VERSION 5.7 ;
  NOWIREEXTENSIONATPIN ON ;
  DIVIDERCHAR "/" ;
  BUSBITCHARS "[]" ;
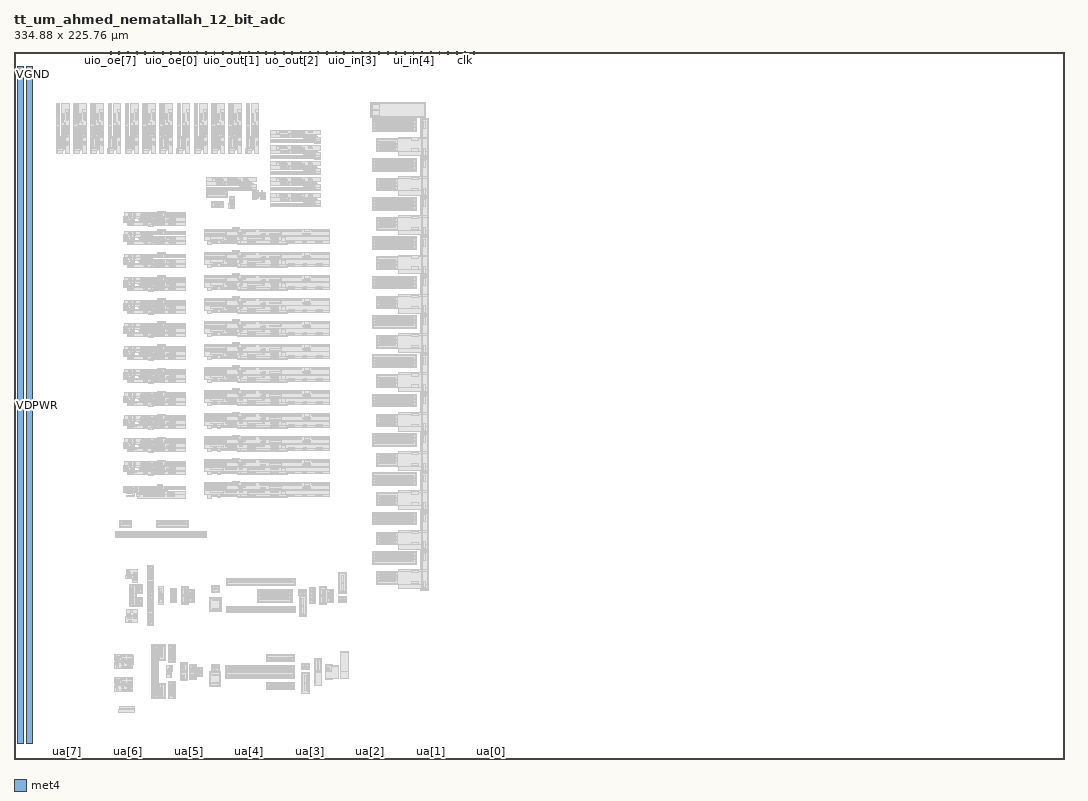
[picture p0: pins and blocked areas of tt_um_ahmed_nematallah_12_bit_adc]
MACRO tt_um_ahmed_nematallah_12_bit_adc
  CLASS BLOCK ;
  FOREIGN tt_um_ahmed_nematallah_12_bit_adc ;
  ORIGIN 0.000 0.000 ;
  SIZE 334.880 BY 225.760 ;
  PIN clk
    DIRECTION INPUT ;
    USE SIGNAL ;
    PORT
      LAYER met4 ;
        RECT 143.830 224.760 144.130 225.760 ;
    END
  END clk
  PIN ena
    DIRECTION INPUT ;
    USE SIGNAL ;
    PORT
      LAYER met4 ;
        RECT 146.590 224.760 146.890 225.760 ;
    END
  END ena
  PIN rst_n
    DIRECTION INPUT ;
    USE SIGNAL ;
    PORT
      LAYER met4 ;
        RECT 141.070 224.760 141.370 225.760 ;
    END
  END rst_n
  PIN ua[0]
    DIRECTION INOUT ;
    USE SIGNAL ;
    ANTENNAGATEAREA 0.450000 ;
    PORT
      LAYER met4 ;
        RECT 151.810 0.000 152.710 1.000 ;
    END
  END ua[0]
  PIN ua[1]
    DIRECTION INOUT ;
    USE SIGNAL ;
    PORT
      LAYER met4 ;
        RECT 132.490 0.000 133.390 1.000 ;
    END
  END ua[1]
  PIN ua[2]
    DIRECTION INOUT ;
    USE SIGNAL ;
    PORT
      LAYER met4 ;
        RECT 113.170 0.000 114.070 1.000 ;
    END
  END ua[2]
  PIN ua[3]
    DIRECTION INOUT ;
    USE SIGNAL ;
    PORT
      LAYER met4 ;
        RECT 93.850 0.000 94.750 1.000 ;
    END
  END ua[3]
  PIN ua[4]
    DIRECTION INOUT ;
    USE SIGNAL ;
    PORT
      LAYER met4 ;
        RECT 74.530 0.000 75.430 1.000 ;
    END
  END ua[4]
  PIN ua[5]
    DIRECTION INOUT ;
    USE SIGNAL ;
    PORT
      LAYER met4 ;
        RECT 55.210 0.000 56.110 1.000 ;
    END
  END ua[5]
  PIN ua[6]
    DIRECTION INOUT ;
    USE SIGNAL ;
    PORT
      LAYER met4 ;
        RECT 35.890 0.000 36.790 1.000 ;
    END
  END ua[6]
  PIN ua[7]
    DIRECTION INOUT ;
    USE SIGNAL ;
    PORT
      LAYER met4 ;
        RECT 16.570 0.000 17.470 1.000 ;
    END
  END ua[7]
  PIN ui_in[0]
    DIRECTION INPUT ;
    USE SIGNAL ;
    PORT
      LAYER met4 ;
        RECT 138.310 224.760 138.610 225.760 ;
    END
  END ui_in[0]
  PIN ui_in[1]
    DIRECTION INPUT ;
    USE SIGNAL ;
    PORT
      LAYER met4 ;
        RECT 135.550 224.760 135.850 225.760 ;
    END
  END ui_in[1]
  PIN ui_in[2]
    DIRECTION INPUT ;
    USE SIGNAL ;
    PORT
      LAYER met4 ;
        RECT 132.790 224.760 133.090 225.760 ;
    END
  END ui_in[2]
  PIN ui_in[3]
    DIRECTION INPUT ;
    USE SIGNAL ;
    PORT
      LAYER met4 ;
        RECT 130.030 224.760 130.330 225.760 ;
    END
  END ui_in[3]
  PIN ui_in[4]
    DIRECTION INPUT ;
    USE SIGNAL ;
    PORT
      LAYER met4 ;
        RECT 127.270 224.760 127.570 225.760 ;
    END
  END ui_in[4]
  PIN ui_in[5]
    DIRECTION INPUT ;
    USE SIGNAL ;
    PORT
      LAYER met4 ;
        RECT 124.510 224.760 124.810 225.760 ;
    END
  END ui_in[5]
  PIN ui_in[6]
    DIRECTION INPUT ;
    USE SIGNAL ;
    PORT
      LAYER met4 ;
        RECT 121.750 224.760 122.050 225.760 ;
    END
  END ui_in[6]
  PIN ui_in[7]
    DIRECTION INPUT ;
    USE SIGNAL ;
    PORT
      LAYER met4 ;
        RECT 118.990 224.760 119.290 225.760 ;
    END
  END ui_in[7]
  PIN uio_in[0]
    DIRECTION INPUT ;
    USE SIGNAL ;
    PORT
      LAYER met4 ;
        RECT 116.230 224.760 116.530 225.760 ;
    END
  END uio_in[0]
  PIN uio_in[1]
    DIRECTION INPUT ;
    USE SIGNAL ;
    PORT
      LAYER met4 ;
        RECT 113.470 224.760 113.770 225.760 ;
    END
  END uio_in[1]
  PIN uio_in[2]
    DIRECTION INPUT ;
    USE SIGNAL ;
    PORT
      LAYER met4 ;
        RECT 110.710 224.760 111.010 225.760 ;
    END
  END uio_in[2]
  PIN uio_in[3]
    DIRECTION INPUT ;
    USE SIGNAL ;
    PORT
      LAYER met4 ;
        RECT 107.950 224.760 108.250 225.760 ;
    END
  END uio_in[3]
  PIN uio_in[4]
    DIRECTION INPUT ;
    USE SIGNAL ;
    PORT
      LAYER met4 ;
        RECT 105.190 224.760 105.490 225.760 ;
    END
  END uio_in[4]
  PIN uio_in[5]
    DIRECTION INPUT ;
    USE SIGNAL ;
    PORT
      LAYER met4 ;
        RECT 102.430 224.760 102.730 225.760 ;
    END
  END uio_in[5]
  PIN uio_in[6]
    DIRECTION INPUT ;
    USE SIGNAL ;
    PORT
      LAYER met4 ;
        RECT 99.670 224.760 99.970 225.760 ;
    END
  END uio_in[6]
  PIN uio_in[7]
    DIRECTION INPUT ;
    USE SIGNAL ;
    PORT
      LAYER met4 ;
        RECT 96.910 224.760 97.210 225.760 ;
    END
  END uio_in[7]
  PIN uio_oe[0]
    DIRECTION OUTPUT ;
    USE SIGNAL ;
    PORT
      LAYER met4 ;
        RECT 49.990 224.760 50.290 225.760 ;
    END
  END uio_oe[0]
  PIN uio_oe[1]
    DIRECTION OUTPUT ;
    USE SIGNAL ;
    PORT
      LAYER met4 ;
        RECT 47.230 224.760 47.530 225.760 ;
    END
  END uio_oe[1]
  PIN uio_oe[2]
    DIRECTION OUTPUT ;
    USE SIGNAL ;
    PORT
      LAYER met4 ;
        RECT 44.470 224.760 44.770 225.760 ;
    END
  END uio_oe[2]
  PIN uio_oe[3]
    DIRECTION OUTPUT ;
    USE SIGNAL ;
    PORT
      LAYER met4 ;
        RECT 41.710 224.760 42.010 225.760 ;
    END
  END uio_oe[3]
  PIN uio_oe[4]
    DIRECTION OUTPUT ;
    USE SIGNAL ;
    PORT
      LAYER met4 ;
        RECT 38.950 224.760 39.250 225.760 ;
    END
  END uio_oe[4]
  PIN uio_oe[5]
    DIRECTION OUTPUT ;
    USE SIGNAL ;
    PORT
      LAYER met4 ;
        RECT 36.190 224.760 36.490 225.760 ;
    END
  END uio_oe[5]
  PIN uio_oe[6]
    DIRECTION OUTPUT ;
    USE SIGNAL ;
    PORT
      LAYER met4 ;
        RECT 33.430 224.760 33.730 225.760 ;
    END
  END uio_oe[6]
  PIN uio_oe[7]
    DIRECTION OUTPUT ;
    USE SIGNAL ;
    PORT
      LAYER met4 ;
        RECT 30.670 224.760 30.970 225.760 ;
    END
  END uio_oe[7]
  PIN uio_out[0]
    DIRECTION OUTPUT ;
    USE SIGNAL ;
    PORT
      LAYER met4 ;
        RECT 72.070 224.760 72.370 225.760 ;
    END
  END uio_out[0]
  PIN uio_out[1]
    DIRECTION OUTPUT ;
    USE SIGNAL ;
    PORT
      LAYER met4 ;
        RECT 69.310 224.760 69.610 225.760 ;
    END
  END uio_out[1]
  PIN uio_out[2]
    DIRECTION OUTPUT ;
    USE SIGNAL ;
    PORT
      LAYER met4 ;
        RECT 66.550 224.760 66.850 225.760 ;
    END
  END uio_out[2]
  PIN uio_out[3]
    DIRECTION OUTPUT ;
    USE SIGNAL ;
    PORT
      LAYER met4 ;
        RECT 63.790 224.760 64.090 225.760 ;
    END
  END uio_out[3]
  PIN uio_out[4]
    DIRECTION OUTPUT ;
    USE SIGNAL ;
    PORT
      LAYER met4 ;
        RECT 61.030 224.760 61.330 225.760 ;
    END
  END uio_out[4]
  PIN uio_out[5]
    DIRECTION OUTPUT ;
    USE SIGNAL ;
    PORT
      LAYER met4 ;
        RECT 58.270 224.760 58.570 225.760 ;
    END
  END uio_out[5]
  PIN uio_out[6]
    DIRECTION OUTPUT ;
    USE SIGNAL ;
    PORT
      LAYER met4 ;
        RECT 55.510 224.760 55.810 225.760 ;
    END
  END uio_out[6]
  PIN uio_out[7]
    DIRECTION OUTPUT ;
    USE SIGNAL ;
    PORT
      LAYER met4 ;
        RECT 52.750 224.760 53.050 225.760 ;
    END
  END uio_out[7]
  PIN uo_out[0]
    DIRECTION OUTPUT ;
    USE SIGNAL ;
    PORT
      LAYER met4 ;
        RECT 94.150 224.760 94.450 225.760 ;
    END
  END uo_out[0]
  PIN uo_out[1]
    DIRECTION OUTPUT ;
    USE SIGNAL ;
    PORT
      LAYER met4 ;
        RECT 91.390 224.760 91.690 225.760 ;
    END
  END uo_out[1]
  PIN uo_out[2]
    DIRECTION OUTPUT ;
    USE SIGNAL ;
    PORT
      LAYER met4 ;
        RECT 88.630 224.760 88.930 225.760 ;
    END
  END uo_out[2]
  PIN uo_out[3]
    DIRECTION OUTPUT ;
    USE SIGNAL ;
    PORT
      LAYER met4 ;
        RECT 85.870 224.760 86.170 225.760 ;
    END
  END uo_out[3]
  PIN uo_out[4]
    DIRECTION OUTPUT ;
    USE SIGNAL ;
    PORT
      LAYER met4 ;
        RECT 83.110 224.760 83.410 225.760 ;
    END
  END uo_out[4]
  PIN uo_out[5]
    DIRECTION OUTPUT ;
    USE SIGNAL ;
    PORT
      LAYER met4 ;
        RECT 80.350 224.760 80.650 225.760 ;
    END
  END uo_out[5]
  PIN uo_out[6]
    DIRECTION OUTPUT ;
    USE SIGNAL ;
    PORT
      LAYER met4 ;
        RECT 77.590 224.760 77.890 225.760 ;
    END
  END uo_out[6]
  PIN uo_out[7]
    DIRECTION OUTPUT ;
    USE SIGNAL ;
    PORT
      LAYER met4 ;
        RECT 74.830 224.760 75.130 225.760 ;
    END
  END uo_out[7]
  PIN VDPWR
    DIRECTION INOUT ;
    USE POWER ;
    PORT
      LAYER met4 ;
        RECT 1.000 5.000 3.000 220.760 ;
    END
  END VDPWR
  PIN VGND
    DIRECTION INOUT ;
    USE GROUND ;
    PORT
      LAYER met4 ;
        RECT 4.000 5.000 6.000 220.760 ;
    END
  END VGND
  OBS
      LAYER nwell ;
        RECT 13.530 198.270 14.620 208.920 ;
      LAYER pwell ;
        RECT 15.140 198.680 17.600 208.920 ;
      LAYER nwell ;
        RECT 13.530 197.980 15.710 198.270 ;
        RECT 13.535 195.160 15.710 197.980 ;
        RECT 13.530 194.830 15.710 195.160 ;
        RECT 13.420 194.090 15.710 194.830 ;
        RECT 13.420 193.010 15.380 194.090 ;
      LAYER pwell ;
        RECT 16.300 193.010 17.600 198.680 ;
      LAYER nwell ;
        RECT 19.030 198.270 20.120 208.920 ;
      LAYER pwell ;
        RECT 20.640 198.680 23.100 208.920 ;
      LAYER nwell ;
        RECT 19.030 197.980 21.210 198.270 ;
        RECT 19.035 195.160 21.210 197.980 ;
        RECT 19.030 194.830 21.210 195.160 ;
        RECT 18.920 194.090 21.210 194.830 ;
        RECT 18.920 193.010 20.880 194.090 ;
      LAYER pwell ;
        RECT 21.800 193.010 23.100 198.680 ;
      LAYER nwell ;
        RECT 24.530 198.270 25.620 208.920 ;
      LAYER pwell ;
        RECT 26.140 198.680 28.600 208.920 ;
      LAYER nwell ;
        RECT 24.530 197.980 26.710 198.270 ;
        RECT 24.535 195.160 26.710 197.980 ;
        RECT 24.530 194.830 26.710 195.160 ;
        RECT 24.420 194.090 26.710 194.830 ;
        RECT 24.420 193.010 26.380 194.090 ;
      LAYER pwell ;
        RECT 27.300 193.010 28.600 198.680 ;
      LAYER nwell ;
        RECT 30.030 198.270 31.120 208.920 ;
      LAYER pwell ;
        RECT 31.640 198.680 34.100 208.920 ;
      LAYER nwell ;
        RECT 30.030 197.980 32.210 198.270 ;
        RECT 30.035 195.160 32.210 197.980 ;
        RECT 30.030 194.830 32.210 195.160 ;
        RECT 29.920 194.090 32.210 194.830 ;
        RECT 29.920 193.010 31.880 194.090 ;
      LAYER pwell ;
        RECT 32.800 193.010 34.100 198.680 ;
      LAYER nwell ;
        RECT 35.530 198.270 36.620 208.920 ;
      LAYER pwell ;
        RECT 37.140 198.680 39.600 208.920 ;
      LAYER nwell ;
        RECT 35.530 197.980 37.710 198.270 ;
        RECT 35.535 195.160 37.710 197.980 ;
        RECT 35.530 194.830 37.710 195.160 ;
        RECT 35.420 194.090 37.710 194.830 ;
        RECT 35.420 193.010 37.380 194.090 ;
      LAYER pwell ;
        RECT 38.300 193.010 39.600 198.680 ;
      LAYER nwell ;
        RECT 41.030 198.270 42.120 208.920 ;
      LAYER pwell ;
        RECT 42.640 198.680 45.100 208.920 ;
      LAYER nwell ;
        RECT 41.030 197.980 43.210 198.270 ;
        RECT 41.035 195.160 43.210 197.980 ;
        RECT 41.030 194.830 43.210 195.160 ;
        RECT 40.920 194.090 43.210 194.830 ;
        RECT 40.920 193.010 42.880 194.090 ;
      LAYER pwell ;
        RECT 43.800 193.010 45.100 198.680 ;
      LAYER nwell ;
        RECT 46.530 198.270 47.620 208.920 ;
      LAYER pwell ;
        RECT 48.140 198.680 50.600 208.920 ;
      LAYER nwell ;
        RECT 46.530 197.980 48.710 198.270 ;
        RECT 46.535 195.160 48.710 197.980 ;
        RECT 46.530 194.830 48.710 195.160 ;
        RECT 46.420 194.090 48.710 194.830 ;
        RECT 46.420 193.010 48.380 194.090 ;
      LAYER pwell ;
        RECT 49.300 193.010 50.600 198.680 ;
      LAYER nwell ;
        RECT 52.030 198.270 53.120 208.920 ;
      LAYER pwell ;
        RECT 53.640 198.680 56.100 208.920 ;
      LAYER nwell ;
        RECT 52.030 197.980 54.210 198.270 ;
        RECT 52.035 195.160 54.210 197.980 ;
        RECT 52.030 194.830 54.210 195.160 ;
        RECT 51.920 194.090 54.210 194.830 ;
        RECT 51.920 193.010 53.880 194.090 ;
      LAYER pwell ;
        RECT 54.800 193.010 56.100 198.680 ;
      LAYER nwell ;
        RECT 57.530 198.270 58.620 208.920 ;
      LAYER pwell ;
        RECT 59.140 198.680 61.600 208.920 ;
      LAYER nwell ;
        RECT 57.530 197.980 59.710 198.270 ;
        RECT 57.535 195.160 59.710 197.980 ;
        RECT 57.530 194.830 59.710 195.160 ;
        RECT 57.420 194.090 59.710 194.830 ;
        RECT 57.420 193.010 59.380 194.090 ;
      LAYER pwell ;
        RECT 60.300 193.010 61.600 198.680 ;
      LAYER nwell ;
        RECT 63.030 198.270 64.120 208.920 ;
      LAYER pwell ;
        RECT 64.640 198.680 67.100 208.920 ;
      LAYER nwell ;
        RECT 63.030 197.980 65.210 198.270 ;
        RECT 63.035 195.160 65.210 197.980 ;
        RECT 63.030 194.830 65.210 195.160 ;
        RECT 62.920 194.090 65.210 194.830 ;
        RECT 62.920 193.010 64.880 194.090 ;
      LAYER pwell ;
        RECT 65.800 193.010 67.100 198.680 ;
      LAYER nwell ;
        RECT 68.530 198.270 69.620 208.920 ;
      LAYER pwell ;
        RECT 70.140 198.680 72.600 208.920 ;
      LAYER nwell ;
        RECT 68.530 197.980 70.710 198.270 ;
        RECT 68.535 195.160 70.710 197.980 ;
        RECT 68.530 194.830 70.710 195.160 ;
        RECT 68.420 194.090 70.710 194.830 ;
        RECT 68.420 193.010 70.380 194.090 ;
      LAYER pwell ;
        RECT 71.300 193.010 72.600 198.680 ;
      LAYER nwell ;
        RECT 74.030 198.270 75.120 208.920 ;
      LAYER pwell ;
        RECT 75.640 198.680 78.100 208.920 ;
        RECT 113.630 204.490 131.270 209.450 ;
      LAYER nwell ;
        RECT 74.030 197.980 76.210 198.270 ;
        RECT 74.035 195.160 76.210 197.980 ;
        RECT 74.030 194.830 76.210 195.160 ;
        RECT 73.920 194.090 76.210 194.830 ;
        RECT 73.920 193.010 75.880 194.090 ;
      LAYER pwell ;
        RECT 76.800 193.010 78.100 198.680 ;
        RECT 81.860 199.280 97.770 200.580 ;
      LAYER nwell ;
        RECT 114.220 200.060 128.410 204.130 ;
      LAYER pwell ;
        RECT 81.860 198.120 92.100 199.280 ;
      LAYER nwell ;
        RECT 92.510 198.360 96.690 198.690 ;
        RECT 92.510 197.600 97.770 198.360 ;
      LAYER pwell ;
        RECT 129.800 198.350 132.150 204.200 ;
        RECT 122.570 197.780 132.150 198.350 ;
      LAYER nwell ;
        RECT 81.860 196.515 97.770 197.600 ;
        RECT 81.860 196.510 92.800 196.515 ;
        RECT 95.620 196.510 97.770 196.515 ;
        RECT 95.950 196.400 97.770 196.510 ;
      LAYER pwell ;
        RECT 81.860 194.210 97.770 195.510 ;
        RECT 81.860 193.050 92.100 194.210 ;
        RECT 115.470 193.710 132.150 197.780 ;
      LAYER nwell ;
        RECT 92.510 193.290 96.690 193.620 ;
        RECT 92.510 192.530 97.770 193.290 ;
        RECT 81.860 191.445 97.770 192.530 ;
      LAYER pwell ;
        RECT 122.570 192.370 132.150 193.710 ;
      LAYER nwell ;
        RECT 81.860 191.440 92.800 191.445 ;
        RECT 95.620 191.440 97.770 191.445 ;
        RECT 95.950 191.330 97.770 191.440 ;
      LAYER pwell ;
        RECT 81.860 189.140 97.770 190.440 ;
        RECT 81.860 187.980 92.100 189.140 ;
      LAYER nwell ;
        RECT 92.510 188.220 96.690 188.550 ;
        RECT 92.510 187.460 97.770 188.220 ;
        RECT 114.220 187.520 128.410 191.590 ;
        RECT 81.860 186.375 97.770 187.460 ;
        RECT 81.860 186.370 92.800 186.375 ;
        RECT 95.620 186.370 97.770 186.375 ;
        RECT 95.950 186.260 97.770 186.370 ;
      LAYER pwell ;
        RECT 129.800 185.810 132.150 192.370 ;
        RECT 61.400 184.070 77.310 185.370 ;
        RECT 81.860 184.070 97.770 185.370 ;
        RECT 122.570 185.240 132.150 185.810 ;
        RECT 61.400 182.910 71.640 184.070 ;
      LAYER nwell ;
        RECT 72.050 183.150 76.230 183.480 ;
        RECT 72.050 182.390 77.310 183.150 ;
      LAYER pwell ;
        RECT 81.860 182.910 92.100 184.070 ;
      LAYER nwell ;
        RECT 92.510 183.150 96.690 183.480 ;
        RECT 92.510 182.390 97.770 183.150 ;
        RECT 61.400 181.305 77.310 182.390 ;
        RECT 61.400 181.300 72.340 181.305 ;
        RECT 75.160 181.300 77.310 181.305 ;
        RECT 81.860 181.305 97.770 182.390 ;
        RECT 81.860 181.300 92.800 181.305 ;
        RECT 95.620 181.300 97.770 181.305 ;
        RECT 61.400 179.190 68.240 181.300 ;
        RECT 75.490 181.190 77.310 181.300 ;
        RECT 95.950 181.190 97.770 181.300 ;
        RECT 76.140 180.100 77.960 181.190 ;
      LAYER pwell ;
        RECT 115.470 181.170 132.150 185.240 ;
        RECT 78.210 180.590 80.180 180.790 ;
        RECT 78.210 180.470 78.540 180.590 ;
        RECT 78.680 180.470 80.180 180.590 ;
        RECT 63.090 175.830 66.880 177.940 ;
        RECT 68.740 177.530 70.310 179.380 ;
      LAYER nwell ;
        RECT 76.140 179.015 77.955 180.100 ;
      LAYER pwell ;
        RECT 78.210 179.260 80.180 180.470 ;
      LAYER nwell ;
        RECT 76.140 178.920 77.950 179.015 ;
        RECT 76.140 178.550 77.320 178.920 ;
      LAYER pwell ;
        RECT 78.730 178.550 80.180 179.260 ;
        RECT 81.860 179.000 97.770 180.300 ;
        RECT 122.570 179.830 132.150 181.170 ;
        RECT 81.860 177.840 92.100 179.000 ;
      LAYER nwell ;
        RECT 92.510 178.080 96.690 178.410 ;
        RECT 92.510 177.320 97.770 178.080 ;
        RECT 68.500 175.540 70.310 177.190 ;
        RECT 81.860 176.235 97.770 177.320 ;
        RECT 81.860 176.230 92.800 176.235 ;
        RECT 95.620 176.230 97.770 176.235 ;
        RECT 95.950 176.120 97.770 176.230 ;
        RECT 114.220 174.980 128.410 179.050 ;
        RECT 45.680 174.200 48.220 174.750 ;
        RECT 35.210 174.195 40.800 174.200 ;
        RECT 43.620 174.195 54.560 174.200 ;
        RECT 35.210 173.170 54.560 174.195 ;
      LAYER pwell ;
        RECT 129.800 173.270 132.150 179.830 ;
      LAYER nwell ;
        RECT 34.790 173.110 54.560 173.170 ;
        RECT 34.790 172.350 43.910 173.110 ;
      LAYER pwell ;
        RECT 122.570 172.700 132.150 173.270 ;
      LAYER nwell ;
        RECT 34.790 172.080 36.600 172.350 ;
      LAYER pwell ;
        RECT 37.000 171.770 38.530 172.100 ;
      LAYER nwell ;
        RECT 39.730 172.020 43.910 172.350 ;
      LAYER pwell ;
        RECT 37.000 171.740 38.210 171.770 ;
        RECT 34.790 171.630 38.210 171.740 ;
        RECT 38.330 171.630 38.530 171.770 ;
        RECT 34.790 171.430 38.530 171.630 ;
        RECT 44.320 171.430 54.560 172.590 ;
        RECT 34.790 171.010 54.560 171.430 ;
        RECT 36.290 170.130 54.560 171.010 ;
        RECT 42.900 169.910 44.380 170.130 ;
      LAYER nwell ;
        RECT 69.700 169.020 72.060 169.460 ;
        RECT 45.680 168.240 48.220 168.790 ;
        RECT 35.210 168.235 40.800 168.240 ;
        RECT 43.620 168.235 54.560 168.240 ;
        RECT 35.210 167.210 54.560 168.235 ;
        RECT 34.790 167.150 54.560 167.210 ;
        RECT 34.790 166.390 43.910 167.150 ;
        RECT 60.640 166.840 100.560 169.020 ;
      LAYER pwell ;
        RECT 115.470 168.630 132.150 172.700 ;
        RECT 122.570 167.290 132.150 168.630 ;
      LAYER nwell ;
        RECT 71.520 166.720 73.330 166.840 ;
        RECT 78.660 166.730 80.470 166.840 ;
        RECT 34.790 166.120 36.600 166.390 ;
      LAYER pwell ;
        RECT 37.000 165.810 38.530 166.140 ;
      LAYER nwell ;
        RECT 39.730 166.060 43.910 166.390 ;
      LAYER pwell ;
        RECT 37.000 165.780 38.210 165.810 ;
        RECT 34.790 165.670 38.210 165.780 ;
        RECT 38.330 165.670 38.530 165.810 ;
        RECT 34.790 165.470 38.530 165.670 ;
        RECT 44.320 165.470 54.560 166.630 ;
        RECT 34.790 165.050 54.560 165.470 ;
        RECT 60.640 165.210 100.560 166.560 ;
        RECT 36.290 164.170 54.560 165.050 ;
        RECT 63.070 164.420 100.560 165.210 ;
        RECT 64.870 164.360 65.990 164.420 ;
        RECT 42.900 163.950 44.380 164.170 ;
      LAYER nwell ;
        RECT 114.220 162.440 128.410 166.510 ;
        RECT 69.700 161.670 72.060 162.110 ;
        RECT 45.680 160.890 48.220 161.440 ;
        RECT 35.210 160.885 40.800 160.890 ;
        RECT 43.620 160.885 54.560 160.890 ;
        RECT 35.210 159.860 54.560 160.885 ;
        RECT 34.790 159.800 54.560 159.860 ;
        RECT 34.790 159.040 43.910 159.800 ;
        RECT 60.640 159.490 100.560 161.670 ;
      LAYER pwell ;
        RECT 129.800 160.730 132.150 167.290 ;
        RECT 122.570 160.160 132.150 160.730 ;
      LAYER nwell ;
        RECT 71.520 159.370 73.330 159.490 ;
        RECT 78.660 159.380 80.470 159.490 ;
        RECT 34.790 158.770 36.600 159.040 ;
      LAYER pwell ;
        RECT 37.000 158.460 38.530 158.790 ;
      LAYER nwell ;
        RECT 39.730 158.710 43.910 159.040 ;
      LAYER pwell ;
        RECT 37.000 158.430 38.210 158.460 ;
        RECT 34.790 158.320 38.210 158.430 ;
        RECT 38.330 158.320 38.530 158.460 ;
        RECT 34.790 158.120 38.530 158.320 ;
        RECT 44.320 158.120 54.560 159.280 ;
        RECT 34.790 157.700 54.560 158.120 ;
        RECT 60.640 157.860 100.560 159.210 ;
        RECT 36.290 156.820 54.560 157.700 ;
        RECT 63.070 157.070 100.560 157.860 ;
        RECT 64.870 157.010 65.990 157.070 ;
        RECT 42.900 156.600 44.380 156.820 ;
        RECT 115.470 156.090 132.150 160.160 ;
      LAYER nwell ;
        RECT 69.700 154.320 72.060 154.760 ;
      LAYER pwell ;
        RECT 122.570 154.750 132.150 156.090 ;
      LAYER nwell ;
        RECT 45.680 153.540 48.220 154.090 ;
        RECT 35.210 153.535 40.800 153.540 ;
        RECT 43.620 153.535 54.560 153.540 ;
        RECT 35.210 152.510 54.560 153.535 ;
        RECT 34.790 152.450 54.560 152.510 ;
        RECT 34.790 151.690 43.910 152.450 ;
        RECT 60.640 152.140 100.560 154.320 ;
        RECT 71.520 152.020 73.330 152.140 ;
        RECT 78.660 152.030 80.470 152.140 ;
        RECT 34.790 151.420 36.600 151.690 ;
      LAYER pwell ;
        RECT 37.000 151.110 38.530 151.440 ;
      LAYER nwell ;
        RECT 39.730 151.360 43.910 151.690 ;
      LAYER pwell ;
        RECT 37.000 151.080 38.210 151.110 ;
        RECT 34.790 150.970 38.210 151.080 ;
        RECT 38.330 150.970 38.530 151.110 ;
        RECT 34.790 150.770 38.530 150.970 ;
        RECT 44.320 150.770 54.560 151.930 ;
        RECT 34.790 150.350 54.560 150.770 ;
        RECT 60.640 150.510 100.560 151.860 ;
        RECT 36.290 149.470 54.560 150.350 ;
        RECT 63.070 149.720 100.560 150.510 ;
      LAYER nwell ;
        RECT 114.220 149.900 128.410 153.970 ;
      LAYER pwell ;
        RECT 64.870 149.660 65.990 149.720 ;
        RECT 42.900 149.250 44.380 149.470 ;
        RECT 129.800 148.190 132.150 154.750 ;
        RECT 122.570 147.620 132.150 148.190 ;
      LAYER nwell ;
        RECT 69.700 146.970 72.060 147.410 ;
        RECT 45.680 146.190 48.220 146.740 ;
        RECT 35.210 146.185 40.800 146.190 ;
        RECT 43.620 146.185 54.560 146.190 ;
        RECT 35.210 145.160 54.560 146.185 ;
        RECT 34.790 145.100 54.560 145.160 ;
        RECT 34.790 144.340 43.910 145.100 ;
        RECT 60.640 144.790 100.560 146.970 ;
        RECT 71.520 144.670 73.330 144.790 ;
        RECT 78.660 144.680 80.470 144.790 ;
        RECT 34.790 144.070 36.600 144.340 ;
      LAYER pwell ;
        RECT 37.000 143.760 38.530 144.090 ;
      LAYER nwell ;
        RECT 39.730 144.010 43.910 144.340 ;
      LAYER pwell ;
        RECT 37.000 143.730 38.210 143.760 ;
        RECT 34.790 143.620 38.210 143.730 ;
        RECT 38.330 143.620 38.530 143.760 ;
        RECT 34.790 143.420 38.530 143.620 ;
        RECT 44.320 143.420 54.560 144.580 ;
        RECT 34.790 143.000 54.560 143.420 ;
        RECT 60.640 143.160 100.560 144.510 ;
        RECT 115.470 143.550 132.150 147.620 ;
        RECT 36.290 142.120 54.560 143.000 ;
        RECT 63.070 142.370 100.560 143.160 ;
        RECT 64.870 142.310 65.990 142.370 ;
        RECT 122.570 142.210 132.150 143.550 ;
        RECT 42.900 141.900 44.380 142.120 ;
      LAYER nwell ;
        RECT 69.700 139.620 72.060 140.060 ;
        RECT 45.680 138.840 48.220 139.390 ;
        RECT 35.210 138.835 40.800 138.840 ;
        RECT 43.620 138.835 54.560 138.840 ;
        RECT 35.210 137.810 54.560 138.835 ;
        RECT 34.790 137.750 54.560 137.810 ;
        RECT 34.790 136.990 43.910 137.750 ;
        RECT 60.640 137.440 100.560 139.620 ;
        RECT 71.520 137.320 73.330 137.440 ;
        RECT 78.660 137.330 80.470 137.440 ;
        RECT 114.220 137.360 128.410 141.430 ;
        RECT 34.790 136.720 36.600 136.990 ;
      LAYER pwell ;
        RECT 37.000 136.410 38.530 136.740 ;
      LAYER nwell ;
        RECT 39.730 136.660 43.910 136.990 ;
      LAYER pwell ;
        RECT 37.000 136.380 38.210 136.410 ;
        RECT 34.790 136.270 38.210 136.380 ;
        RECT 38.330 136.270 38.530 136.410 ;
        RECT 34.790 136.070 38.530 136.270 ;
        RECT 44.320 136.070 54.560 137.230 ;
        RECT 34.790 135.650 54.560 136.070 ;
        RECT 60.640 135.810 100.560 137.160 ;
        RECT 36.290 134.770 54.560 135.650 ;
        RECT 63.070 135.020 100.560 135.810 ;
        RECT 129.800 135.650 132.150 142.210 ;
        RECT 122.570 135.080 132.150 135.650 ;
        RECT 64.870 134.960 65.990 135.020 ;
        RECT 42.900 134.550 44.380 134.770 ;
      LAYER nwell ;
        RECT 69.700 132.270 72.060 132.710 ;
        RECT 45.680 131.490 48.220 132.040 ;
        RECT 35.210 131.485 40.800 131.490 ;
        RECT 43.620 131.485 54.560 131.490 ;
        RECT 35.210 130.460 54.560 131.485 ;
        RECT 34.790 130.400 54.560 130.460 ;
        RECT 34.790 129.640 43.910 130.400 ;
        RECT 60.640 130.090 100.560 132.270 ;
      LAYER pwell ;
        RECT 115.470 131.010 132.150 135.080 ;
      LAYER nwell ;
        RECT 71.520 129.970 73.330 130.090 ;
        RECT 78.660 129.980 80.470 130.090 ;
        RECT 34.790 129.370 36.600 129.640 ;
      LAYER pwell ;
        RECT 37.000 129.060 38.530 129.390 ;
      LAYER nwell ;
        RECT 39.730 129.310 43.910 129.640 ;
      LAYER pwell ;
        RECT 37.000 129.030 38.210 129.060 ;
        RECT 34.790 128.920 38.210 129.030 ;
        RECT 38.330 128.920 38.530 129.060 ;
        RECT 34.790 128.720 38.530 128.920 ;
        RECT 44.320 128.720 54.560 129.880 ;
        RECT 34.790 128.300 54.560 128.720 ;
        RECT 60.640 128.460 100.560 129.810 ;
        RECT 122.570 129.670 132.150 131.010 ;
        RECT 36.290 127.420 54.560 128.300 ;
        RECT 63.070 127.670 100.560 128.460 ;
        RECT 64.870 127.610 65.990 127.670 ;
        RECT 42.900 127.200 44.380 127.420 ;
      LAYER nwell ;
        RECT 69.700 124.920 72.060 125.360 ;
        RECT 45.680 124.140 48.220 124.690 ;
        RECT 35.210 124.135 40.800 124.140 ;
        RECT 43.620 124.135 54.560 124.140 ;
        RECT 35.210 123.110 54.560 124.135 ;
        RECT 34.790 123.050 54.560 123.110 ;
        RECT 34.790 122.290 43.910 123.050 ;
        RECT 60.640 122.740 100.560 124.920 ;
        RECT 114.220 124.820 128.410 128.890 ;
      LAYER pwell ;
        RECT 129.800 123.110 132.150 129.670 ;
      LAYER nwell ;
        RECT 71.520 122.620 73.330 122.740 ;
        RECT 78.660 122.630 80.470 122.740 ;
      LAYER pwell ;
        RECT 122.570 122.540 132.150 123.110 ;
      LAYER nwell ;
        RECT 34.790 122.020 36.600 122.290 ;
      LAYER pwell ;
        RECT 37.000 121.710 38.530 122.040 ;
      LAYER nwell ;
        RECT 39.730 121.960 43.910 122.290 ;
      LAYER pwell ;
        RECT 37.000 121.680 38.210 121.710 ;
        RECT 34.790 121.570 38.210 121.680 ;
        RECT 38.330 121.570 38.530 121.710 ;
        RECT 34.790 121.370 38.530 121.570 ;
        RECT 44.320 121.370 54.560 122.530 ;
        RECT 34.790 120.950 54.560 121.370 ;
        RECT 60.640 121.110 100.560 122.460 ;
        RECT 36.290 120.070 54.560 120.950 ;
        RECT 63.070 120.320 100.560 121.110 ;
        RECT 64.870 120.260 65.990 120.320 ;
        RECT 42.900 119.850 44.380 120.070 ;
        RECT 115.470 118.470 132.150 122.540 ;
      LAYER nwell ;
        RECT 69.700 117.570 72.060 118.010 ;
        RECT 45.680 116.790 48.220 117.340 ;
        RECT 35.210 116.785 40.800 116.790 ;
        RECT 43.620 116.785 54.560 116.790 ;
        RECT 35.210 115.760 54.560 116.785 ;
        RECT 34.790 115.700 54.560 115.760 ;
        RECT 34.790 114.940 43.910 115.700 ;
        RECT 60.640 115.390 100.560 117.570 ;
      LAYER pwell ;
        RECT 122.570 117.130 132.150 118.470 ;
      LAYER nwell ;
        RECT 71.520 115.270 73.330 115.390 ;
        RECT 78.660 115.280 80.470 115.390 ;
        RECT 34.790 114.670 36.600 114.940 ;
      LAYER pwell ;
        RECT 37.000 114.360 38.530 114.690 ;
      LAYER nwell ;
        RECT 39.730 114.610 43.910 114.940 ;
      LAYER pwell ;
        RECT 37.000 114.330 38.210 114.360 ;
        RECT 34.790 114.220 38.210 114.330 ;
        RECT 38.330 114.220 38.530 114.360 ;
        RECT 34.790 114.020 38.530 114.220 ;
        RECT 44.320 114.020 54.560 115.180 ;
        RECT 34.790 113.600 54.560 114.020 ;
        RECT 60.640 113.760 100.560 115.110 ;
        RECT 36.290 112.720 54.560 113.600 ;
        RECT 63.070 112.970 100.560 113.760 ;
        RECT 64.870 112.910 65.990 112.970 ;
        RECT 42.900 112.500 44.380 112.720 ;
      LAYER nwell ;
        RECT 114.220 112.280 128.410 116.350 ;
        RECT 69.700 110.220 72.060 110.660 ;
      LAYER pwell ;
        RECT 129.800 110.570 132.150 117.130 ;
      LAYER nwell ;
        RECT 45.680 109.440 48.220 109.990 ;
        RECT 35.210 109.435 40.800 109.440 ;
        RECT 43.620 109.435 54.560 109.440 ;
        RECT 35.210 108.410 54.560 109.435 ;
        RECT 34.790 108.350 54.560 108.410 ;
        RECT 34.790 107.590 43.910 108.350 ;
        RECT 60.640 108.040 100.560 110.220 ;
      LAYER pwell ;
        RECT 122.570 110.000 132.150 110.570 ;
      LAYER nwell ;
        RECT 71.520 107.920 73.330 108.040 ;
        RECT 78.660 107.930 80.470 108.040 ;
        RECT 34.790 107.320 36.600 107.590 ;
      LAYER pwell ;
        RECT 37.000 107.010 38.530 107.340 ;
      LAYER nwell ;
        RECT 39.730 107.260 43.910 107.590 ;
      LAYER pwell ;
        RECT 37.000 106.980 38.210 107.010 ;
        RECT 34.790 106.870 38.210 106.980 ;
        RECT 38.330 106.870 38.530 107.010 ;
        RECT 34.790 106.670 38.530 106.870 ;
        RECT 44.320 106.670 54.560 107.830 ;
        RECT 34.790 106.250 54.560 106.670 ;
        RECT 60.640 106.410 100.560 107.760 ;
        RECT 36.290 105.370 54.560 106.250 ;
        RECT 63.070 105.620 100.560 106.410 ;
        RECT 115.470 105.930 132.150 110.000 ;
        RECT 64.870 105.560 65.990 105.620 ;
        RECT 42.900 105.150 44.380 105.370 ;
        RECT 122.570 104.590 132.150 105.930 ;
      LAYER nwell ;
        RECT 69.700 102.870 72.060 103.310 ;
        RECT 45.680 102.090 48.220 102.640 ;
        RECT 35.210 102.085 40.800 102.090 ;
        RECT 43.620 102.085 54.560 102.090 ;
        RECT 35.210 101.060 54.560 102.085 ;
        RECT 34.790 101.000 54.560 101.060 ;
        RECT 34.790 100.240 43.910 101.000 ;
        RECT 60.640 100.690 100.560 102.870 ;
        RECT 71.520 100.570 73.330 100.690 ;
        RECT 78.660 100.580 80.470 100.690 ;
        RECT 34.790 99.970 36.600 100.240 ;
      LAYER pwell ;
        RECT 37.000 99.660 38.530 99.990 ;
      LAYER nwell ;
        RECT 39.730 99.910 43.910 100.240 ;
      LAYER pwell ;
        RECT 37.000 99.630 38.210 99.660 ;
        RECT 34.790 99.520 38.210 99.630 ;
        RECT 38.330 99.520 38.530 99.660 ;
        RECT 34.790 99.320 38.530 99.520 ;
        RECT 44.320 99.320 54.560 100.480 ;
        RECT 34.790 98.900 54.560 99.320 ;
        RECT 60.640 99.060 100.560 100.410 ;
      LAYER nwell ;
        RECT 114.220 99.740 128.410 103.810 ;
      LAYER pwell ;
        RECT 36.290 98.020 54.560 98.900 ;
        RECT 63.070 98.270 100.560 99.060 ;
        RECT 64.870 98.210 65.990 98.270 ;
        RECT 129.800 98.030 132.150 104.590 ;
        RECT 42.900 97.800 44.380 98.020 ;
        RECT 122.570 97.460 132.150 98.030 ;
      LAYER nwell ;
        RECT 69.700 95.520 72.060 95.960 ;
        RECT 45.680 94.740 48.220 95.290 ;
        RECT 35.210 94.735 40.800 94.740 ;
        RECT 43.620 94.735 54.560 94.740 ;
        RECT 35.210 93.710 54.560 94.735 ;
        RECT 34.790 93.650 54.560 93.710 ;
        RECT 34.790 92.890 43.910 93.650 ;
        RECT 60.640 93.340 100.560 95.520 ;
      LAYER pwell ;
        RECT 115.470 93.390 132.150 97.460 ;
      LAYER nwell ;
        RECT 71.520 93.220 73.330 93.340 ;
        RECT 78.660 93.230 80.470 93.340 ;
        RECT 34.790 92.620 36.600 92.890 ;
      LAYER pwell ;
        RECT 37.000 92.310 38.530 92.640 ;
      LAYER nwell ;
        RECT 39.730 92.560 43.910 92.890 ;
      LAYER pwell ;
        RECT 37.000 92.280 38.210 92.310 ;
        RECT 34.790 92.170 38.210 92.280 ;
        RECT 38.330 92.170 38.530 92.310 ;
        RECT 34.790 91.970 38.530 92.170 ;
        RECT 44.320 91.970 54.560 93.130 ;
        RECT 34.790 91.550 54.560 91.970 ;
        RECT 60.640 91.710 100.560 93.060 ;
        RECT 122.570 92.050 132.150 93.390 ;
        RECT 36.290 90.670 54.560 91.550 ;
        RECT 63.070 90.920 100.560 91.710 ;
        RECT 64.870 90.860 65.990 90.920 ;
        RECT 42.900 90.450 44.380 90.670 ;
      LAYER nwell ;
        RECT 69.695 88.165 72.055 88.605 ;
        RECT 45.780 86.940 47.520 87.420 ;
        RECT 39.320 86.790 54.560 86.940 ;
      LAYER pwell ;
        RECT 34.910 84.950 36.590 86.790 ;
      LAYER nwell ;
        RECT 36.910 85.850 54.560 86.790 ;
        RECT 60.635 85.985 100.555 88.165 ;
        RECT 114.220 87.200 128.410 91.270 ;
        RECT 71.515 85.865 73.325 85.985 ;
        RECT 78.655 85.875 80.465 85.985 ;
        RECT 36.910 84.980 43.895 85.850 ;
        RECT 39.320 84.765 43.895 84.980 ;
        RECT 39.320 84.760 40.750 84.765 ;
      LAYER pwell ;
        RECT 44.450 84.390 54.560 85.360 ;
        RECT 39.980 84.300 54.560 84.390 ;
        RECT 60.635 84.355 100.555 85.705 ;
        RECT 129.800 85.490 132.150 92.050 ;
        RECT 122.570 84.920 132.150 85.490 ;
        RECT 39.310 83.220 54.560 84.300 ;
        RECT 63.065 83.565 100.555 84.355 ;
        RECT 64.865 83.505 65.985 83.565 ;
        RECT 115.470 80.850 132.150 84.920 ;
        RECT 122.570 79.510 132.150 80.850 ;
        RECT 33.640 73.910 37.430 76.020 ;
        RECT 45.510 73.920 55.610 76.030 ;
      LAYER nwell ;
        RECT 114.220 74.660 128.410 78.730 ;
      LAYER pwell ;
        RECT 129.800 72.950 132.150 79.510 ;
      LAYER nwell ;
        RECT 32.280 70.550 61.310 72.660 ;
      LAYER pwell ;
        RECT 122.570 72.380 132.150 72.950 ;
        RECT 115.470 68.310 132.150 72.380 ;
        RECT 122.570 66.970 132.150 68.310 ;
      LAYER nwell ;
        RECT 114.220 62.120 128.410 66.190 ;
      LAYER pwell ;
        RECT 35.880 58.840 39.400 60.440 ;
      LAYER nwell ;
        RECT 35.640 57.410 39.400 58.500 ;
        RECT 37.790 56.420 39.400 57.410 ;
      LAYER pwell ;
        RECT 36.840 52.870 41.060 55.660 ;
        RECT 36.840 51.350 38.950 52.870 ;
        RECT 36.840 48.560 41.060 51.350 ;
        RECT 35.880 45.860 39.400 47.530 ;
      LAYER nwell ;
        RECT 35.640 43.450 39.400 45.520 ;
        RECT 42.430 42.430 44.540 61.790 ;
      LAYER pwell ;
        RECT 129.800 60.410 132.150 66.970 ;
        RECT 122.570 59.840 132.150 60.410 ;
      LAYER nwell ;
        RECT 67.660 55.460 89.850 57.570 ;
        RECT 45.950 52.210 47.760 54.900 ;
      LAYER pwell ;
        RECT 46.190 49.140 47.760 51.870 ;
        RECT 49.810 49.820 51.920 54.400 ;
      LAYER nwell ;
        RECT 53.500 54.200 55.610 54.940 ;
        RECT 53.500 50.010 57.720 54.200 ;
      LAYER pwell ;
        RECT 62.930 53.220 65.530 55.330 ;
      LAYER nwell ;
        RECT 53.500 49.260 55.610 50.010 ;
        RECT 62.460 46.930 66.040 51.640 ;
      LAYER pwell ;
        RECT 77.590 49.990 88.690 54.210 ;
        RECT 90.810 52.100 93.360 54.210 ;
      LAYER nwell ;
        RECT 67.660 46.630 89.850 48.740 ;
      LAYER pwell ;
        RECT 90.910 45.590 93.260 52.100 ;
        RECT 94.190 49.500 96.300 54.700 ;
      LAYER nwell ;
        RECT 97.540 54.200 99.650 54.950 ;
        RECT 97.540 50.010 101.760 54.200 ;
      LAYER pwell ;
        RECT 103.620 52.930 105.970 59.440 ;
        RECT 115.470 55.770 132.150 59.840 ;
        RECT 122.570 54.430 132.150 55.770 ;
        RECT 129.800 53.720 132.150 54.430 ;
      LAYER nwell ;
        RECT 97.540 49.270 99.650 50.010 ;
        RECT 103.450 49.790 106.140 51.900 ;
        RECT 32.210 31.280 37.690 33.460 ;
        RECT 44.000 31.540 48.220 36.380 ;
      LAYER pwell ;
        RECT 32.210 28.720 37.700 30.920 ;
      LAYER nwell ;
        RECT 32.180 23.930 37.660 26.110 ;
        RECT 44.000 24.030 46.110 31.540 ;
      LAYER pwell ;
        RECT 49.260 30.800 51.370 36.380 ;
        RECT 80.450 31.140 89.550 33.250 ;
      LAYER nwell ;
        RECT 48.730 27.890 50.540 29.770 ;
      LAYER pwell ;
        RECT 48.730 26.040 50.300 27.550 ;
      LAYER nwell ;
        RECT 53.120 24.940 55.230 30.620 ;
      LAYER pwell ;
        RECT 55.940 29.330 58.050 30.070 ;
        RECT 55.940 26.230 60.160 29.330 ;
      LAYER nwell ;
        RECT 62.840 27.900 65.480 30.010 ;
      LAYER pwell ;
        RECT 55.940 25.490 58.050 26.230 ;
        RECT 32.180 21.370 37.670 23.570 ;
      LAYER nwell ;
        RECT 44.000 19.190 48.220 24.030 ;
      LAYER pwell ;
        RECT 49.260 19.190 51.370 24.770 ;
      LAYER nwell ;
        RECT 62.370 23.190 65.950 27.900 ;
        RECT 67.360 25.670 89.550 29.890 ;
        RECT 91.610 28.390 94.250 30.500 ;
      LAYER pwell ;
        RECT 80.450 22.310 89.550 24.420 ;
        RECT 91.760 21.030 94.110 27.540 ;
      LAYER nwell ;
        RECT 95.900 23.590 98.010 31.970 ;
      LAYER pwell ;
        RECT 99.350 29.830 101.460 30.070 ;
        RECT 99.350 25.730 103.570 29.830 ;
        RECT 104.210 27.770 106.560 34.280 ;
        RECT 99.350 25.490 101.460 25.730 ;
        RECT 104.110 25.660 106.660 27.770 ;
        RECT 33.720 16.140 38.560 16.870 ;
      LAYER nwell ;
        RECT 33.480 14.710 38.560 15.800 ;
      LAYER li1 ;
        RECT 113.810 209.100 131.090 209.270 ;
        RECT 13.770 202.590 13.940 208.630 ;
        RECT 14.210 202.590 14.380 208.630 ;
        RECT 16.400 206.150 17.500 207.130 ;
        RECT 15.400 203.820 15.570 205.860 ;
        RECT 15.840 203.820 16.010 205.860 ;
        RECT 16.710 203.820 16.880 205.860 ;
        RECT 17.150 203.820 17.320 205.860 ;
        RECT 15.540 203.120 15.870 203.650 ;
        RECT 16.850 203.480 17.180 203.650 ;
        RECT 15.540 202.870 16.470 203.120 ;
        RECT 13.910 202.205 14.240 202.375 ;
        RECT 13.770 198.760 13.940 201.800 ;
        RECT 14.210 198.760 14.380 201.800 ;
        RECT 15.400 199.160 15.570 202.200 ;
        RECT 15.840 199.160 16.010 202.200 ;
        RECT 15.540 198.820 15.870 198.990 ;
        RECT 16.230 198.550 16.470 202.870 ;
        RECT 19.270 202.590 19.440 208.630 ;
        RECT 19.710 202.590 19.880 208.630 ;
        RECT 21.900 206.150 23.000 207.130 ;
        RECT 20.900 203.820 21.070 205.860 ;
        RECT 21.340 203.820 21.510 205.860 ;
        RECT 22.210 203.820 22.380 205.860 ;
        RECT 22.650 203.820 22.820 205.860 ;
        RECT 21.040 203.120 21.370 203.650 ;
        RECT 22.350 203.480 22.680 203.650 ;
        RECT 21.040 202.870 21.970 203.120 ;
        RECT 19.410 202.205 19.740 202.375 ;
        RECT 16.710 199.160 16.880 202.200 ;
        RECT 17.150 199.160 17.320 202.200 ;
        RECT 16.850 198.550 17.180 198.990 ;
        RECT 19.270 198.760 19.440 201.800 ;
        RECT 19.710 198.760 19.880 201.800 ;
        RECT 20.900 199.160 21.070 202.200 ;
        RECT 21.340 199.160 21.510 202.200 ;
        RECT 21.040 198.820 21.370 198.990 ;
        RECT 21.730 198.550 21.970 202.870 ;
        RECT 24.770 202.590 24.940 208.630 ;
        RECT 25.210 202.590 25.380 208.630 ;
        RECT 27.400 206.150 28.500 207.130 ;
        RECT 26.400 203.820 26.570 205.860 ;
        RECT 26.840 203.820 27.010 205.860 ;
        RECT 27.710 203.820 27.880 205.860 ;
        RECT 28.150 203.820 28.320 205.860 ;
        RECT 26.540 203.120 26.870 203.650 ;
        RECT 27.850 203.480 28.180 203.650 ;
        RECT 26.540 202.870 27.470 203.120 ;
        RECT 24.910 202.205 25.240 202.375 ;
        RECT 22.210 199.160 22.380 202.200 ;
        RECT 22.650 199.160 22.820 202.200 ;
        RECT 22.350 198.550 22.680 198.990 ;
        RECT 24.770 198.760 24.940 201.800 ;
        RECT 25.210 198.760 25.380 201.800 ;
        RECT 26.400 199.160 26.570 202.200 ;
        RECT 26.840 199.160 27.010 202.200 ;
        RECT 26.540 198.820 26.870 198.990 ;
        RECT 27.230 198.550 27.470 202.870 ;
        RECT 30.270 202.590 30.440 208.630 ;
        RECT 30.710 202.590 30.880 208.630 ;
        RECT 32.900 206.150 34.000 207.130 ;
        RECT 31.900 203.820 32.070 205.860 ;
        RECT 32.340 203.820 32.510 205.860 ;
        RECT 33.210 203.820 33.380 205.860 ;
        RECT 33.650 203.820 33.820 205.860 ;
        RECT 32.040 203.120 32.370 203.650 ;
        RECT 33.350 203.480 33.680 203.650 ;
        RECT 32.040 202.870 32.970 203.120 ;
        RECT 30.410 202.205 30.740 202.375 ;
        RECT 27.710 199.160 27.880 202.200 ;
        RECT 28.150 199.160 28.320 202.200 ;
        RECT 27.850 198.550 28.180 198.990 ;
        RECT 30.270 198.760 30.440 201.800 ;
        RECT 30.710 198.760 30.880 201.800 ;
        RECT 31.900 199.160 32.070 202.200 ;
        RECT 32.340 199.160 32.510 202.200 ;
        RECT 32.040 198.820 32.370 198.990 ;
        RECT 32.730 198.550 32.970 202.870 ;
        RECT 35.770 202.590 35.940 208.630 ;
        RECT 36.210 202.590 36.380 208.630 ;
        RECT 38.400 206.150 39.500 207.130 ;
        RECT 37.400 203.820 37.570 205.860 ;
        RECT 37.840 203.820 38.010 205.860 ;
        RECT 38.710 203.820 38.880 205.860 ;
        RECT 39.150 203.820 39.320 205.860 ;
        RECT 37.540 203.120 37.870 203.650 ;
        RECT 38.850 203.480 39.180 203.650 ;
        RECT 37.540 202.870 38.470 203.120 ;
        RECT 35.910 202.205 36.240 202.375 ;
        RECT 33.210 199.160 33.380 202.200 ;
        RECT 33.650 199.160 33.820 202.200 ;
        RECT 33.350 198.550 33.680 198.990 ;
        RECT 35.770 198.760 35.940 201.800 ;
        RECT 36.210 198.760 36.380 201.800 ;
        RECT 37.400 199.160 37.570 202.200 ;
        RECT 37.840 199.160 38.010 202.200 ;
        RECT 37.540 198.820 37.870 198.990 ;
        RECT 38.230 198.550 38.470 202.870 ;
        RECT 41.270 202.590 41.440 208.630 ;
        RECT 41.710 202.590 41.880 208.630 ;
        RECT 43.900 206.150 45.000 207.130 ;
        RECT 42.900 203.820 43.070 205.860 ;
        RECT 43.340 203.820 43.510 205.860 ;
        RECT 44.210 203.820 44.380 205.860 ;
        RECT 44.650 203.820 44.820 205.860 ;
        RECT 43.040 203.120 43.370 203.650 ;
        RECT 44.350 203.480 44.680 203.650 ;
        RECT 43.040 202.870 43.970 203.120 ;
        RECT 41.410 202.205 41.740 202.375 ;
        RECT 38.710 199.160 38.880 202.200 ;
        RECT 39.150 199.160 39.320 202.200 ;
        RECT 38.850 198.550 39.180 198.990 ;
        RECT 41.270 198.760 41.440 201.800 ;
        RECT 41.710 198.760 41.880 201.800 ;
        RECT 42.900 199.160 43.070 202.200 ;
        RECT 43.340 199.160 43.510 202.200 ;
        RECT 43.040 198.820 43.370 198.990 ;
        RECT 43.730 198.550 43.970 202.870 ;
        RECT 46.770 202.590 46.940 208.630 ;
        RECT 47.210 202.590 47.380 208.630 ;
        RECT 49.400 206.150 50.500 207.130 ;
        RECT 48.400 203.820 48.570 205.860 ;
        RECT 48.840 203.820 49.010 205.860 ;
        RECT 49.710 203.820 49.880 205.860 ;
        RECT 50.150 203.820 50.320 205.860 ;
        RECT 48.540 203.120 48.870 203.650 ;
        RECT 49.850 203.480 50.180 203.650 ;
        RECT 48.540 202.870 49.470 203.120 ;
        RECT 46.910 202.205 47.240 202.375 ;
        RECT 44.210 199.160 44.380 202.200 ;
        RECT 44.650 199.160 44.820 202.200 ;
        RECT 44.350 198.550 44.680 198.990 ;
        RECT 46.770 198.760 46.940 201.800 ;
        RECT 47.210 198.760 47.380 201.800 ;
        RECT 48.400 199.160 48.570 202.200 ;
        RECT 48.840 199.160 49.010 202.200 ;
        RECT 48.540 198.820 48.870 198.990 ;
        RECT 49.230 198.550 49.470 202.870 ;
        RECT 52.270 202.590 52.440 208.630 ;
        RECT 52.710 202.590 52.880 208.630 ;
        RECT 54.900 206.150 56.000 207.130 ;
        RECT 53.900 203.820 54.070 205.860 ;
        RECT 54.340 203.820 54.510 205.860 ;
        RECT 55.210 203.820 55.380 205.860 ;
        RECT 55.650 203.820 55.820 205.860 ;
        RECT 54.040 203.120 54.370 203.650 ;
        RECT 55.350 203.480 55.680 203.650 ;
        RECT 54.040 202.870 54.970 203.120 ;
        RECT 52.410 202.205 52.740 202.375 ;
        RECT 49.710 199.160 49.880 202.200 ;
        RECT 50.150 199.160 50.320 202.200 ;
        RECT 49.850 198.550 50.180 198.990 ;
        RECT 52.270 198.760 52.440 201.800 ;
        RECT 52.710 198.760 52.880 201.800 ;
        RECT 53.900 199.160 54.070 202.200 ;
        RECT 54.340 199.160 54.510 202.200 ;
        RECT 54.040 198.820 54.370 198.990 ;
        RECT 54.730 198.550 54.970 202.870 ;
        RECT 57.770 202.590 57.940 208.630 ;
        RECT 58.210 202.590 58.380 208.630 ;
        RECT 60.400 206.150 61.500 207.130 ;
        RECT 59.400 203.820 59.570 205.860 ;
        RECT 59.840 203.820 60.010 205.860 ;
        RECT 60.710 203.820 60.880 205.860 ;
        RECT 61.150 203.820 61.320 205.860 ;
        RECT 59.540 203.120 59.870 203.650 ;
        RECT 60.850 203.480 61.180 203.650 ;
        RECT 59.540 202.870 60.470 203.120 ;
        RECT 57.910 202.205 58.240 202.375 ;
        RECT 55.210 199.160 55.380 202.200 ;
        RECT 55.650 199.160 55.820 202.200 ;
        RECT 55.350 198.550 55.680 198.990 ;
        RECT 57.770 198.760 57.940 201.800 ;
        RECT 58.210 198.760 58.380 201.800 ;
        RECT 59.400 199.160 59.570 202.200 ;
        RECT 59.840 199.160 60.010 202.200 ;
        RECT 59.540 198.820 59.870 198.990 ;
        RECT 60.230 198.550 60.470 202.870 ;
        RECT 63.270 202.590 63.440 208.630 ;
        RECT 63.710 202.590 63.880 208.630 ;
        RECT 65.900 206.150 67.000 207.130 ;
        RECT 64.900 203.820 65.070 205.860 ;
        RECT 65.340 203.820 65.510 205.860 ;
        RECT 66.210 203.820 66.380 205.860 ;
        RECT 66.650 203.820 66.820 205.860 ;
        RECT 65.040 203.120 65.370 203.650 ;
        RECT 66.350 203.480 66.680 203.650 ;
        RECT 65.040 202.870 65.970 203.120 ;
        RECT 63.410 202.205 63.740 202.375 ;
        RECT 60.710 199.160 60.880 202.200 ;
        RECT 61.150 199.160 61.320 202.200 ;
        RECT 60.850 198.550 61.180 198.990 ;
        RECT 63.270 198.760 63.440 201.800 ;
        RECT 63.710 198.760 63.880 201.800 ;
        RECT 64.900 199.160 65.070 202.200 ;
        RECT 65.340 199.160 65.510 202.200 ;
        RECT 65.040 198.820 65.370 198.990 ;
        RECT 65.730 198.550 65.970 202.870 ;
        RECT 68.770 202.590 68.940 208.630 ;
        RECT 69.210 202.590 69.380 208.630 ;
        RECT 71.400 206.150 72.500 207.130 ;
        RECT 70.400 203.820 70.570 205.860 ;
        RECT 70.840 203.820 71.010 205.860 ;
        RECT 71.710 203.820 71.880 205.860 ;
        RECT 72.150 203.820 72.320 205.860 ;
        RECT 70.540 203.120 70.870 203.650 ;
        RECT 71.850 203.480 72.180 203.650 ;
        RECT 70.540 202.870 71.470 203.120 ;
        RECT 68.910 202.205 69.240 202.375 ;
        RECT 66.210 199.160 66.380 202.200 ;
        RECT 66.650 199.160 66.820 202.200 ;
        RECT 66.350 198.550 66.680 198.990 ;
        RECT 68.770 198.760 68.940 201.800 ;
        RECT 69.210 198.760 69.380 201.800 ;
        RECT 70.400 199.160 70.570 202.200 ;
        RECT 70.840 199.160 71.010 202.200 ;
        RECT 70.540 198.820 70.870 198.990 ;
        RECT 71.230 198.550 71.470 202.870 ;
        RECT 74.270 202.590 74.440 208.630 ;
        RECT 74.710 202.590 74.880 208.630 ;
        RECT 76.900 206.150 78.000 207.130 ;
        RECT 113.810 206.830 113.980 209.100 ;
        RECT 114.460 207.210 116.620 208.620 ;
        RECT 75.900 203.820 76.070 205.860 ;
        RECT 76.340 203.820 76.510 205.860 ;
        RECT 77.210 203.820 77.380 205.860 ;
        RECT 77.650 203.820 77.820 205.860 ;
        RECT 113.810 205.230 113.990 206.830 ;
        RECT 114.460 205.320 116.620 206.730 ;
        RECT 113.810 204.840 113.980 205.230 ;
        RECT 130.920 204.840 131.090 209.100 ;
        RECT 113.810 204.670 131.090 204.840 ;
        RECT 114.400 203.780 128.230 203.950 ;
        RECT 76.040 203.120 76.370 203.650 ;
        RECT 77.350 203.480 77.680 203.650 ;
        RECT 76.040 202.870 76.970 203.120 ;
        RECT 74.410 202.205 74.740 202.375 ;
        RECT 71.710 199.160 71.880 202.200 ;
        RECT 72.150 199.160 72.320 202.200 ;
        RECT 71.850 198.550 72.180 198.990 ;
        RECT 74.270 198.760 74.440 201.800 ;
        RECT 74.710 198.760 74.880 201.800 ;
        RECT 75.900 199.160 76.070 202.200 ;
        RECT 76.340 199.160 76.510 202.200 ;
        RECT 76.040 198.820 76.370 198.990 ;
        RECT 76.730 198.550 76.970 202.870 ;
        RECT 77.210 199.160 77.380 202.200 ;
        RECT 77.650 199.160 77.820 202.200 ;
        RECT 83.650 199.380 84.630 200.480 ;
        RECT 114.400 200.410 114.570 203.780 ;
        RECT 114.910 202.890 115.080 203.220 ;
        RECT 115.295 203.210 127.335 203.380 ;
        RECT 115.400 202.900 121.350 202.910 ;
        RECT 115.295 202.730 127.335 202.900 ;
        RECT 114.910 201.930 115.080 202.260 ;
        RECT 115.295 202.250 127.335 202.420 ;
        RECT 127.550 202.410 127.720 202.740 ;
        RECT 115.295 201.770 127.335 201.940 ;
        RECT 114.910 200.970 115.080 201.300 ;
        RECT 115.295 201.290 127.335 201.460 ;
        RECT 127.550 201.450 127.720 201.780 ;
        RECT 115.295 200.810 127.335 200.980 ;
        RECT 128.060 200.410 128.230 203.780 ;
        RECT 84.920 200.130 86.960 200.300 ;
        RECT 84.920 199.690 86.960 199.860 ;
        RECT 87.130 199.830 87.300 200.160 ;
        RECT 88.580 200.130 91.620 200.300 ;
        RECT 88.580 199.690 91.620 199.860 ;
        RECT 91.790 199.830 92.540 200.160 ;
        RECT 93.770 200.130 94.810 200.300 ;
        RECT 114.400 200.240 128.230 200.410 ;
        RECT 129.980 203.850 131.970 204.020 ;
        RECT 92.230 199.450 92.540 199.830 ;
        RECT 93.770 199.690 94.810 199.860 ;
        RECT 94.980 199.830 95.150 200.160 ;
        RECT 87.660 199.300 92.540 199.450 ;
        RECT 87.660 199.210 96.360 199.300 ;
        RECT 77.350 198.550 77.680 198.990 ;
        RECT 84.920 198.820 86.960 198.990 ;
        RECT 87.660 198.850 87.910 199.210 ;
        RECT 92.230 198.990 96.360 199.210 ;
        RECT 13.910 198.240 17.180 198.550 ;
        RECT 19.410 198.240 22.680 198.550 ;
        RECT 24.910 198.240 28.180 198.550 ;
        RECT 30.410 198.240 33.680 198.550 ;
        RECT 35.910 198.240 39.180 198.550 ;
        RECT 41.410 198.240 44.680 198.550 ;
        RECT 46.910 198.240 50.180 198.550 ;
        RECT 52.410 198.240 55.680 198.550 ;
        RECT 57.910 198.240 61.180 198.550 ;
        RECT 63.410 198.240 66.680 198.550 ;
        RECT 68.910 198.240 72.180 198.550 ;
        RECT 74.410 198.240 77.680 198.550 ;
        RECT 84.920 198.380 86.960 198.550 ;
        RECT 87.130 198.520 87.910 198.850 ;
        RECT 88.580 198.820 91.620 198.990 ;
        RECT 88.580 198.380 91.620 198.550 ;
        RECT 91.790 198.520 91.960 198.850 ;
        RECT 13.775 194.935 13.945 197.975 ;
        RECT 14.215 194.935 14.385 197.975 ;
        RECT 14.860 194.940 15.030 197.980 ;
        RECT 15.300 194.940 15.470 197.980 ;
        RECT 16.010 194.820 16.320 198.240 ;
        RECT 16.710 195.970 16.880 197.010 ;
        RECT 17.150 195.970 17.320 197.010 ;
        RECT 16.850 195.630 17.180 195.800 ;
        RECT 19.275 194.935 19.445 197.975 ;
        RECT 19.715 194.935 19.885 197.975 ;
        RECT 20.360 194.940 20.530 197.980 ;
        RECT 20.800 194.940 20.970 197.980 ;
        RECT 21.510 194.820 21.820 198.240 ;
        RECT 22.210 195.970 22.380 197.010 ;
        RECT 22.650 195.970 22.820 197.010 ;
        RECT 22.350 195.630 22.680 195.800 ;
        RECT 24.775 194.935 24.945 197.975 ;
        RECT 25.215 194.935 25.385 197.975 ;
        RECT 25.860 194.940 26.030 197.980 ;
        RECT 26.300 194.940 26.470 197.980 ;
        RECT 27.010 194.820 27.320 198.240 ;
        RECT 27.710 195.970 27.880 197.010 ;
        RECT 28.150 195.970 28.320 197.010 ;
        RECT 27.850 195.630 28.180 195.800 ;
        RECT 30.275 194.935 30.445 197.975 ;
        RECT 30.715 194.935 30.885 197.975 ;
        RECT 31.360 194.940 31.530 197.980 ;
        RECT 31.800 194.940 31.970 197.980 ;
        RECT 32.510 194.820 32.820 198.240 ;
        RECT 33.210 195.970 33.380 197.010 ;
        RECT 33.650 195.970 33.820 197.010 ;
        RECT 33.350 195.630 33.680 195.800 ;
        RECT 35.775 194.935 35.945 197.975 ;
        RECT 36.215 194.935 36.385 197.975 ;
        RECT 36.860 194.940 37.030 197.980 ;
        RECT 37.300 194.940 37.470 197.980 ;
        RECT 38.010 194.820 38.320 198.240 ;
        RECT 38.710 195.970 38.880 197.010 ;
        RECT 39.150 195.970 39.320 197.010 ;
        RECT 38.850 195.630 39.180 195.800 ;
        RECT 41.275 194.935 41.445 197.975 ;
        RECT 41.715 194.935 41.885 197.975 ;
        RECT 42.360 194.940 42.530 197.980 ;
        RECT 42.800 194.940 42.970 197.980 ;
        RECT 43.510 194.820 43.820 198.240 ;
        RECT 44.210 195.970 44.380 197.010 ;
        RECT 44.650 195.970 44.820 197.010 ;
        RECT 44.350 195.630 44.680 195.800 ;
        RECT 46.775 194.935 46.945 197.975 ;
        RECT 47.215 194.935 47.385 197.975 ;
        RECT 47.860 194.940 48.030 197.980 ;
        RECT 48.300 194.940 48.470 197.980 ;
        RECT 49.010 194.820 49.320 198.240 ;
        RECT 49.710 195.970 49.880 197.010 ;
        RECT 50.150 195.970 50.320 197.010 ;
        RECT 49.850 195.630 50.180 195.800 ;
        RECT 52.275 194.935 52.445 197.975 ;
        RECT 52.715 194.935 52.885 197.975 ;
        RECT 53.360 194.940 53.530 197.980 ;
        RECT 53.800 194.940 53.970 197.980 ;
        RECT 54.510 194.820 54.820 198.240 ;
        RECT 55.210 195.970 55.380 197.010 ;
        RECT 55.650 195.970 55.820 197.010 ;
        RECT 55.350 195.630 55.680 195.800 ;
        RECT 57.775 194.935 57.945 197.975 ;
        RECT 58.215 194.935 58.385 197.975 ;
        RECT 58.860 194.940 59.030 197.980 ;
        RECT 59.300 194.940 59.470 197.980 ;
        RECT 60.010 194.820 60.320 198.240 ;
        RECT 60.710 195.970 60.880 197.010 ;
        RECT 61.150 195.970 61.320 197.010 ;
        RECT 60.850 195.630 61.180 195.800 ;
        RECT 63.275 194.935 63.445 197.975 ;
        RECT 63.715 194.935 63.885 197.975 ;
        RECT 64.360 194.940 64.530 197.980 ;
        RECT 64.800 194.940 64.970 197.980 ;
        RECT 65.510 194.820 65.820 198.240 ;
        RECT 66.210 195.970 66.380 197.010 ;
        RECT 66.650 195.970 66.820 197.010 ;
        RECT 66.350 195.630 66.680 195.800 ;
        RECT 68.775 194.935 68.945 197.975 ;
        RECT 69.215 194.935 69.385 197.975 ;
        RECT 69.860 194.940 70.030 197.980 ;
        RECT 70.300 194.940 70.470 197.980 ;
        RECT 71.010 194.820 71.320 198.240 ;
        RECT 71.710 195.970 71.880 197.010 ;
        RECT 72.150 195.970 72.320 197.010 ;
        RECT 71.850 195.630 72.180 195.800 ;
        RECT 74.275 194.935 74.445 197.975 ;
        RECT 74.715 194.935 74.885 197.975 ;
        RECT 75.360 194.940 75.530 197.980 ;
        RECT 75.800 194.940 75.970 197.980 ;
        RECT 76.510 194.820 76.820 198.240 ;
        RECT 82.150 197.190 88.190 197.360 ;
        RECT 77.210 195.970 77.380 197.010 ;
        RECT 77.650 195.970 77.820 197.010 ;
        RECT 82.150 196.750 88.190 196.920 ;
        RECT 88.405 196.890 88.575 197.220 ;
        RECT 88.980 197.190 92.020 197.360 ;
        RECT 88.980 196.750 92.020 196.920 ;
        RECT 92.230 196.890 92.540 198.990 ;
        RECT 95.960 198.840 96.360 198.990 ;
        RECT 92.800 198.280 95.840 198.450 ;
        RECT 92.800 197.840 95.840 198.010 ;
        RECT 96.055 197.980 96.225 198.310 ;
        RECT 115.650 197.430 122.390 197.600 ;
        RECT 92.805 197.195 95.845 197.365 ;
        RECT 92.805 196.755 95.845 196.925 ;
        RECT 96.060 196.895 96.230 197.225 ;
        RECT 96.480 196.680 97.590 196.850 ;
        RECT 96.480 196.550 97.380 196.680 ;
        RECT 77.350 195.630 77.680 195.800 ;
        RECT 13.915 194.550 14.245 194.720 ;
        RECT 15.000 194.555 15.330 194.725 ;
        RECT 15.860 194.420 16.320 194.820 ;
        RECT 19.415 194.550 19.745 194.720 ;
        RECT 20.500 194.555 20.830 194.725 ;
        RECT 21.360 194.420 21.820 194.820 ;
        RECT 24.915 194.550 25.245 194.720 ;
        RECT 26.000 194.555 26.330 194.725 ;
        RECT 26.860 194.420 27.320 194.820 ;
        RECT 30.415 194.550 30.745 194.720 ;
        RECT 31.500 194.555 31.830 194.725 ;
        RECT 32.360 194.420 32.820 194.820 ;
        RECT 35.915 194.550 36.245 194.720 ;
        RECT 37.000 194.555 37.330 194.725 ;
        RECT 37.860 194.420 38.320 194.820 ;
        RECT 41.415 194.550 41.745 194.720 ;
        RECT 42.500 194.555 42.830 194.725 ;
        RECT 43.360 194.420 43.820 194.820 ;
        RECT 46.915 194.550 47.245 194.720 ;
        RECT 48.000 194.555 48.330 194.725 ;
        RECT 48.860 194.420 49.320 194.820 ;
        RECT 52.415 194.550 52.745 194.720 ;
        RECT 53.500 194.555 53.830 194.725 ;
        RECT 54.360 194.420 54.820 194.820 ;
        RECT 57.915 194.550 58.245 194.720 ;
        RECT 59.000 194.555 59.330 194.725 ;
        RECT 59.860 194.420 60.320 194.820 ;
        RECT 63.415 194.550 63.745 194.720 ;
        RECT 64.500 194.555 64.830 194.725 ;
        RECT 65.360 194.420 65.820 194.820 ;
        RECT 68.915 194.550 69.245 194.720 ;
        RECT 70.000 194.555 70.330 194.725 ;
        RECT 70.860 194.420 71.320 194.820 ;
        RECT 74.415 194.550 74.745 194.720 ;
        RECT 75.500 194.555 75.830 194.725 ;
        RECT 76.360 194.420 76.820 194.820 ;
        RECT 83.650 194.310 84.630 195.410 ;
        RECT 84.920 195.060 86.960 195.230 ;
        RECT 84.920 194.620 86.960 194.790 ;
        RECT 87.130 194.760 87.300 195.090 ;
        RECT 88.580 195.060 91.620 195.230 ;
        RECT 88.580 194.620 91.620 194.790 ;
        RECT 91.790 194.760 92.540 195.090 ;
        RECT 93.770 195.060 94.810 195.230 ;
        RECT 92.230 194.380 92.540 194.760 ;
        RECT 93.770 194.620 94.810 194.790 ;
        RECT 94.980 194.760 95.150 195.090 ;
        RECT 13.570 193.400 13.870 194.300 ;
        RECT 19.070 193.400 19.370 194.300 ;
        RECT 24.570 193.400 24.870 194.300 ;
        RECT 30.070 193.400 30.370 194.300 ;
        RECT 35.570 193.400 35.870 194.300 ;
        RECT 41.070 193.400 41.370 194.300 ;
        RECT 46.570 193.400 46.870 194.300 ;
        RECT 52.070 193.400 52.370 194.300 ;
        RECT 57.570 193.400 57.870 194.300 ;
        RECT 63.070 193.400 63.370 194.300 ;
        RECT 68.570 193.400 68.870 194.300 ;
        RECT 74.070 193.400 74.370 194.300 ;
        RECT 87.660 194.230 92.540 194.380 ;
        RECT 87.660 194.140 96.360 194.230 ;
        RECT 84.920 193.750 86.960 193.920 ;
        RECT 87.660 193.780 87.910 194.140 ;
        RECT 92.230 193.920 96.360 194.140 ;
        RECT 13.700 193.190 13.870 193.400 ;
        RECT 19.200 193.190 19.370 193.400 ;
        RECT 24.700 193.190 24.870 193.400 ;
        RECT 30.200 193.190 30.370 193.400 ;
        RECT 35.700 193.190 35.870 193.400 ;
        RECT 41.200 193.190 41.370 193.400 ;
        RECT 46.700 193.190 46.870 193.400 ;
        RECT 52.200 193.190 52.370 193.400 ;
        RECT 57.700 193.190 57.870 193.400 ;
        RECT 63.200 193.190 63.370 193.400 ;
        RECT 68.700 193.190 68.870 193.400 ;
        RECT 74.200 193.190 74.370 193.400 ;
        RECT 84.920 193.310 86.960 193.480 ;
        RECT 87.130 193.450 87.910 193.780 ;
        RECT 88.580 193.750 91.620 193.920 ;
        RECT 88.580 193.310 91.620 193.480 ;
        RECT 91.790 193.450 91.960 193.780 ;
        RECT 82.150 192.120 88.190 192.290 ;
        RECT 82.150 191.680 88.190 191.850 ;
        RECT 88.405 191.820 88.575 192.150 ;
        RECT 88.980 192.120 92.020 192.290 ;
        RECT 88.980 191.680 92.020 191.850 ;
        RECT 92.230 191.820 92.540 193.920 ;
        RECT 95.960 193.770 96.360 193.920 ;
        RECT 115.650 194.060 115.820 197.430 ;
        RECT 119.520 197.030 121.410 197.050 ;
        RECT 116.160 196.540 116.330 196.870 ;
        RECT 116.500 196.860 121.540 197.030 ;
        RECT 116.680 196.550 118.680 196.560 ;
        RECT 116.500 196.380 121.540 196.550 ;
        RECT 116.680 196.370 118.680 196.380 ;
        RECT 119.520 196.070 121.410 196.100 ;
        RECT 116.160 195.580 116.330 195.910 ;
        RECT 116.500 195.900 121.540 196.070 ;
        RECT 121.710 196.060 121.880 196.390 ;
        RECT 116.700 195.590 118.700 195.620 ;
        RECT 116.500 195.420 121.540 195.590 ;
        RECT 119.550 195.110 121.440 195.120 ;
        RECT 116.160 194.620 116.330 194.950 ;
        RECT 116.500 194.940 121.540 195.110 ;
        RECT 121.710 195.100 121.880 195.430 ;
        RECT 119.550 194.930 121.440 194.940 ;
        RECT 116.680 194.630 118.680 194.660 ;
        RECT 116.500 194.460 121.540 194.630 ;
        RECT 122.220 194.060 122.390 197.430 ;
        RECT 126.815 197.375 128.975 198.065 ;
        RECT 115.650 193.890 122.390 194.060 ;
        RECT 126.815 193.865 128.975 194.555 ;
        RECT 92.800 193.210 95.840 193.380 ;
        RECT 92.800 192.770 95.840 192.940 ;
        RECT 96.055 192.910 96.225 193.240 ;
        RECT 92.805 192.125 95.845 192.295 ;
        RECT 92.805 191.685 95.845 191.855 ;
        RECT 96.060 191.825 96.230 192.155 ;
        RECT 129.980 192.010 130.150 203.850 ;
        RECT 130.630 201.210 131.320 203.370 ;
        RECT 130.630 192.490 131.320 194.650 ;
        RECT 131.800 192.010 131.970 203.850 ;
        RECT 129.980 191.840 131.970 192.010 ;
        RECT 96.480 191.610 97.590 191.780 ;
        RECT 96.480 191.480 97.380 191.610 ;
        RECT 114.400 191.240 128.230 191.410 ;
        RECT 83.650 189.240 84.630 190.340 ;
        RECT 84.920 189.990 86.960 190.160 ;
        RECT 84.920 189.550 86.960 189.720 ;
        RECT 87.130 189.690 87.300 190.020 ;
        RECT 88.580 189.990 91.620 190.160 ;
        RECT 88.580 189.550 91.620 189.720 ;
        RECT 91.790 189.690 92.540 190.020 ;
        RECT 93.770 189.990 94.810 190.160 ;
        RECT 92.230 189.310 92.540 189.690 ;
        RECT 93.770 189.550 94.810 189.720 ;
        RECT 94.980 189.690 95.150 190.020 ;
        RECT 87.660 189.160 92.540 189.310 ;
        RECT 87.660 189.070 96.360 189.160 ;
        RECT 84.920 188.680 86.960 188.850 ;
        RECT 87.660 188.710 87.910 189.070 ;
        RECT 92.230 188.850 96.360 189.070 ;
        RECT 84.920 188.240 86.960 188.410 ;
        RECT 87.130 188.380 87.910 188.710 ;
        RECT 88.580 188.680 91.620 188.850 ;
        RECT 88.580 188.240 91.620 188.410 ;
        RECT 91.790 188.380 91.960 188.710 ;
        RECT 82.150 187.050 88.190 187.220 ;
        RECT 82.150 186.610 88.190 186.780 ;
        RECT 88.405 186.750 88.575 187.080 ;
        RECT 88.980 187.050 92.020 187.220 ;
        RECT 88.980 186.610 92.020 186.780 ;
        RECT 92.230 186.750 92.540 188.850 ;
        RECT 95.960 188.700 96.360 188.850 ;
        RECT 92.800 188.140 95.840 188.310 ;
        RECT 92.800 187.700 95.840 187.870 ;
        RECT 96.055 187.840 96.225 188.170 ;
        RECT 114.400 187.870 114.570 191.240 ;
        RECT 114.910 190.350 115.080 190.680 ;
        RECT 115.295 190.670 127.335 190.840 ;
        RECT 115.400 190.360 121.350 190.370 ;
        RECT 115.295 190.190 127.335 190.360 ;
        RECT 114.910 189.390 115.080 189.720 ;
        RECT 115.295 189.710 127.335 189.880 ;
        RECT 127.550 189.870 127.720 190.200 ;
        RECT 115.295 189.230 127.335 189.400 ;
        RECT 114.910 188.430 115.080 188.760 ;
        RECT 115.295 188.750 127.335 188.920 ;
        RECT 127.550 188.910 127.720 189.240 ;
        RECT 115.295 188.270 127.335 188.440 ;
        RECT 128.060 187.870 128.230 191.240 ;
        RECT 114.400 187.700 128.230 187.870 ;
        RECT 129.980 191.310 131.970 191.480 ;
        RECT 92.805 187.055 95.845 187.225 ;
        RECT 92.805 186.615 95.845 186.785 ;
        RECT 96.060 186.755 96.230 187.085 ;
        RECT 96.480 186.540 97.590 186.710 ;
        RECT 96.480 186.410 97.380 186.540 ;
        RECT 63.190 184.170 64.170 185.270 ;
        RECT 64.460 184.920 66.500 185.090 ;
        RECT 64.460 184.480 66.500 184.650 ;
        RECT 66.670 184.620 66.840 184.950 ;
        RECT 68.120 184.920 71.160 185.090 ;
        RECT 68.120 184.480 71.160 184.650 ;
        RECT 71.330 184.620 72.080 184.950 ;
        RECT 73.310 184.920 74.350 185.090 ;
        RECT 71.770 184.240 72.080 184.620 ;
        RECT 73.310 184.480 74.350 184.650 ;
        RECT 74.520 184.620 74.690 184.950 ;
        RECT 67.200 184.090 72.080 184.240 ;
        RECT 83.650 184.170 84.630 185.270 ;
        RECT 84.920 184.920 86.960 185.090 ;
        RECT 84.920 184.480 86.960 184.650 ;
        RECT 87.130 184.620 87.300 184.950 ;
        RECT 88.580 184.920 91.620 185.090 ;
        RECT 88.580 184.480 91.620 184.650 ;
        RECT 91.790 184.620 92.540 184.950 ;
        RECT 93.770 184.920 94.810 185.090 ;
        RECT 92.230 184.240 92.540 184.620 ;
        RECT 93.770 184.480 94.810 184.650 ;
        RECT 94.980 184.620 95.150 184.950 ;
        RECT 115.650 184.890 122.390 185.060 ;
        RECT 87.660 184.090 92.540 184.240 ;
        RECT 67.200 184.000 75.900 184.090 ;
        RECT 64.460 183.610 66.500 183.780 ;
        RECT 67.200 183.640 67.450 184.000 ;
        RECT 71.770 183.780 75.900 184.000 ;
        RECT 87.660 184.000 96.360 184.090 ;
        RECT 64.460 183.170 66.500 183.340 ;
        RECT 66.670 183.310 67.450 183.640 ;
        RECT 68.120 183.610 71.160 183.780 ;
        RECT 68.120 183.170 71.160 183.340 ;
        RECT 71.330 183.310 71.500 183.640 ;
        RECT 61.690 181.980 67.730 182.150 ;
        RECT 61.690 181.540 67.730 181.710 ;
        RECT 67.945 181.680 68.115 182.010 ;
        RECT 68.520 181.980 71.560 182.150 ;
        RECT 68.520 181.540 71.560 181.710 ;
        RECT 71.770 181.680 72.080 183.780 ;
        RECT 75.500 183.630 75.900 183.780 ;
        RECT 84.920 183.610 86.960 183.780 ;
        RECT 87.660 183.640 87.910 184.000 ;
        RECT 92.230 183.780 96.360 184.000 ;
        RECT 72.340 183.070 75.380 183.240 ;
        RECT 84.920 183.170 86.960 183.340 ;
        RECT 87.130 183.310 87.910 183.640 ;
        RECT 88.580 183.610 91.620 183.780 ;
        RECT 88.580 183.170 91.620 183.340 ;
        RECT 91.790 183.310 91.960 183.640 ;
        RECT 72.340 182.630 75.380 182.800 ;
        RECT 75.595 182.770 75.765 183.100 ;
        RECT 72.345 181.985 75.385 182.155 ;
        RECT 72.345 181.545 75.385 181.715 ;
        RECT 75.600 181.685 75.770 182.015 ;
        RECT 82.150 181.980 88.190 182.150 ;
        RECT 76.020 181.470 77.130 181.640 ;
        RECT 82.150 181.540 88.190 181.710 ;
        RECT 88.405 181.680 88.575 182.010 ;
        RECT 88.980 181.980 92.020 182.150 ;
        RECT 88.980 181.540 92.020 181.710 ;
        RECT 92.230 181.680 92.540 183.780 ;
        RECT 95.960 183.630 96.360 183.780 ;
        RECT 92.800 183.070 95.840 183.240 ;
        RECT 92.800 182.630 95.840 182.800 ;
        RECT 96.055 182.770 96.225 183.100 ;
        RECT 92.805 181.985 95.845 182.155 ;
        RECT 92.805 181.545 95.845 181.715 ;
        RECT 96.060 181.685 96.230 182.015 ;
        RECT 96.480 181.470 97.590 181.640 ;
        RECT 115.650 181.520 115.820 184.890 ;
        RECT 119.520 184.490 121.410 184.510 ;
        RECT 116.160 184.000 116.330 184.330 ;
        RECT 116.500 184.320 121.540 184.490 ;
        RECT 116.680 184.010 118.680 184.020 ;
        RECT 116.500 183.840 121.540 184.010 ;
        RECT 116.680 183.830 118.680 183.840 ;
        RECT 119.520 183.530 121.410 183.560 ;
        RECT 116.160 183.040 116.330 183.370 ;
        RECT 116.500 183.360 121.540 183.530 ;
        RECT 121.710 183.520 121.880 183.850 ;
        RECT 116.700 183.050 118.700 183.080 ;
        RECT 116.500 182.880 121.540 183.050 ;
        RECT 119.550 182.570 121.440 182.580 ;
        RECT 116.160 182.080 116.330 182.410 ;
        RECT 116.500 182.400 121.540 182.570 ;
        RECT 121.710 182.560 121.880 182.890 ;
        RECT 119.550 182.390 121.440 182.400 ;
        RECT 116.680 182.090 118.680 182.120 ;
        RECT 116.500 181.920 121.540 182.090 ;
        RECT 122.220 181.520 122.390 184.890 ;
        RECT 126.815 184.835 128.975 185.525 ;
        RECT 76.020 181.340 76.920 181.470 ;
        RECT 96.480 181.340 97.380 181.470 ;
        RECT 115.650 181.350 122.390 181.520 ;
        RECT 126.815 181.325 128.975 182.015 ;
        RECT 79.010 181.190 79.320 181.210 ;
        RECT 61.580 180.950 68.060 181.120 ;
        RECT 61.580 179.540 61.750 180.950 ;
        RECT 62.120 180.380 67.160 180.550 ;
        RECT 62.120 179.940 67.160 180.110 ;
        RECT 67.375 180.080 67.545 180.410 ;
        RECT 67.890 179.540 68.060 180.950 ;
        RECT 76.440 180.780 77.480 180.950 ;
        RECT 78.980 180.810 79.360 181.190 ;
        RECT 77.670 180.620 79.360 180.810 ;
        RECT 76.440 180.340 77.480 180.510 ;
        RECT 77.670 180.340 79.200 180.620 ;
        RECT 76.435 179.695 77.475 179.865 ;
        RECT 61.580 179.370 68.060 179.540 ;
        RECT 76.435 179.255 77.475 179.425 ;
        RECT 77.690 179.395 77.860 179.725 ;
        RECT 78.380 179.630 78.550 180.170 ;
        RECT 78.820 179.630 78.990 180.170 ;
        RECT 79.380 179.850 79.550 180.390 ;
        RECT 79.820 179.850 79.990 180.390 ;
        RECT 79.520 179.510 79.850 179.680 ;
        RECT 68.960 178.570 70.060 179.180 ;
        RECT 83.650 179.100 84.630 180.200 ;
        RECT 84.920 179.850 86.960 180.020 ;
        RECT 84.920 179.410 86.960 179.580 ;
        RECT 87.130 179.550 87.300 179.880 ;
        RECT 88.580 179.850 91.620 180.020 ;
        RECT 88.580 179.410 91.620 179.580 ;
        RECT 91.790 179.550 92.540 179.880 ;
        RECT 93.770 179.850 94.810 180.020 ;
        RECT 92.230 179.170 92.540 179.550 ;
        RECT 93.770 179.410 94.810 179.580 ;
        RECT 94.980 179.550 95.150 179.880 ;
        RECT 129.980 179.470 130.150 191.310 ;
        RECT 130.630 188.670 131.320 190.830 ;
        RECT 130.630 179.950 131.320 182.110 ;
        RECT 131.800 179.470 131.970 191.310 ;
        RECT 129.980 179.300 131.970 179.470 ;
        RECT 76.350 178.730 77.080 178.910 ;
        RECT 78.870 178.680 79.940 179.080 ;
        RECT 87.660 179.020 92.540 179.170 ;
        RECT 87.660 178.930 96.360 179.020 ;
        RECT 84.920 178.540 86.960 178.710 ;
        RECT 87.660 178.570 87.910 178.930 ;
        RECT 92.230 178.710 96.360 178.930 ;
        RECT 69.060 178.030 69.600 178.200 ;
        RECT 84.920 178.100 86.960 178.270 ;
        RECT 87.130 178.240 87.910 178.570 ;
        RECT 88.580 178.540 91.620 178.710 ;
        RECT 88.580 178.100 91.620 178.270 ;
        RECT 91.790 178.240 91.960 178.570 ;
        RECT 63.270 177.590 66.700 177.760 ;
        RECT 69.060 177.590 69.600 177.760 ;
        RECT 69.770 177.730 69.940 178.060 ;
        RECT 63.270 176.180 63.440 177.590 ;
        RECT 63.810 177.020 65.850 177.190 ;
        RECT 63.810 176.580 65.850 176.750 ;
        RECT 66.020 176.720 66.190 177.050 ;
        RECT 66.530 176.180 66.700 177.590 ;
        RECT 68.900 176.780 69.720 176.950 ;
        RECT 82.150 176.910 88.190 177.080 ;
        RECT 68.900 176.340 69.720 176.510 ;
        RECT 70.045 176.480 70.215 176.810 ;
        RECT 82.150 176.470 88.190 176.640 ;
        RECT 88.405 176.610 88.575 176.940 ;
        RECT 88.980 176.910 92.020 177.080 ;
        RECT 88.980 176.470 92.020 176.640 ;
        RECT 92.230 176.610 92.540 178.710 ;
        RECT 95.960 178.560 96.360 178.710 ;
        RECT 114.400 178.700 128.230 178.870 ;
        RECT 92.800 178.000 95.840 178.170 ;
        RECT 92.800 177.560 95.840 177.730 ;
        RECT 96.055 177.700 96.225 178.030 ;
        RECT 92.805 176.915 95.845 177.085 ;
        RECT 92.805 176.475 95.845 176.645 ;
        RECT 96.060 176.615 96.230 176.945 ;
        RECT 96.480 176.400 97.590 176.570 ;
        RECT 96.480 176.270 97.380 176.400 ;
        RECT 63.270 176.010 66.700 176.180 ;
        RECT 68.910 175.720 70.130 175.950 ;
        RECT 114.400 175.330 114.570 178.700 ;
        RECT 114.910 177.810 115.080 178.140 ;
        RECT 115.295 178.130 127.335 178.300 ;
        RECT 115.400 177.820 121.350 177.830 ;
        RECT 115.295 177.650 127.335 177.820 ;
        RECT 114.910 176.850 115.080 177.180 ;
        RECT 115.295 177.170 127.335 177.340 ;
        RECT 127.550 177.330 127.720 177.660 ;
        RECT 115.295 176.690 127.335 176.860 ;
        RECT 114.910 175.890 115.080 176.220 ;
        RECT 115.295 176.210 127.335 176.380 ;
        RECT 127.550 176.370 127.720 176.700 ;
        RECT 115.295 175.730 127.335 175.900 ;
        RECT 128.060 175.330 128.230 178.700 ;
        RECT 114.400 175.160 128.230 175.330 ;
        RECT 129.980 178.770 131.970 178.940 ;
        RECT 45.930 174.290 47.900 174.570 ;
        RECT 36.470 173.230 36.650 173.960 ;
        RECT 34.885 172.460 35.055 172.790 ;
        RECT 35.380 172.760 36.200 172.930 ;
        RECT 36.995 172.835 37.165 173.875 ;
        RECT 37.435 172.835 37.605 173.875 ;
        RECT 38.080 172.830 38.250 173.870 ;
        RECT 38.520 172.830 38.690 173.870 ;
        RECT 40.190 173.485 40.360 173.815 ;
        RECT 40.575 173.785 43.615 173.955 ;
        RECT 40.575 173.345 43.615 173.515 ;
        RECT 35.380 172.320 36.200 172.490 ;
        RECT 37.135 172.450 37.465 172.620 ;
        RECT 37.370 171.760 37.910 171.930 ;
        RECT 35.160 171.210 35.330 171.540 ;
        RECT 35.500 171.510 36.040 171.680 ;
        RECT 35.500 171.070 36.040 171.240 ;
        RECT 36.420 170.370 36.820 171.440 ;
        RECT 37.370 171.320 37.910 171.490 ;
        RECT 38.080 171.330 38.550 172.640 ;
        RECT 40.195 172.400 40.365 172.730 ;
        RECT 40.580 172.700 43.620 172.870 ;
        RECT 40.580 172.260 43.620 172.430 ;
        RECT 40.060 171.720 40.460 171.870 ;
        RECT 43.880 171.720 44.190 173.820 ;
        RECT 44.400 173.790 47.440 173.960 ;
        RECT 44.400 173.350 47.440 173.520 ;
        RECT 47.845 173.490 48.015 173.820 ;
        RECT 48.230 173.790 54.270 173.960 ;
        RECT 48.230 173.350 54.270 173.520 ;
        RECT 115.650 172.350 122.390 172.520 ;
        RECT 44.460 171.860 44.630 172.190 ;
        RECT 44.800 172.160 47.840 172.330 ;
        RECT 44.800 171.720 47.840 171.890 ;
        RECT 48.510 171.860 49.290 172.190 ;
        RECT 49.460 172.160 51.500 172.330 ;
        RECT 40.060 171.500 44.190 171.720 ;
        RECT 48.510 171.500 48.760 171.860 ;
        RECT 49.460 171.720 51.500 171.890 ;
        RECT 40.060 171.410 48.760 171.500 ;
        RECT 38.080 171.300 38.930 171.330 ;
        RECT 38.080 171.110 38.950 171.300 ;
        RECT 38.360 170.990 38.950 171.110 ;
        RECT 43.880 171.260 48.760 171.410 ;
        RECT 38.360 170.950 38.930 170.990 ;
        RECT 37.250 170.460 37.420 170.790 ;
        RECT 37.590 170.760 38.130 170.930 ;
        RECT 41.270 170.550 41.440 170.880 ;
        RECT 41.610 170.850 42.650 171.020 ;
        RECT 43.880 170.880 44.190 171.260 ;
        RECT 37.590 170.320 38.130 170.490 ;
        RECT 41.610 170.410 42.650 170.580 ;
        RECT 43.880 170.550 44.630 170.880 ;
        RECT 44.800 170.850 47.840 171.020 ;
        RECT 44.800 170.410 47.840 170.580 ;
        RECT 49.120 170.550 49.290 170.880 ;
        RECT 49.460 170.850 51.500 171.020 ;
        RECT 49.460 170.410 51.500 170.580 ;
        RECT 43.120 169.990 44.140 170.340 ;
        RECT 69.880 169.110 71.840 169.280 ;
        RECT 115.650 168.980 115.820 172.350 ;
        RECT 119.520 171.950 121.410 171.970 ;
        RECT 116.160 171.460 116.330 171.790 ;
        RECT 116.500 171.780 121.540 171.950 ;
        RECT 116.680 171.470 118.680 171.480 ;
        RECT 116.500 171.300 121.540 171.470 ;
        RECT 116.680 171.290 118.680 171.300 ;
        RECT 119.520 170.990 121.410 171.020 ;
        RECT 116.160 170.500 116.330 170.830 ;
        RECT 116.500 170.820 121.540 170.990 ;
        RECT 121.710 170.980 121.880 171.310 ;
        RECT 116.700 170.510 118.700 170.540 ;
        RECT 116.500 170.340 121.540 170.510 ;
        RECT 119.550 170.030 121.440 170.040 ;
        RECT 116.160 169.540 116.330 169.870 ;
        RECT 116.500 169.860 121.540 170.030 ;
        RECT 121.710 170.020 121.880 170.350 ;
        RECT 119.550 169.850 121.440 169.860 ;
        RECT 116.680 169.550 118.680 169.580 ;
        RECT 116.500 169.380 121.540 169.550 ;
        RECT 122.220 168.980 122.390 172.350 ;
        RECT 126.815 172.295 128.975 172.985 ;
        RECT 45.930 168.330 47.900 168.610 ;
        RECT 60.740 168.305 60.910 168.635 ;
        RECT 61.125 168.605 67.165 168.775 ;
        RECT 61.125 168.165 67.165 168.335 ;
        RECT 36.470 167.270 36.650 168.000 ;
        RECT 34.885 166.500 35.055 166.830 ;
        RECT 35.380 166.800 36.200 166.970 ;
        RECT 36.995 166.875 37.165 167.915 ;
        RECT 37.435 166.875 37.605 167.915 ;
        RECT 38.080 166.870 38.250 167.910 ;
        RECT 38.520 166.870 38.690 167.910 ;
        RECT 40.190 167.525 40.360 167.855 ;
        RECT 40.575 167.825 43.615 167.995 ;
        RECT 40.575 167.385 43.615 167.555 ;
        RECT 35.380 166.360 36.200 166.530 ;
        RECT 37.135 166.490 37.465 166.660 ;
        RECT 37.370 165.800 37.910 165.970 ;
        RECT 35.160 165.250 35.330 165.580 ;
        RECT 35.500 165.550 36.040 165.720 ;
        RECT 35.500 165.110 36.040 165.280 ;
        RECT 36.420 164.410 36.820 165.480 ;
        RECT 37.370 165.360 37.910 165.530 ;
        RECT 38.080 165.370 38.550 166.680 ;
        RECT 40.195 166.440 40.365 166.770 ;
        RECT 40.580 166.740 43.620 166.910 ;
        RECT 40.580 166.300 43.620 166.470 ;
        RECT 40.060 165.760 40.460 165.910 ;
        RECT 43.880 165.760 44.190 167.860 ;
        RECT 44.400 167.830 47.440 168.000 ;
        RECT 44.400 167.390 47.440 167.560 ;
        RECT 47.845 167.530 48.015 167.860 ;
        RECT 48.230 167.830 54.270 168.000 ;
        RECT 48.230 167.390 54.270 167.560 ;
        RECT 60.735 167.220 60.905 167.550 ;
        RECT 61.120 167.520 67.160 167.690 ;
        RECT 61.120 167.080 67.160 167.250 ;
        RECT 67.490 166.790 67.750 168.640 ;
        RECT 67.950 168.610 70.990 168.780 ;
        RECT 67.950 168.170 70.990 168.340 ;
        RECT 71.390 168.000 71.600 168.640 ;
        RECT 72.545 168.610 77.115 168.780 ;
        RECT 72.545 168.170 77.115 168.340 ;
        RECT 78.285 168.310 78.455 168.640 ;
        RECT 78.670 168.610 84.710 168.780 ;
        RECT 78.670 168.170 84.710 168.340 ;
        RECT 71.390 167.750 73.870 168.000 ;
        RECT 71.615 167.100 71.785 167.430 ;
        RECT 72.110 167.400 72.930 167.570 ;
        RECT 73.330 167.540 73.870 167.750 ;
        RECT 84.990 167.710 85.330 168.640 ;
        RECT 85.540 168.610 91.580 168.780 ;
        RECT 85.540 168.170 91.580 168.340 ;
        RECT 92.760 168.080 94.140 168.840 ;
        RECT 115.650 168.810 122.390 168.980 ;
        RECT 126.815 168.785 128.975 169.475 ;
        RECT 94.845 168.310 95.015 168.640 ;
        RECT 95.230 168.610 100.270 168.780 ;
        RECT 95.230 168.170 100.270 168.340 ;
        RECT 72.110 166.960 72.930 167.130 ;
        RECT 78.755 167.110 78.925 167.440 ;
        RECT 79.250 167.410 80.070 167.580 ;
        RECT 81.450 167.180 85.330 167.710 ;
        RECT 92.005 167.240 92.175 167.570 ;
        RECT 92.390 167.540 94.430 167.710 ;
        RECT 79.250 166.970 80.070 167.140 ;
        RECT 92.390 167.100 94.430 167.270 ;
        RECT 129.980 166.930 130.150 178.770 ;
        RECT 130.630 176.130 131.320 178.290 ;
        RECT 130.630 167.410 131.320 169.570 ;
        RECT 131.800 166.930 131.970 178.770 ;
        RECT 67.490 166.720 82.090 166.790 ;
        RECT 129.980 166.760 131.970 166.930 ;
        RECT 62.770 166.520 82.090 166.720 ;
        RECT 44.460 165.900 44.630 166.230 ;
        RECT 44.800 166.200 47.840 166.370 ;
        RECT 44.800 165.760 47.840 165.930 ;
        RECT 48.510 165.900 49.290 166.230 ;
        RECT 49.460 166.200 51.500 166.370 ;
        RECT 40.060 165.540 44.190 165.760 ;
        RECT 48.510 165.540 48.760 165.900 ;
        RECT 49.460 165.760 51.500 165.930 ;
        RECT 62.770 165.720 66.890 166.520 ;
        RECT 67.610 165.880 67.780 166.210 ;
        RECT 67.950 166.180 70.990 166.350 ;
        RECT 67.950 165.740 70.990 165.910 ;
        RECT 71.890 165.850 72.060 166.180 ;
        RECT 72.230 166.150 72.770 166.320 ;
        RECT 40.060 165.450 48.760 165.540 ;
        RECT 38.080 165.340 38.930 165.370 ;
        RECT 38.080 165.150 38.950 165.340 ;
        RECT 38.360 165.030 38.950 165.150 ;
        RECT 43.880 165.300 48.760 165.450 ;
        RECT 38.360 164.990 38.930 165.030 ;
        RECT 37.250 164.500 37.420 164.830 ;
        RECT 37.590 164.800 38.130 164.970 ;
        RECT 41.270 164.590 41.440 164.920 ;
        RECT 41.610 164.890 42.650 165.060 ;
        RECT 43.880 164.920 44.190 165.300 ;
        RECT 37.590 164.360 38.130 164.530 ;
        RECT 41.610 164.450 42.650 164.620 ;
        RECT 43.880 164.590 44.630 164.920 ;
        RECT 44.800 164.890 47.840 165.060 ;
        RECT 44.800 164.450 47.840 164.620 ;
        RECT 49.120 164.590 49.290 164.920 ;
        RECT 49.460 164.890 51.500 165.060 ;
        RECT 49.460 164.450 51.500 164.620 ;
        RECT 43.120 164.030 44.140 164.380 ;
        RECT 61.860 164.080 62.920 165.100 ;
        RECT 63.220 164.870 63.390 165.200 ;
        RECT 63.560 165.170 64.600 165.340 ;
        RECT 63.560 164.730 64.600 164.900 ;
        RECT 64.990 164.510 65.900 165.290 ;
        RECT 66.150 165.200 66.890 165.720 ;
        RECT 72.230 165.710 72.770 165.880 ;
        RECT 74.370 165.770 79.200 166.290 ;
        RECT 79.370 166.160 79.910 166.330 ;
        RECT 66.150 164.870 67.780 165.200 ;
        RECT 67.950 165.170 70.990 165.340 ;
        RECT 67.950 164.730 70.990 164.900 ;
        RECT 71.390 164.530 72.090 165.300 ;
        RECT 74.370 164.870 74.730 165.770 ;
        RECT 79.370 165.720 79.910 165.890 ;
        RECT 81.730 165.880 82.090 166.520 ;
        RECT 82.260 166.180 84.300 166.350 ;
        RECT 82.260 165.740 84.300 165.910 ;
        RECT 74.900 165.170 76.940 165.340 ;
        RECT 74.900 164.730 76.940 164.900 ;
        RECT 81.930 164.870 82.100 165.200 ;
        RECT 82.270 165.170 84.310 165.340 ;
        RECT 85.290 165.150 86.660 166.280 ;
        RECT 114.400 166.160 128.230 166.330 ;
        RECT 82.270 164.730 84.310 164.900 ;
        RECT 86.990 164.530 87.270 165.200 ;
        RECT 87.440 165.170 89.480 165.340 ;
        RECT 87.440 164.730 89.480 164.900 ;
        RECT 92.010 164.870 92.180 165.200 ;
        RECT 92.350 165.170 93.390 165.340 ;
        RECT 92.350 164.730 93.390 164.900 ;
        RECT 96.090 164.870 96.260 165.200 ;
        RECT 96.430 165.170 98.470 165.340 ;
        RECT 96.430 164.730 98.470 164.900 ;
        RECT 71.390 164.230 87.270 164.530 ;
        RECT 114.400 162.790 114.570 166.160 ;
        RECT 114.910 165.270 115.080 165.600 ;
        RECT 115.295 165.590 127.335 165.760 ;
        RECT 115.400 165.280 121.350 165.290 ;
        RECT 115.295 165.110 127.335 165.280 ;
        RECT 114.910 164.310 115.080 164.640 ;
        RECT 115.295 164.630 127.335 164.800 ;
        RECT 127.550 164.790 127.720 165.120 ;
        RECT 115.295 164.150 127.335 164.320 ;
        RECT 114.910 163.350 115.080 163.680 ;
        RECT 115.295 163.670 127.335 163.840 ;
        RECT 127.550 163.830 127.720 164.160 ;
        RECT 115.295 163.190 127.335 163.360 ;
        RECT 128.060 162.790 128.230 166.160 ;
        RECT 114.400 162.620 128.230 162.790 ;
        RECT 129.980 166.230 131.970 166.400 ;
        RECT 69.880 161.760 71.840 161.930 ;
        RECT 45.930 160.980 47.900 161.260 ;
        RECT 60.740 160.955 60.910 161.285 ;
        RECT 61.125 161.255 67.165 161.425 ;
        RECT 61.125 160.815 67.165 160.985 ;
        RECT 36.470 159.920 36.650 160.650 ;
        RECT 34.885 159.150 35.055 159.480 ;
        RECT 35.380 159.450 36.200 159.620 ;
        RECT 36.995 159.525 37.165 160.565 ;
        RECT 37.435 159.525 37.605 160.565 ;
        RECT 38.080 159.520 38.250 160.560 ;
        RECT 38.520 159.520 38.690 160.560 ;
        RECT 40.190 160.175 40.360 160.505 ;
        RECT 40.575 160.475 43.615 160.645 ;
        RECT 40.575 160.035 43.615 160.205 ;
        RECT 35.380 159.010 36.200 159.180 ;
        RECT 37.135 159.140 37.465 159.310 ;
        RECT 37.370 158.450 37.910 158.620 ;
        RECT 35.160 157.900 35.330 158.230 ;
        RECT 35.500 158.200 36.040 158.370 ;
        RECT 35.500 157.760 36.040 157.930 ;
        RECT 36.420 157.060 36.820 158.130 ;
        RECT 37.370 158.010 37.910 158.180 ;
        RECT 38.080 158.020 38.550 159.330 ;
        RECT 40.195 159.090 40.365 159.420 ;
        RECT 40.580 159.390 43.620 159.560 ;
        RECT 40.580 158.950 43.620 159.120 ;
        RECT 40.060 158.410 40.460 158.560 ;
        RECT 43.880 158.410 44.190 160.510 ;
        RECT 44.400 160.480 47.440 160.650 ;
        RECT 44.400 160.040 47.440 160.210 ;
        RECT 47.845 160.180 48.015 160.510 ;
        RECT 48.230 160.480 54.270 160.650 ;
        RECT 48.230 160.040 54.270 160.210 ;
        RECT 60.735 159.870 60.905 160.200 ;
        RECT 61.120 160.170 67.160 160.340 ;
        RECT 61.120 159.730 67.160 159.900 ;
        RECT 67.490 159.440 67.750 161.290 ;
        RECT 67.950 161.260 70.990 161.430 ;
        RECT 67.950 160.820 70.990 160.990 ;
        RECT 71.390 160.650 71.600 161.290 ;
        RECT 72.545 161.260 77.115 161.430 ;
        RECT 72.545 160.820 77.115 160.990 ;
        RECT 78.285 160.960 78.455 161.290 ;
        RECT 78.670 161.260 84.710 161.430 ;
        RECT 78.670 160.820 84.710 160.990 ;
        RECT 71.390 160.400 73.870 160.650 ;
        RECT 71.615 159.750 71.785 160.080 ;
        RECT 72.110 160.050 72.930 160.220 ;
        RECT 73.330 160.190 73.870 160.400 ;
        RECT 84.990 160.360 85.330 161.290 ;
        RECT 85.540 161.260 91.580 161.430 ;
        RECT 85.540 160.820 91.580 160.990 ;
        RECT 92.760 160.730 94.140 161.490 ;
        RECT 94.845 160.960 95.015 161.290 ;
        RECT 95.230 161.260 100.270 161.430 ;
        RECT 95.230 160.820 100.270 160.990 ;
        RECT 72.110 159.610 72.930 159.780 ;
        RECT 78.755 159.760 78.925 160.090 ;
        RECT 79.250 160.060 80.070 160.230 ;
        RECT 81.450 159.830 85.330 160.360 ;
        RECT 92.005 159.890 92.175 160.220 ;
        RECT 92.390 160.190 94.430 160.360 ;
        RECT 79.250 159.620 80.070 159.790 ;
        RECT 92.390 159.750 94.430 159.920 ;
        RECT 115.650 159.810 122.390 159.980 ;
        RECT 67.490 159.370 82.090 159.440 ;
        RECT 62.770 159.170 82.090 159.370 ;
        RECT 44.460 158.550 44.630 158.880 ;
        RECT 44.800 158.850 47.840 159.020 ;
        RECT 44.800 158.410 47.840 158.580 ;
        RECT 48.510 158.550 49.290 158.880 ;
        RECT 49.460 158.850 51.500 159.020 ;
        RECT 40.060 158.190 44.190 158.410 ;
        RECT 48.510 158.190 48.760 158.550 ;
        RECT 49.460 158.410 51.500 158.580 ;
        RECT 62.770 158.370 66.890 159.170 ;
        RECT 67.610 158.530 67.780 158.860 ;
        RECT 67.950 158.830 70.990 159.000 ;
        RECT 67.950 158.390 70.990 158.560 ;
        RECT 71.890 158.500 72.060 158.830 ;
        RECT 72.230 158.800 72.770 158.970 ;
        RECT 40.060 158.100 48.760 158.190 ;
        RECT 38.080 157.990 38.930 158.020 ;
        RECT 38.080 157.800 38.950 157.990 ;
        RECT 38.360 157.680 38.950 157.800 ;
        RECT 43.880 157.950 48.760 158.100 ;
        RECT 38.360 157.640 38.930 157.680 ;
        RECT 37.250 157.150 37.420 157.480 ;
        RECT 37.590 157.450 38.130 157.620 ;
        RECT 41.270 157.240 41.440 157.570 ;
        RECT 41.610 157.540 42.650 157.710 ;
        RECT 43.880 157.570 44.190 157.950 ;
        RECT 37.590 157.010 38.130 157.180 ;
        RECT 41.610 157.100 42.650 157.270 ;
        RECT 43.880 157.240 44.630 157.570 ;
        RECT 44.800 157.540 47.840 157.710 ;
        RECT 44.800 157.100 47.840 157.270 ;
        RECT 49.120 157.240 49.290 157.570 ;
        RECT 49.460 157.540 51.500 157.710 ;
        RECT 49.460 157.100 51.500 157.270 ;
        RECT 43.120 156.680 44.140 157.030 ;
        RECT 61.860 156.730 62.920 157.750 ;
        RECT 63.220 157.520 63.390 157.850 ;
        RECT 63.560 157.820 64.600 157.990 ;
        RECT 63.560 157.380 64.600 157.550 ;
        RECT 64.990 157.160 65.900 157.940 ;
        RECT 66.150 157.850 66.890 158.370 ;
        RECT 72.230 158.360 72.770 158.530 ;
        RECT 74.370 158.420 79.200 158.940 ;
        RECT 79.370 158.810 79.910 158.980 ;
        RECT 66.150 157.520 67.780 157.850 ;
        RECT 67.950 157.820 70.990 157.990 ;
        RECT 67.950 157.380 70.990 157.550 ;
        RECT 71.390 157.180 72.090 157.950 ;
        RECT 74.370 157.520 74.730 158.420 ;
        RECT 79.370 158.370 79.910 158.540 ;
        RECT 81.730 158.530 82.090 159.170 ;
        RECT 82.260 158.830 84.300 159.000 ;
        RECT 82.260 158.390 84.300 158.560 ;
        RECT 74.900 157.820 76.940 157.990 ;
        RECT 74.900 157.380 76.940 157.550 ;
        RECT 81.930 157.520 82.100 157.850 ;
        RECT 82.270 157.820 84.310 157.990 ;
        RECT 85.290 157.800 86.660 158.930 ;
        RECT 82.270 157.380 84.310 157.550 ;
        RECT 86.990 157.180 87.270 157.850 ;
        RECT 87.440 157.820 89.480 157.990 ;
        RECT 87.440 157.380 89.480 157.550 ;
        RECT 92.010 157.520 92.180 157.850 ;
        RECT 92.350 157.820 93.390 157.990 ;
        RECT 92.350 157.380 93.390 157.550 ;
        RECT 96.090 157.520 96.260 157.850 ;
        RECT 96.430 157.820 98.470 157.990 ;
        RECT 96.430 157.380 98.470 157.550 ;
        RECT 71.390 156.880 87.270 157.180 ;
        RECT 115.650 156.440 115.820 159.810 ;
        RECT 119.520 159.410 121.410 159.430 ;
        RECT 116.160 158.920 116.330 159.250 ;
        RECT 116.500 159.240 121.540 159.410 ;
        RECT 116.680 158.930 118.680 158.940 ;
        RECT 116.500 158.760 121.540 158.930 ;
        RECT 116.680 158.750 118.680 158.760 ;
        RECT 119.520 158.450 121.410 158.480 ;
        RECT 116.160 157.960 116.330 158.290 ;
        RECT 116.500 158.280 121.540 158.450 ;
        RECT 121.710 158.440 121.880 158.770 ;
        RECT 116.700 157.970 118.700 158.000 ;
        RECT 116.500 157.800 121.540 157.970 ;
        RECT 119.550 157.490 121.440 157.500 ;
        RECT 116.160 157.000 116.330 157.330 ;
        RECT 116.500 157.320 121.540 157.490 ;
        RECT 121.710 157.480 121.880 157.810 ;
        RECT 119.550 157.310 121.440 157.320 ;
        RECT 116.680 157.010 118.680 157.040 ;
        RECT 116.500 156.840 121.540 157.010 ;
        RECT 122.220 156.440 122.390 159.810 ;
        RECT 126.815 159.755 128.975 160.445 ;
        RECT 115.650 156.270 122.390 156.440 ;
        RECT 126.815 156.245 128.975 156.935 ;
        RECT 69.880 154.410 71.840 154.580 ;
        RECT 129.980 154.390 130.150 166.230 ;
        RECT 130.630 163.590 131.320 165.750 ;
        RECT 130.630 154.870 131.320 157.030 ;
        RECT 131.800 154.390 131.970 166.230 ;
        RECT 129.980 154.220 131.970 154.390 ;
        RECT 45.930 153.630 47.900 153.910 ;
        RECT 60.740 153.605 60.910 153.935 ;
        RECT 61.125 153.905 67.165 154.075 ;
        RECT 61.125 153.465 67.165 153.635 ;
        RECT 36.470 152.570 36.650 153.300 ;
        RECT 34.885 151.800 35.055 152.130 ;
        RECT 35.380 152.100 36.200 152.270 ;
        RECT 36.995 152.175 37.165 153.215 ;
        RECT 37.435 152.175 37.605 153.215 ;
        RECT 38.080 152.170 38.250 153.210 ;
        RECT 38.520 152.170 38.690 153.210 ;
        RECT 40.190 152.825 40.360 153.155 ;
        RECT 40.575 153.125 43.615 153.295 ;
        RECT 40.575 152.685 43.615 152.855 ;
        RECT 35.380 151.660 36.200 151.830 ;
        RECT 37.135 151.790 37.465 151.960 ;
        RECT 37.370 151.100 37.910 151.270 ;
        RECT 35.160 150.550 35.330 150.880 ;
        RECT 35.500 150.850 36.040 151.020 ;
        RECT 35.500 150.410 36.040 150.580 ;
        RECT 36.420 149.710 36.820 150.780 ;
        RECT 37.370 150.660 37.910 150.830 ;
        RECT 38.080 150.670 38.550 151.980 ;
        RECT 40.195 151.740 40.365 152.070 ;
        RECT 40.580 152.040 43.620 152.210 ;
        RECT 40.580 151.600 43.620 151.770 ;
        RECT 40.060 151.060 40.460 151.210 ;
        RECT 43.880 151.060 44.190 153.160 ;
        RECT 44.400 153.130 47.440 153.300 ;
        RECT 44.400 152.690 47.440 152.860 ;
        RECT 47.845 152.830 48.015 153.160 ;
        RECT 48.230 153.130 54.270 153.300 ;
        RECT 48.230 152.690 54.270 152.860 ;
        RECT 60.735 152.520 60.905 152.850 ;
        RECT 61.120 152.820 67.160 152.990 ;
        RECT 61.120 152.380 67.160 152.550 ;
        RECT 67.490 152.090 67.750 153.940 ;
        RECT 67.950 153.910 70.990 154.080 ;
        RECT 67.950 153.470 70.990 153.640 ;
        RECT 71.390 153.300 71.600 153.940 ;
        RECT 72.545 153.910 77.115 154.080 ;
        RECT 72.545 153.470 77.115 153.640 ;
        RECT 78.285 153.610 78.455 153.940 ;
        RECT 78.670 153.910 84.710 154.080 ;
        RECT 78.670 153.470 84.710 153.640 ;
        RECT 71.390 153.050 73.870 153.300 ;
        RECT 71.615 152.400 71.785 152.730 ;
        RECT 72.110 152.700 72.930 152.870 ;
        RECT 73.330 152.840 73.870 153.050 ;
        RECT 84.990 153.010 85.330 153.940 ;
        RECT 85.540 153.910 91.580 154.080 ;
        RECT 85.540 153.470 91.580 153.640 ;
        RECT 92.760 153.380 94.140 154.140 ;
        RECT 94.845 153.610 95.015 153.940 ;
        RECT 95.230 153.910 100.270 154.080 ;
        RECT 95.230 153.470 100.270 153.640 ;
        RECT 114.400 153.620 128.230 153.790 ;
        RECT 72.110 152.260 72.930 152.430 ;
        RECT 78.755 152.410 78.925 152.740 ;
        RECT 79.250 152.710 80.070 152.880 ;
        RECT 81.450 152.480 85.330 153.010 ;
        RECT 92.005 152.540 92.175 152.870 ;
        RECT 92.390 152.840 94.430 153.010 ;
        RECT 79.250 152.270 80.070 152.440 ;
        RECT 92.390 152.400 94.430 152.570 ;
        RECT 67.490 152.020 82.090 152.090 ;
        RECT 62.770 151.820 82.090 152.020 ;
        RECT 44.460 151.200 44.630 151.530 ;
        RECT 44.800 151.500 47.840 151.670 ;
        RECT 44.800 151.060 47.840 151.230 ;
        RECT 48.510 151.200 49.290 151.530 ;
        RECT 49.460 151.500 51.500 151.670 ;
        RECT 40.060 150.840 44.190 151.060 ;
        RECT 48.510 150.840 48.760 151.200 ;
        RECT 49.460 151.060 51.500 151.230 ;
        RECT 62.770 151.020 66.890 151.820 ;
        RECT 67.610 151.180 67.780 151.510 ;
        RECT 67.950 151.480 70.990 151.650 ;
        RECT 67.950 151.040 70.990 151.210 ;
        RECT 71.890 151.150 72.060 151.480 ;
        RECT 72.230 151.450 72.770 151.620 ;
        RECT 40.060 150.750 48.760 150.840 ;
        RECT 38.080 150.640 38.930 150.670 ;
        RECT 38.080 150.450 38.950 150.640 ;
        RECT 38.360 150.330 38.950 150.450 ;
        RECT 43.880 150.600 48.760 150.750 ;
        RECT 38.360 150.290 38.930 150.330 ;
        RECT 37.250 149.800 37.420 150.130 ;
        RECT 37.590 150.100 38.130 150.270 ;
        RECT 41.270 149.890 41.440 150.220 ;
        RECT 41.610 150.190 42.650 150.360 ;
        RECT 43.880 150.220 44.190 150.600 ;
        RECT 37.590 149.660 38.130 149.830 ;
        RECT 41.610 149.750 42.650 149.920 ;
        RECT 43.880 149.890 44.630 150.220 ;
        RECT 44.800 150.190 47.840 150.360 ;
        RECT 44.800 149.750 47.840 149.920 ;
        RECT 49.120 149.890 49.290 150.220 ;
        RECT 49.460 150.190 51.500 150.360 ;
        RECT 49.460 149.750 51.500 149.920 ;
        RECT 43.120 149.330 44.140 149.680 ;
        RECT 61.860 149.380 62.920 150.400 ;
        RECT 63.220 150.170 63.390 150.500 ;
        RECT 63.560 150.470 64.600 150.640 ;
        RECT 63.560 150.030 64.600 150.200 ;
        RECT 64.990 149.810 65.900 150.590 ;
        RECT 66.150 150.500 66.890 151.020 ;
        RECT 72.230 151.010 72.770 151.180 ;
        RECT 74.370 151.070 79.200 151.590 ;
        RECT 79.370 151.460 79.910 151.630 ;
        RECT 66.150 150.170 67.780 150.500 ;
        RECT 67.950 150.470 70.990 150.640 ;
        RECT 67.950 150.030 70.990 150.200 ;
        RECT 71.390 149.830 72.090 150.600 ;
        RECT 74.370 150.170 74.730 151.070 ;
        RECT 79.370 151.020 79.910 151.190 ;
        RECT 81.730 151.180 82.090 151.820 ;
        RECT 82.260 151.480 84.300 151.650 ;
        RECT 82.260 151.040 84.300 151.210 ;
        RECT 74.900 150.470 76.940 150.640 ;
        RECT 74.900 150.030 76.940 150.200 ;
        RECT 81.930 150.170 82.100 150.500 ;
        RECT 82.270 150.470 84.310 150.640 ;
        RECT 85.290 150.450 86.660 151.580 ;
        RECT 82.270 150.030 84.310 150.200 ;
        RECT 86.990 149.830 87.270 150.500 ;
        RECT 87.440 150.470 89.480 150.640 ;
        RECT 87.440 150.030 89.480 150.200 ;
        RECT 92.010 150.170 92.180 150.500 ;
        RECT 92.350 150.470 93.390 150.640 ;
        RECT 92.350 150.030 93.390 150.200 ;
        RECT 96.090 150.170 96.260 150.500 ;
        RECT 96.430 150.470 98.470 150.640 ;
        RECT 114.400 150.250 114.570 153.620 ;
        RECT 114.910 152.730 115.080 153.060 ;
        RECT 115.295 153.050 127.335 153.220 ;
        RECT 115.400 152.740 121.350 152.750 ;
        RECT 115.295 152.570 127.335 152.740 ;
        RECT 114.910 151.770 115.080 152.100 ;
        RECT 115.295 152.090 127.335 152.260 ;
        RECT 127.550 152.250 127.720 152.580 ;
        RECT 115.295 151.610 127.335 151.780 ;
        RECT 114.910 150.810 115.080 151.140 ;
        RECT 115.295 151.130 127.335 151.300 ;
        RECT 127.550 151.290 127.720 151.620 ;
        RECT 115.295 150.650 127.335 150.820 ;
        RECT 128.060 150.250 128.230 153.620 ;
        RECT 96.430 150.030 98.470 150.200 ;
        RECT 114.400 150.080 128.230 150.250 ;
        RECT 129.980 153.690 131.970 153.860 ;
        RECT 71.390 149.530 87.270 149.830 ;
        RECT 115.650 147.270 122.390 147.440 ;
        RECT 69.880 147.060 71.840 147.230 ;
        RECT 45.930 146.280 47.900 146.560 ;
        RECT 60.740 146.255 60.910 146.585 ;
        RECT 61.125 146.555 67.165 146.725 ;
        RECT 61.125 146.115 67.165 146.285 ;
        RECT 36.470 145.220 36.650 145.950 ;
        RECT 34.885 144.450 35.055 144.780 ;
        RECT 35.380 144.750 36.200 144.920 ;
        RECT 36.995 144.825 37.165 145.865 ;
        RECT 37.435 144.825 37.605 145.865 ;
        RECT 38.080 144.820 38.250 145.860 ;
        RECT 38.520 144.820 38.690 145.860 ;
        RECT 40.190 145.475 40.360 145.805 ;
        RECT 40.575 145.775 43.615 145.945 ;
        RECT 40.575 145.335 43.615 145.505 ;
        RECT 35.380 144.310 36.200 144.480 ;
        RECT 37.135 144.440 37.465 144.610 ;
        RECT 37.370 143.750 37.910 143.920 ;
        RECT 35.160 143.200 35.330 143.530 ;
        RECT 35.500 143.500 36.040 143.670 ;
        RECT 35.500 143.060 36.040 143.230 ;
        RECT 36.420 142.360 36.820 143.430 ;
        RECT 37.370 143.310 37.910 143.480 ;
        RECT 38.080 143.320 38.550 144.630 ;
        RECT 40.195 144.390 40.365 144.720 ;
        RECT 40.580 144.690 43.620 144.860 ;
        RECT 40.580 144.250 43.620 144.420 ;
        RECT 40.060 143.710 40.460 143.860 ;
        RECT 43.880 143.710 44.190 145.810 ;
        RECT 44.400 145.780 47.440 145.950 ;
        RECT 44.400 145.340 47.440 145.510 ;
        RECT 47.845 145.480 48.015 145.810 ;
        RECT 48.230 145.780 54.270 145.950 ;
        RECT 48.230 145.340 54.270 145.510 ;
        RECT 60.735 145.170 60.905 145.500 ;
        RECT 61.120 145.470 67.160 145.640 ;
        RECT 61.120 145.030 67.160 145.200 ;
        RECT 67.490 144.740 67.750 146.590 ;
        RECT 67.950 146.560 70.990 146.730 ;
        RECT 67.950 146.120 70.990 146.290 ;
        RECT 71.390 145.950 71.600 146.590 ;
        RECT 72.545 146.560 77.115 146.730 ;
        RECT 72.545 146.120 77.115 146.290 ;
        RECT 78.285 146.260 78.455 146.590 ;
        RECT 78.670 146.560 84.710 146.730 ;
        RECT 78.670 146.120 84.710 146.290 ;
        RECT 71.390 145.700 73.870 145.950 ;
        RECT 71.615 145.050 71.785 145.380 ;
        RECT 72.110 145.350 72.930 145.520 ;
        RECT 73.330 145.490 73.870 145.700 ;
        RECT 84.990 145.660 85.330 146.590 ;
        RECT 85.540 146.560 91.580 146.730 ;
        RECT 85.540 146.120 91.580 146.290 ;
        RECT 92.760 146.030 94.140 146.790 ;
        RECT 94.845 146.260 95.015 146.590 ;
        RECT 95.230 146.560 100.270 146.730 ;
        RECT 95.230 146.120 100.270 146.290 ;
        RECT 72.110 144.910 72.930 145.080 ;
        RECT 78.755 145.060 78.925 145.390 ;
        RECT 79.250 145.360 80.070 145.530 ;
        RECT 81.450 145.130 85.330 145.660 ;
        RECT 92.005 145.190 92.175 145.520 ;
        RECT 92.390 145.490 94.430 145.660 ;
        RECT 79.250 144.920 80.070 145.090 ;
        RECT 92.390 145.050 94.430 145.220 ;
        RECT 67.490 144.670 82.090 144.740 ;
        RECT 62.770 144.470 82.090 144.670 ;
        RECT 44.460 143.850 44.630 144.180 ;
        RECT 44.800 144.150 47.840 144.320 ;
        RECT 44.800 143.710 47.840 143.880 ;
        RECT 48.510 143.850 49.290 144.180 ;
        RECT 49.460 144.150 51.500 144.320 ;
        RECT 40.060 143.490 44.190 143.710 ;
        RECT 48.510 143.490 48.760 143.850 ;
        RECT 49.460 143.710 51.500 143.880 ;
        RECT 62.770 143.670 66.890 144.470 ;
        RECT 67.610 143.830 67.780 144.160 ;
        RECT 67.950 144.130 70.990 144.300 ;
        RECT 67.950 143.690 70.990 143.860 ;
        RECT 71.890 143.800 72.060 144.130 ;
        RECT 72.230 144.100 72.770 144.270 ;
        RECT 40.060 143.400 48.760 143.490 ;
        RECT 38.080 143.290 38.930 143.320 ;
        RECT 38.080 143.100 38.950 143.290 ;
        RECT 38.360 142.980 38.950 143.100 ;
        RECT 43.880 143.250 48.760 143.400 ;
        RECT 38.360 142.940 38.930 142.980 ;
        RECT 37.250 142.450 37.420 142.780 ;
        RECT 37.590 142.750 38.130 142.920 ;
        RECT 41.270 142.540 41.440 142.870 ;
        RECT 41.610 142.840 42.650 143.010 ;
        RECT 43.880 142.870 44.190 143.250 ;
        RECT 37.590 142.310 38.130 142.480 ;
        RECT 41.610 142.400 42.650 142.570 ;
        RECT 43.880 142.540 44.630 142.870 ;
        RECT 44.800 142.840 47.840 143.010 ;
        RECT 44.800 142.400 47.840 142.570 ;
        RECT 49.120 142.540 49.290 142.870 ;
        RECT 49.460 142.840 51.500 143.010 ;
        RECT 49.460 142.400 51.500 142.570 ;
        RECT 43.120 141.980 44.140 142.330 ;
        RECT 61.860 142.030 62.920 143.050 ;
        RECT 63.220 142.820 63.390 143.150 ;
        RECT 63.560 143.120 64.600 143.290 ;
        RECT 63.560 142.680 64.600 142.850 ;
        RECT 64.990 142.460 65.900 143.240 ;
        RECT 66.150 143.150 66.890 143.670 ;
        RECT 72.230 143.660 72.770 143.830 ;
        RECT 74.370 143.720 79.200 144.240 ;
        RECT 79.370 144.110 79.910 144.280 ;
        RECT 66.150 142.820 67.780 143.150 ;
        RECT 67.950 143.120 70.990 143.290 ;
        RECT 67.950 142.680 70.990 142.850 ;
        RECT 71.390 142.480 72.090 143.250 ;
        RECT 74.370 142.820 74.730 143.720 ;
        RECT 79.370 143.670 79.910 143.840 ;
        RECT 81.730 143.830 82.090 144.470 ;
        RECT 82.260 144.130 84.300 144.300 ;
        RECT 82.260 143.690 84.300 143.860 ;
        RECT 74.900 143.120 76.940 143.290 ;
        RECT 74.900 142.680 76.940 142.850 ;
        RECT 81.930 142.820 82.100 143.150 ;
        RECT 82.270 143.120 84.310 143.290 ;
        RECT 85.290 143.100 86.660 144.230 ;
        RECT 115.650 143.900 115.820 147.270 ;
        RECT 119.520 146.870 121.410 146.890 ;
        RECT 116.160 146.380 116.330 146.710 ;
        RECT 116.500 146.700 121.540 146.870 ;
        RECT 116.680 146.390 118.680 146.400 ;
        RECT 116.500 146.220 121.540 146.390 ;
        RECT 116.680 146.210 118.680 146.220 ;
        RECT 119.520 145.910 121.410 145.940 ;
        RECT 116.160 145.420 116.330 145.750 ;
        RECT 116.500 145.740 121.540 145.910 ;
        RECT 121.710 145.900 121.880 146.230 ;
        RECT 116.700 145.430 118.700 145.460 ;
        RECT 116.500 145.260 121.540 145.430 ;
        RECT 119.550 144.950 121.440 144.960 ;
        RECT 116.160 144.460 116.330 144.790 ;
        RECT 116.500 144.780 121.540 144.950 ;
        RECT 121.710 144.940 121.880 145.270 ;
        RECT 119.550 144.770 121.440 144.780 ;
        RECT 116.680 144.470 118.680 144.500 ;
        RECT 116.500 144.300 121.540 144.470 ;
        RECT 122.220 143.900 122.390 147.270 ;
        RECT 126.815 147.215 128.975 147.905 ;
        RECT 115.650 143.730 122.390 143.900 ;
        RECT 126.815 143.705 128.975 144.395 ;
        RECT 82.270 142.680 84.310 142.850 ;
        RECT 86.990 142.480 87.270 143.150 ;
        RECT 87.440 143.120 89.480 143.290 ;
        RECT 87.440 142.680 89.480 142.850 ;
        RECT 92.010 142.820 92.180 143.150 ;
        RECT 92.350 143.120 93.390 143.290 ;
        RECT 92.350 142.680 93.390 142.850 ;
        RECT 96.090 142.820 96.260 143.150 ;
        RECT 96.430 143.120 98.470 143.290 ;
        RECT 96.430 142.680 98.470 142.850 ;
        RECT 71.390 142.180 87.270 142.480 ;
        RECT 129.980 141.850 130.150 153.690 ;
        RECT 130.630 151.050 131.320 153.210 ;
        RECT 130.630 142.330 131.320 144.490 ;
        RECT 131.800 141.850 131.970 153.690 ;
        RECT 129.980 141.680 131.970 141.850 ;
        RECT 114.400 141.080 128.230 141.250 ;
        RECT 69.880 139.710 71.840 139.880 ;
        RECT 45.930 138.930 47.900 139.210 ;
        RECT 60.740 138.905 60.910 139.235 ;
        RECT 61.125 139.205 67.165 139.375 ;
        RECT 61.125 138.765 67.165 138.935 ;
        RECT 36.470 137.870 36.650 138.600 ;
        RECT 34.885 137.100 35.055 137.430 ;
        RECT 35.380 137.400 36.200 137.570 ;
        RECT 36.995 137.475 37.165 138.515 ;
        RECT 37.435 137.475 37.605 138.515 ;
        RECT 38.080 137.470 38.250 138.510 ;
        RECT 38.520 137.470 38.690 138.510 ;
        RECT 40.190 138.125 40.360 138.455 ;
        RECT 40.575 138.425 43.615 138.595 ;
        RECT 40.575 137.985 43.615 138.155 ;
        RECT 35.380 136.960 36.200 137.130 ;
        RECT 37.135 137.090 37.465 137.260 ;
        RECT 37.370 136.400 37.910 136.570 ;
        RECT 35.160 135.850 35.330 136.180 ;
        RECT 35.500 136.150 36.040 136.320 ;
        RECT 35.500 135.710 36.040 135.880 ;
        RECT 36.420 135.010 36.820 136.080 ;
        RECT 37.370 135.960 37.910 136.130 ;
        RECT 38.080 135.970 38.550 137.280 ;
        RECT 40.195 137.040 40.365 137.370 ;
        RECT 40.580 137.340 43.620 137.510 ;
        RECT 40.580 136.900 43.620 137.070 ;
        RECT 40.060 136.360 40.460 136.510 ;
        RECT 43.880 136.360 44.190 138.460 ;
        RECT 44.400 138.430 47.440 138.600 ;
        RECT 44.400 137.990 47.440 138.160 ;
        RECT 47.845 138.130 48.015 138.460 ;
        RECT 48.230 138.430 54.270 138.600 ;
        RECT 48.230 137.990 54.270 138.160 ;
        RECT 60.735 137.820 60.905 138.150 ;
        RECT 61.120 138.120 67.160 138.290 ;
        RECT 61.120 137.680 67.160 137.850 ;
        RECT 67.490 137.390 67.750 139.240 ;
        RECT 67.950 139.210 70.990 139.380 ;
        RECT 67.950 138.770 70.990 138.940 ;
        RECT 71.390 138.600 71.600 139.240 ;
        RECT 72.545 139.210 77.115 139.380 ;
        RECT 72.545 138.770 77.115 138.940 ;
        RECT 78.285 138.910 78.455 139.240 ;
        RECT 78.670 139.210 84.710 139.380 ;
        RECT 78.670 138.770 84.710 138.940 ;
        RECT 71.390 138.350 73.870 138.600 ;
        RECT 71.615 137.700 71.785 138.030 ;
        RECT 72.110 138.000 72.930 138.170 ;
        RECT 73.330 138.140 73.870 138.350 ;
        RECT 84.990 138.310 85.330 139.240 ;
        RECT 85.540 139.210 91.580 139.380 ;
        RECT 85.540 138.770 91.580 138.940 ;
        RECT 92.760 138.680 94.140 139.440 ;
        RECT 94.845 138.910 95.015 139.240 ;
        RECT 95.230 139.210 100.270 139.380 ;
        RECT 95.230 138.770 100.270 138.940 ;
        RECT 72.110 137.560 72.930 137.730 ;
        RECT 78.755 137.710 78.925 138.040 ;
        RECT 79.250 138.010 80.070 138.180 ;
        RECT 81.450 137.780 85.330 138.310 ;
        RECT 92.005 137.840 92.175 138.170 ;
        RECT 92.390 138.140 94.430 138.310 ;
        RECT 79.250 137.570 80.070 137.740 ;
        RECT 92.390 137.700 94.430 137.870 ;
        RECT 114.400 137.710 114.570 141.080 ;
        RECT 114.910 140.190 115.080 140.520 ;
        RECT 115.295 140.510 127.335 140.680 ;
        RECT 115.400 140.200 121.350 140.210 ;
        RECT 115.295 140.030 127.335 140.200 ;
        RECT 114.910 139.230 115.080 139.560 ;
        RECT 115.295 139.550 127.335 139.720 ;
        RECT 127.550 139.710 127.720 140.040 ;
        RECT 115.295 139.070 127.335 139.240 ;
        RECT 114.910 138.270 115.080 138.600 ;
        RECT 115.295 138.590 127.335 138.760 ;
        RECT 127.550 138.750 127.720 139.080 ;
        RECT 115.295 138.110 127.335 138.280 ;
        RECT 128.060 137.710 128.230 141.080 ;
        RECT 114.400 137.540 128.230 137.710 ;
        RECT 129.980 141.150 131.970 141.320 ;
        RECT 67.490 137.320 82.090 137.390 ;
        RECT 62.770 137.120 82.090 137.320 ;
        RECT 44.460 136.500 44.630 136.830 ;
        RECT 44.800 136.800 47.840 136.970 ;
        RECT 44.800 136.360 47.840 136.530 ;
        RECT 48.510 136.500 49.290 136.830 ;
        RECT 49.460 136.800 51.500 136.970 ;
        RECT 40.060 136.140 44.190 136.360 ;
        RECT 48.510 136.140 48.760 136.500 ;
        RECT 49.460 136.360 51.500 136.530 ;
        RECT 62.770 136.320 66.890 137.120 ;
        RECT 67.610 136.480 67.780 136.810 ;
        RECT 67.950 136.780 70.990 136.950 ;
        RECT 67.950 136.340 70.990 136.510 ;
        RECT 71.890 136.450 72.060 136.780 ;
        RECT 72.230 136.750 72.770 136.920 ;
        RECT 40.060 136.050 48.760 136.140 ;
        RECT 38.080 135.940 38.930 135.970 ;
        RECT 38.080 135.750 38.950 135.940 ;
        RECT 38.360 135.630 38.950 135.750 ;
        RECT 43.880 135.900 48.760 136.050 ;
        RECT 38.360 135.590 38.930 135.630 ;
        RECT 37.250 135.100 37.420 135.430 ;
        RECT 37.590 135.400 38.130 135.570 ;
        RECT 41.270 135.190 41.440 135.520 ;
        RECT 41.610 135.490 42.650 135.660 ;
        RECT 43.880 135.520 44.190 135.900 ;
        RECT 37.590 134.960 38.130 135.130 ;
        RECT 41.610 135.050 42.650 135.220 ;
        RECT 43.880 135.190 44.630 135.520 ;
        RECT 44.800 135.490 47.840 135.660 ;
        RECT 44.800 135.050 47.840 135.220 ;
        RECT 49.120 135.190 49.290 135.520 ;
        RECT 49.460 135.490 51.500 135.660 ;
        RECT 49.460 135.050 51.500 135.220 ;
        RECT 43.120 134.630 44.140 134.980 ;
        RECT 61.860 134.680 62.920 135.700 ;
        RECT 63.220 135.470 63.390 135.800 ;
        RECT 63.560 135.770 64.600 135.940 ;
        RECT 63.560 135.330 64.600 135.500 ;
        RECT 64.990 135.110 65.900 135.890 ;
        RECT 66.150 135.800 66.890 136.320 ;
        RECT 72.230 136.310 72.770 136.480 ;
        RECT 74.370 136.370 79.200 136.890 ;
        RECT 79.370 136.760 79.910 136.930 ;
        RECT 66.150 135.470 67.780 135.800 ;
        RECT 67.950 135.770 70.990 135.940 ;
        RECT 67.950 135.330 70.990 135.500 ;
        RECT 71.390 135.130 72.090 135.900 ;
        RECT 74.370 135.470 74.730 136.370 ;
        RECT 79.370 136.320 79.910 136.490 ;
        RECT 81.730 136.480 82.090 137.120 ;
        RECT 82.260 136.780 84.300 136.950 ;
        RECT 82.260 136.340 84.300 136.510 ;
        RECT 74.900 135.770 76.940 135.940 ;
        RECT 74.900 135.330 76.940 135.500 ;
        RECT 81.930 135.470 82.100 135.800 ;
        RECT 82.270 135.770 84.310 135.940 ;
        RECT 85.290 135.750 86.660 136.880 ;
        RECT 82.270 135.330 84.310 135.500 ;
        RECT 86.990 135.130 87.270 135.800 ;
        RECT 87.440 135.770 89.480 135.940 ;
        RECT 87.440 135.330 89.480 135.500 ;
        RECT 92.010 135.470 92.180 135.800 ;
        RECT 92.350 135.770 93.390 135.940 ;
        RECT 92.350 135.330 93.390 135.500 ;
        RECT 96.090 135.470 96.260 135.800 ;
        RECT 96.430 135.770 98.470 135.940 ;
        RECT 96.430 135.330 98.470 135.500 ;
        RECT 71.390 134.830 87.270 135.130 ;
        RECT 115.650 134.730 122.390 134.900 ;
        RECT 69.880 132.360 71.840 132.530 ;
        RECT 45.930 131.580 47.900 131.860 ;
        RECT 60.740 131.555 60.910 131.885 ;
        RECT 61.125 131.855 67.165 132.025 ;
        RECT 61.125 131.415 67.165 131.585 ;
        RECT 36.470 130.520 36.650 131.250 ;
        RECT 34.885 129.750 35.055 130.080 ;
        RECT 35.380 130.050 36.200 130.220 ;
        RECT 36.995 130.125 37.165 131.165 ;
        RECT 37.435 130.125 37.605 131.165 ;
        RECT 38.080 130.120 38.250 131.160 ;
        RECT 38.520 130.120 38.690 131.160 ;
        RECT 40.190 130.775 40.360 131.105 ;
        RECT 40.575 131.075 43.615 131.245 ;
        RECT 40.575 130.635 43.615 130.805 ;
        RECT 35.380 129.610 36.200 129.780 ;
        RECT 37.135 129.740 37.465 129.910 ;
        RECT 37.370 129.050 37.910 129.220 ;
        RECT 35.160 128.500 35.330 128.830 ;
        RECT 35.500 128.800 36.040 128.970 ;
        RECT 35.500 128.360 36.040 128.530 ;
        RECT 36.420 127.660 36.820 128.730 ;
        RECT 37.370 128.610 37.910 128.780 ;
        RECT 38.080 128.620 38.550 129.930 ;
        RECT 40.195 129.690 40.365 130.020 ;
        RECT 40.580 129.990 43.620 130.160 ;
        RECT 40.580 129.550 43.620 129.720 ;
        RECT 40.060 129.010 40.460 129.160 ;
        RECT 43.880 129.010 44.190 131.110 ;
        RECT 44.400 131.080 47.440 131.250 ;
        RECT 44.400 130.640 47.440 130.810 ;
        RECT 47.845 130.780 48.015 131.110 ;
        RECT 48.230 131.080 54.270 131.250 ;
        RECT 48.230 130.640 54.270 130.810 ;
        RECT 60.735 130.470 60.905 130.800 ;
        RECT 61.120 130.770 67.160 130.940 ;
        RECT 61.120 130.330 67.160 130.500 ;
        RECT 67.490 130.040 67.750 131.890 ;
        RECT 67.950 131.860 70.990 132.030 ;
        RECT 67.950 131.420 70.990 131.590 ;
        RECT 71.390 131.250 71.600 131.890 ;
        RECT 72.545 131.860 77.115 132.030 ;
        RECT 72.545 131.420 77.115 131.590 ;
        RECT 78.285 131.560 78.455 131.890 ;
        RECT 78.670 131.860 84.710 132.030 ;
        RECT 78.670 131.420 84.710 131.590 ;
        RECT 71.390 131.000 73.870 131.250 ;
        RECT 71.615 130.350 71.785 130.680 ;
        RECT 72.110 130.650 72.930 130.820 ;
        RECT 73.330 130.790 73.870 131.000 ;
        RECT 84.990 130.960 85.330 131.890 ;
        RECT 85.540 131.860 91.580 132.030 ;
        RECT 85.540 131.420 91.580 131.590 ;
        RECT 92.760 131.330 94.140 132.090 ;
        RECT 94.845 131.560 95.015 131.890 ;
        RECT 95.230 131.860 100.270 132.030 ;
        RECT 95.230 131.420 100.270 131.590 ;
        RECT 115.650 131.360 115.820 134.730 ;
        RECT 119.520 134.330 121.410 134.350 ;
        RECT 116.160 133.840 116.330 134.170 ;
        RECT 116.500 134.160 121.540 134.330 ;
        RECT 116.680 133.850 118.680 133.860 ;
        RECT 116.500 133.680 121.540 133.850 ;
        RECT 116.680 133.670 118.680 133.680 ;
        RECT 119.520 133.370 121.410 133.400 ;
        RECT 116.160 132.880 116.330 133.210 ;
        RECT 116.500 133.200 121.540 133.370 ;
        RECT 121.710 133.360 121.880 133.690 ;
        RECT 116.700 132.890 118.700 132.920 ;
        RECT 116.500 132.720 121.540 132.890 ;
        RECT 119.550 132.410 121.440 132.420 ;
        RECT 116.160 131.920 116.330 132.250 ;
        RECT 116.500 132.240 121.540 132.410 ;
        RECT 121.710 132.400 121.880 132.730 ;
        RECT 119.550 132.230 121.440 132.240 ;
        RECT 116.680 131.930 118.680 131.960 ;
        RECT 116.500 131.760 121.540 131.930 ;
        RECT 122.220 131.360 122.390 134.730 ;
        RECT 126.815 134.675 128.975 135.365 ;
        RECT 115.650 131.190 122.390 131.360 ;
        RECT 126.815 131.165 128.975 131.855 ;
        RECT 72.110 130.210 72.930 130.380 ;
        RECT 78.755 130.360 78.925 130.690 ;
        RECT 79.250 130.660 80.070 130.830 ;
        RECT 81.450 130.430 85.330 130.960 ;
        RECT 92.005 130.490 92.175 130.820 ;
        RECT 92.390 130.790 94.430 130.960 ;
        RECT 79.250 130.220 80.070 130.390 ;
        RECT 92.390 130.350 94.430 130.520 ;
        RECT 67.490 129.970 82.090 130.040 ;
        RECT 62.770 129.770 82.090 129.970 ;
        RECT 44.460 129.150 44.630 129.480 ;
        RECT 44.800 129.450 47.840 129.620 ;
        RECT 44.800 129.010 47.840 129.180 ;
        RECT 48.510 129.150 49.290 129.480 ;
        RECT 49.460 129.450 51.500 129.620 ;
        RECT 40.060 128.790 44.190 129.010 ;
        RECT 48.510 128.790 48.760 129.150 ;
        RECT 49.460 129.010 51.500 129.180 ;
        RECT 62.770 128.970 66.890 129.770 ;
        RECT 67.610 129.130 67.780 129.460 ;
        RECT 67.950 129.430 70.990 129.600 ;
        RECT 67.950 128.990 70.990 129.160 ;
        RECT 71.890 129.100 72.060 129.430 ;
        RECT 72.230 129.400 72.770 129.570 ;
        RECT 40.060 128.700 48.760 128.790 ;
        RECT 38.080 128.590 38.930 128.620 ;
        RECT 38.080 128.400 38.950 128.590 ;
        RECT 38.360 128.280 38.950 128.400 ;
        RECT 43.880 128.550 48.760 128.700 ;
        RECT 38.360 128.240 38.930 128.280 ;
        RECT 37.250 127.750 37.420 128.080 ;
        RECT 37.590 128.050 38.130 128.220 ;
        RECT 41.270 127.840 41.440 128.170 ;
        RECT 41.610 128.140 42.650 128.310 ;
        RECT 43.880 128.170 44.190 128.550 ;
        RECT 37.590 127.610 38.130 127.780 ;
        RECT 41.610 127.700 42.650 127.870 ;
        RECT 43.880 127.840 44.630 128.170 ;
        RECT 44.800 128.140 47.840 128.310 ;
        RECT 44.800 127.700 47.840 127.870 ;
        RECT 49.120 127.840 49.290 128.170 ;
        RECT 49.460 128.140 51.500 128.310 ;
        RECT 49.460 127.700 51.500 127.870 ;
        RECT 43.120 127.280 44.140 127.630 ;
        RECT 61.860 127.330 62.920 128.350 ;
        RECT 63.220 128.120 63.390 128.450 ;
        RECT 63.560 128.420 64.600 128.590 ;
        RECT 63.560 127.980 64.600 128.150 ;
        RECT 64.990 127.760 65.900 128.540 ;
        RECT 66.150 128.450 66.890 128.970 ;
        RECT 72.230 128.960 72.770 129.130 ;
        RECT 74.370 129.020 79.200 129.540 ;
        RECT 79.370 129.410 79.910 129.580 ;
        RECT 66.150 128.120 67.780 128.450 ;
        RECT 67.950 128.420 70.990 128.590 ;
        RECT 67.950 127.980 70.990 128.150 ;
        RECT 71.390 127.780 72.090 128.550 ;
        RECT 74.370 128.120 74.730 129.020 ;
        RECT 79.370 128.970 79.910 129.140 ;
        RECT 81.730 129.130 82.090 129.770 ;
        RECT 82.260 129.430 84.300 129.600 ;
        RECT 82.260 128.990 84.300 129.160 ;
        RECT 74.900 128.420 76.940 128.590 ;
        RECT 74.900 127.980 76.940 128.150 ;
        RECT 81.930 128.120 82.100 128.450 ;
        RECT 82.270 128.420 84.310 128.590 ;
        RECT 85.290 128.400 86.660 129.530 ;
        RECT 129.980 129.310 130.150 141.150 ;
        RECT 130.630 138.510 131.320 140.670 ;
        RECT 130.630 129.790 131.320 131.950 ;
        RECT 131.800 129.310 131.970 141.150 ;
        RECT 129.980 129.140 131.970 129.310 ;
        RECT 82.270 127.980 84.310 128.150 ;
        RECT 86.990 127.780 87.270 128.450 ;
        RECT 87.440 128.420 89.480 128.590 ;
        RECT 87.440 127.980 89.480 128.150 ;
        RECT 92.010 128.120 92.180 128.450 ;
        RECT 92.350 128.420 93.390 128.590 ;
        RECT 92.350 127.980 93.390 128.150 ;
        RECT 96.090 128.120 96.260 128.450 ;
        RECT 96.430 128.420 98.470 128.590 ;
        RECT 114.400 128.540 128.230 128.710 ;
        RECT 96.430 127.980 98.470 128.150 ;
        RECT 71.390 127.480 87.270 127.780 ;
        RECT 69.880 125.010 71.840 125.180 ;
        RECT 114.400 125.170 114.570 128.540 ;
        RECT 114.910 127.650 115.080 127.980 ;
        RECT 115.295 127.970 127.335 128.140 ;
        RECT 115.400 127.660 121.350 127.670 ;
        RECT 115.295 127.490 127.335 127.660 ;
        RECT 114.910 126.690 115.080 127.020 ;
        RECT 115.295 127.010 127.335 127.180 ;
        RECT 127.550 127.170 127.720 127.500 ;
        RECT 115.295 126.530 127.335 126.700 ;
        RECT 114.910 125.730 115.080 126.060 ;
        RECT 115.295 126.050 127.335 126.220 ;
        RECT 127.550 126.210 127.720 126.540 ;
        RECT 115.295 125.570 127.335 125.740 ;
        RECT 128.060 125.170 128.230 128.540 ;
        RECT 114.400 125.000 128.230 125.170 ;
        RECT 129.980 128.610 131.970 128.780 ;
        RECT 45.930 124.230 47.900 124.510 ;
        RECT 60.740 124.205 60.910 124.535 ;
        RECT 61.125 124.505 67.165 124.675 ;
        RECT 61.125 124.065 67.165 124.235 ;
        RECT 36.470 123.170 36.650 123.900 ;
        RECT 34.885 122.400 35.055 122.730 ;
        RECT 35.380 122.700 36.200 122.870 ;
        RECT 36.995 122.775 37.165 123.815 ;
        RECT 37.435 122.775 37.605 123.815 ;
        RECT 38.080 122.770 38.250 123.810 ;
        RECT 38.520 122.770 38.690 123.810 ;
        RECT 40.190 123.425 40.360 123.755 ;
        RECT 40.575 123.725 43.615 123.895 ;
        RECT 40.575 123.285 43.615 123.455 ;
        RECT 35.380 122.260 36.200 122.430 ;
        RECT 37.135 122.390 37.465 122.560 ;
        RECT 37.370 121.700 37.910 121.870 ;
        RECT 35.160 121.150 35.330 121.480 ;
        RECT 35.500 121.450 36.040 121.620 ;
        RECT 35.500 121.010 36.040 121.180 ;
        RECT 36.420 120.310 36.820 121.380 ;
        RECT 37.370 121.260 37.910 121.430 ;
        RECT 38.080 121.270 38.550 122.580 ;
        RECT 40.195 122.340 40.365 122.670 ;
        RECT 40.580 122.640 43.620 122.810 ;
        RECT 40.580 122.200 43.620 122.370 ;
        RECT 40.060 121.660 40.460 121.810 ;
        RECT 43.880 121.660 44.190 123.760 ;
        RECT 44.400 123.730 47.440 123.900 ;
        RECT 44.400 123.290 47.440 123.460 ;
        RECT 47.845 123.430 48.015 123.760 ;
        RECT 48.230 123.730 54.270 123.900 ;
        RECT 48.230 123.290 54.270 123.460 ;
        RECT 60.735 123.120 60.905 123.450 ;
        RECT 61.120 123.420 67.160 123.590 ;
        RECT 61.120 122.980 67.160 123.150 ;
        RECT 67.490 122.690 67.750 124.540 ;
        RECT 67.950 124.510 70.990 124.680 ;
        RECT 67.950 124.070 70.990 124.240 ;
        RECT 71.390 123.900 71.600 124.540 ;
        RECT 72.545 124.510 77.115 124.680 ;
        RECT 72.545 124.070 77.115 124.240 ;
        RECT 78.285 124.210 78.455 124.540 ;
        RECT 78.670 124.510 84.710 124.680 ;
        RECT 78.670 124.070 84.710 124.240 ;
        RECT 71.390 123.650 73.870 123.900 ;
        RECT 71.615 123.000 71.785 123.330 ;
        RECT 72.110 123.300 72.930 123.470 ;
        RECT 73.330 123.440 73.870 123.650 ;
        RECT 84.990 123.610 85.330 124.540 ;
        RECT 85.540 124.510 91.580 124.680 ;
        RECT 85.540 124.070 91.580 124.240 ;
        RECT 92.760 123.980 94.140 124.740 ;
        RECT 94.845 124.210 95.015 124.540 ;
        RECT 95.230 124.510 100.270 124.680 ;
        RECT 95.230 124.070 100.270 124.240 ;
        RECT 72.110 122.860 72.930 123.030 ;
        RECT 78.755 123.010 78.925 123.340 ;
        RECT 79.250 123.310 80.070 123.480 ;
        RECT 81.450 123.080 85.330 123.610 ;
        RECT 92.005 123.140 92.175 123.470 ;
        RECT 92.390 123.440 94.430 123.610 ;
        RECT 79.250 122.870 80.070 123.040 ;
        RECT 92.390 123.000 94.430 123.170 ;
        RECT 67.490 122.620 82.090 122.690 ;
        RECT 62.770 122.420 82.090 122.620 ;
        RECT 44.460 121.800 44.630 122.130 ;
        RECT 44.800 122.100 47.840 122.270 ;
        RECT 44.800 121.660 47.840 121.830 ;
        RECT 48.510 121.800 49.290 122.130 ;
        RECT 49.460 122.100 51.500 122.270 ;
        RECT 40.060 121.440 44.190 121.660 ;
        RECT 48.510 121.440 48.760 121.800 ;
        RECT 49.460 121.660 51.500 121.830 ;
        RECT 62.770 121.620 66.890 122.420 ;
        RECT 67.610 121.780 67.780 122.110 ;
        RECT 67.950 122.080 70.990 122.250 ;
        RECT 67.950 121.640 70.990 121.810 ;
        RECT 71.890 121.750 72.060 122.080 ;
        RECT 72.230 122.050 72.770 122.220 ;
        RECT 40.060 121.350 48.760 121.440 ;
        RECT 38.080 121.240 38.930 121.270 ;
        RECT 38.080 121.050 38.950 121.240 ;
        RECT 38.360 120.930 38.950 121.050 ;
        RECT 43.880 121.200 48.760 121.350 ;
        RECT 38.360 120.890 38.930 120.930 ;
        RECT 37.250 120.400 37.420 120.730 ;
        RECT 37.590 120.700 38.130 120.870 ;
        RECT 41.270 120.490 41.440 120.820 ;
        RECT 41.610 120.790 42.650 120.960 ;
        RECT 43.880 120.820 44.190 121.200 ;
        RECT 37.590 120.260 38.130 120.430 ;
        RECT 41.610 120.350 42.650 120.520 ;
        RECT 43.880 120.490 44.630 120.820 ;
        RECT 44.800 120.790 47.840 120.960 ;
        RECT 44.800 120.350 47.840 120.520 ;
        RECT 49.120 120.490 49.290 120.820 ;
        RECT 49.460 120.790 51.500 120.960 ;
        RECT 49.460 120.350 51.500 120.520 ;
        RECT 43.120 119.930 44.140 120.280 ;
        RECT 61.860 119.980 62.920 121.000 ;
        RECT 63.220 120.770 63.390 121.100 ;
        RECT 63.560 121.070 64.600 121.240 ;
        RECT 63.560 120.630 64.600 120.800 ;
        RECT 64.990 120.410 65.900 121.190 ;
        RECT 66.150 121.100 66.890 121.620 ;
        RECT 72.230 121.610 72.770 121.780 ;
        RECT 74.370 121.670 79.200 122.190 ;
        RECT 79.370 122.060 79.910 122.230 ;
        RECT 66.150 120.770 67.780 121.100 ;
        RECT 67.950 121.070 70.990 121.240 ;
        RECT 67.950 120.630 70.990 120.800 ;
        RECT 71.390 120.430 72.090 121.200 ;
        RECT 74.370 120.770 74.730 121.670 ;
        RECT 79.370 121.620 79.910 121.790 ;
        RECT 81.730 121.780 82.090 122.420 ;
        RECT 82.260 122.080 84.300 122.250 ;
        RECT 115.650 122.190 122.390 122.360 ;
        RECT 82.260 121.640 84.300 121.810 ;
        RECT 74.900 121.070 76.940 121.240 ;
        RECT 74.900 120.630 76.940 120.800 ;
        RECT 81.930 120.770 82.100 121.100 ;
        RECT 82.270 121.070 84.310 121.240 ;
        RECT 85.290 121.050 86.660 122.180 ;
        RECT 82.270 120.630 84.310 120.800 ;
        RECT 86.990 120.430 87.270 121.100 ;
        RECT 87.440 121.070 89.480 121.240 ;
        RECT 87.440 120.630 89.480 120.800 ;
        RECT 92.010 120.770 92.180 121.100 ;
        RECT 92.350 121.070 93.390 121.240 ;
        RECT 92.350 120.630 93.390 120.800 ;
        RECT 96.090 120.770 96.260 121.100 ;
        RECT 96.430 121.070 98.470 121.240 ;
        RECT 96.430 120.630 98.470 120.800 ;
        RECT 71.390 120.130 87.270 120.430 ;
        RECT 115.650 118.820 115.820 122.190 ;
        RECT 119.520 121.790 121.410 121.810 ;
        RECT 116.160 121.300 116.330 121.630 ;
        RECT 116.500 121.620 121.540 121.790 ;
        RECT 116.680 121.310 118.680 121.320 ;
        RECT 116.500 121.140 121.540 121.310 ;
        RECT 116.680 121.130 118.680 121.140 ;
        RECT 119.520 120.830 121.410 120.860 ;
        RECT 116.160 120.340 116.330 120.670 ;
        RECT 116.500 120.660 121.540 120.830 ;
        RECT 121.710 120.820 121.880 121.150 ;
        RECT 116.700 120.350 118.700 120.380 ;
        RECT 116.500 120.180 121.540 120.350 ;
        RECT 119.550 119.870 121.440 119.880 ;
        RECT 116.160 119.380 116.330 119.710 ;
        RECT 116.500 119.700 121.540 119.870 ;
        RECT 121.710 119.860 121.880 120.190 ;
        RECT 119.550 119.690 121.440 119.700 ;
        RECT 116.680 119.390 118.680 119.420 ;
        RECT 116.500 119.220 121.540 119.390 ;
        RECT 122.220 118.820 122.390 122.190 ;
        RECT 126.815 122.135 128.975 122.825 ;
        RECT 115.650 118.650 122.390 118.820 ;
        RECT 126.815 118.625 128.975 119.315 ;
        RECT 69.880 117.660 71.840 117.830 ;
        RECT 45.930 116.880 47.900 117.160 ;
        RECT 60.740 116.855 60.910 117.185 ;
        RECT 61.125 117.155 67.165 117.325 ;
        RECT 61.125 116.715 67.165 116.885 ;
        RECT 36.470 115.820 36.650 116.550 ;
        RECT 34.885 115.050 35.055 115.380 ;
        RECT 35.380 115.350 36.200 115.520 ;
        RECT 36.995 115.425 37.165 116.465 ;
        RECT 37.435 115.425 37.605 116.465 ;
        RECT 38.080 115.420 38.250 116.460 ;
        RECT 38.520 115.420 38.690 116.460 ;
        RECT 40.190 116.075 40.360 116.405 ;
        RECT 40.575 116.375 43.615 116.545 ;
        RECT 40.575 115.935 43.615 116.105 ;
        RECT 35.380 114.910 36.200 115.080 ;
        RECT 37.135 115.040 37.465 115.210 ;
        RECT 37.370 114.350 37.910 114.520 ;
        RECT 35.160 113.800 35.330 114.130 ;
        RECT 35.500 114.100 36.040 114.270 ;
        RECT 35.500 113.660 36.040 113.830 ;
        RECT 36.420 112.960 36.820 114.030 ;
        RECT 37.370 113.910 37.910 114.080 ;
        RECT 38.080 113.920 38.550 115.230 ;
        RECT 40.195 114.990 40.365 115.320 ;
        RECT 40.580 115.290 43.620 115.460 ;
        RECT 40.580 114.850 43.620 115.020 ;
        RECT 40.060 114.310 40.460 114.460 ;
        RECT 43.880 114.310 44.190 116.410 ;
        RECT 44.400 116.380 47.440 116.550 ;
        RECT 44.400 115.940 47.440 116.110 ;
        RECT 47.845 116.080 48.015 116.410 ;
        RECT 48.230 116.380 54.270 116.550 ;
        RECT 48.230 115.940 54.270 116.110 ;
        RECT 60.735 115.770 60.905 116.100 ;
        RECT 61.120 116.070 67.160 116.240 ;
        RECT 61.120 115.630 67.160 115.800 ;
        RECT 67.490 115.340 67.750 117.190 ;
        RECT 67.950 117.160 70.990 117.330 ;
        RECT 67.950 116.720 70.990 116.890 ;
        RECT 71.390 116.550 71.600 117.190 ;
        RECT 72.545 117.160 77.115 117.330 ;
        RECT 72.545 116.720 77.115 116.890 ;
        RECT 78.285 116.860 78.455 117.190 ;
        RECT 78.670 117.160 84.710 117.330 ;
        RECT 78.670 116.720 84.710 116.890 ;
        RECT 71.390 116.300 73.870 116.550 ;
        RECT 71.615 115.650 71.785 115.980 ;
        RECT 72.110 115.950 72.930 116.120 ;
        RECT 73.330 116.090 73.870 116.300 ;
        RECT 84.990 116.260 85.330 117.190 ;
        RECT 85.540 117.160 91.580 117.330 ;
        RECT 85.540 116.720 91.580 116.890 ;
        RECT 92.760 116.630 94.140 117.390 ;
        RECT 94.845 116.860 95.015 117.190 ;
        RECT 95.230 117.160 100.270 117.330 ;
        RECT 95.230 116.720 100.270 116.890 ;
        RECT 129.980 116.770 130.150 128.610 ;
        RECT 130.630 125.970 131.320 128.130 ;
        RECT 130.630 117.250 131.320 119.410 ;
        RECT 131.800 116.770 131.970 128.610 ;
        RECT 129.980 116.600 131.970 116.770 ;
        RECT 72.110 115.510 72.930 115.680 ;
        RECT 78.755 115.660 78.925 115.990 ;
        RECT 79.250 115.960 80.070 116.130 ;
        RECT 81.450 115.730 85.330 116.260 ;
        RECT 92.005 115.790 92.175 116.120 ;
        RECT 92.390 116.090 94.430 116.260 ;
        RECT 114.400 116.000 128.230 116.170 ;
        RECT 79.250 115.520 80.070 115.690 ;
        RECT 92.390 115.650 94.430 115.820 ;
        RECT 67.490 115.270 82.090 115.340 ;
        RECT 62.770 115.070 82.090 115.270 ;
        RECT 44.460 114.450 44.630 114.780 ;
        RECT 44.800 114.750 47.840 114.920 ;
        RECT 44.800 114.310 47.840 114.480 ;
        RECT 48.510 114.450 49.290 114.780 ;
        RECT 49.460 114.750 51.500 114.920 ;
        RECT 40.060 114.090 44.190 114.310 ;
        RECT 48.510 114.090 48.760 114.450 ;
        RECT 49.460 114.310 51.500 114.480 ;
        RECT 62.770 114.270 66.890 115.070 ;
        RECT 67.610 114.430 67.780 114.760 ;
        RECT 67.950 114.730 70.990 114.900 ;
        RECT 67.950 114.290 70.990 114.460 ;
        RECT 71.890 114.400 72.060 114.730 ;
        RECT 72.230 114.700 72.770 114.870 ;
        RECT 40.060 114.000 48.760 114.090 ;
        RECT 38.080 113.890 38.930 113.920 ;
        RECT 38.080 113.700 38.950 113.890 ;
        RECT 38.360 113.580 38.950 113.700 ;
        RECT 43.880 113.850 48.760 114.000 ;
        RECT 38.360 113.540 38.930 113.580 ;
        RECT 37.250 113.050 37.420 113.380 ;
        RECT 37.590 113.350 38.130 113.520 ;
        RECT 41.270 113.140 41.440 113.470 ;
        RECT 41.610 113.440 42.650 113.610 ;
        RECT 43.880 113.470 44.190 113.850 ;
        RECT 37.590 112.910 38.130 113.080 ;
        RECT 41.610 113.000 42.650 113.170 ;
        RECT 43.880 113.140 44.630 113.470 ;
        RECT 44.800 113.440 47.840 113.610 ;
        RECT 44.800 113.000 47.840 113.170 ;
        RECT 49.120 113.140 49.290 113.470 ;
        RECT 49.460 113.440 51.500 113.610 ;
        RECT 49.460 113.000 51.500 113.170 ;
        RECT 43.120 112.580 44.140 112.930 ;
        RECT 61.860 112.630 62.920 113.650 ;
        RECT 63.220 113.420 63.390 113.750 ;
        RECT 63.560 113.720 64.600 113.890 ;
        RECT 63.560 113.280 64.600 113.450 ;
        RECT 64.990 113.060 65.900 113.840 ;
        RECT 66.150 113.750 66.890 114.270 ;
        RECT 72.230 114.260 72.770 114.430 ;
        RECT 74.370 114.320 79.200 114.840 ;
        RECT 79.370 114.710 79.910 114.880 ;
        RECT 66.150 113.420 67.780 113.750 ;
        RECT 67.950 113.720 70.990 113.890 ;
        RECT 67.950 113.280 70.990 113.450 ;
        RECT 71.390 113.080 72.090 113.850 ;
        RECT 74.370 113.420 74.730 114.320 ;
        RECT 79.370 114.270 79.910 114.440 ;
        RECT 81.730 114.430 82.090 115.070 ;
        RECT 82.260 114.730 84.300 114.900 ;
        RECT 82.260 114.290 84.300 114.460 ;
        RECT 74.900 113.720 76.940 113.890 ;
        RECT 74.900 113.280 76.940 113.450 ;
        RECT 81.930 113.420 82.100 113.750 ;
        RECT 82.270 113.720 84.310 113.890 ;
        RECT 85.290 113.700 86.660 114.830 ;
        RECT 82.270 113.280 84.310 113.450 ;
        RECT 86.990 113.080 87.270 113.750 ;
        RECT 87.440 113.720 89.480 113.890 ;
        RECT 87.440 113.280 89.480 113.450 ;
        RECT 92.010 113.420 92.180 113.750 ;
        RECT 92.350 113.720 93.390 113.890 ;
        RECT 92.350 113.280 93.390 113.450 ;
        RECT 96.090 113.420 96.260 113.750 ;
        RECT 96.430 113.720 98.470 113.890 ;
        RECT 96.430 113.280 98.470 113.450 ;
        RECT 71.390 112.780 87.270 113.080 ;
        RECT 114.400 112.630 114.570 116.000 ;
        RECT 114.910 115.110 115.080 115.440 ;
        RECT 115.295 115.430 127.335 115.600 ;
        RECT 115.400 115.120 121.350 115.130 ;
        RECT 115.295 114.950 127.335 115.120 ;
        RECT 114.910 114.150 115.080 114.480 ;
        RECT 115.295 114.470 127.335 114.640 ;
        RECT 127.550 114.630 127.720 114.960 ;
        RECT 115.295 113.990 127.335 114.160 ;
        RECT 114.910 113.190 115.080 113.520 ;
        RECT 115.295 113.510 127.335 113.680 ;
        RECT 127.550 113.670 127.720 114.000 ;
        RECT 115.295 113.030 127.335 113.200 ;
        RECT 128.060 112.630 128.230 116.000 ;
        RECT 114.400 112.460 128.230 112.630 ;
        RECT 129.980 116.070 131.970 116.240 ;
        RECT 69.880 110.310 71.840 110.480 ;
        RECT 45.930 109.530 47.900 109.810 ;
        RECT 60.740 109.505 60.910 109.835 ;
        RECT 61.125 109.805 67.165 109.975 ;
        RECT 61.125 109.365 67.165 109.535 ;
        RECT 36.470 108.470 36.650 109.200 ;
        RECT 34.885 107.700 35.055 108.030 ;
        RECT 35.380 108.000 36.200 108.170 ;
        RECT 36.995 108.075 37.165 109.115 ;
        RECT 37.435 108.075 37.605 109.115 ;
        RECT 38.080 108.070 38.250 109.110 ;
        RECT 38.520 108.070 38.690 109.110 ;
        RECT 40.190 108.725 40.360 109.055 ;
        RECT 40.575 109.025 43.615 109.195 ;
        RECT 40.575 108.585 43.615 108.755 ;
        RECT 35.380 107.560 36.200 107.730 ;
        RECT 37.135 107.690 37.465 107.860 ;
        RECT 37.370 107.000 37.910 107.170 ;
        RECT 35.160 106.450 35.330 106.780 ;
        RECT 35.500 106.750 36.040 106.920 ;
        RECT 35.500 106.310 36.040 106.480 ;
        RECT 36.420 105.610 36.820 106.680 ;
        RECT 37.370 106.560 37.910 106.730 ;
        RECT 38.080 106.570 38.550 107.880 ;
        RECT 40.195 107.640 40.365 107.970 ;
        RECT 40.580 107.940 43.620 108.110 ;
        RECT 40.580 107.500 43.620 107.670 ;
        RECT 40.060 106.960 40.460 107.110 ;
        RECT 43.880 106.960 44.190 109.060 ;
        RECT 44.400 109.030 47.440 109.200 ;
        RECT 44.400 108.590 47.440 108.760 ;
        RECT 47.845 108.730 48.015 109.060 ;
        RECT 48.230 109.030 54.270 109.200 ;
        RECT 48.230 108.590 54.270 108.760 ;
        RECT 60.735 108.420 60.905 108.750 ;
        RECT 61.120 108.720 67.160 108.890 ;
        RECT 61.120 108.280 67.160 108.450 ;
        RECT 67.490 107.990 67.750 109.840 ;
        RECT 67.950 109.810 70.990 109.980 ;
        RECT 67.950 109.370 70.990 109.540 ;
        RECT 71.390 109.200 71.600 109.840 ;
        RECT 72.545 109.810 77.115 109.980 ;
        RECT 72.545 109.370 77.115 109.540 ;
        RECT 78.285 109.510 78.455 109.840 ;
        RECT 78.670 109.810 84.710 109.980 ;
        RECT 78.670 109.370 84.710 109.540 ;
        RECT 71.390 108.950 73.870 109.200 ;
        RECT 71.615 108.300 71.785 108.630 ;
        RECT 72.110 108.600 72.930 108.770 ;
        RECT 73.330 108.740 73.870 108.950 ;
        RECT 84.990 108.910 85.330 109.840 ;
        RECT 85.540 109.810 91.580 109.980 ;
        RECT 85.540 109.370 91.580 109.540 ;
        RECT 92.760 109.280 94.140 110.040 ;
        RECT 94.845 109.510 95.015 109.840 ;
        RECT 95.230 109.810 100.270 109.980 ;
        RECT 115.650 109.650 122.390 109.820 ;
        RECT 95.230 109.370 100.270 109.540 ;
        RECT 72.110 108.160 72.930 108.330 ;
        RECT 78.755 108.310 78.925 108.640 ;
        RECT 79.250 108.610 80.070 108.780 ;
        RECT 81.450 108.380 85.330 108.910 ;
        RECT 92.005 108.440 92.175 108.770 ;
        RECT 92.390 108.740 94.430 108.910 ;
        RECT 79.250 108.170 80.070 108.340 ;
        RECT 92.390 108.300 94.430 108.470 ;
        RECT 67.490 107.920 82.090 107.990 ;
        RECT 62.770 107.720 82.090 107.920 ;
        RECT 44.460 107.100 44.630 107.430 ;
        RECT 44.800 107.400 47.840 107.570 ;
        RECT 44.800 106.960 47.840 107.130 ;
        RECT 48.510 107.100 49.290 107.430 ;
        RECT 49.460 107.400 51.500 107.570 ;
        RECT 40.060 106.740 44.190 106.960 ;
        RECT 48.510 106.740 48.760 107.100 ;
        RECT 49.460 106.960 51.500 107.130 ;
        RECT 62.770 106.920 66.890 107.720 ;
        RECT 67.610 107.080 67.780 107.410 ;
        RECT 67.950 107.380 70.990 107.550 ;
        RECT 67.950 106.940 70.990 107.110 ;
        RECT 71.890 107.050 72.060 107.380 ;
        RECT 72.230 107.350 72.770 107.520 ;
        RECT 40.060 106.650 48.760 106.740 ;
        RECT 38.080 106.540 38.930 106.570 ;
        RECT 38.080 106.350 38.950 106.540 ;
        RECT 38.360 106.230 38.950 106.350 ;
        RECT 43.880 106.500 48.760 106.650 ;
        RECT 38.360 106.190 38.930 106.230 ;
        RECT 37.250 105.700 37.420 106.030 ;
        RECT 37.590 106.000 38.130 106.170 ;
        RECT 41.270 105.790 41.440 106.120 ;
        RECT 41.610 106.090 42.650 106.260 ;
        RECT 43.880 106.120 44.190 106.500 ;
        RECT 37.590 105.560 38.130 105.730 ;
        RECT 41.610 105.650 42.650 105.820 ;
        RECT 43.880 105.790 44.630 106.120 ;
        RECT 44.800 106.090 47.840 106.260 ;
        RECT 44.800 105.650 47.840 105.820 ;
        RECT 49.120 105.790 49.290 106.120 ;
        RECT 49.460 106.090 51.500 106.260 ;
        RECT 49.460 105.650 51.500 105.820 ;
        RECT 43.120 105.230 44.140 105.580 ;
        RECT 61.860 105.280 62.920 106.300 ;
        RECT 63.220 106.070 63.390 106.400 ;
        RECT 63.560 106.370 64.600 106.540 ;
        RECT 63.560 105.930 64.600 106.100 ;
        RECT 64.990 105.710 65.900 106.490 ;
        RECT 66.150 106.400 66.890 106.920 ;
        RECT 72.230 106.910 72.770 107.080 ;
        RECT 74.370 106.970 79.200 107.490 ;
        RECT 79.370 107.360 79.910 107.530 ;
        RECT 66.150 106.070 67.780 106.400 ;
        RECT 67.950 106.370 70.990 106.540 ;
        RECT 67.950 105.930 70.990 106.100 ;
        RECT 71.390 105.730 72.090 106.500 ;
        RECT 74.370 106.070 74.730 106.970 ;
        RECT 79.370 106.920 79.910 107.090 ;
        RECT 81.730 107.080 82.090 107.720 ;
        RECT 82.260 107.380 84.300 107.550 ;
        RECT 82.260 106.940 84.300 107.110 ;
        RECT 74.900 106.370 76.940 106.540 ;
        RECT 74.900 105.930 76.940 106.100 ;
        RECT 81.930 106.070 82.100 106.400 ;
        RECT 82.270 106.370 84.310 106.540 ;
        RECT 85.290 106.350 86.660 107.480 ;
        RECT 82.270 105.930 84.310 106.100 ;
        RECT 86.990 105.730 87.270 106.400 ;
        RECT 87.440 106.370 89.480 106.540 ;
        RECT 87.440 105.930 89.480 106.100 ;
        RECT 92.010 106.070 92.180 106.400 ;
        RECT 92.350 106.370 93.390 106.540 ;
        RECT 92.350 105.930 93.390 106.100 ;
        RECT 96.090 106.070 96.260 106.400 ;
        RECT 96.430 106.370 98.470 106.540 ;
        RECT 115.650 106.280 115.820 109.650 ;
        RECT 119.520 109.250 121.410 109.270 ;
        RECT 116.160 108.760 116.330 109.090 ;
        RECT 116.500 109.080 121.540 109.250 ;
        RECT 116.680 108.770 118.680 108.780 ;
        RECT 116.500 108.600 121.540 108.770 ;
        RECT 116.680 108.590 118.680 108.600 ;
        RECT 119.520 108.290 121.410 108.320 ;
        RECT 116.160 107.800 116.330 108.130 ;
        RECT 116.500 108.120 121.540 108.290 ;
        RECT 121.710 108.280 121.880 108.610 ;
        RECT 116.700 107.810 118.700 107.840 ;
        RECT 116.500 107.640 121.540 107.810 ;
        RECT 119.550 107.330 121.440 107.340 ;
        RECT 116.160 106.840 116.330 107.170 ;
        RECT 116.500 107.160 121.540 107.330 ;
        RECT 121.710 107.320 121.880 107.650 ;
        RECT 119.550 107.150 121.440 107.160 ;
        RECT 116.680 106.850 118.680 106.880 ;
        RECT 116.500 106.680 121.540 106.850 ;
        RECT 122.220 106.280 122.390 109.650 ;
        RECT 126.815 109.595 128.975 110.285 ;
        RECT 115.650 106.110 122.390 106.280 ;
        RECT 96.430 105.930 98.470 106.100 ;
        RECT 126.815 106.085 128.975 106.775 ;
        RECT 71.390 105.430 87.270 105.730 ;
        RECT 129.980 104.230 130.150 116.070 ;
        RECT 130.630 113.430 131.320 115.590 ;
        RECT 130.630 104.710 131.320 106.870 ;
        RECT 131.800 104.230 131.970 116.070 ;
        RECT 129.980 104.060 131.970 104.230 ;
        RECT 114.400 103.460 128.230 103.630 ;
        RECT 69.880 102.960 71.840 103.130 ;
        RECT 45.930 102.180 47.900 102.460 ;
        RECT 60.740 102.155 60.910 102.485 ;
        RECT 61.125 102.455 67.165 102.625 ;
        RECT 61.125 102.015 67.165 102.185 ;
        RECT 36.470 101.120 36.650 101.850 ;
        RECT 34.885 100.350 35.055 100.680 ;
        RECT 35.380 100.650 36.200 100.820 ;
        RECT 36.995 100.725 37.165 101.765 ;
        RECT 37.435 100.725 37.605 101.765 ;
        RECT 38.080 100.720 38.250 101.760 ;
        RECT 38.520 100.720 38.690 101.760 ;
        RECT 40.190 101.375 40.360 101.705 ;
        RECT 40.575 101.675 43.615 101.845 ;
        RECT 40.575 101.235 43.615 101.405 ;
        RECT 35.380 100.210 36.200 100.380 ;
        RECT 37.135 100.340 37.465 100.510 ;
        RECT 37.370 99.650 37.910 99.820 ;
        RECT 35.160 99.100 35.330 99.430 ;
        RECT 35.500 99.400 36.040 99.570 ;
        RECT 35.500 98.960 36.040 99.130 ;
        RECT 36.420 98.260 36.820 99.330 ;
        RECT 37.370 99.210 37.910 99.380 ;
        RECT 38.080 99.220 38.550 100.530 ;
        RECT 40.195 100.290 40.365 100.620 ;
        RECT 40.580 100.590 43.620 100.760 ;
        RECT 40.580 100.150 43.620 100.320 ;
        RECT 40.060 99.610 40.460 99.760 ;
        RECT 43.880 99.610 44.190 101.710 ;
        RECT 44.400 101.680 47.440 101.850 ;
        RECT 44.400 101.240 47.440 101.410 ;
        RECT 47.845 101.380 48.015 101.710 ;
        RECT 48.230 101.680 54.270 101.850 ;
        RECT 48.230 101.240 54.270 101.410 ;
        RECT 60.735 101.070 60.905 101.400 ;
        RECT 61.120 101.370 67.160 101.540 ;
        RECT 61.120 100.930 67.160 101.100 ;
        RECT 67.490 100.640 67.750 102.490 ;
        RECT 67.950 102.460 70.990 102.630 ;
        RECT 67.950 102.020 70.990 102.190 ;
        RECT 71.390 101.850 71.600 102.490 ;
        RECT 72.545 102.460 77.115 102.630 ;
        RECT 72.545 102.020 77.115 102.190 ;
        RECT 78.285 102.160 78.455 102.490 ;
        RECT 78.670 102.460 84.710 102.630 ;
        RECT 78.670 102.020 84.710 102.190 ;
        RECT 71.390 101.600 73.870 101.850 ;
        RECT 71.615 100.950 71.785 101.280 ;
        RECT 72.110 101.250 72.930 101.420 ;
        RECT 73.330 101.390 73.870 101.600 ;
        RECT 84.990 101.560 85.330 102.490 ;
        RECT 85.540 102.460 91.580 102.630 ;
        RECT 85.540 102.020 91.580 102.190 ;
        RECT 92.760 101.930 94.140 102.690 ;
        RECT 94.845 102.160 95.015 102.490 ;
        RECT 95.230 102.460 100.270 102.630 ;
        RECT 95.230 102.020 100.270 102.190 ;
        RECT 72.110 100.810 72.930 100.980 ;
        RECT 78.755 100.960 78.925 101.290 ;
        RECT 79.250 101.260 80.070 101.430 ;
        RECT 81.450 101.030 85.330 101.560 ;
        RECT 92.005 101.090 92.175 101.420 ;
        RECT 92.390 101.390 94.430 101.560 ;
        RECT 79.250 100.820 80.070 100.990 ;
        RECT 92.390 100.950 94.430 101.120 ;
        RECT 67.490 100.570 82.090 100.640 ;
        RECT 62.770 100.370 82.090 100.570 ;
        RECT 44.460 99.750 44.630 100.080 ;
        RECT 44.800 100.050 47.840 100.220 ;
        RECT 44.800 99.610 47.840 99.780 ;
        RECT 48.510 99.750 49.290 100.080 ;
        RECT 49.460 100.050 51.500 100.220 ;
        RECT 40.060 99.390 44.190 99.610 ;
        RECT 48.510 99.390 48.760 99.750 ;
        RECT 49.460 99.610 51.500 99.780 ;
        RECT 62.770 99.570 66.890 100.370 ;
        RECT 67.610 99.730 67.780 100.060 ;
        RECT 67.950 100.030 70.990 100.200 ;
        RECT 67.950 99.590 70.990 99.760 ;
        RECT 71.890 99.700 72.060 100.030 ;
        RECT 72.230 100.000 72.770 100.170 ;
        RECT 40.060 99.300 48.760 99.390 ;
        RECT 38.080 99.190 38.930 99.220 ;
        RECT 38.080 99.000 38.950 99.190 ;
        RECT 38.360 98.880 38.950 99.000 ;
        RECT 43.880 99.150 48.760 99.300 ;
        RECT 38.360 98.840 38.930 98.880 ;
        RECT 37.250 98.350 37.420 98.680 ;
        RECT 37.590 98.650 38.130 98.820 ;
        RECT 41.270 98.440 41.440 98.770 ;
        RECT 41.610 98.740 42.650 98.910 ;
        RECT 43.880 98.770 44.190 99.150 ;
        RECT 37.590 98.210 38.130 98.380 ;
        RECT 41.610 98.300 42.650 98.470 ;
        RECT 43.880 98.440 44.630 98.770 ;
        RECT 44.800 98.740 47.840 98.910 ;
        RECT 44.800 98.300 47.840 98.470 ;
        RECT 49.120 98.440 49.290 98.770 ;
        RECT 49.460 98.740 51.500 98.910 ;
        RECT 49.460 98.300 51.500 98.470 ;
        RECT 43.120 97.880 44.140 98.230 ;
        RECT 61.860 97.930 62.920 98.950 ;
        RECT 63.220 98.720 63.390 99.050 ;
        RECT 63.560 99.020 64.600 99.190 ;
        RECT 63.560 98.580 64.600 98.750 ;
        RECT 64.990 98.360 65.900 99.140 ;
        RECT 66.150 99.050 66.890 99.570 ;
        RECT 72.230 99.560 72.770 99.730 ;
        RECT 74.370 99.620 79.200 100.140 ;
        RECT 79.370 100.010 79.910 100.180 ;
        RECT 66.150 98.720 67.780 99.050 ;
        RECT 67.950 99.020 70.990 99.190 ;
        RECT 67.950 98.580 70.990 98.750 ;
        RECT 71.390 98.380 72.090 99.150 ;
        RECT 74.370 98.720 74.730 99.620 ;
        RECT 79.370 99.570 79.910 99.740 ;
        RECT 81.730 99.730 82.090 100.370 ;
        RECT 82.260 100.030 84.300 100.200 ;
        RECT 82.260 99.590 84.300 99.760 ;
        RECT 74.900 99.020 76.940 99.190 ;
        RECT 74.900 98.580 76.940 98.750 ;
        RECT 81.930 98.720 82.100 99.050 ;
        RECT 82.270 99.020 84.310 99.190 ;
        RECT 85.290 99.000 86.660 100.130 ;
        RECT 114.400 100.090 114.570 103.460 ;
        RECT 114.910 102.570 115.080 102.900 ;
        RECT 115.295 102.890 127.335 103.060 ;
        RECT 115.400 102.580 121.350 102.590 ;
        RECT 115.295 102.410 127.335 102.580 ;
        RECT 114.910 101.610 115.080 101.940 ;
        RECT 115.295 101.930 127.335 102.100 ;
        RECT 127.550 102.090 127.720 102.420 ;
        RECT 115.295 101.450 127.335 101.620 ;
        RECT 114.910 100.650 115.080 100.980 ;
        RECT 115.295 100.970 127.335 101.140 ;
        RECT 127.550 101.130 127.720 101.460 ;
        RECT 115.295 100.490 127.335 100.660 ;
        RECT 128.060 100.090 128.230 103.460 ;
        RECT 114.400 99.920 128.230 100.090 ;
        RECT 129.980 103.530 131.970 103.700 ;
        RECT 82.270 98.580 84.310 98.750 ;
        RECT 86.990 98.380 87.270 99.050 ;
        RECT 87.440 99.020 89.480 99.190 ;
        RECT 87.440 98.580 89.480 98.750 ;
        RECT 92.010 98.720 92.180 99.050 ;
        RECT 92.350 99.020 93.390 99.190 ;
        RECT 92.350 98.580 93.390 98.750 ;
        RECT 96.090 98.720 96.260 99.050 ;
        RECT 96.430 99.020 98.470 99.190 ;
        RECT 96.430 98.580 98.470 98.750 ;
        RECT 71.390 98.080 87.270 98.380 ;
        RECT 115.650 97.110 122.390 97.280 ;
        RECT 69.880 95.610 71.840 95.780 ;
        RECT 45.930 94.830 47.900 95.110 ;
        RECT 60.740 94.805 60.910 95.135 ;
        RECT 61.125 95.105 67.165 95.275 ;
        RECT 61.125 94.665 67.165 94.835 ;
        RECT 36.470 93.770 36.650 94.500 ;
        RECT 34.885 93.000 35.055 93.330 ;
        RECT 35.380 93.300 36.200 93.470 ;
        RECT 36.995 93.375 37.165 94.415 ;
        RECT 37.435 93.375 37.605 94.415 ;
        RECT 38.080 93.370 38.250 94.410 ;
        RECT 38.520 93.370 38.690 94.410 ;
        RECT 40.190 94.025 40.360 94.355 ;
        RECT 40.575 94.325 43.615 94.495 ;
        RECT 40.575 93.885 43.615 94.055 ;
        RECT 35.380 92.860 36.200 93.030 ;
        RECT 37.135 92.990 37.465 93.160 ;
        RECT 37.370 92.300 37.910 92.470 ;
        RECT 35.160 91.750 35.330 92.080 ;
        RECT 35.500 92.050 36.040 92.220 ;
        RECT 35.500 91.610 36.040 91.780 ;
        RECT 36.420 90.910 36.820 91.980 ;
        RECT 37.370 91.860 37.910 92.030 ;
        RECT 38.080 91.870 38.550 93.180 ;
        RECT 40.195 92.940 40.365 93.270 ;
        RECT 40.580 93.240 43.620 93.410 ;
        RECT 40.580 92.800 43.620 92.970 ;
        RECT 40.060 92.260 40.460 92.410 ;
        RECT 43.880 92.260 44.190 94.360 ;
        RECT 44.400 94.330 47.440 94.500 ;
        RECT 44.400 93.890 47.440 94.060 ;
        RECT 47.845 94.030 48.015 94.360 ;
        RECT 48.230 94.330 54.270 94.500 ;
        RECT 48.230 93.890 54.270 94.060 ;
        RECT 60.735 93.720 60.905 94.050 ;
        RECT 61.120 94.020 67.160 94.190 ;
        RECT 61.120 93.580 67.160 93.750 ;
        RECT 67.490 93.290 67.750 95.140 ;
        RECT 67.950 95.110 70.990 95.280 ;
        RECT 67.950 94.670 70.990 94.840 ;
        RECT 71.390 94.500 71.600 95.140 ;
        RECT 72.545 95.110 77.115 95.280 ;
        RECT 72.545 94.670 77.115 94.840 ;
        RECT 78.285 94.810 78.455 95.140 ;
        RECT 78.670 95.110 84.710 95.280 ;
        RECT 78.670 94.670 84.710 94.840 ;
        RECT 71.390 94.250 73.870 94.500 ;
        RECT 71.615 93.600 71.785 93.930 ;
        RECT 72.110 93.900 72.930 94.070 ;
        RECT 73.330 94.040 73.870 94.250 ;
        RECT 84.990 94.210 85.330 95.140 ;
        RECT 85.540 95.110 91.580 95.280 ;
        RECT 85.540 94.670 91.580 94.840 ;
        RECT 92.760 94.580 94.140 95.340 ;
        RECT 94.845 94.810 95.015 95.140 ;
        RECT 95.230 95.110 100.270 95.280 ;
        RECT 95.230 94.670 100.270 94.840 ;
        RECT 72.110 93.460 72.930 93.630 ;
        RECT 78.755 93.610 78.925 93.940 ;
        RECT 79.250 93.910 80.070 94.080 ;
        RECT 81.450 93.680 85.330 94.210 ;
        RECT 92.005 93.740 92.175 94.070 ;
        RECT 92.390 94.040 94.430 94.210 ;
        RECT 79.250 93.470 80.070 93.640 ;
        RECT 92.390 93.600 94.430 93.770 ;
        RECT 115.650 93.740 115.820 97.110 ;
        RECT 119.520 96.710 121.410 96.730 ;
        RECT 116.160 96.220 116.330 96.550 ;
        RECT 116.500 96.540 121.540 96.710 ;
        RECT 116.680 96.230 118.680 96.240 ;
        RECT 116.500 96.060 121.540 96.230 ;
        RECT 116.680 96.050 118.680 96.060 ;
        RECT 119.520 95.750 121.410 95.780 ;
        RECT 116.160 95.260 116.330 95.590 ;
        RECT 116.500 95.580 121.540 95.750 ;
        RECT 121.710 95.740 121.880 96.070 ;
        RECT 116.700 95.270 118.700 95.300 ;
        RECT 116.500 95.100 121.540 95.270 ;
        RECT 119.550 94.790 121.440 94.800 ;
        RECT 116.160 94.300 116.330 94.630 ;
        RECT 116.500 94.620 121.540 94.790 ;
        RECT 121.710 94.780 121.880 95.110 ;
        RECT 119.550 94.610 121.440 94.620 ;
        RECT 116.680 94.310 118.680 94.340 ;
        RECT 116.500 94.140 121.540 94.310 ;
        RECT 122.220 93.740 122.390 97.110 ;
        RECT 126.815 97.055 128.975 97.745 ;
        RECT 115.650 93.570 122.390 93.740 ;
        RECT 126.815 93.545 128.975 94.235 ;
        RECT 67.490 93.220 82.090 93.290 ;
        RECT 62.770 93.020 82.090 93.220 ;
        RECT 44.460 92.400 44.630 92.730 ;
        RECT 44.800 92.700 47.840 92.870 ;
        RECT 44.800 92.260 47.840 92.430 ;
        RECT 48.510 92.400 49.290 92.730 ;
        RECT 49.460 92.700 51.500 92.870 ;
        RECT 40.060 92.040 44.190 92.260 ;
        RECT 48.510 92.040 48.760 92.400 ;
        RECT 49.460 92.260 51.500 92.430 ;
        RECT 62.770 92.220 66.890 93.020 ;
        RECT 67.610 92.380 67.780 92.710 ;
        RECT 67.950 92.680 70.990 92.850 ;
        RECT 67.950 92.240 70.990 92.410 ;
        RECT 71.890 92.350 72.060 92.680 ;
        RECT 72.230 92.650 72.770 92.820 ;
        RECT 40.060 91.950 48.760 92.040 ;
        RECT 38.080 91.840 38.930 91.870 ;
        RECT 38.080 91.650 38.950 91.840 ;
        RECT 38.360 91.530 38.950 91.650 ;
        RECT 43.880 91.800 48.760 91.950 ;
        RECT 38.360 91.490 38.930 91.530 ;
        RECT 37.250 91.000 37.420 91.330 ;
        RECT 37.590 91.300 38.130 91.470 ;
        RECT 41.270 91.090 41.440 91.420 ;
        RECT 41.610 91.390 42.650 91.560 ;
        RECT 43.880 91.420 44.190 91.800 ;
        RECT 37.590 90.860 38.130 91.030 ;
        RECT 41.610 90.950 42.650 91.120 ;
        RECT 43.880 91.090 44.630 91.420 ;
        RECT 44.800 91.390 47.840 91.560 ;
        RECT 44.800 90.950 47.840 91.120 ;
        RECT 49.120 91.090 49.290 91.420 ;
        RECT 49.460 91.390 51.500 91.560 ;
        RECT 49.460 90.950 51.500 91.120 ;
        RECT 43.120 90.530 44.140 90.880 ;
        RECT 61.860 90.580 62.920 91.600 ;
        RECT 63.220 91.370 63.390 91.700 ;
        RECT 63.560 91.670 64.600 91.840 ;
        RECT 63.560 91.230 64.600 91.400 ;
        RECT 64.990 91.010 65.900 91.790 ;
        RECT 66.150 91.700 66.890 92.220 ;
        RECT 72.230 92.210 72.770 92.380 ;
        RECT 74.370 92.270 79.200 92.790 ;
        RECT 79.370 92.660 79.910 92.830 ;
        RECT 66.150 91.370 67.780 91.700 ;
        RECT 67.950 91.670 70.990 91.840 ;
        RECT 67.950 91.230 70.990 91.400 ;
        RECT 71.390 91.030 72.090 91.800 ;
        RECT 74.370 91.370 74.730 92.270 ;
        RECT 79.370 92.220 79.910 92.390 ;
        RECT 81.730 92.380 82.090 93.020 ;
        RECT 82.260 92.680 84.300 92.850 ;
        RECT 82.260 92.240 84.300 92.410 ;
        RECT 74.900 91.670 76.940 91.840 ;
        RECT 74.900 91.230 76.940 91.400 ;
        RECT 81.930 91.370 82.100 91.700 ;
        RECT 82.270 91.670 84.310 91.840 ;
        RECT 85.290 91.650 86.660 92.780 ;
        RECT 82.270 91.230 84.310 91.400 ;
        RECT 86.990 91.030 87.270 91.700 ;
        RECT 87.440 91.670 89.480 91.840 ;
        RECT 87.440 91.230 89.480 91.400 ;
        RECT 92.010 91.370 92.180 91.700 ;
        RECT 92.350 91.670 93.390 91.840 ;
        RECT 92.350 91.230 93.390 91.400 ;
        RECT 96.090 91.370 96.260 91.700 ;
        RECT 96.430 91.670 98.470 91.840 ;
        RECT 129.980 91.690 130.150 103.530 ;
        RECT 130.630 100.890 131.320 103.050 ;
        RECT 130.630 92.170 131.320 94.330 ;
        RECT 131.800 91.690 131.970 103.530 ;
        RECT 129.980 91.520 131.970 91.690 ;
        RECT 96.430 91.230 98.470 91.400 ;
        RECT 71.390 90.730 87.270 91.030 ;
        RECT 114.400 90.920 128.230 91.090 ;
        RECT 69.875 88.255 71.835 88.425 ;
        RECT 60.735 87.450 60.905 87.780 ;
        RECT 61.120 87.750 67.160 87.920 ;
        RECT 61.120 87.310 67.160 87.480 ;
        RECT 45.960 87.030 47.330 87.240 ;
        RECT 35.850 86.800 36.180 86.970 ;
        RECT 34.950 85.280 35.370 86.480 ;
        RECT 35.710 86.090 35.880 86.630 ;
        RECT 36.150 86.090 36.320 86.630 ;
        RECT 38.380 86.525 38.710 86.695 ;
        RECT 35.710 85.120 35.880 85.660 ;
        RECT 36.150 85.120 36.320 85.660 ;
        RECT 37.150 85.460 37.320 86.500 ;
        RECT 37.590 85.460 37.760 86.500 ;
        RECT 38.240 85.270 38.410 86.310 ;
        RECT 38.680 85.270 38.850 86.310 ;
        RECT 37.290 84.950 37.620 85.250 ;
        RECT 39.180 85.160 39.470 86.610 ;
        RECT 40.185 86.230 40.355 86.560 ;
        RECT 40.570 86.530 43.610 86.700 ;
        RECT 40.570 86.090 43.610 86.260 ;
        RECT 44.010 85.810 44.190 86.560 ;
        RECT 44.400 86.530 47.440 86.700 ;
        RECT 44.400 86.090 47.440 86.260 ;
        RECT 47.845 86.230 48.015 86.560 ;
        RECT 48.230 86.530 54.270 86.700 ;
        RECT 60.730 86.365 60.900 86.695 ;
        RECT 61.115 86.665 67.155 86.835 ;
        RECT 48.230 86.090 54.270 86.260 ;
        RECT 61.115 86.225 67.155 86.395 ;
        RECT 67.485 85.935 67.745 87.785 ;
        RECT 67.945 87.755 70.985 87.925 ;
        RECT 67.945 87.315 70.985 87.485 ;
        RECT 71.385 87.145 71.595 87.785 ;
        RECT 72.540 87.755 77.110 87.925 ;
        RECT 72.540 87.315 77.110 87.485 ;
        RECT 78.280 87.455 78.450 87.785 ;
        RECT 78.665 87.755 84.705 87.925 ;
        RECT 78.665 87.315 84.705 87.485 ;
        RECT 71.385 86.895 73.865 87.145 ;
        RECT 71.610 86.245 71.780 86.575 ;
        RECT 72.105 86.545 72.925 86.715 ;
        RECT 73.325 86.685 73.865 86.895 ;
        RECT 84.985 86.855 85.325 87.785 ;
        RECT 85.535 87.755 91.575 87.925 ;
        RECT 85.535 87.315 91.575 87.485 ;
        RECT 92.755 87.225 94.135 87.985 ;
        RECT 94.840 87.455 95.010 87.785 ;
        RECT 95.225 87.755 100.265 87.925 ;
        RECT 114.400 87.550 114.570 90.920 ;
        RECT 114.910 90.030 115.080 90.360 ;
        RECT 115.295 90.350 127.335 90.520 ;
        RECT 115.400 90.040 121.350 90.050 ;
        RECT 115.295 89.870 127.335 90.040 ;
        RECT 114.910 89.070 115.080 89.400 ;
        RECT 115.295 89.390 127.335 89.560 ;
        RECT 127.550 89.550 127.720 89.880 ;
        RECT 115.295 88.910 127.335 89.080 ;
        RECT 114.910 88.110 115.080 88.440 ;
        RECT 115.295 88.430 127.335 88.600 ;
        RECT 127.550 88.590 127.720 88.920 ;
        RECT 115.295 87.950 127.335 88.120 ;
        RECT 128.060 87.550 128.230 90.920 ;
        RECT 95.225 87.315 100.265 87.485 ;
        RECT 114.400 87.380 128.230 87.550 ;
        RECT 129.980 90.990 131.970 91.160 ;
        RECT 72.105 86.105 72.925 86.275 ;
        RECT 78.750 86.255 78.920 86.585 ;
        RECT 79.245 86.555 80.065 86.725 ;
        RECT 81.445 86.325 85.325 86.855 ;
        RECT 92.000 86.385 92.170 86.715 ;
        RECT 92.385 86.685 94.425 86.855 ;
        RECT 79.245 86.115 80.065 86.285 ;
        RECT 92.385 86.245 94.425 86.415 ;
        RECT 67.485 85.865 82.085 85.935 ;
        RECT 35.840 84.680 37.620 84.950 ;
        RECT 37.920 84.100 38.290 85.060 ;
        RECT 40.180 84.770 40.350 85.480 ;
        RECT 40.565 85.445 43.605 85.615 ;
        RECT 43.930 85.500 49.110 85.810 ;
        RECT 40.565 85.005 43.605 85.175 ;
        RECT 43.930 84.770 44.260 85.500 ;
        RECT 40.180 84.680 44.260 84.770 ;
        RECT 44.650 84.740 44.820 85.070 ;
        RECT 44.990 85.040 48.030 85.210 ;
        RECT 35.930 83.730 38.290 84.100 ;
        RECT 38.940 84.390 44.260 84.680 ;
        RECT 44.990 84.600 48.030 84.770 ;
        RECT 48.940 84.740 49.110 85.500 ;
        RECT 62.765 85.665 82.085 85.865 ;
        RECT 49.280 85.040 51.320 85.210 ;
        RECT 62.765 84.865 66.885 85.665 ;
        RECT 67.605 85.025 67.775 85.355 ;
        RECT 67.945 85.325 70.985 85.495 ;
        RECT 67.945 84.885 70.985 85.055 ;
        RECT 71.885 84.995 72.055 85.325 ;
        RECT 72.225 85.295 72.765 85.465 ;
        RECT 49.280 84.600 51.320 84.770 ;
        RECT 38.940 83.680 39.940 84.390 ;
        RECT 41.240 83.710 41.410 84.040 ;
        RECT 41.580 84.010 42.620 84.180 ;
        RECT 41.580 83.570 42.620 83.740 ;
        RECT 42.990 83.600 43.730 84.190 ;
        RECT 43.930 84.040 44.260 84.390 ;
        RECT 43.930 83.710 44.820 84.040 ;
        RECT 44.990 84.010 48.030 84.180 ;
        RECT 44.990 83.570 48.030 83.740 ;
        RECT 48.940 83.710 49.110 84.040 ;
        RECT 49.280 84.010 51.320 84.180 ;
        RECT 49.280 83.570 51.320 83.740 ;
        RECT 61.855 83.225 62.915 84.245 ;
        RECT 63.215 84.015 63.385 84.345 ;
        RECT 63.555 84.315 64.595 84.485 ;
        RECT 63.555 83.875 64.595 84.045 ;
        RECT 64.985 83.655 65.895 84.435 ;
        RECT 66.145 84.345 66.885 84.865 ;
        RECT 72.225 84.855 72.765 85.025 ;
        RECT 74.365 84.915 79.195 85.435 ;
        RECT 79.365 85.305 79.905 85.475 ;
        RECT 66.145 84.015 67.775 84.345 ;
        RECT 67.945 84.315 70.985 84.485 ;
        RECT 67.945 83.875 70.985 84.045 ;
        RECT 71.385 83.675 72.085 84.445 ;
        RECT 74.365 84.015 74.725 84.915 ;
        RECT 79.365 84.865 79.905 85.035 ;
        RECT 81.725 85.025 82.085 85.665 ;
        RECT 82.255 85.325 84.295 85.495 ;
        RECT 82.255 84.885 84.295 85.055 ;
        RECT 74.895 84.315 76.935 84.485 ;
        RECT 74.895 83.875 76.935 84.045 ;
        RECT 81.925 84.015 82.095 84.345 ;
        RECT 82.265 84.315 84.305 84.485 ;
        RECT 85.285 84.295 86.655 85.425 ;
        RECT 115.650 84.570 122.390 84.740 ;
        RECT 82.265 83.875 84.305 84.045 ;
        RECT 86.985 83.675 87.265 84.345 ;
        RECT 87.435 84.315 89.475 84.485 ;
        RECT 87.435 83.875 89.475 84.045 ;
        RECT 92.005 84.015 92.175 84.345 ;
        RECT 92.345 84.315 93.385 84.485 ;
        RECT 92.345 83.875 93.385 84.045 ;
        RECT 96.085 84.015 96.255 84.345 ;
        RECT 96.425 84.315 98.465 84.485 ;
        RECT 96.425 83.875 98.465 84.045 ;
        RECT 71.385 83.375 87.265 83.675 ;
        RECT 115.650 81.200 115.820 84.570 ;
        RECT 119.520 84.170 121.410 84.190 ;
        RECT 116.160 83.680 116.330 84.010 ;
        RECT 116.500 84.000 121.540 84.170 ;
        RECT 116.680 83.690 118.680 83.700 ;
        RECT 116.500 83.520 121.540 83.690 ;
        RECT 116.680 83.510 118.680 83.520 ;
        RECT 119.520 83.210 121.410 83.240 ;
        RECT 116.160 82.720 116.330 83.050 ;
        RECT 116.500 83.040 121.540 83.210 ;
        RECT 121.710 83.200 121.880 83.530 ;
        RECT 116.700 82.730 118.700 82.760 ;
        RECT 116.500 82.560 121.540 82.730 ;
        RECT 119.550 82.250 121.440 82.260 ;
        RECT 116.160 81.760 116.330 82.090 ;
        RECT 116.500 82.080 121.540 82.250 ;
        RECT 121.710 82.240 121.880 82.570 ;
        RECT 119.550 82.070 121.440 82.080 ;
        RECT 116.680 81.770 118.680 81.800 ;
        RECT 116.500 81.600 121.540 81.770 ;
        RECT 122.220 81.200 122.390 84.570 ;
        RECT 126.815 84.515 128.975 85.205 ;
        RECT 115.650 81.030 122.390 81.200 ;
        RECT 126.815 81.005 128.975 81.695 ;
        RECT 129.980 79.150 130.150 90.990 ;
        RECT 130.630 88.350 131.320 90.510 ;
        RECT 130.630 79.630 131.320 81.790 ;
        RECT 131.800 79.150 131.970 90.990 ;
        RECT 129.980 78.980 131.970 79.150 ;
        RECT 114.400 78.380 128.230 78.550 ;
        RECT 33.820 75.670 37.250 75.840 ;
        RECT 33.820 74.260 33.990 75.670 ;
        RECT 34.330 74.800 34.500 75.130 ;
        RECT 34.670 75.100 36.710 75.270 ;
        RECT 34.670 74.660 36.710 74.830 ;
        RECT 37.080 74.260 37.250 75.670 ;
        RECT 33.820 74.090 37.250 74.260 ;
        RECT 45.690 75.680 55.430 75.850 ;
        RECT 45.690 74.270 45.860 75.680 ;
        RECT 46.200 74.810 46.370 75.140 ;
        RECT 46.540 75.110 54.580 75.280 ;
        RECT 46.540 74.670 54.580 74.840 ;
        RECT 54.750 74.810 54.920 75.140 ;
        RECT 55.260 74.270 55.430 75.680 ;
        RECT 114.400 75.010 114.570 78.380 ;
        RECT 114.910 77.490 115.080 77.820 ;
        RECT 115.295 77.810 127.335 77.980 ;
        RECT 115.400 77.500 121.350 77.510 ;
        RECT 115.295 77.330 127.335 77.500 ;
        RECT 114.910 76.530 115.080 76.860 ;
        RECT 115.295 76.850 127.335 77.020 ;
        RECT 127.550 77.010 127.720 77.340 ;
        RECT 115.295 76.370 127.335 76.540 ;
        RECT 114.910 75.570 115.080 75.900 ;
        RECT 115.295 75.890 127.335 76.060 ;
        RECT 127.550 76.050 127.720 76.380 ;
        RECT 115.295 75.410 127.335 75.580 ;
        RECT 128.060 75.010 128.230 78.380 ;
        RECT 114.400 74.840 128.230 75.010 ;
        RECT 129.980 78.450 131.970 78.620 ;
        RECT 45.690 74.100 55.430 74.270 ;
        RECT 32.460 72.310 38.940 72.480 ;
        RECT 32.460 70.900 32.630 72.310 ;
        RECT 32.975 71.440 33.145 71.770 ;
        RECT 33.360 71.740 38.400 71.910 ;
        RECT 33.360 71.300 38.400 71.470 ;
        RECT 38.770 70.900 38.940 72.310 ;
        RECT 32.460 70.730 38.940 70.900 ;
        RECT 39.300 72.310 61.130 72.480 ;
        RECT 39.300 70.900 39.470 72.310 ;
        RECT 39.810 71.440 39.980 71.770 ;
        RECT 40.195 71.740 60.235 71.910 ;
        RECT 40.195 71.300 60.235 71.470 ;
        RECT 60.450 71.440 60.620 71.770 ;
        RECT 60.960 70.900 61.130 72.310 ;
        RECT 39.300 70.730 61.130 70.900 ;
        RECT 115.650 72.030 122.390 72.200 ;
        RECT 115.650 68.660 115.820 72.030 ;
        RECT 119.520 71.630 121.410 71.650 ;
        RECT 116.160 71.140 116.330 71.470 ;
        RECT 116.500 71.460 121.540 71.630 ;
        RECT 116.680 71.150 118.680 71.160 ;
        RECT 116.500 70.980 121.540 71.150 ;
        RECT 116.680 70.970 118.680 70.980 ;
        RECT 119.520 70.670 121.410 70.700 ;
        RECT 116.160 70.180 116.330 70.510 ;
        RECT 116.500 70.500 121.540 70.670 ;
        RECT 121.710 70.660 121.880 70.990 ;
        RECT 116.700 70.190 118.700 70.220 ;
        RECT 116.500 70.020 121.540 70.190 ;
        RECT 119.550 69.710 121.440 69.720 ;
        RECT 116.160 69.220 116.330 69.550 ;
        RECT 116.500 69.540 121.540 69.710 ;
        RECT 121.710 69.700 121.880 70.030 ;
        RECT 119.550 69.530 121.440 69.540 ;
        RECT 116.680 69.230 118.680 69.260 ;
        RECT 116.500 69.060 121.540 69.230 ;
        RECT 122.220 68.660 122.390 72.030 ;
        RECT 126.815 71.975 128.975 72.665 ;
        RECT 115.650 68.490 122.390 68.660 ;
        RECT 126.815 68.465 128.975 69.155 ;
        RECT 129.980 66.610 130.150 78.450 ;
        RECT 130.630 75.810 131.320 77.970 ;
        RECT 130.630 67.090 131.320 69.250 ;
        RECT 131.800 66.610 131.970 78.450 ;
        RECT 129.980 66.440 131.970 66.610 ;
        RECT 114.400 65.840 128.230 66.010 ;
        RECT 114.400 62.470 114.570 65.840 ;
        RECT 114.910 64.950 115.080 65.280 ;
        RECT 115.295 65.270 127.335 65.440 ;
        RECT 115.400 64.960 121.350 64.970 ;
        RECT 115.295 64.790 127.335 64.960 ;
        RECT 114.910 63.990 115.080 64.320 ;
        RECT 115.295 64.310 127.335 64.480 ;
        RECT 127.550 64.470 127.720 64.800 ;
        RECT 115.295 63.830 127.335 64.000 ;
        RECT 114.910 63.030 115.080 63.360 ;
        RECT 115.295 63.350 127.335 63.520 ;
        RECT 127.550 63.510 127.720 63.840 ;
        RECT 115.295 62.870 127.335 63.040 ;
        RECT 128.060 62.470 128.230 65.840 ;
        RECT 114.400 62.300 128.230 62.470 ;
        RECT 129.980 65.910 131.970 66.080 ;
        RECT 42.610 61.440 44.360 61.610 ;
        RECT 36.070 59.950 36.790 60.270 ;
        RECT 36.200 59.340 36.740 59.510 ;
        RECT 36.200 58.900 36.740 59.070 ;
        RECT 36.910 59.040 37.080 59.370 ;
        RECT 38.150 59.340 38.690 59.510 ;
        RECT 38.150 58.900 38.690 59.070 ;
        RECT 38.860 59.040 39.030 59.370 ;
        RECT 36.040 58.090 36.860 58.260 ;
        RECT 36.040 57.650 36.860 57.820 ;
        RECT 37.185 57.790 37.355 58.120 ;
        RECT 37.990 58.090 38.810 58.260 ;
        RECT 37.990 57.650 38.810 57.820 ;
        RECT 39.135 57.790 39.305 58.120 ;
        RECT 42.610 57.300 42.780 61.440 ;
        RECT 43.320 60.925 43.650 61.095 ;
        RECT 43.180 57.670 43.350 60.710 ;
        RECT 43.620 57.670 43.790 60.710 ;
        RECT 44.190 57.300 44.360 61.440 ;
        RECT 115.650 59.490 122.390 59.660 ;
        RECT 103.800 59.090 105.790 59.260 ;
        RECT 38.130 56.820 39.190 57.290 ;
        RECT 42.610 57.130 44.360 57.300 ;
        RECT 67.840 57.220 89.670 57.390 ;
        RECT 42.610 56.600 44.360 56.770 ;
        RECT 37.020 55.310 38.770 55.480 ;
        RECT 37.020 48.910 37.190 55.310 ;
        RECT 37.730 54.800 38.060 54.970 ;
        RECT 37.590 49.590 37.760 54.630 ;
        RECT 38.030 49.590 38.200 54.630 ;
        RECT 37.730 49.250 38.060 49.420 ;
        RECT 38.600 48.910 38.770 55.310 ;
        RECT 39.130 55.310 40.880 55.480 ;
        RECT 39.130 53.220 39.300 55.310 ;
        RECT 39.700 53.900 39.870 54.940 ;
        RECT 40.140 53.900 40.310 54.940 ;
        RECT 39.840 53.560 40.170 53.730 ;
        RECT 40.710 53.220 40.880 55.310 ;
        RECT 39.130 53.050 40.880 53.220 ;
        RECT 42.610 52.460 42.780 56.600 ;
        RECT 43.180 53.190 43.350 56.230 ;
        RECT 43.620 53.190 43.790 56.230 ;
        RECT 43.320 52.805 43.650 52.975 ;
        RECT 44.190 52.460 44.360 56.600 ;
        RECT 67.840 55.810 68.010 57.220 ;
        RECT 68.350 56.350 68.520 56.680 ;
        RECT 68.735 56.650 88.775 56.820 ;
        RECT 68.735 56.210 88.775 56.380 ;
        RECT 88.990 56.350 89.160 56.680 ;
        RECT 89.500 55.810 89.670 57.220 ;
        RECT 67.840 55.640 89.670 55.810 ;
        RECT 63.110 54.980 65.350 55.150 ;
        RECT 53.680 54.590 55.430 54.760 ;
        RECT 46.390 53.420 46.940 54.350 ;
        RECT 49.990 54.050 51.740 54.220 ;
        RECT 46.350 52.890 47.170 53.060 ;
        RECT 42.610 52.290 44.360 52.460 ;
        RECT 46.350 52.450 47.170 52.620 ;
        RECT 47.495 52.590 47.665 52.920 ;
        RECT 49.990 52.460 50.160 54.050 ;
        RECT 50.560 53.140 50.730 53.680 ;
        RECT 51.000 53.140 51.170 53.680 ;
        RECT 50.700 52.800 51.030 52.970 ;
        RECT 51.570 52.460 51.740 54.050 ;
        RECT 49.990 52.290 51.740 52.460 ;
        RECT 53.680 52.450 53.850 54.590 ;
        RECT 54.390 54.075 54.720 54.245 ;
        RECT 54.250 52.820 54.420 53.860 ;
        RECT 54.690 52.820 54.860 53.860 ;
        RECT 55.260 52.450 55.430 54.590 ;
        RECT 53.680 52.280 55.430 52.450 ;
        RECT 55.790 53.850 57.540 54.020 ;
        RECT 42.610 51.760 44.360 51.930 ;
        RECT 37.020 48.740 38.770 48.910 ;
        RECT 39.130 51.000 40.880 51.170 ;
        RECT 39.130 48.910 39.300 51.000 ;
        RECT 39.840 50.490 40.170 50.660 ;
        RECT 39.700 49.280 39.870 50.320 ;
        RECT 40.140 49.280 40.310 50.320 ;
        RECT 40.710 48.910 40.880 51.000 ;
        RECT 39.130 48.740 40.880 48.910 ;
        RECT 42.610 47.620 42.780 51.760 ;
        RECT 43.320 51.245 43.650 51.415 ;
        RECT 43.180 47.990 43.350 51.030 ;
        RECT 43.620 47.990 43.790 51.030 ;
        RECT 44.190 47.620 44.360 51.760 ;
        RECT 46.510 51.640 47.050 51.810 ;
        RECT 49.990 51.760 51.740 51.930 ;
        RECT 46.510 51.200 47.050 51.370 ;
        RECT 47.220 51.340 47.390 51.670 ;
        RECT 46.460 49.930 47.500 50.730 ;
        RECT 49.990 50.170 50.160 51.760 ;
        RECT 50.700 51.250 51.030 51.420 ;
        RECT 50.560 50.540 50.730 51.080 ;
        RECT 51.000 50.540 51.170 51.080 ;
        RECT 51.570 50.170 51.740 51.760 ;
        RECT 49.990 50.000 51.740 50.170 ;
        RECT 53.680 51.750 55.430 51.920 ;
        RECT 53.680 49.610 53.850 51.750 ;
        RECT 54.250 50.340 54.420 51.380 ;
        RECT 54.690 50.340 54.860 51.380 ;
        RECT 54.390 49.955 54.720 50.125 ;
        RECT 55.260 49.610 55.430 51.750 ;
        RECT 55.790 50.360 55.960 53.850 ;
        RECT 56.500 53.340 56.830 53.510 ;
        RECT 56.360 51.085 56.530 53.125 ;
        RECT 56.800 51.085 56.970 53.125 ;
        RECT 56.500 50.700 56.830 50.870 ;
        RECT 57.370 50.360 57.540 53.850 ;
        RECT 63.110 53.570 63.280 54.980 ;
        RECT 63.620 54.110 63.790 54.440 ;
        RECT 63.960 54.410 64.500 54.580 ;
        RECT 63.960 53.970 64.500 54.140 ;
        RECT 64.670 54.110 64.840 54.440 ;
        RECT 65.180 53.570 65.350 54.980 ;
        RECT 97.720 54.600 99.470 54.770 ;
        RECT 94.370 54.350 96.120 54.520 ;
        RECT 63.110 53.400 65.350 53.570 ;
        RECT 77.770 53.860 88.510 54.030 ;
        RECT 77.770 52.450 77.940 53.860 ;
        RECT 78.280 52.990 78.450 53.320 ;
        RECT 78.620 53.290 87.660 53.460 ;
        RECT 78.620 52.850 87.660 53.020 ;
        RECT 87.830 52.990 88.000 53.320 ;
        RECT 88.340 52.450 88.510 53.860 ;
        RECT 77.770 52.280 88.510 52.450 ;
        RECT 90.990 53.860 93.180 54.030 ;
        RECT 90.990 52.450 91.160 53.860 ;
        RECT 91.500 52.990 91.670 53.320 ;
        RECT 91.840 53.290 92.330 53.460 ;
        RECT 91.840 52.850 92.330 53.020 ;
        RECT 92.500 52.990 92.670 53.320 ;
        RECT 93.010 52.450 93.180 53.860 ;
        RECT 90.990 52.280 93.180 52.450 ;
        RECT 94.370 52.450 94.540 54.350 ;
        RECT 95.080 53.840 95.410 54.010 ;
        RECT 94.940 53.130 95.110 53.670 ;
        RECT 95.380 53.130 95.550 53.670 ;
        RECT 95.080 52.790 95.410 52.960 ;
        RECT 95.950 52.450 96.120 54.350 ;
        RECT 94.370 52.280 96.120 52.450 ;
        RECT 97.720 52.460 97.890 54.600 ;
        RECT 98.290 52.830 98.460 53.870 ;
        RECT 98.730 52.830 98.900 53.870 ;
        RECT 99.300 52.460 99.470 54.600 ;
        RECT 97.720 52.290 99.470 52.460 ;
        RECT 99.830 53.850 101.580 54.020 ;
        RECT 77.770 51.750 88.510 51.920 ;
        RECT 55.790 50.190 57.540 50.360 ;
        RECT 62.640 51.290 65.860 51.460 ;
        RECT 53.680 49.440 55.430 49.610 ;
        RECT 42.610 47.450 44.360 47.620 ;
        RECT 62.640 47.280 62.810 51.290 ;
        RECT 63.230 50.620 65.270 50.790 ;
        RECT 63.310 50.420 65.190 50.620 ;
        RECT 63.310 47.950 65.190 48.150 ;
        RECT 63.230 47.780 65.270 47.950 ;
        RECT 65.690 47.280 65.860 51.290 ;
        RECT 77.770 50.340 77.940 51.750 ;
        RECT 78.280 50.880 78.450 51.210 ;
        RECT 78.620 51.180 87.660 51.350 ;
        RECT 78.620 50.740 87.660 50.910 ;
        RECT 87.830 50.880 88.000 51.210 ;
        RECT 88.340 50.340 88.510 51.750 ;
        RECT 77.770 50.170 88.510 50.340 ;
        RECT 91.090 51.750 93.080 51.920 ;
        RECT 37.060 46.620 37.780 47.240 ;
        RECT 62.640 47.110 65.860 47.280 ;
        RECT 67.840 48.390 89.670 48.560 ;
        RECT 42.610 46.920 44.360 47.090 ;
        RECT 36.200 46.360 36.740 46.530 ;
        RECT 36.200 45.920 36.740 46.090 ;
        RECT 36.910 46.060 37.080 46.390 ;
        RECT 38.150 46.360 38.690 46.530 ;
        RECT 38.150 45.920 38.690 46.090 ;
        RECT 38.860 46.060 39.030 46.390 ;
        RECT 36.040 45.110 36.860 45.280 ;
        RECT 36.040 44.670 36.860 44.840 ;
        RECT 37.185 44.810 37.355 45.140 ;
        RECT 37.990 45.110 38.810 45.280 ;
        RECT 37.990 44.670 38.810 44.840 ;
        RECT 39.135 44.810 39.305 45.140 ;
        RECT 36.360 43.850 37.570 44.220 ;
        RECT 42.610 42.780 42.780 46.920 ;
        RECT 43.180 43.510 43.350 46.550 ;
        RECT 43.620 43.510 43.790 46.550 ;
        RECT 43.320 43.125 43.650 43.295 ;
        RECT 44.190 42.780 44.360 46.920 ;
        RECT 67.840 46.980 68.010 48.390 ;
        RECT 68.350 47.520 68.520 47.850 ;
        RECT 68.735 47.820 88.775 47.990 ;
        RECT 68.735 47.380 88.775 47.550 ;
        RECT 88.990 47.520 89.160 47.850 ;
        RECT 89.500 46.980 89.670 48.390 ;
        RECT 67.840 46.810 89.670 46.980 ;
        RECT 91.090 45.940 91.260 51.750 ;
        RECT 91.740 49.110 92.430 51.270 ;
        RECT 91.740 46.420 92.430 48.580 ;
        RECT 92.910 45.940 93.080 51.750 ;
        RECT 94.370 51.750 96.120 51.920 ;
        RECT 94.370 49.850 94.540 51.750 ;
        RECT 95.080 51.240 95.410 51.410 ;
        RECT 94.940 50.530 95.110 51.070 ;
        RECT 95.380 50.530 95.550 51.070 ;
        RECT 95.080 50.190 95.410 50.360 ;
        RECT 95.950 49.850 96.120 51.750 ;
        RECT 94.370 49.680 96.120 49.850 ;
        RECT 97.720 51.760 99.470 51.930 ;
        RECT 97.720 49.620 97.890 51.760 ;
        RECT 98.290 50.350 98.460 51.390 ;
        RECT 98.730 50.350 98.900 51.390 ;
        RECT 98.430 49.965 98.760 50.135 ;
        RECT 99.300 49.620 99.470 51.760 ;
        RECT 99.830 50.360 100.000 53.850 ;
        RECT 100.540 53.340 100.870 53.510 ;
        RECT 100.400 51.085 100.570 53.125 ;
        RECT 100.840 51.085 101.010 53.125 ;
        RECT 100.540 50.700 100.870 50.870 ;
        RECT 101.410 50.360 101.580 53.850 ;
        RECT 103.800 53.280 103.970 59.090 ;
        RECT 104.450 56.450 105.140 58.610 ;
        RECT 104.450 53.760 105.140 55.920 ;
        RECT 105.620 53.280 105.790 59.090 ;
        RECT 115.650 56.120 115.820 59.490 ;
        RECT 119.520 59.090 121.410 59.110 ;
        RECT 116.160 58.600 116.330 58.930 ;
        RECT 116.500 58.920 121.540 59.090 ;
        RECT 116.680 58.610 118.680 58.620 ;
        RECT 116.500 58.440 121.540 58.610 ;
        RECT 116.680 58.430 118.680 58.440 ;
        RECT 119.520 58.130 121.410 58.160 ;
        RECT 116.160 57.640 116.330 57.970 ;
        RECT 116.500 57.960 121.540 58.130 ;
        RECT 121.710 58.120 121.880 58.450 ;
        RECT 116.700 57.650 118.700 57.680 ;
        RECT 116.500 57.480 121.540 57.650 ;
        RECT 119.550 57.170 121.440 57.180 ;
        RECT 116.160 56.680 116.330 57.010 ;
        RECT 116.500 57.000 121.540 57.170 ;
        RECT 121.710 57.160 121.880 57.490 ;
        RECT 119.550 56.990 121.440 57.000 ;
        RECT 116.680 56.690 118.680 56.720 ;
        RECT 116.500 56.520 121.540 56.690 ;
        RECT 122.220 56.120 122.390 59.490 ;
        RECT 126.815 59.435 128.975 60.125 ;
        RECT 115.650 55.950 122.390 56.120 ;
        RECT 126.815 55.925 128.975 56.615 ;
        RECT 129.980 54.070 130.150 65.910 ;
        RECT 130.630 63.270 131.320 65.430 ;
        RECT 130.630 54.550 131.320 56.710 ;
        RECT 131.800 54.070 131.970 65.910 ;
        RECT 129.980 53.900 131.970 54.070 ;
        RECT 103.800 53.110 105.790 53.280 ;
        RECT 99.830 50.190 101.580 50.360 ;
        RECT 103.630 51.550 105.960 51.720 ;
        RECT 103.630 50.140 103.800 51.550 ;
        RECT 104.140 50.680 104.310 51.010 ;
        RECT 104.525 50.980 105.065 51.150 ;
        RECT 104.525 50.540 105.065 50.710 ;
        RECT 105.280 50.680 105.450 51.010 ;
        RECT 105.790 50.140 105.960 51.550 ;
        RECT 103.630 49.970 105.960 50.140 ;
        RECT 97.720 49.450 99.470 49.620 ;
        RECT 91.090 45.770 93.080 45.940 ;
        RECT 42.610 42.610 44.360 42.780 ;
        RECT 44.180 36.030 45.930 36.200 ;
        RECT 32.390 32.840 33.070 33.280 ;
        RECT 33.970 32.630 34.340 33.080 ;
        RECT 34.550 33.050 35.590 33.220 ;
        RECT 36.170 33.050 37.210 33.220 ;
        RECT 32.310 32.400 34.340 32.630 ;
        RECT 34.550 32.610 35.590 32.780 ;
        RECT 36.170 32.610 37.210 32.780 ;
        RECT 37.425 32.750 37.980 33.080 ;
        RECT 32.310 31.990 32.480 32.400 ;
        RECT 32.305 31.660 32.480 31.990 ;
        RECT 32.690 31.960 33.730 32.130 ;
        RECT 32.690 31.520 33.730 31.690 ;
        RECT 34.165 31.660 34.335 31.990 ;
        RECT 34.550 31.960 35.590 32.130 ;
        RECT 36.170 31.960 37.210 32.130 ;
        RECT 34.550 31.520 35.590 31.690 ;
        RECT 36.170 31.520 37.210 31.690 ;
        RECT 37.425 31.660 37.610 31.990 ;
        RECT 32.310 30.920 35.990 31.210 ;
        RECT 37.430 31.170 37.610 31.660 ;
        RECT 32.310 30.110 32.480 30.920 ;
        RECT 32.650 30.410 33.190 30.580 ;
        RECT 32.650 29.970 33.190 30.140 ;
        RECT 34.170 30.110 34.340 30.440 ;
        RECT 34.510 30.410 35.050 30.580 ;
        RECT 35.620 30.380 35.990 30.920 ;
        RECT 36.200 30.930 37.610 31.170 ;
        RECT 34.510 29.970 35.050 30.140 ;
        RECT 32.610 29.020 33.430 29.570 ;
        RECT 34.200 29.340 34.740 29.510 ;
        RECT 36.200 29.370 36.420 30.930 ;
        RECT 36.710 30.410 37.250 30.580 ;
        RECT 37.790 30.440 37.980 32.750 ;
        RECT 36.710 29.970 37.250 30.140 ;
        RECT 37.420 30.110 37.980 30.440 ;
        RECT 34.200 28.900 34.740 29.070 ;
        RECT 34.910 29.040 36.420 29.370 ;
        RECT 36.680 29.040 36.850 29.370 ;
        RECT 37.020 29.340 37.560 29.510 ;
        RECT 37.020 28.900 37.560 29.070 ;
        RECT 32.360 25.490 33.040 25.930 ;
        RECT 33.940 25.280 34.310 25.730 ;
        RECT 34.520 25.700 35.560 25.870 ;
        RECT 36.140 25.700 37.180 25.870 ;
        RECT 32.280 25.050 34.310 25.280 ;
        RECT 34.520 25.260 35.560 25.430 ;
        RECT 36.140 25.260 37.180 25.430 ;
        RECT 37.395 25.400 37.950 25.730 ;
        RECT 32.280 24.640 32.450 25.050 ;
        RECT 32.275 24.310 32.450 24.640 ;
        RECT 32.660 24.610 33.700 24.780 ;
        RECT 32.660 24.170 33.700 24.340 ;
        RECT 34.135 24.310 34.305 24.640 ;
        RECT 34.520 24.610 35.560 24.780 ;
        RECT 36.140 24.610 37.180 24.780 ;
        RECT 34.520 24.170 35.560 24.340 ;
        RECT 36.140 24.170 37.180 24.340 ;
        RECT 37.395 24.310 37.580 24.640 ;
        RECT 32.280 23.570 35.960 23.860 ;
        RECT 37.400 23.820 37.580 24.310 ;
        RECT 32.280 22.760 32.450 23.570 ;
        RECT 32.620 23.060 33.160 23.230 ;
        RECT 32.620 22.620 33.160 22.790 ;
        RECT 34.140 22.760 34.310 23.090 ;
        RECT 34.480 23.060 35.020 23.230 ;
        RECT 35.590 23.030 35.960 23.570 ;
        RECT 36.170 23.580 37.580 23.820 ;
        RECT 34.480 22.620 35.020 22.790 ;
        RECT 32.580 21.670 33.400 22.220 ;
        RECT 34.170 21.990 34.710 22.160 ;
        RECT 36.170 22.020 36.390 23.580 ;
        RECT 36.680 23.060 37.220 23.230 ;
        RECT 37.760 23.090 37.950 25.400 ;
        RECT 36.680 22.620 37.220 22.790 ;
        RECT 37.390 22.760 37.950 23.090 ;
        RECT 34.170 21.550 34.710 21.720 ;
        RECT 34.880 21.690 36.390 22.020 ;
        RECT 36.650 21.690 36.820 22.020 ;
        RECT 36.990 21.990 37.530 22.160 ;
        RECT 36.990 21.550 37.530 21.720 ;
        RECT 44.180 19.540 44.350 36.030 ;
        RECT 44.890 35.520 45.220 35.690 ;
        RECT 44.750 20.265 44.920 35.305 ;
        RECT 45.190 20.265 45.360 35.305 ;
        RECT 44.890 19.880 45.220 20.050 ;
        RECT 45.760 19.540 45.930 36.030 ;
        RECT 46.290 36.030 48.040 36.200 ;
        RECT 46.290 31.890 46.460 36.030 ;
        RECT 46.860 32.620 47.030 35.660 ;
        RECT 47.300 32.620 47.470 35.660 ;
        RECT 47.000 32.235 47.330 32.405 ;
        RECT 47.870 31.890 48.040 36.030 ;
        RECT 49.440 36.030 51.190 36.200 ;
        RECT 49.440 33.940 49.610 36.030 ;
        RECT 50.150 35.520 50.480 35.690 ;
        RECT 50.010 34.310 50.180 35.350 ;
        RECT 50.450 34.310 50.620 35.350 ;
        RECT 51.020 33.940 51.190 36.030 ;
        RECT 49.440 33.770 51.190 33.940 ;
        RECT 104.390 33.930 106.380 34.100 ;
        RECT 46.290 31.720 48.040 31.890 ;
        RECT 49.440 33.240 51.190 33.410 ;
        RECT 49.440 31.150 49.610 33.240 ;
        RECT 50.010 31.830 50.180 32.870 ;
        RECT 50.450 31.830 50.620 32.870 ;
        RECT 50.150 31.490 50.480 31.660 ;
        RECT 51.020 31.150 51.190 33.240 ;
        RECT 80.630 32.900 89.370 33.070 ;
        RECT 80.630 31.490 80.800 32.900 ;
        RECT 81.140 32.030 81.310 32.360 ;
        RECT 81.480 32.330 88.520 32.500 ;
        RECT 81.480 31.890 88.520 32.060 ;
        RECT 88.690 32.030 88.860 32.360 ;
        RECT 89.200 31.490 89.370 32.900 ;
        RECT 80.630 31.320 89.370 31.490 ;
        RECT 96.080 31.620 97.830 31.790 ;
        RECT 49.440 30.980 51.190 31.150 ;
        RECT 53.300 30.270 55.050 30.440 ;
        RECT 49.600 29.170 50.340 29.580 ;
        RECT 48.825 28.270 48.995 28.600 ;
        RECT 49.320 28.570 50.140 28.740 ;
        RECT 49.320 28.130 50.140 28.300 ;
        RECT 53.300 28.130 53.470 30.270 ;
        RECT 53.870 28.860 54.040 29.900 ;
        RECT 54.310 28.860 54.480 29.900 ;
        RECT 54.010 28.475 54.340 28.645 ;
        RECT 54.880 28.130 55.050 30.270 ;
        RECT 91.790 30.150 94.070 30.320 ;
        RECT 53.300 27.960 55.050 28.130 ;
        RECT 56.120 29.720 57.870 29.890 ;
        RECT 56.120 28.130 56.290 29.720 ;
        RECT 56.830 29.210 57.160 29.380 ;
        RECT 56.690 28.500 56.860 29.040 ;
        RECT 57.130 28.500 57.300 29.040 ;
        RECT 57.700 28.130 57.870 29.720 ;
        RECT 63.020 29.660 65.300 29.830 ;
        RECT 56.120 27.960 57.870 28.130 ;
        RECT 58.230 28.980 59.980 29.150 ;
        RECT 49.100 27.020 49.270 27.350 ;
        RECT 49.440 27.320 49.980 27.490 ;
        RECT 53.300 27.430 55.050 27.600 ;
        RECT 49.440 26.880 49.980 27.050 ;
        RECT 49.880 26.100 50.300 26.500 ;
        RECT 53.300 25.290 53.470 27.430 ;
        RECT 54.010 26.915 54.340 27.085 ;
        RECT 53.870 25.660 54.040 26.700 ;
        RECT 54.310 25.660 54.480 26.700 ;
        RECT 54.880 25.290 55.050 27.430 ;
        RECT 56.120 27.430 57.870 27.600 ;
        RECT 56.120 25.840 56.290 27.430 ;
        RECT 56.690 26.520 56.860 27.060 ;
        RECT 57.130 26.520 57.300 27.060 ;
        RECT 56.830 26.180 57.160 26.350 ;
        RECT 57.700 25.840 57.870 27.430 ;
        RECT 58.230 26.580 58.400 28.980 ;
        RECT 58.940 28.470 59.270 28.640 ;
        RECT 58.800 27.260 58.970 28.300 ;
        RECT 59.240 27.260 59.410 28.300 ;
        RECT 58.940 26.920 59.270 27.090 ;
        RECT 59.810 26.580 59.980 28.980 ;
        RECT 63.020 28.250 63.190 29.660 ;
        RECT 63.530 28.790 63.700 29.120 ;
        RECT 63.915 29.090 64.405 29.260 ;
        RECT 63.915 28.650 64.405 28.820 ;
        RECT 64.620 28.790 64.790 29.120 ;
        RECT 65.130 28.250 65.300 29.660 ;
        RECT 63.020 28.080 65.300 28.250 ;
        RECT 67.540 29.540 89.370 29.710 ;
        RECT 67.540 28.130 67.710 29.540 ;
        RECT 68.050 28.670 68.220 29.000 ;
        RECT 68.435 28.970 88.475 29.140 ;
        RECT 68.435 28.530 88.475 28.700 ;
        RECT 88.690 28.670 88.860 29.000 ;
        RECT 89.200 28.130 89.370 29.540 ;
        RECT 91.790 28.740 91.960 30.150 ;
        RECT 92.300 29.280 92.470 29.610 ;
        RECT 92.685 29.580 93.175 29.750 ;
        RECT 92.685 29.140 93.175 29.310 ;
        RECT 93.390 29.280 93.560 29.610 ;
        RECT 93.900 28.740 94.070 30.150 ;
        RECT 91.790 28.570 94.070 28.740 ;
        RECT 67.540 27.960 89.370 28.130 ;
        RECT 96.080 28.130 96.250 31.620 ;
        RECT 96.790 31.110 97.120 31.280 ;
        RECT 96.650 28.855 96.820 30.895 ;
        RECT 97.090 28.855 97.260 30.895 ;
        RECT 96.790 28.470 97.120 28.640 ;
        RECT 97.660 28.130 97.830 31.620 ;
        RECT 96.080 27.960 97.830 28.130 ;
        RECT 99.530 29.720 101.280 29.890 ;
        RECT 99.530 28.130 99.700 29.720 ;
        RECT 100.100 28.500 100.270 29.040 ;
        RECT 100.540 28.500 100.710 29.040 ;
        RECT 101.110 28.130 101.280 29.720 ;
        RECT 99.530 27.960 101.280 28.130 ;
        RECT 101.640 29.480 103.390 29.650 ;
        RECT 58.230 26.410 59.980 26.580 ;
        RECT 62.550 27.550 65.770 27.720 ;
        RECT 56.120 25.670 57.870 25.840 ;
        RECT 53.300 25.120 55.050 25.290 ;
        RECT 49.440 24.420 51.190 24.590 ;
        RECT 44.180 19.370 45.930 19.540 ;
        RECT 46.290 23.680 48.040 23.850 ;
        RECT 46.290 19.540 46.460 23.680 ;
        RECT 47.000 23.165 47.330 23.335 ;
        RECT 46.860 19.910 47.030 22.950 ;
        RECT 47.300 19.910 47.470 22.950 ;
        RECT 47.870 19.540 48.040 23.680 ;
        RECT 49.440 22.330 49.610 24.420 ;
        RECT 50.150 23.910 50.480 24.080 ;
        RECT 50.010 22.700 50.180 23.740 ;
        RECT 50.450 22.700 50.620 23.740 ;
        RECT 51.020 22.330 51.190 24.420 ;
        RECT 62.550 23.540 62.720 27.550 ;
        RECT 63.140 26.880 65.180 27.050 ;
        RECT 63.220 26.680 65.100 26.880 ;
        RECT 63.220 24.210 65.100 24.410 ;
        RECT 63.140 24.040 65.180 24.210 ;
        RECT 65.600 23.540 65.770 27.550 ;
        RECT 67.540 27.430 89.370 27.600 ;
        RECT 67.540 26.020 67.710 27.430 ;
        RECT 68.050 26.560 68.220 26.890 ;
        RECT 68.435 26.860 88.475 27.030 ;
        RECT 68.435 26.420 88.475 26.590 ;
        RECT 88.690 26.560 88.860 26.890 ;
        RECT 89.200 26.020 89.370 27.430 ;
        RECT 96.080 27.430 97.830 27.600 ;
        RECT 67.540 25.850 89.370 26.020 ;
        RECT 91.940 27.190 93.930 27.360 ;
        RECT 62.550 23.370 65.770 23.540 ;
        RECT 80.630 24.070 89.370 24.240 ;
        RECT 80.630 22.660 80.800 24.070 ;
        RECT 81.140 23.200 81.310 23.530 ;
        RECT 81.480 23.500 88.520 23.670 ;
        RECT 81.480 23.060 88.520 23.230 ;
        RECT 88.690 23.200 88.860 23.530 ;
        RECT 89.200 22.660 89.370 24.070 ;
        RECT 80.630 22.490 89.370 22.660 ;
        RECT 49.440 22.160 51.190 22.330 ;
        RECT 46.290 19.370 48.040 19.540 ;
        RECT 49.440 21.630 51.190 21.800 ;
        RECT 49.440 19.540 49.610 21.630 ;
        RECT 50.010 20.220 50.180 21.260 ;
        RECT 50.450 20.220 50.620 21.260 ;
        RECT 50.150 19.880 50.480 20.050 ;
        RECT 51.020 19.540 51.190 21.630 ;
        RECT 91.940 21.380 92.110 27.190 ;
        RECT 92.590 24.550 93.280 26.710 ;
        RECT 92.590 21.860 93.280 24.020 ;
        RECT 93.760 21.380 93.930 27.190 ;
        RECT 96.080 23.940 96.250 27.430 ;
        RECT 96.790 26.920 97.120 27.090 ;
        RECT 96.650 24.665 96.820 26.705 ;
        RECT 97.090 24.665 97.260 26.705 ;
        RECT 96.790 24.280 97.120 24.450 ;
        RECT 97.660 23.940 97.830 27.430 ;
        RECT 99.530 27.430 101.280 27.600 ;
        RECT 99.530 25.840 99.700 27.430 ;
        RECT 100.100 26.520 100.270 27.060 ;
        RECT 100.540 26.520 100.710 27.060 ;
        RECT 100.240 26.180 100.570 26.350 ;
        RECT 101.110 25.840 101.280 27.430 ;
        RECT 101.640 26.080 101.810 29.480 ;
        RECT 102.350 28.970 102.680 29.140 ;
        RECT 102.210 26.760 102.380 28.800 ;
        RECT 102.650 26.760 102.820 28.800 ;
        RECT 102.350 26.420 102.680 26.590 ;
        RECT 103.220 26.080 103.390 29.480 ;
        RECT 104.390 28.120 104.560 33.930 ;
        RECT 105.040 31.290 105.730 33.450 ;
        RECT 105.040 28.600 105.730 30.760 ;
        RECT 106.210 28.120 106.380 33.930 ;
        RECT 104.390 27.950 106.380 28.120 ;
        RECT 101.640 25.910 103.390 26.080 ;
        RECT 104.290 27.420 106.480 27.590 ;
        RECT 104.290 26.010 104.460 27.420 ;
        RECT 104.800 26.550 104.970 26.880 ;
        RECT 105.140 26.850 105.630 27.020 ;
        RECT 105.140 26.410 105.630 26.580 ;
        RECT 105.800 26.550 105.970 26.880 ;
        RECT 106.310 26.010 106.480 27.420 ;
        RECT 104.290 25.840 106.480 26.010 ;
        RECT 99.530 25.670 101.280 25.840 ;
        RECT 96.080 23.770 97.830 23.940 ;
        RECT 91.940 21.210 93.930 21.380 ;
        RECT 49.440 19.370 51.190 19.540 ;
        RECT 34.040 16.640 34.580 16.810 ;
        RECT 34.040 16.200 34.580 16.370 ;
        RECT 34.750 16.340 34.920 16.670 ;
        RECT 37.310 16.640 37.850 16.810 ;
        RECT 37.310 16.200 37.850 16.370 ;
        RECT 33.880 15.390 34.700 15.560 ;
        RECT 33.880 14.950 34.700 15.120 ;
        RECT 35.025 15.090 35.195 15.420 ;
        RECT 35.430 14.900 36.620 15.600 ;
        RECT 37.150 15.390 37.970 15.560 ;
        RECT 37.150 14.950 37.970 15.120 ;
      LAYER met1 ;
        RECT 13.420 208.610 13.750 208.920 ;
        RECT 18.920 208.610 19.250 208.920 ;
        RECT 24.420 208.610 24.750 208.920 ;
        RECT 29.920 208.610 30.250 208.920 ;
        RECT 35.420 208.610 35.750 208.920 ;
        RECT 40.920 208.610 41.250 208.920 ;
        RECT 46.420 208.610 46.750 208.920 ;
        RECT 51.920 208.610 52.250 208.920 ;
        RECT 57.420 208.610 57.750 208.920 ;
        RECT 62.920 208.610 63.250 208.920 ;
        RECT 68.420 208.610 68.750 208.920 ;
        RECT 73.920 208.610 74.250 208.920 ;
        RECT 13.420 202.610 13.970 208.610 ;
        RECT 14.180 208.480 14.410 208.610 ;
        RECT 14.180 207.480 16.600 208.480 ;
        RECT 14.180 203.840 15.600 207.480 ;
        RECT 15.810 203.840 16.910 205.840 ;
        RECT 17.120 203.840 17.690 207.130 ;
        RECT 14.180 202.610 14.410 203.840 ;
        RECT 16.850 203.070 17.180 203.680 ;
        RECT 15.220 202.710 17.180 203.070 ;
        RECT 13.420 201.780 13.750 202.610 ;
        RECT 13.930 202.180 14.810 202.410 ;
        RECT 15.220 202.180 15.600 202.710 ;
        RECT 17.350 202.180 17.690 203.840 ;
        RECT 13.930 202.140 15.600 202.180 ;
        RECT 13.420 198.780 13.970 201.780 ;
        RECT 14.180 199.180 15.600 202.140 ;
        RECT 15.810 199.180 16.910 202.180 ;
        RECT 17.120 199.180 17.690 202.180 ;
        RECT 14.180 198.780 14.410 199.180 ;
        RECT 13.420 197.955 13.750 198.780 ;
        RECT 15.450 197.960 16.200 199.020 ;
        RECT 13.420 194.955 13.975 197.955 ;
        RECT 14.180 194.960 15.060 197.960 ;
        RECT 15.270 195.990 16.910 197.960 ;
        RECT 17.350 196.990 17.690 199.180 ;
        RECT 17.120 195.990 17.690 196.990 ;
        RECT 15.270 194.960 15.500 195.990 ;
        RECT 14.185 194.955 14.415 194.960 ;
        RECT 13.420 194.380 13.750 194.955 ;
        RECT 13.935 194.520 14.510 194.750 ;
        RECT 13.420 193.070 13.830 194.380 ;
        RECT 13.990 193.650 14.510 194.520 ;
        RECT 14.860 194.420 16.320 194.820 ;
        RECT 14.860 193.820 15.860 194.420 ;
        RECT 16.850 194.220 17.180 195.830 ;
        RECT 16.010 194.000 17.180 194.220 ;
        RECT 17.350 194.000 17.690 195.990 ;
        RECT 18.920 202.610 19.470 208.610 ;
        RECT 19.680 208.480 19.910 208.610 ;
        RECT 19.680 207.480 22.100 208.480 ;
        RECT 19.680 203.840 21.100 207.480 ;
        RECT 21.310 203.840 22.410 205.840 ;
        RECT 22.620 203.840 23.190 207.130 ;
        RECT 19.680 202.610 19.910 203.840 ;
        RECT 22.350 203.070 22.680 203.680 ;
        RECT 20.720 202.710 22.680 203.070 ;
        RECT 18.920 201.780 19.250 202.610 ;
        RECT 19.430 202.180 20.310 202.410 ;
        RECT 20.720 202.180 21.100 202.710 ;
        RECT 22.850 202.180 23.190 203.840 ;
        RECT 19.430 202.140 21.100 202.180 ;
        RECT 18.920 198.780 19.470 201.780 ;
        RECT 19.680 199.180 21.100 202.140 ;
        RECT 21.310 199.180 22.410 202.180 ;
        RECT 22.620 199.180 23.190 202.180 ;
        RECT 19.680 198.780 19.910 199.180 ;
        RECT 18.920 197.955 19.250 198.780 ;
        RECT 20.950 197.960 21.700 199.020 ;
        RECT 18.920 194.955 19.475 197.955 ;
        RECT 19.680 194.960 20.560 197.960 ;
        RECT 20.770 195.990 22.410 197.960 ;
        RECT 22.850 196.990 23.190 199.180 ;
        RECT 22.620 195.990 23.190 196.990 ;
        RECT 20.770 194.960 21.000 195.990 ;
        RECT 19.685 194.955 19.915 194.960 ;
        RECT 18.920 194.380 19.250 194.955 ;
        RECT 19.435 194.520 20.010 194.750 ;
        RECT 16.010 193.650 16.200 194.000 ;
        RECT 13.990 193.430 16.200 193.650 ;
        RECT 14.960 192.650 15.960 193.430 ;
        RECT 18.920 193.070 19.330 194.380 ;
        RECT 19.490 193.650 20.010 194.520 ;
        RECT 20.360 194.420 21.820 194.820 ;
        RECT 20.360 193.820 21.360 194.420 ;
        RECT 22.350 194.220 22.680 195.830 ;
        RECT 21.510 194.000 22.680 194.220 ;
        RECT 22.850 194.000 23.190 195.990 ;
        RECT 24.420 202.610 24.970 208.610 ;
        RECT 25.180 208.480 25.410 208.610 ;
        RECT 25.180 207.480 27.600 208.480 ;
        RECT 25.180 203.840 26.600 207.480 ;
        RECT 26.810 203.840 27.910 205.840 ;
        RECT 28.120 203.840 28.690 207.130 ;
        RECT 25.180 202.610 25.410 203.840 ;
        RECT 27.850 203.070 28.180 203.680 ;
        RECT 26.220 202.710 28.180 203.070 ;
        RECT 24.420 201.780 24.750 202.610 ;
        RECT 24.930 202.180 25.810 202.410 ;
        RECT 26.220 202.180 26.600 202.710 ;
        RECT 28.350 202.180 28.690 203.840 ;
        RECT 24.930 202.140 26.600 202.180 ;
        RECT 24.420 198.780 24.970 201.780 ;
        RECT 25.180 199.180 26.600 202.140 ;
        RECT 26.810 199.180 27.910 202.180 ;
        RECT 28.120 199.180 28.690 202.180 ;
        RECT 25.180 198.780 25.410 199.180 ;
        RECT 24.420 197.955 24.750 198.780 ;
        RECT 26.450 197.960 27.200 199.020 ;
        RECT 24.420 194.955 24.975 197.955 ;
        RECT 25.180 194.960 26.060 197.960 ;
        RECT 26.270 195.990 27.910 197.960 ;
        RECT 28.350 196.990 28.690 199.180 ;
        RECT 28.120 195.990 28.690 196.990 ;
        RECT 26.270 194.960 26.500 195.990 ;
        RECT 25.185 194.955 25.415 194.960 ;
        RECT 24.420 194.380 24.750 194.955 ;
        RECT 24.935 194.520 25.510 194.750 ;
        RECT 21.510 193.650 21.700 194.000 ;
        RECT 19.490 193.430 21.700 193.650 ;
        RECT 20.460 192.650 21.460 193.430 ;
        RECT 24.420 193.070 24.830 194.380 ;
        RECT 24.990 193.650 25.510 194.520 ;
        RECT 25.860 194.420 27.320 194.820 ;
        RECT 25.860 193.820 26.860 194.420 ;
        RECT 27.850 194.220 28.180 195.830 ;
        RECT 27.010 194.000 28.180 194.220 ;
        RECT 28.350 194.000 28.690 195.990 ;
        RECT 29.920 202.610 30.470 208.610 ;
        RECT 30.680 208.480 30.910 208.610 ;
        RECT 30.680 207.480 33.100 208.480 ;
        RECT 30.680 203.840 32.100 207.480 ;
        RECT 32.310 203.840 33.410 205.840 ;
        RECT 33.620 203.840 34.190 207.130 ;
        RECT 30.680 202.610 30.910 203.840 ;
        RECT 33.350 203.070 33.680 203.680 ;
        RECT 31.720 202.710 33.680 203.070 ;
        RECT 29.920 201.780 30.250 202.610 ;
        RECT 30.430 202.180 31.310 202.410 ;
        RECT 31.720 202.180 32.100 202.710 ;
        RECT 33.850 202.180 34.190 203.840 ;
        RECT 30.430 202.140 32.100 202.180 ;
        RECT 29.920 198.780 30.470 201.780 ;
        RECT 30.680 199.180 32.100 202.140 ;
        RECT 32.310 199.180 33.410 202.180 ;
        RECT 33.620 199.180 34.190 202.180 ;
        RECT 30.680 198.780 30.910 199.180 ;
        RECT 29.920 197.955 30.250 198.780 ;
        RECT 31.950 197.960 32.700 199.020 ;
        RECT 29.920 194.955 30.475 197.955 ;
        RECT 30.680 194.960 31.560 197.960 ;
        RECT 31.770 195.990 33.410 197.960 ;
        RECT 33.850 196.990 34.190 199.180 ;
        RECT 33.620 195.990 34.190 196.990 ;
        RECT 31.770 194.960 32.000 195.990 ;
        RECT 30.685 194.955 30.915 194.960 ;
        RECT 29.920 194.380 30.250 194.955 ;
        RECT 30.435 194.520 31.010 194.750 ;
        RECT 27.010 193.650 27.200 194.000 ;
        RECT 24.990 193.430 27.200 193.650 ;
        RECT 25.960 192.650 26.960 193.430 ;
        RECT 29.920 193.070 30.330 194.380 ;
        RECT 30.490 193.650 31.010 194.520 ;
        RECT 31.360 194.420 32.820 194.820 ;
        RECT 31.360 193.820 32.360 194.420 ;
        RECT 33.350 194.220 33.680 195.830 ;
        RECT 32.510 194.000 33.680 194.220 ;
        RECT 33.850 194.000 34.190 195.990 ;
        RECT 35.420 202.610 35.970 208.610 ;
        RECT 36.180 208.480 36.410 208.610 ;
        RECT 36.180 207.480 38.600 208.480 ;
        RECT 36.180 203.840 37.600 207.480 ;
        RECT 37.810 203.840 38.910 205.840 ;
        RECT 39.120 203.840 39.690 207.130 ;
        RECT 36.180 202.610 36.410 203.840 ;
        RECT 38.850 203.070 39.180 203.680 ;
        RECT 37.220 202.710 39.180 203.070 ;
        RECT 35.420 201.780 35.750 202.610 ;
        RECT 35.930 202.180 36.810 202.410 ;
        RECT 37.220 202.180 37.600 202.710 ;
        RECT 39.350 202.180 39.690 203.840 ;
        RECT 35.930 202.140 37.600 202.180 ;
        RECT 35.420 198.780 35.970 201.780 ;
        RECT 36.180 199.180 37.600 202.140 ;
        RECT 37.810 199.180 38.910 202.180 ;
        RECT 39.120 199.180 39.690 202.180 ;
        RECT 36.180 198.780 36.410 199.180 ;
        RECT 35.420 197.955 35.750 198.780 ;
        RECT 37.450 197.960 38.200 199.020 ;
        RECT 35.420 194.955 35.975 197.955 ;
        RECT 36.180 194.960 37.060 197.960 ;
        RECT 37.270 195.990 38.910 197.960 ;
        RECT 39.350 196.990 39.690 199.180 ;
        RECT 39.120 195.990 39.690 196.990 ;
        RECT 37.270 194.960 37.500 195.990 ;
        RECT 36.185 194.955 36.415 194.960 ;
        RECT 35.420 194.380 35.750 194.955 ;
        RECT 35.935 194.520 36.510 194.750 ;
        RECT 32.510 193.650 32.700 194.000 ;
        RECT 30.490 193.430 32.700 193.650 ;
        RECT 31.460 192.650 32.460 193.430 ;
        RECT 35.420 193.070 35.830 194.380 ;
        RECT 35.990 193.650 36.510 194.520 ;
        RECT 36.860 194.420 38.320 194.820 ;
        RECT 36.860 193.820 37.860 194.420 ;
        RECT 38.850 194.220 39.180 195.830 ;
        RECT 38.010 194.000 39.180 194.220 ;
        RECT 39.350 194.000 39.690 195.990 ;
        RECT 40.920 202.610 41.470 208.610 ;
        RECT 41.680 208.480 41.910 208.610 ;
        RECT 41.680 207.480 44.100 208.480 ;
        RECT 41.680 203.840 43.100 207.480 ;
        RECT 43.310 203.840 44.410 205.840 ;
        RECT 44.620 203.840 45.190 207.130 ;
        RECT 41.680 202.610 41.910 203.840 ;
        RECT 44.350 203.070 44.680 203.680 ;
        RECT 42.720 202.710 44.680 203.070 ;
        RECT 40.920 201.780 41.250 202.610 ;
        RECT 41.430 202.180 42.310 202.410 ;
        RECT 42.720 202.180 43.100 202.710 ;
        RECT 44.850 202.180 45.190 203.840 ;
        RECT 41.430 202.140 43.100 202.180 ;
        RECT 40.920 198.780 41.470 201.780 ;
        RECT 41.680 199.180 43.100 202.140 ;
        RECT 43.310 199.180 44.410 202.180 ;
        RECT 44.620 199.180 45.190 202.180 ;
        RECT 41.680 198.780 41.910 199.180 ;
        RECT 40.920 197.955 41.250 198.780 ;
        RECT 42.950 197.960 43.700 199.020 ;
        RECT 40.920 194.955 41.475 197.955 ;
        RECT 41.680 194.960 42.560 197.960 ;
        RECT 42.770 195.990 44.410 197.960 ;
        RECT 44.850 196.990 45.190 199.180 ;
        RECT 44.620 195.990 45.190 196.990 ;
        RECT 42.770 194.960 43.000 195.990 ;
        RECT 41.685 194.955 41.915 194.960 ;
        RECT 40.920 194.380 41.250 194.955 ;
        RECT 41.435 194.520 42.010 194.750 ;
        RECT 38.010 193.650 38.200 194.000 ;
        RECT 35.990 193.430 38.200 193.650 ;
        RECT 36.960 192.650 37.960 193.430 ;
        RECT 40.920 193.070 41.330 194.380 ;
        RECT 41.490 193.650 42.010 194.520 ;
        RECT 42.360 194.420 43.820 194.820 ;
        RECT 42.360 193.820 43.360 194.420 ;
        RECT 44.350 194.220 44.680 195.830 ;
        RECT 43.510 194.000 44.680 194.220 ;
        RECT 44.850 194.000 45.190 195.990 ;
        RECT 46.420 202.610 46.970 208.610 ;
        RECT 47.180 208.480 47.410 208.610 ;
        RECT 47.180 207.480 49.600 208.480 ;
        RECT 47.180 203.840 48.600 207.480 ;
        RECT 48.810 203.840 49.910 205.840 ;
        RECT 50.120 203.840 50.690 207.130 ;
        RECT 47.180 202.610 47.410 203.840 ;
        RECT 49.850 203.070 50.180 203.680 ;
        RECT 48.220 202.710 50.180 203.070 ;
        RECT 46.420 201.780 46.750 202.610 ;
        RECT 46.930 202.180 47.810 202.410 ;
        RECT 48.220 202.180 48.600 202.710 ;
        RECT 50.350 202.180 50.690 203.840 ;
        RECT 46.930 202.140 48.600 202.180 ;
        RECT 46.420 198.780 46.970 201.780 ;
        RECT 47.180 199.180 48.600 202.140 ;
        RECT 48.810 199.180 49.910 202.180 ;
        RECT 50.120 199.180 50.690 202.180 ;
        RECT 47.180 198.780 47.410 199.180 ;
        RECT 46.420 197.955 46.750 198.780 ;
        RECT 48.450 197.960 49.200 199.020 ;
        RECT 46.420 194.955 46.975 197.955 ;
        RECT 47.180 194.960 48.060 197.960 ;
        RECT 48.270 195.990 49.910 197.960 ;
        RECT 50.350 196.990 50.690 199.180 ;
        RECT 50.120 195.990 50.690 196.990 ;
        RECT 48.270 194.960 48.500 195.990 ;
        RECT 47.185 194.955 47.415 194.960 ;
        RECT 46.420 194.380 46.750 194.955 ;
        RECT 46.935 194.520 47.510 194.750 ;
        RECT 43.510 193.650 43.700 194.000 ;
        RECT 41.490 193.430 43.700 193.650 ;
        RECT 42.460 192.650 43.460 193.430 ;
        RECT 46.420 193.070 46.830 194.380 ;
        RECT 46.990 193.650 47.510 194.520 ;
        RECT 47.860 194.420 49.320 194.820 ;
        RECT 47.860 193.820 48.860 194.420 ;
        RECT 49.850 194.220 50.180 195.830 ;
        RECT 49.010 194.000 50.180 194.220 ;
        RECT 50.350 194.000 50.690 195.990 ;
        RECT 51.920 202.610 52.470 208.610 ;
        RECT 52.680 208.480 52.910 208.610 ;
        RECT 52.680 207.480 55.100 208.480 ;
        RECT 52.680 203.840 54.100 207.480 ;
        RECT 54.310 203.840 55.410 205.840 ;
        RECT 55.620 203.840 56.190 207.130 ;
        RECT 52.680 202.610 52.910 203.840 ;
        RECT 55.350 203.070 55.680 203.680 ;
        RECT 53.720 202.710 55.680 203.070 ;
        RECT 51.920 201.780 52.250 202.610 ;
        RECT 52.430 202.180 53.310 202.410 ;
        RECT 53.720 202.180 54.100 202.710 ;
        RECT 55.850 202.180 56.190 203.840 ;
        RECT 52.430 202.140 54.100 202.180 ;
        RECT 51.920 198.780 52.470 201.780 ;
        RECT 52.680 199.180 54.100 202.140 ;
        RECT 54.310 199.180 55.410 202.180 ;
        RECT 55.620 199.180 56.190 202.180 ;
        RECT 52.680 198.780 52.910 199.180 ;
        RECT 51.920 197.955 52.250 198.780 ;
        RECT 53.950 197.960 54.700 199.020 ;
        RECT 51.920 194.955 52.475 197.955 ;
        RECT 52.680 194.960 53.560 197.960 ;
        RECT 53.770 195.990 55.410 197.960 ;
        RECT 55.850 196.990 56.190 199.180 ;
        RECT 55.620 195.990 56.190 196.990 ;
        RECT 53.770 194.960 54.000 195.990 ;
        RECT 52.685 194.955 52.915 194.960 ;
        RECT 51.920 194.380 52.250 194.955 ;
        RECT 52.435 194.520 53.010 194.750 ;
        RECT 49.010 193.650 49.200 194.000 ;
        RECT 46.990 193.430 49.200 193.650 ;
        RECT 47.960 192.650 48.960 193.430 ;
        RECT 51.920 193.070 52.330 194.380 ;
        RECT 52.490 193.650 53.010 194.520 ;
        RECT 53.360 194.420 54.820 194.820 ;
        RECT 53.360 193.820 54.360 194.420 ;
        RECT 55.350 194.220 55.680 195.830 ;
        RECT 54.510 194.000 55.680 194.220 ;
        RECT 55.850 194.000 56.190 195.990 ;
        RECT 57.420 202.610 57.970 208.610 ;
        RECT 58.180 208.480 58.410 208.610 ;
        RECT 58.180 207.480 60.600 208.480 ;
        RECT 58.180 203.840 59.600 207.480 ;
        RECT 59.810 203.840 60.910 205.840 ;
        RECT 61.120 203.840 61.690 207.130 ;
        RECT 58.180 202.610 58.410 203.840 ;
        RECT 60.850 203.070 61.180 203.680 ;
        RECT 59.220 202.710 61.180 203.070 ;
        RECT 57.420 201.780 57.750 202.610 ;
        RECT 57.930 202.180 58.810 202.410 ;
        RECT 59.220 202.180 59.600 202.710 ;
        RECT 61.350 202.180 61.690 203.840 ;
        RECT 57.930 202.140 59.600 202.180 ;
        RECT 57.420 198.780 57.970 201.780 ;
        RECT 58.180 199.180 59.600 202.140 ;
        RECT 59.810 199.180 60.910 202.180 ;
        RECT 61.120 199.180 61.690 202.180 ;
        RECT 58.180 198.780 58.410 199.180 ;
        RECT 57.420 197.955 57.750 198.780 ;
        RECT 59.450 197.960 60.200 199.020 ;
        RECT 57.420 194.955 57.975 197.955 ;
        RECT 58.180 194.960 59.060 197.960 ;
        RECT 59.270 195.990 60.910 197.960 ;
        RECT 61.350 196.990 61.690 199.180 ;
        RECT 61.120 195.990 61.690 196.990 ;
        RECT 59.270 194.960 59.500 195.990 ;
        RECT 58.185 194.955 58.415 194.960 ;
        RECT 57.420 194.380 57.750 194.955 ;
        RECT 57.935 194.520 58.510 194.750 ;
        RECT 54.510 193.650 54.700 194.000 ;
        RECT 52.490 193.430 54.700 193.650 ;
        RECT 53.460 192.650 54.460 193.430 ;
        RECT 57.420 193.070 57.830 194.380 ;
        RECT 57.990 193.650 58.510 194.520 ;
        RECT 58.860 194.420 60.320 194.820 ;
        RECT 58.860 193.820 59.860 194.420 ;
        RECT 60.850 194.220 61.180 195.830 ;
        RECT 60.010 194.000 61.180 194.220 ;
        RECT 61.350 194.000 61.690 195.990 ;
        RECT 62.920 202.610 63.470 208.610 ;
        RECT 63.680 208.480 63.910 208.610 ;
        RECT 63.680 207.480 66.100 208.480 ;
        RECT 63.680 203.840 65.100 207.480 ;
        RECT 65.310 203.840 66.410 205.840 ;
        RECT 66.620 203.840 67.190 207.130 ;
        RECT 63.680 202.610 63.910 203.840 ;
        RECT 66.350 203.070 66.680 203.680 ;
        RECT 64.720 202.710 66.680 203.070 ;
        RECT 62.920 201.780 63.250 202.610 ;
        RECT 63.430 202.180 64.310 202.410 ;
        RECT 64.720 202.180 65.100 202.710 ;
        RECT 66.850 202.180 67.190 203.840 ;
        RECT 63.430 202.140 65.100 202.180 ;
        RECT 62.920 198.780 63.470 201.780 ;
        RECT 63.680 199.180 65.100 202.140 ;
        RECT 65.310 199.180 66.410 202.180 ;
        RECT 66.620 199.180 67.190 202.180 ;
        RECT 63.680 198.780 63.910 199.180 ;
        RECT 62.920 197.955 63.250 198.780 ;
        RECT 64.950 197.960 65.700 199.020 ;
        RECT 62.920 194.955 63.475 197.955 ;
        RECT 63.680 194.960 64.560 197.960 ;
        RECT 64.770 195.990 66.410 197.960 ;
        RECT 66.850 196.990 67.190 199.180 ;
        RECT 66.620 195.990 67.190 196.990 ;
        RECT 64.770 194.960 65.000 195.990 ;
        RECT 63.685 194.955 63.915 194.960 ;
        RECT 62.920 194.380 63.250 194.955 ;
        RECT 63.435 194.520 64.010 194.750 ;
        RECT 60.010 193.650 60.200 194.000 ;
        RECT 57.990 193.430 60.200 193.650 ;
        RECT 58.960 192.650 59.960 193.430 ;
        RECT 62.920 193.070 63.330 194.380 ;
        RECT 63.490 193.650 64.010 194.520 ;
        RECT 64.360 194.420 65.820 194.820 ;
        RECT 64.360 193.820 65.360 194.420 ;
        RECT 66.350 194.220 66.680 195.830 ;
        RECT 65.510 194.000 66.680 194.220 ;
        RECT 66.850 194.000 67.190 195.990 ;
        RECT 68.420 202.610 68.970 208.610 ;
        RECT 69.180 208.480 69.410 208.610 ;
        RECT 69.180 207.480 71.600 208.480 ;
        RECT 69.180 203.840 70.600 207.480 ;
        RECT 70.810 203.840 71.910 205.840 ;
        RECT 72.120 203.840 72.690 207.130 ;
        RECT 69.180 202.610 69.410 203.840 ;
        RECT 71.850 203.070 72.180 203.680 ;
        RECT 70.220 202.710 72.180 203.070 ;
        RECT 68.420 201.780 68.750 202.610 ;
        RECT 68.930 202.180 69.810 202.410 ;
        RECT 70.220 202.180 70.600 202.710 ;
        RECT 72.350 202.180 72.690 203.840 ;
        RECT 68.930 202.140 70.600 202.180 ;
        RECT 68.420 198.780 68.970 201.780 ;
        RECT 69.180 199.180 70.600 202.140 ;
        RECT 70.810 199.180 71.910 202.180 ;
        RECT 72.120 199.180 72.690 202.180 ;
        RECT 69.180 198.780 69.410 199.180 ;
        RECT 68.420 197.955 68.750 198.780 ;
        RECT 70.450 197.960 71.200 199.020 ;
        RECT 68.420 194.955 68.975 197.955 ;
        RECT 69.180 194.960 70.060 197.960 ;
        RECT 70.270 195.990 71.910 197.960 ;
        RECT 72.350 196.990 72.690 199.180 ;
        RECT 72.120 195.990 72.690 196.990 ;
        RECT 70.270 194.960 70.500 195.990 ;
        RECT 69.185 194.955 69.415 194.960 ;
        RECT 68.420 194.380 68.750 194.955 ;
        RECT 68.935 194.520 69.510 194.750 ;
        RECT 65.510 193.650 65.700 194.000 ;
        RECT 63.490 193.430 65.700 193.650 ;
        RECT 64.460 192.660 65.460 193.430 ;
        RECT 68.420 193.070 68.830 194.380 ;
        RECT 68.990 193.650 69.510 194.520 ;
        RECT 69.860 194.420 71.320 194.820 ;
        RECT 69.860 193.820 70.860 194.420 ;
        RECT 71.850 194.220 72.180 195.830 ;
        RECT 71.010 194.000 72.180 194.220 ;
        RECT 72.350 194.000 72.690 195.990 ;
        RECT 73.920 202.610 74.470 208.610 ;
        RECT 74.680 208.480 74.910 208.610 ;
        RECT 74.680 207.480 77.100 208.480 ;
        RECT 74.680 203.840 76.100 207.480 ;
        RECT 76.310 203.840 77.410 205.840 ;
        RECT 77.620 203.840 78.190 207.130 ;
        RECT 114.260 207.080 131.400 208.710 ;
        RECT 74.680 202.610 74.910 203.840 ;
        RECT 77.350 203.070 77.680 203.680 ;
        RECT 75.720 202.710 77.680 203.070 ;
        RECT 77.850 203.090 78.190 203.840 ;
        RECT 112.570 204.490 116.810 206.910 ;
        RECT 112.570 203.090 114.740 204.490 ;
        RECT 73.920 201.780 74.250 202.610 ;
        RECT 74.430 202.180 75.310 202.410 ;
        RECT 75.720 202.180 76.100 202.710 ;
        RECT 77.850 202.180 114.740 203.090 ;
        RECT 74.430 202.140 76.100 202.180 ;
        RECT 73.920 198.780 74.470 201.780 ;
        RECT 74.680 199.180 76.100 202.140 ;
        RECT 76.310 199.180 77.410 202.180 ;
        RECT 77.620 201.430 114.740 202.180 ;
        RECT 77.620 200.530 99.440 201.430 ;
        RECT 77.620 200.190 79.190 200.530 ;
        RECT 83.650 200.330 99.430 200.530 ;
        RECT 77.620 199.180 78.190 200.190 ;
        RECT 83.650 200.100 86.940 200.330 ;
        RECT 74.680 198.780 74.910 199.180 ;
        RECT 73.920 197.955 74.250 198.780 ;
        RECT 75.950 197.960 76.700 199.020 ;
        RECT 73.920 194.955 74.475 197.955 ;
        RECT 74.680 194.960 75.560 197.960 ;
        RECT 75.770 195.990 77.410 197.960 ;
        RECT 77.850 196.990 78.190 199.180 ;
        RECT 80.460 197.680 81.460 198.680 ;
        RECT 82.300 198.580 83.300 199.580 ;
        RECT 84.940 198.790 86.940 199.890 ;
        RECT 87.100 199.830 88.070 200.160 ;
        RECT 88.600 200.100 91.600 200.330 ;
        RECT 93.790 200.100 94.790 200.330 ;
        RECT 87.710 198.580 88.070 199.830 ;
        RECT 88.600 198.790 91.600 199.890 ;
        RECT 92.820 199.180 94.790 199.890 ;
        RECT 94.950 199.830 96.780 200.160 ;
        RECT 82.300 197.390 86.940 198.580 ;
        RECT 87.710 198.200 91.600 198.580 ;
        RECT 91.760 198.480 94.790 199.180 ;
        RECT 95.960 198.840 96.360 199.300 ;
        RECT 96.560 199.180 96.780 199.830 ;
        RECT 98.430 199.390 99.430 200.330 ;
        RECT 100.140 199.670 101.140 200.670 ;
        RECT 112.570 199.390 114.740 201.430 ;
        RECT 96.560 198.990 97.350 199.180 ;
        RECT 97.130 198.940 97.350 198.990 ;
        RECT 91.760 198.430 95.820 198.480 ;
        RECT 92.820 198.250 95.820 198.430 ;
        RECT 88.600 197.790 91.600 198.200 ;
        RECT 88.370 197.390 91.600 197.790 ;
        RECT 92.820 197.395 95.820 198.040 ;
        RECT 95.960 197.840 96.960 198.840 ;
        RECT 97.130 198.160 97.770 198.940 ;
        RECT 98.430 198.220 114.740 199.390 ;
        RECT 97.130 197.490 97.350 198.160 ;
        RECT 82.170 197.160 88.170 197.390 ;
        RECT 88.370 197.160 92.000 197.390 ;
        RECT 92.820 197.165 95.825 197.395 ;
        RECT 92.820 197.160 95.820 197.165 ;
        RECT 77.620 195.990 78.190 196.990 ;
        RECT 78.380 196.730 81.860 196.990 ;
        RECT 82.170 196.730 88.170 196.950 ;
        RECT 88.370 196.910 88.640 197.160 ;
        RECT 96.030 196.970 97.350 197.490 ;
        RECT 89.000 196.730 92.000 196.950 ;
        RECT 92.825 196.730 95.825 196.955 ;
        RECT 96.030 196.915 96.260 196.970 ;
        RECT 100.140 196.810 101.140 197.890 ;
        RECT 96.400 196.730 101.140 196.810 ;
        RECT 78.380 196.300 101.140 196.730 ;
        RECT 78.380 195.990 81.860 196.300 ;
        RECT 75.770 194.960 76.000 195.990 ;
        RECT 74.685 194.955 74.915 194.960 ;
        RECT 73.920 194.380 74.250 194.955 ;
        RECT 74.435 194.520 75.010 194.750 ;
        RECT 71.010 193.650 71.200 194.000 ;
        RECT 68.990 193.430 71.200 193.650 ;
        RECT 69.960 192.650 70.960 193.430 ;
        RECT 73.920 193.070 74.330 194.380 ;
        RECT 74.490 193.650 75.010 194.520 ;
        RECT 75.360 194.420 76.820 194.820 ;
        RECT 75.360 193.820 76.360 194.420 ;
        RECT 77.350 194.220 77.680 195.830 ;
        RECT 76.510 194.000 77.680 194.220 ;
        RECT 77.850 194.000 78.190 195.990 ;
        RECT 76.510 193.650 76.700 194.000 ;
        RECT 74.490 193.430 76.700 193.650 ;
        RECT 75.460 192.650 76.460 193.430 ;
        RECT 78.380 190.630 79.380 194.820 ;
        RECT 80.780 191.660 81.860 195.990 ;
        RECT 83.650 195.420 99.430 195.880 ;
        RECT 112.570 195.510 114.740 198.220 ;
        RECT 114.880 203.750 127.840 204.060 ;
        RECT 114.880 199.740 115.120 203.750 ;
        RECT 115.330 200.590 121.480 203.470 ;
        RECT 115.330 200.580 118.820 200.590 ;
        RECT 114.880 198.740 116.120 199.740 ;
        RECT 119.460 199.260 121.480 200.590 ;
        RECT 121.820 200.540 127.240 203.470 ;
        RECT 127.520 200.710 127.840 203.750 ;
        RECT 129.880 201.210 131.400 207.080 ;
        RECT 131.540 200.540 134.000 204.200 ;
        RECT 121.820 199.560 134.000 200.540 ;
        RECT 114.880 198.250 119.320 198.740 ;
        RECT 114.880 196.490 116.370 198.250 ;
        RECT 112.570 195.420 115.220 195.510 ;
        RECT 83.650 195.260 115.220 195.420 ;
        RECT 83.650 195.030 86.940 195.260 ;
        RECT 82.300 193.510 83.300 194.510 ;
        RECT 84.940 193.720 86.940 194.820 ;
        RECT 87.100 194.760 88.070 195.090 ;
        RECT 88.600 195.030 91.600 195.260 ;
        RECT 93.790 195.030 94.790 195.260 ;
        RECT 87.710 193.510 88.070 194.760 ;
        RECT 88.600 193.720 91.600 194.820 ;
        RECT 92.820 194.110 94.790 194.820 ;
        RECT 94.950 194.760 96.780 195.090 ;
        RECT 82.300 192.320 86.940 193.510 ;
        RECT 87.710 193.130 91.600 193.510 ;
        RECT 91.760 193.410 94.790 194.110 ;
        RECT 95.960 193.770 96.360 194.230 ;
        RECT 96.560 194.110 96.780 194.760 ;
        RECT 98.430 194.510 115.220 195.260 ;
        RECT 98.430 194.250 114.740 194.510 ;
        RECT 115.880 194.345 116.370 196.490 ;
        RECT 115.930 194.340 116.370 194.345 ;
        RECT 96.560 193.920 97.350 194.110 ;
        RECT 97.130 193.870 97.350 193.920 ;
        RECT 91.760 193.360 95.820 193.410 ;
        RECT 92.820 193.180 95.820 193.360 ;
        RECT 88.600 192.720 91.600 193.130 ;
        RECT 88.370 192.320 91.600 192.720 ;
        RECT 92.820 192.325 95.820 192.970 ;
        RECT 95.960 192.770 96.960 193.770 ;
        RECT 97.130 193.090 97.770 193.870 ;
        RECT 112.570 193.520 114.740 194.250 ;
        RECT 116.590 193.520 118.820 197.090 ;
        RECT 118.970 194.080 119.320 198.250 ;
        RECT 119.460 198.010 128.970 199.260 ;
        RECT 119.460 194.360 121.480 198.010 ;
        RECT 121.680 194.080 122.260 197.390 ;
        RECT 126.810 197.350 128.970 198.010 ;
        RECT 131.540 197.890 134.000 199.560 ;
        RECT 131.230 196.890 134.000 197.890 ;
        RECT 118.970 193.660 122.260 194.080 ;
        RECT 122.700 195.320 130.400 196.760 ;
        RECT 122.700 193.520 123.050 195.320 ;
        RECT 97.130 192.420 97.350 193.090 ;
        RECT 82.170 192.090 88.170 192.320 ;
        RECT 88.370 192.090 92.000 192.320 ;
        RECT 92.820 192.095 95.825 192.325 ;
        RECT 92.820 192.090 95.820 192.095 ;
        RECT 82.170 191.660 88.170 191.880 ;
        RECT 88.370 191.840 88.640 192.090 ;
        RECT 96.030 191.900 97.350 192.420 ;
        RECT 89.000 191.660 92.000 191.880 ;
        RECT 92.825 191.660 95.825 191.885 ;
        RECT 96.030 191.845 96.260 191.900 ;
        RECT 100.140 191.740 101.140 192.310 ;
        RECT 96.400 191.660 101.140 191.740 ;
        RECT 80.780 191.230 101.140 191.660 ;
        RECT 55.550 188.610 79.380 190.630 ;
        RECT 83.650 190.320 99.430 190.810 ;
        RECT 100.140 190.720 101.140 191.230 ;
        RECT 112.570 192.070 123.050 193.520 ;
        RECT 126.810 192.390 131.400 194.750 ;
        RECT 112.570 190.320 114.740 192.070 ;
        RECT 83.650 190.190 114.740 190.320 ;
        RECT 83.650 189.960 86.940 190.190 ;
        RECT 55.550 179.430 59.130 188.610 ;
        RECT 82.300 188.440 83.300 189.440 ;
        RECT 84.940 188.650 86.940 189.750 ;
        RECT 87.100 189.690 88.070 190.020 ;
        RECT 88.600 189.960 91.600 190.190 ;
        RECT 93.790 189.960 94.790 190.190 ;
        RECT 87.710 188.440 88.070 189.690 ;
        RECT 88.600 188.650 91.600 189.750 ;
        RECT 92.820 189.040 94.790 189.750 ;
        RECT 94.950 189.690 96.780 190.020 ;
        RECT 82.300 187.250 86.940 188.440 ;
        RECT 87.710 188.060 91.600 188.440 ;
        RECT 91.760 188.340 94.790 189.040 ;
        RECT 95.960 188.700 96.360 189.160 ;
        RECT 96.560 189.040 96.780 189.690 ;
        RECT 98.430 189.150 114.740 190.190 ;
        RECT 96.560 188.850 97.350 189.040 ;
        RECT 97.130 188.800 97.350 188.850 ;
        RECT 91.760 188.290 95.820 188.340 ;
        RECT 92.820 188.110 95.820 188.290 ;
        RECT 88.600 187.650 91.600 188.060 ;
        RECT 88.370 187.250 91.600 187.650 ;
        RECT 92.820 187.255 95.820 187.900 ;
        RECT 95.960 187.700 96.960 188.700 ;
        RECT 97.130 188.020 97.770 188.800 ;
        RECT 97.130 187.350 97.350 188.020 ;
        RECT 82.170 187.020 88.170 187.250 ;
        RECT 88.370 187.020 92.000 187.250 ;
        RECT 92.820 187.025 95.825 187.255 ;
        RECT 92.820 187.020 95.820 187.025 ;
        RECT 75.130 186.740 80.670 186.750 ;
        RECT 75.130 185.750 80.810 186.740 ;
        RECT 82.170 186.590 88.170 186.810 ;
        RECT 88.370 186.770 88.640 187.020 ;
        RECT 96.030 186.830 97.350 187.350 ;
        RECT 89.000 186.590 92.000 186.810 ;
        RECT 92.825 186.590 95.825 186.815 ;
        RECT 96.030 186.775 96.260 186.830 ;
        RECT 100.140 186.670 101.140 187.110 ;
        RECT 96.400 186.590 101.140 186.670 ;
        RECT 81.860 186.160 101.140 186.590 ;
        RECT 63.190 185.740 80.810 185.750 ;
        RECT 63.190 185.500 99.430 185.740 ;
        RECT 100.140 185.520 101.140 186.160 ;
        RECT 63.190 185.120 76.320 185.500 ;
        RECT 79.720 185.330 99.430 185.500 ;
        RECT 112.570 185.330 114.740 189.150 ;
        RECT 79.720 185.120 114.740 185.330 ;
        RECT 63.190 184.890 66.480 185.120 ;
        RECT 61.840 183.370 62.840 184.370 ;
        RECT 64.480 183.580 66.480 184.680 ;
        RECT 66.640 184.620 67.610 184.950 ;
        RECT 68.140 184.890 71.140 185.120 ;
        RECT 73.330 184.890 74.330 185.120 ;
        RECT 67.250 183.370 67.610 184.620 ;
        RECT 68.140 183.580 71.140 184.680 ;
        RECT 72.360 183.970 74.330 184.680 ;
        RECT 74.490 184.620 76.320 184.950 ;
        RECT 79.720 184.890 86.940 185.120 ;
        RECT 61.840 182.180 66.480 183.370 ;
        RECT 67.250 182.990 71.140 183.370 ;
        RECT 71.300 183.270 74.330 183.970 ;
        RECT 75.500 183.630 75.900 184.090 ;
        RECT 76.100 183.970 76.320 184.620 ;
        RECT 76.100 183.780 76.890 183.970 ;
        RECT 76.670 183.730 76.890 183.780 ;
        RECT 71.300 183.220 75.360 183.270 ;
        RECT 72.360 183.040 75.360 183.220 ;
        RECT 68.140 182.580 71.140 182.990 ;
        RECT 67.910 182.180 71.140 182.580 ;
        RECT 72.360 182.185 75.360 182.830 ;
        RECT 75.500 182.630 76.500 183.630 ;
        RECT 76.670 182.950 78.700 183.730 ;
        RECT 76.670 182.280 76.890 182.950 ;
        RECT 61.710 181.950 67.710 182.180 ;
        RECT 67.910 181.950 71.540 182.180 ;
        RECT 72.360 181.955 75.365 182.185 ;
        RECT 72.360 181.950 75.360 181.955 ;
        RECT 61.710 181.520 67.710 181.740 ;
        RECT 67.910 181.700 68.180 181.950 ;
        RECT 75.570 181.760 76.890 182.280 ;
        RECT 68.540 181.520 71.540 181.740 ;
        RECT 72.365 181.520 75.365 181.745 ;
        RECT 75.570 181.705 75.800 181.760 ;
        RECT 75.940 181.520 77.250 181.600 ;
        RECT 61.400 181.300 77.250 181.520 ;
        RECT 61.400 181.190 77.310 181.300 ;
        RECT 61.400 181.090 77.460 181.190 ;
        RECT 60.090 179.430 61.090 180.430 ;
        RECT 61.400 180.350 67.140 181.090 ;
        RECT 76.110 180.750 77.460 181.090 ;
        RECT 62.140 179.910 67.140 180.140 ;
        RECT 33.210 179.190 63.130 179.430 ;
        RECT 63.830 179.190 65.830 179.910 ;
        RECT 67.340 179.370 67.990 180.410 ;
        RECT 33.210 178.190 65.830 179.190 ;
        RECT 33.210 177.930 63.130 178.190 ;
        RECT 33.210 172.770 35.080 177.930 ;
        RECT 63.830 176.990 65.830 178.190 ;
        RECT 65.990 178.580 67.990 179.370 ;
        RECT 76.110 179.460 76.300 180.750 ;
        RECT 77.700 180.620 78.700 182.950 ;
        RECT 78.980 183.370 83.300 184.370 ;
        RECT 84.940 183.580 86.940 184.680 ;
        RECT 87.100 184.620 88.070 184.950 ;
        RECT 88.600 184.890 91.600 185.120 ;
        RECT 93.790 184.890 94.790 185.120 ;
        RECT 87.710 183.370 88.070 184.620 ;
        RECT 88.600 183.580 91.600 184.680 ;
        RECT 92.820 183.970 94.790 184.680 ;
        RECT 94.950 184.620 96.780 184.950 ;
        RECT 78.980 180.620 79.610 183.370 ;
        RECT 82.300 182.180 86.940 183.370 ;
        RECT 87.710 182.990 91.600 183.370 ;
        RECT 91.760 183.270 94.790 183.970 ;
        RECT 95.960 183.630 96.360 184.090 ;
        RECT 96.560 183.970 96.780 184.620 ;
        RECT 98.430 184.160 114.740 185.120 ;
        RECT 96.560 183.780 97.350 183.970 ;
        RECT 97.130 183.730 97.350 183.780 ;
        RECT 91.760 183.220 95.820 183.270 ;
        RECT 92.820 183.040 95.820 183.220 ;
        RECT 88.600 182.580 91.600 182.990 ;
        RECT 88.370 182.180 91.600 182.580 ;
        RECT 92.820 182.185 95.820 182.830 ;
        RECT 95.960 182.630 96.960 183.630 ;
        RECT 97.130 182.950 97.770 183.730 ;
        RECT 112.570 182.970 114.740 184.160 ;
        RECT 114.880 191.210 127.840 191.520 ;
        RECT 114.880 187.200 115.120 191.210 ;
        RECT 115.330 188.050 121.480 190.930 ;
        RECT 115.330 188.040 118.820 188.050 ;
        RECT 114.880 186.200 116.120 187.200 ;
        RECT 119.460 186.720 121.480 188.050 ;
        RECT 121.820 188.000 127.240 190.930 ;
        RECT 127.520 188.170 127.840 191.210 ;
        RECT 129.880 188.670 131.400 192.390 ;
        RECT 131.540 188.000 134.000 196.890 ;
        RECT 121.820 187.020 134.000 188.000 ;
        RECT 114.880 185.710 119.320 186.200 ;
        RECT 114.880 183.950 116.370 185.710 ;
        RECT 97.130 182.280 97.350 182.950 ;
        RECT 82.170 181.950 88.170 182.180 ;
        RECT 88.370 181.950 92.000 182.180 ;
        RECT 92.820 181.955 95.825 182.185 ;
        RECT 92.820 181.950 95.820 181.955 ;
        RECT 82.170 181.520 88.170 181.740 ;
        RECT 88.370 181.700 88.640 181.950 ;
        RECT 96.030 181.760 97.350 182.280 ;
        RECT 89.000 181.520 92.000 181.740 ;
        RECT 92.825 181.520 95.825 181.745 ;
        RECT 96.030 181.705 96.260 181.760 ;
        RECT 100.140 181.600 101.140 182.180 ;
        RECT 96.400 181.520 101.140 181.600 ;
        RECT 81.860 181.090 101.140 181.520 ;
        RECT 76.440 180.450 77.460 180.540 ;
        RECT 77.700 180.450 78.550 180.620 ;
        RECT 76.440 180.150 78.550 180.450 ;
        RECT 80.120 180.390 99.430 180.670 ;
        RECT 100.140 180.590 101.140 181.090 ;
        RECT 112.570 181.970 115.220 182.970 ;
        RECT 112.570 180.980 114.740 181.970 ;
        RECT 115.880 181.805 116.370 183.950 ;
        RECT 115.930 181.800 116.370 181.805 ;
        RECT 116.590 180.980 118.820 184.550 ;
        RECT 118.970 181.540 119.320 185.710 ;
        RECT 119.460 185.470 128.970 186.720 ;
        RECT 119.460 181.820 121.480 185.470 ;
        RECT 121.680 181.540 122.260 184.850 ;
        RECT 126.810 184.810 128.970 185.470 ;
        RECT 131.540 185.350 134.000 187.020 ;
        RECT 131.230 184.350 134.000 185.350 ;
        RECT 118.970 181.120 122.260 181.540 ;
        RECT 122.700 182.780 130.400 184.220 ;
        RECT 122.700 180.980 123.050 182.780 ;
        RECT 78.990 180.150 79.580 180.380 ;
        RECT 76.440 179.850 78.580 180.150 ;
        RECT 76.440 179.660 77.460 179.850 ;
        RECT 76.110 179.455 76.530 179.460 ;
        RECT 76.110 179.450 77.455 179.455 ;
        RECT 76.110 179.010 77.460 179.450 ;
        RECT 77.610 179.440 78.050 179.710 ;
        RECT 78.190 179.650 78.580 179.850 ;
        RECT 78.790 179.870 79.580 180.150 ;
        RECT 79.790 180.210 99.430 180.390 ;
        RECT 112.570 180.210 123.050 180.980 ;
        RECT 79.790 180.050 123.050 180.210 ;
        RECT 79.790 179.870 86.940 180.050 ;
        RECT 78.790 179.650 79.260 179.870 ;
        RECT 79.990 179.820 86.940 179.870 ;
        RECT 79.400 179.480 79.850 179.710 ;
        RECT 79.400 179.440 79.590 179.480 ;
        RECT 77.610 179.250 79.590 179.440 ;
        RECT 77.610 179.110 78.830 179.250 ;
        RECT 65.990 177.790 68.020 178.580 ;
        RECT 68.580 178.000 69.580 179.000 ;
        RECT 76.110 178.990 77.140 179.010 ;
        RECT 65.990 176.980 69.580 177.790 ;
        RECT 69.740 177.730 71.110 178.060 ;
        RECT 63.090 175.830 65.830 176.780 ;
        RECT 65.990 176.750 69.700 176.980 ;
        RECT 70.020 176.790 71.110 177.730 ;
        RECT 70.015 176.780 71.110 176.790 ;
        RECT 65.990 176.720 68.210 176.750 ;
        RECT 68.700 176.100 69.700 176.540 ;
        RECT 70.015 176.500 70.245 176.780 ;
        RECT 76.100 176.450 77.140 178.990 ;
        RECT 77.830 178.020 78.830 179.110 ;
        RECT 79.990 179.080 80.180 179.820 ;
        RECT 79.180 178.550 80.180 179.080 ;
        RECT 82.300 178.300 83.300 179.300 ;
        RECT 84.940 178.510 86.940 179.610 ;
        RECT 87.100 179.550 88.070 179.880 ;
        RECT 88.600 179.820 91.600 180.050 ;
        RECT 93.790 179.820 94.790 180.050 ;
        RECT 87.710 178.300 88.070 179.550 ;
        RECT 88.600 178.510 91.600 179.610 ;
        RECT 92.820 178.900 94.790 179.610 ;
        RECT 94.950 179.550 96.780 179.880 ;
        RECT 82.300 178.020 86.940 178.300 ;
        RECT 77.830 177.210 86.940 178.020 ;
        RECT 87.710 177.920 91.600 178.300 ;
        RECT 91.760 178.200 94.790 178.900 ;
        RECT 95.960 178.560 96.360 179.020 ;
        RECT 96.560 178.900 96.780 179.550 ;
        RECT 98.430 179.530 123.050 180.050 ;
        RECT 126.810 179.850 131.400 182.210 ;
        RECT 98.430 179.040 114.740 179.530 ;
        RECT 96.560 178.710 97.350 178.900 ;
        RECT 97.130 178.660 97.350 178.710 ;
        RECT 91.760 178.150 95.820 178.200 ;
        RECT 92.820 177.970 95.820 178.150 ;
        RECT 88.600 177.510 91.600 177.920 ;
        RECT 82.170 177.110 86.940 177.210 ;
        RECT 88.370 177.110 91.600 177.510 ;
        RECT 92.820 177.115 95.820 177.760 ;
        RECT 95.960 177.560 96.960 178.560 ;
        RECT 97.130 177.880 97.770 178.660 ;
        RECT 97.130 177.210 97.350 177.880 ;
        RECT 82.170 176.880 88.170 177.110 ;
        RECT 88.370 176.880 92.000 177.110 ;
        RECT 92.820 176.885 95.825 177.115 ;
        RECT 92.820 176.880 95.820 176.885 ;
        RECT 82.170 176.450 88.170 176.670 ;
        RECT 88.370 176.630 88.640 176.880 ;
        RECT 96.030 176.690 97.350 177.210 ;
        RECT 89.000 176.450 92.000 176.670 ;
        RECT 92.825 176.450 95.825 176.675 ;
        RECT 96.030 176.635 96.260 176.690 ;
        RECT 100.140 176.530 101.140 177.610 ;
        RECT 96.400 176.450 101.140 176.530 ;
        RECT 76.100 176.100 101.140 176.450 ;
        RECT 68.700 176.020 101.140 176.100 ;
        RECT 68.700 175.540 77.140 176.020 ;
        RECT 45.930 174.310 47.900 174.650 ;
        RECT 55.100 174.310 56.100 175.310 ;
        RECT 35.400 174.010 56.100 174.310 ;
        RECT 35.400 173.780 37.200 174.010 ;
        RECT 38.490 173.980 56.100 174.010 ;
        RECT 35.400 173.170 37.195 173.780 ;
        RECT 33.210 172.480 35.085 172.770 ;
        RECT 35.400 172.730 36.400 173.170 ;
        RECT 36.750 172.855 37.195 173.170 ;
        RECT 36.750 172.850 37.190 172.855 ;
        RECT 37.400 172.850 38.280 173.870 ;
        RECT 38.490 172.850 38.930 173.980 ;
        RECT 40.160 173.740 40.390 173.795 ;
        RECT 40.595 173.755 43.595 173.980 ;
        RECT 44.420 173.760 47.420 173.980 ;
        RECT 39.070 173.220 40.390 173.740 ;
        RECT 47.780 173.550 48.050 173.800 ;
        RECT 48.250 173.760 56.100 173.980 ;
        RECT 40.600 173.545 43.600 173.550 ;
        RECT 40.595 173.315 43.600 173.545 ;
        RECT 44.420 173.320 48.050 173.550 ;
        RECT 48.250 173.320 54.250 173.550 ;
        RECT 35.400 172.480 36.600 172.520 ;
        RECT 36.850 172.480 37.450 172.700 ;
        RECT 33.210 171.540 35.080 172.480 ;
        RECT 35.400 172.290 37.450 172.480 ;
        RECT 35.520 172.260 37.450 172.290 ;
        RECT 37.590 172.610 38.190 172.850 ;
        RECT 39.070 172.640 39.290 173.220 ;
        RECT 38.430 172.610 39.290 172.640 ;
        RECT 33.210 171.210 35.360 171.540 ;
        RECT 35.520 171.480 37.180 172.260 ;
        RECT 37.590 172.120 39.290 172.610 ;
        RECT 37.390 172.000 39.290 172.120 ;
        RECT 37.390 171.760 38.930 172.000 ;
        RECT 39.460 171.870 40.460 172.870 ;
        RECT 40.600 172.670 43.600 173.315 ;
        RECT 44.820 172.920 48.050 173.320 ;
        RECT 44.820 172.510 47.820 172.920 ;
        RECT 40.600 172.280 43.600 172.460 ;
        RECT 40.600 172.230 44.660 172.280 ;
        RECT 37.390 171.730 37.890 171.760 ;
        RECT 38.360 171.720 38.930 171.760 ;
        RECT 38.360 171.530 39.860 171.720 ;
        RECT 33.210 166.810 35.080 171.210 ;
        RECT 35.520 171.130 36.520 171.270 ;
        RECT 35.520 170.380 36.820 171.130 ;
        RECT 36.990 170.910 37.180 171.480 ;
        RECT 37.390 171.320 37.890 171.520 ;
        RECT 37.390 171.050 38.120 171.320 ;
        RECT 36.990 170.720 37.450 170.910 ;
        RECT 37.610 170.730 38.120 171.050 ;
        RECT 37.220 170.460 37.450 170.720 ;
        RECT 38.360 170.550 39.360 171.330 ;
        RECT 39.640 170.880 39.860 171.530 ;
        RECT 40.060 171.410 40.460 171.870 ;
        RECT 41.630 171.530 44.660 172.230 ;
        RECT 44.820 172.130 48.710 172.510 ;
        RECT 49.480 172.130 54.120 173.320 ;
        RECT 55.100 172.890 56.100 173.760 ;
        RECT 56.700 173.320 57.700 174.320 ;
        RECT 58.300 174.310 59.300 175.310 ;
        RECT 39.640 170.550 41.470 170.880 ;
        RECT 41.630 170.820 43.600 171.530 ;
        RECT 44.820 170.820 47.820 171.920 ;
        RECT 48.350 170.880 48.710 172.130 ;
        RECT 37.610 170.380 38.110 170.520 ;
        RECT 41.630 170.380 42.630 170.610 ;
        RECT 44.820 170.380 47.820 170.610 ;
        RECT 48.350 170.550 49.320 170.880 ;
        RECT 49.480 170.820 51.480 171.920 ;
        RECT 52.670 171.130 53.670 172.130 ;
        RECT 58.300 170.610 59.300 171.100 ;
        RECT 49.480 170.380 59.300 170.610 ;
        RECT 35.520 170.320 37.080 170.380 ;
        RECT 37.590 170.320 59.300 170.380 ;
        RECT 35.520 170.040 59.300 170.320 ;
        RECT 58.300 169.680 59.300 170.040 ;
        RECT 73.720 169.430 74.930 175.540 ;
        RECT 80.130 169.430 81.340 176.020 ;
        RECT 85.410 169.430 86.620 176.020 ;
        RECT 91.860 169.430 93.070 176.020 ;
        RECT 96.190 169.430 97.400 176.020 ;
        RECT 112.570 170.430 114.740 179.040 ;
        RECT 114.880 178.670 127.840 178.980 ;
        RECT 114.880 174.660 115.120 178.670 ;
        RECT 115.330 175.510 121.480 178.390 ;
        RECT 115.330 175.500 118.820 175.510 ;
        RECT 114.880 173.660 116.120 174.660 ;
        RECT 119.460 174.180 121.480 175.510 ;
        RECT 121.820 175.460 127.240 178.390 ;
        RECT 127.520 175.630 127.840 178.670 ;
        RECT 129.880 176.130 131.400 179.850 ;
        RECT 131.540 175.460 134.000 184.350 ;
        RECT 121.820 174.480 134.000 175.460 ;
        RECT 114.880 173.170 119.320 173.660 ;
        RECT 114.880 171.410 116.370 173.170 ;
        RECT 112.570 169.430 115.220 170.430 ;
        RECT 55.100 169.030 56.100 169.410 ;
        RECT 59.570 169.030 100.560 169.430 ;
        RECT 53.390 168.800 100.560 169.030 ;
        RECT 45.930 168.350 47.900 168.690 ;
        RECT 53.390 168.430 60.570 168.800 ;
        RECT 60.740 168.615 60.940 168.620 ;
        RECT 53.390 168.350 54.560 168.430 ;
        RECT 35.400 168.050 54.560 168.350 ;
        RECT 35.400 167.820 37.200 168.050 ;
        RECT 38.490 168.020 54.560 168.050 ;
        RECT 35.400 167.210 37.195 167.820 ;
        RECT 33.210 166.520 35.085 166.810 ;
        RECT 35.400 166.770 36.400 167.210 ;
        RECT 36.750 166.895 37.195 167.210 ;
        RECT 36.750 166.890 37.190 166.895 ;
        RECT 37.400 166.890 38.280 167.910 ;
        RECT 38.490 166.890 38.930 168.020 ;
        RECT 40.160 167.780 40.390 167.835 ;
        RECT 40.595 167.795 43.595 168.020 ;
        RECT 44.420 167.800 47.420 168.020 ;
        RECT 39.070 167.260 40.390 167.780 ;
        RECT 47.780 167.590 48.050 167.840 ;
        RECT 48.250 167.800 54.250 168.020 ;
        RECT 55.100 167.990 56.100 168.430 ;
        RECT 60.710 168.325 60.940 168.615 ;
        RECT 61.145 168.575 67.145 168.800 ;
        RECT 67.970 168.580 70.970 168.800 ;
        RECT 60.740 167.960 60.940 168.325 ;
        RECT 59.560 167.680 60.940 167.960 ;
        RECT 40.600 167.585 43.600 167.590 ;
        RECT 40.595 167.355 43.600 167.585 ;
        RECT 44.420 167.360 48.050 167.590 ;
        RECT 48.250 167.360 54.250 167.590 ;
        RECT 35.400 166.520 36.600 166.560 ;
        RECT 36.850 166.520 37.450 166.740 ;
        RECT 33.210 165.580 35.080 166.520 ;
        RECT 35.400 166.330 37.450 166.520 ;
        RECT 35.520 166.300 37.450 166.330 ;
        RECT 37.590 166.650 38.190 166.890 ;
        RECT 39.070 166.650 39.290 167.260 ;
        RECT 37.590 166.430 39.290 166.650 ;
        RECT 33.210 165.250 35.360 165.580 ;
        RECT 35.520 165.520 37.180 166.300 ;
        RECT 37.590 166.160 38.930 166.430 ;
        RECT 37.390 165.800 38.930 166.160 ;
        RECT 39.460 165.910 40.460 166.910 ;
        RECT 40.600 166.710 43.600 167.355 ;
        RECT 44.820 166.960 48.050 167.360 ;
        RECT 44.820 166.550 47.820 166.960 ;
        RECT 40.600 166.320 43.600 166.500 ;
        RECT 40.600 166.270 44.660 166.320 ;
        RECT 37.390 165.770 37.890 165.800 ;
        RECT 38.360 165.760 38.930 165.800 ;
        RECT 38.360 165.570 39.860 165.760 ;
        RECT 33.210 163.470 35.080 165.250 ;
        RECT 35.520 165.170 36.520 165.310 ;
        RECT 35.520 164.420 36.820 165.170 ;
        RECT 36.990 164.950 37.180 165.520 ;
        RECT 37.390 165.360 37.890 165.560 ;
        RECT 37.390 165.090 38.120 165.360 ;
        RECT 36.990 164.760 37.450 164.950 ;
        RECT 37.610 164.770 38.120 165.090 ;
        RECT 37.220 164.500 37.450 164.760 ;
        RECT 38.360 164.590 39.360 165.370 ;
        RECT 39.640 164.920 39.860 165.570 ;
        RECT 40.060 165.450 40.460 165.910 ;
        RECT 41.630 165.570 44.660 166.270 ;
        RECT 44.820 166.170 48.710 166.550 ;
        RECT 49.480 166.170 54.120 167.360 ;
        RECT 59.560 166.960 60.560 167.680 ;
        RECT 60.705 167.240 60.940 167.530 ;
        RECT 61.140 167.490 67.150 168.370 ;
        RECT 39.640 164.590 41.470 164.920 ;
        RECT 41.630 164.860 43.600 165.570 ;
        RECT 44.820 164.860 47.820 165.960 ;
        RECT 48.350 164.920 48.710 166.170 ;
        RECT 37.610 164.420 38.110 164.560 ;
        RECT 41.630 164.420 42.630 164.650 ;
        RECT 44.820 164.420 47.820 164.650 ;
        RECT 48.350 164.590 49.320 164.920 ;
        RECT 49.480 164.860 51.480 165.960 ;
        RECT 52.670 165.170 53.670 166.170 ;
        RECT 60.060 165.580 60.560 166.960 ;
        RECT 60.730 166.720 60.940 167.240 ;
        RECT 61.140 167.050 67.810 167.280 ;
        RECT 60.730 166.190 63.250 166.720 ;
        RECT 61.770 165.720 63.250 166.190 ;
        RECT 63.580 166.210 67.810 167.050 ;
        RECT 60.060 165.240 63.420 165.580 ;
        RECT 58.300 164.650 59.300 165.110 ;
        RECT 60.640 164.750 61.640 165.080 ;
        RECT 61.860 164.750 62.920 165.100 ;
        RECT 63.140 164.890 63.420 165.240 ;
        RECT 63.580 165.140 64.580 166.210 ;
        RECT 66.900 165.880 67.810 166.210 ;
        RECT 67.970 166.150 70.970 168.370 ;
        RECT 72.240 167.930 72.420 168.800 ;
        RECT 72.565 168.580 77.095 168.800 ;
        RECT 72.565 168.140 77.620 168.370 ;
        RECT 72.240 167.810 73.130 167.930 ;
        RECT 71.585 167.120 71.815 167.410 ;
        RECT 72.130 167.370 73.130 167.810 ;
        RECT 73.330 167.160 73.870 168.000 ;
        RECT 71.520 166.300 71.810 167.120 ;
        RECT 72.130 166.930 73.870 167.160 ;
        RECT 63.580 164.750 64.580 164.930 ;
        RECT 64.890 164.750 66.010 165.380 ;
        RECT 67.970 165.140 70.970 165.940 ;
        RECT 67.970 164.750 70.970 164.930 ;
        RECT 71.390 164.910 72.090 166.300 ;
        RECT 72.250 166.120 73.870 166.930 ;
        RECT 74.390 166.030 77.620 168.140 ;
        RECT 77.790 167.920 78.050 168.800 ;
        RECT 78.200 168.060 78.540 168.660 ;
        RECT 78.690 168.580 84.690 168.800 ;
        RECT 85.560 168.580 91.560 168.800 ;
        RECT 78.690 168.140 84.690 168.370 ;
        RECT 77.790 167.660 80.270 167.920 ;
        RECT 81.730 167.880 84.690 168.140 ;
        RECT 85.560 167.880 91.560 168.370 ;
        RECT 81.730 167.870 91.560 167.880 ;
        RECT 78.725 167.130 78.955 167.420 ;
        RECT 79.270 167.380 80.270 167.660 ;
        RECT 81.070 167.170 82.070 167.700 ;
        RECT 79.270 167.160 82.070 167.170 ;
        RECT 82.270 167.570 91.560 167.870 ;
        RECT 82.270 167.160 92.210 167.570 ;
        RECT 92.410 167.510 94.410 168.800 ;
        RECT 94.815 168.560 95.045 168.620 ;
        RECT 95.250 168.580 100.250 168.800 ;
        RECT 78.660 166.220 78.950 167.130 ;
        RECT 79.270 166.940 81.540 167.160 ;
        RECT 72.250 164.750 73.250 165.910 ;
        RECT 74.910 165.150 77.620 166.030 ;
        RECT 77.910 166.190 78.950 166.220 ;
        RECT 77.910 165.860 79.230 166.190 ;
        RECT 79.390 166.130 81.540 166.940 ;
        RECT 82.280 166.150 92.210 167.160 ;
        RECT 77.910 165.180 78.910 165.860 ;
        RECT 74.920 165.140 76.920 165.150 ;
        RECT 74.920 164.750 76.920 164.930 ;
        RECT 79.390 164.750 80.390 165.920 ;
        RECT 82.280 165.710 84.280 165.940 ;
        RECT 87.460 165.870 92.210 166.150 ;
        RECT 80.680 164.930 82.130 165.650 ;
        RECT 82.290 165.370 84.280 165.710 ;
        RECT 82.290 165.140 84.290 165.370 ;
        RECT 81.900 164.890 82.130 164.930 ;
        RECT 82.290 164.750 84.290 164.930 ;
        RECT 85.290 164.750 86.660 165.870 ;
        RECT 87.460 165.140 89.460 165.870 ;
        RECT 87.460 164.750 89.460 164.930 ;
        RECT 91.890 164.890 92.210 165.870 ;
        RECT 92.370 166.710 94.410 167.300 ;
        RECT 94.610 166.710 95.050 168.560 ;
        RECT 112.570 168.440 114.740 169.430 ;
        RECT 115.880 169.265 116.370 171.410 ;
        RECT 115.930 169.260 116.370 169.265 ;
        RECT 116.590 168.440 118.820 172.010 ;
        RECT 118.970 169.000 119.320 173.170 ;
        RECT 119.460 172.930 128.970 174.180 ;
        RECT 119.460 169.280 121.480 172.930 ;
        RECT 121.680 169.000 122.260 172.310 ;
        RECT 126.810 172.270 128.970 172.930 ;
        RECT 131.540 172.810 134.000 174.480 ;
        RECT 131.230 171.810 134.000 172.810 ;
        RECT 118.970 168.580 122.260 169.000 ;
        RECT 122.700 170.240 130.400 171.680 ;
        RECT 122.700 168.440 123.050 170.240 ;
        RECT 95.250 167.840 100.250 168.370 ;
        RECT 95.250 167.000 100.560 167.840 ;
        RECT 96.450 166.840 100.560 167.000 ;
        RECT 112.570 166.990 123.050 168.440 ;
        RECT 126.810 167.310 131.400 169.670 ;
        RECT 92.370 165.710 95.410 166.710 ;
        RECT 92.370 165.140 94.410 165.710 ;
        RECT 94.770 165.290 95.410 165.710 ;
        RECT 96.450 166.000 100.450 166.840 ;
        RECT 94.770 164.950 96.290 165.290 ;
        RECT 96.450 165.140 98.450 166.000 ;
        RECT 99.450 165.840 100.450 166.000 ;
        RECT 92.370 164.750 93.370 164.930 ;
        RECT 96.060 164.890 96.290 164.950 ;
        RECT 96.450 164.750 98.450 164.930 ;
        RECT 60.640 164.650 100.560 164.750 ;
        RECT 49.480 164.420 100.560 164.650 ;
        RECT 35.520 164.360 37.080 164.420 ;
        RECT 37.590 164.360 100.560 164.420 ;
        RECT 35.520 164.080 100.560 164.360 ;
        RECT 58.300 163.690 59.300 164.080 ;
        RECT 33.210 163.020 41.350 163.470 ;
        RECT 33.210 159.460 35.080 163.020 ;
        RECT 55.100 161.680 56.100 162.060 ;
        RECT 59.570 161.680 100.560 162.080 ;
        RECT 53.390 161.450 100.560 161.680 ;
        RECT 45.930 161.000 47.900 161.340 ;
        RECT 53.390 161.080 60.570 161.450 ;
        RECT 60.740 161.265 60.940 161.270 ;
        RECT 53.390 161.000 54.560 161.080 ;
        RECT 35.400 160.700 54.560 161.000 ;
        RECT 35.400 160.470 37.200 160.700 ;
        RECT 38.490 160.670 54.560 160.700 ;
        RECT 35.400 159.860 37.195 160.470 ;
        RECT 33.210 159.170 35.085 159.460 ;
        RECT 35.400 159.420 36.400 159.860 ;
        RECT 36.750 159.545 37.195 159.860 ;
        RECT 36.750 159.540 37.190 159.545 ;
        RECT 37.400 159.540 38.280 160.560 ;
        RECT 38.490 159.540 38.930 160.670 ;
        RECT 40.160 160.430 40.390 160.485 ;
        RECT 40.595 160.445 43.595 160.670 ;
        RECT 44.420 160.450 47.420 160.670 ;
        RECT 39.070 159.910 40.390 160.430 ;
        RECT 47.780 160.240 48.050 160.490 ;
        RECT 48.250 160.450 54.250 160.670 ;
        RECT 55.100 160.640 56.100 161.080 ;
        RECT 60.710 160.975 60.940 161.265 ;
        RECT 61.145 161.225 67.145 161.450 ;
        RECT 67.970 161.230 70.970 161.450 ;
        RECT 60.740 160.610 60.940 160.975 ;
        RECT 59.560 160.330 60.940 160.610 ;
        RECT 40.600 160.235 43.600 160.240 ;
        RECT 40.595 160.005 43.600 160.235 ;
        RECT 44.420 160.010 48.050 160.240 ;
        RECT 48.250 160.010 54.250 160.240 ;
        RECT 35.400 159.170 36.600 159.210 ;
        RECT 36.850 159.170 37.450 159.390 ;
        RECT 33.210 158.230 35.080 159.170 ;
        RECT 35.400 158.980 37.450 159.170 ;
        RECT 35.520 158.950 37.450 158.980 ;
        RECT 37.590 159.300 38.190 159.540 ;
        RECT 39.070 159.300 39.290 159.910 ;
        RECT 37.590 159.080 39.290 159.300 ;
        RECT 33.210 157.900 35.360 158.230 ;
        RECT 35.520 158.170 37.180 158.950 ;
        RECT 37.590 158.810 38.930 159.080 ;
        RECT 37.390 158.450 38.930 158.810 ;
        RECT 39.460 158.560 40.460 159.560 ;
        RECT 40.600 159.360 43.600 160.005 ;
        RECT 44.820 159.610 48.050 160.010 ;
        RECT 44.820 159.200 47.820 159.610 ;
        RECT 40.600 158.970 43.600 159.150 ;
        RECT 40.600 158.920 44.660 158.970 ;
        RECT 37.390 158.420 37.890 158.450 ;
        RECT 38.360 158.410 38.930 158.450 ;
        RECT 38.360 158.220 39.860 158.410 ;
        RECT 33.210 156.120 35.080 157.900 ;
        RECT 35.520 157.820 36.520 157.960 ;
        RECT 35.520 157.070 36.820 157.820 ;
        RECT 36.990 157.600 37.180 158.170 ;
        RECT 37.390 158.010 37.890 158.210 ;
        RECT 37.390 157.740 38.120 158.010 ;
        RECT 36.990 157.410 37.450 157.600 ;
        RECT 37.610 157.420 38.120 157.740 ;
        RECT 37.220 157.150 37.450 157.410 ;
        RECT 38.360 157.240 39.360 158.020 ;
        RECT 39.640 157.570 39.860 158.220 ;
        RECT 40.060 158.100 40.460 158.560 ;
        RECT 41.630 158.220 44.660 158.920 ;
        RECT 44.820 158.820 48.710 159.200 ;
        RECT 49.480 158.820 54.120 160.010 ;
        RECT 59.560 159.610 60.560 160.330 ;
        RECT 60.705 159.890 60.940 160.180 ;
        RECT 61.140 160.140 67.150 161.020 ;
        RECT 39.640 157.240 41.470 157.570 ;
        RECT 41.630 157.510 43.600 158.220 ;
        RECT 44.820 157.510 47.820 158.610 ;
        RECT 48.350 157.570 48.710 158.820 ;
        RECT 37.610 157.070 38.110 157.210 ;
        RECT 41.630 157.070 42.630 157.300 ;
        RECT 44.820 157.070 47.820 157.300 ;
        RECT 48.350 157.240 49.320 157.570 ;
        RECT 49.480 157.510 51.480 158.610 ;
        RECT 52.670 157.820 53.670 158.820 ;
        RECT 60.060 158.230 60.560 159.610 ;
        RECT 60.730 159.370 60.940 159.890 ;
        RECT 61.140 159.700 67.810 159.930 ;
        RECT 60.730 158.840 63.250 159.370 ;
        RECT 61.770 158.370 63.250 158.840 ;
        RECT 63.580 158.860 67.810 159.700 ;
        RECT 60.060 157.890 63.420 158.230 ;
        RECT 58.300 157.300 59.300 157.760 ;
        RECT 60.640 157.400 61.640 157.730 ;
        RECT 61.860 157.400 62.920 157.750 ;
        RECT 63.140 157.540 63.420 157.890 ;
        RECT 63.580 157.790 64.580 158.860 ;
        RECT 66.900 158.530 67.810 158.860 ;
        RECT 67.970 158.800 70.970 161.020 ;
        RECT 72.240 160.580 72.420 161.450 ;
        RECT 72.565 161.230 77.095 161.450 ;
        RECT 72.565 160.790 77.620 161.020 ;
        RECT 72.240 160.460 73.130 160.580 ;
        RECT 71.585 159.770 71.815 160.060 ;
        RECT 72.130 160.020 73.130 160.460 ;
        RECT 73.330 159.810 73.870 160.650 ;
        RECT 71.520 158.950 71.810 159.770 ;
        RECT 72.130 159.580 73.870 159.810 ;
        RECT 63.580 157.400 64.580 157.580 ;
        RECT 64.890 157.400 66.010 158.030 ;
        RECT 67.970 157.790 70.970 158.590 ;
        RECT 67.970 157.400 70.970 157.580 ;
        RECT 71.390 157.560 72.090 158.950 ;
        RECT 72.250 158.770 73.870 159.580 ;
        RECT 74.390 158.680 77.620 160.790 ;
        RECT 77.790 160.570 78.050 161.450 ;
        RECT 78.200 160.710 78.540 161.310 ;
        RECT 78.690 161.230 84.690 161.450 ;
        RECT 85.560 161.230 91.560 161.450 ;
        RECT 78.690 160.790 84.690 161.020 ;
        RECT 77.790 160.310 80.270 160.570 ;
        RECT 81.730 160.530 84.690 160.790 ;
        RECT 85.560 160.530 91.560 161.020 ;
        RECT 81.730 160.520 91.560 160.530 ;
        RECT 78.725 159.780 78.955 160.070 ;
        RECT 79.270 160.030 80.270 160.310 ;
        RECT 81.070 159.820 82.070 160.350 ;
        RECT 79.270 159.810 82.070 159.820 ;
        RECT 82.270 160.220 91.560 160.520 ;
        RECT 82.270 159.810 92.210 160.220 ;
        RECT 92.410 160.160 94.410 161.450 ;
        RECT 94.815 161.210 95.045 161.270 ;
        RECT 95.250 161.230 100.250 161.450 ;
        RECT 78.660 158.870 78.950 159.780 ;
        RECT 79.270 159.590 81.540 159.810 ;
        RECT 72.250 157.400 73.250 158.560 ;
        RECT 74.910 157.800 77.620 158.680 ;
        RECT 77.910 158.840 78.950 158.870 ;
        RECT 77.910 158.510 79.230 158.840 ;
        RECT 79.390 158.780 81.540 159.590 ;
        RECT 82.280 158.800 92.210 159.810 ;
        RECT 77.910 157.830 78.910 158.510 ;
        RECT 74.920 157.790 76.920 157.800 ;
        RECT 74.920 157.400 76.920 157.580 ;
        RECT 79.390 157.400 80.390 158.570 ;
        RECT 82.280 158.360 84.280 158.590 ;
        RECT 87.460 158.520 92.210 158.800 ;
        RECT 80.680 157.580 82.130 158.300 ;
        RECT 82.290 158.020 84.280 158.360 ;
        RECT 82.290 157.790 84.290 158.020 ;
        RECT 81.900 157.540 82.130 157.580 ;
        RECT 82.290 157.400 84.290 157.580 ;
        RECT 85.290 157.400 86.660 158.520 ;
        RECT 87.460 157.790 89.460 158.520 ;
        RECT 87.460 157.400 89.460 157.580 ;
        RECT 91.890 157.540 92.210 158.520 ;
        RECT 92.370 159.360 94.410 159.950 ;
        RECT 94.610 159.360 95.050 161.210 ;
        RECT 95.250 160.490 100.250 161.020 ;
        RECT 95.250 159.650 100.560 160.490 ;
        RECT 96.450 159.490 100.560 159.650 ;
        RECT 92.370 158.360 95.410 159.360 ;
        RECT 92.370 157.790 94.410 158.360 ;
        RECT 94.770 157.940 95.410 158.360 ;
        RECT 96.450 158.650 100.450 159.490 ;
        RECT 94.770 157.600 96.290 157.940 ;
        RECT 96.450 157.790 98.450 158.650 ;
        RECT 99.450 158.490 100.450 158.650 ;
        RECT 112.570 157.890 114.740 166.990 ;
        RECT 114.880 166.130 127.840 166.440 ;
        RECT 114.880 162.120 115.120 166.130 ;
        RECT 115.330 162.970 121.480 165.850 ;
        RECT 115.330 162.960 118.820 162.970 ;
        RECT 114.880 161.120 116.120 162.120 ;
        RECT 119.460 161.640 121.480 162.970 ;
        RECT 121.820 162.920 127.240 165.850 ;
        RECT 127.520 163.090 127.840 166.130 ;
        RECT 129.880 163.590 131.400 167.310 ;
        RECT 131.540 162.920 134.000 171.810 ;
        RECT 121.820 161.940 134.000 162.920 ;
        RECT 114.880 160.630 119.320 161.120 ;
        RECT 114.880 158.870 116.370 160.630 ;
        RECT 92.370 157.400 93.370 157.580 ;
        RECT 96.060 157.540 96.290 157.600 ;
        RECT 96.450 157.400 98.450 157.580 ;
        RECT 60.640 157.300 100.560 157.400 ;
        RECT 49.480 157.070 100.560 157.300 ;
        RECT 35.520 157.010 37.080 157.070 ;
        RECT 37.590 157.010 100.560 157.070 ;
        RECT 35.520 156.730 100.560 157.010 ;
        RECT 112.570 156.890 115.220 157.890 ;
        RECT 58.300 156.340 59.300 156.730 ;
        RECT 33.210 155.670 41.350 156.120 ;
        RECT 112.570 155.900 114.740 156.890 ;
        RECT 115.880 156.725 116.370 158.870 ;
        RECT 115.930 156.720 116.370 156.725 ;
        RECT 116.590 155.900 118.820 159.470 ;
        RECT 118.970 156.460 119.320 160.630 ;
        RECT 119.460 160.390 128.970 161.640 ;
        RECT 119.460 156.740 121.480 160.390 ;
        RECT 121.680 156.460 122.260 159.770 ;
        RECT 126.810 159.730 128.970 160.390 ;
        RECT 131.540 160.270 134.000 161.940 ;
        RECT 131.230 159.270 134.000 160.270 ;
        RECT 118.970 156.040 122.260 156.460 ;
        RECT 122.700 157.700 130.400 159.140 ;
        RECT 122.700 155.900 123.050 157.700 ;
        RECT 33.210 152.110 35.080 155.670 ;
        RECT 55.100 154.330 56.100 154.710 ;
        RECT 59.570 154.330 100.560 154.730 ;
        RECT 53.390 154.100 100.560 154.330 ;
        RECT 112.570 154.450 123.050 155.900 ;
        RECT 126.810 154.770 131.400 157.130 ;
        RECT 45.930 153.650 47.900 153.990 ;
        RECT 53.390 153.730 60.570 154.100 ;
        RECT 60.740 153.915 60.940 153.920 ;
        RECT 53.390 153.650 54.560 153.730 ;
        RECT 35.400 153.350 54.560 153.650 ;
        RECT 35.400 153.120 37.200 153.350 ;
        RECT 38.490 153.320 54.560 153.350 ;
        RECT 35.400 152.510 37.195 153.120 ;
        RECT 33.210 151.820 35.085 152.110 ;
        RECT 35.400 152.070 36.400 152.510 ;
        RECT 36.750 152.195 37.195 152.510 ;
        RECT 36.750 152.190 37.190 152.195 ;
        RECT 37.400 152.190 38.280 153.210 ;
        RECT 38.490 152.190 38.930 153.320 ;
        RECT 40.160 153.080 40.390 153.135 ;
        RECT 40.595 153.095 43.595 153.320 ;
        RECT 44.420 153.100 47.420 153.320 ;
        RECT 39.070 152.560 40.390 153.080 ;
        RECT 47.780 152.890 48.050 153.140 ;
        RECT 48.250 153.100 54.250 153.320 ;
        RECT 55.100 153.290 56.100 153.730 ;
        RECT 60.710 153.625 60.940 153.915 ;
        RECT 61.145 153.875 67.145 154.100 ;
        RECT 67.970 153.880 70.970 154.100 ;
        RECT 60.740 153.260 60.940 153.625 ;
        RECT 59.560 152.980 60.940 153.260 ;
        RECT 40.600 152.885 43.600 152.890 ;
        RECT 40.595 152.655 43.600 152.885 ;
        RECT 44.420 152.660 48.050 152.890 ;
        RECT 48.250 152.660 54.250 152.890 ;
        RECT 35.400 151.820 36.600 151.860 ;
        RECT 36.850 151.820 37.450 152.040 ;
        RECT 33.210 150.880 35.080 151.820 ;
        RECT 35.400 151.630 37.450 151.820 ;
        RECT 35.520 151.600 37.450 151.630 ;
        RECT 37.590 151.950 38.190 152.190 ;
        RECT 39.070 151.950 39.290 152.560 ;
        RECT 37.590 151.730 39.290 151.950 ;
        RECT 33.210 150.550 35.360 150.880 ;
        RECT 35.520 150.820 37.180 151.600 ;
        RECT 37.590 151.460 38.930 151.730 ;
        RECT 37.390 151.100 38.930 151.460 ;
        RECT 39.460 151.210 40.460 152.210 ;
        RECT 40.600 152.010 43.600 152.655 ;
        RECT 44.820 152.260 48.050 152.660 ;
        RECT 44.820 151.850 47.820 152.260 ;
        RECT 40.600 151.620 43.600 151.800 ;
        RECT 40.600 151.570 44.660 151.620 ;
        RECT 37.390 151.070 37.890 151.100 ;
        RECT 38.360 151.060 38.930 151.100 ;
        RECT 38.360 150.870 39.860 151.060 ;
        RECT 33.210 148.770 35.080 150.550 ;
        RECT 35.520 150.470 36.520 150.610 ;
        RECT 35.520 149.720 36.820 150.470 ;
        RECT 36.990 150.250 37.180 150.820 ;
        RECT 37.390 150.660 37.890 150.860 ;
        RECT 37.390 150.390 38.120 150.660 ;
        RECT 36.990 150.060 37.450 150.250 ;
        RECT 37.610 150.070 38.120 150.390 ;
        RECT 37.220 149.800 37.450 150.060 ;
        RECT 38.360 149.890 39.360 150.670 ;
        RECT 39.640 150.220 39.860 150.870 ;
        RECT 40.060 150.750 40.460 151.210 ;
        RECT 41.630 150.870 44.660 151.570 ;
        RECT 44.820 151.470 48.710 151.850 ;
        RECT 49.480 151.470 54.120 152.660 ;
        RECT 59.560 152.260 60.560 152.980 ;
        RECT 60.705 152.540 60.940 152.830 ;
        RECT 61.140 152.790 67.150 153.670 ;
        RECT 39.640 149.890 41.470 150.220 ;
        RECT 41.630 150.160 43.600 150.870 ;
        RECT 44.820 150.160 47.820 151.260 ;
        RECT 48.350 150.220 48.710 151.470 ;
        RECT 37.610 149.720 38.110 149.860 ;
        RECT 41.630 149.720 42.630 149.950 ;
        RECT 44.820 149.720 47.820 149.950 ;
        RECT 48.350 149.890 49.320 150.220 ;
        RECT 49.480 150.160 51.480 151.260 ;
        RECT 52.670 150.470 53.670 151.470 ;
        RECT 60.060 150.880 60.560 152.260 ;
        RECT 60.730 152.020 60.940 152.540 ;
        RECT 61.140 152.350 67.810 152.580 ;
        RECT 60.730 151.490 63.250 152.020 ;
        RECT 61.770 151.020 63.250 151.490 ;
        RECT 63.580 151.510 67.810 152.350 ;
        RECT 60.060 150.540 63.420 150.880 ;
        RECT 58.300 149.950 59.300 150.410 ;
        RECT 60.640 150.050 61.640 150.380 ;
        RECT 61.860 150.050 62.920 150.400 ;
        RECT 63.140 150.190 63.420 150.540 ;
        RECT 63.580 150.440 64.580 151.510 ;
        RECT 66.900 151.180 67.810 151.510 ;
        RECT 67.970 151.450 70.970 153.670 ;
        RECT 72.240 153.230 72.420 154.100 ;
        RECT 72.565 153.880 77.095 154.100 ;
        RECT 72.565 153.440 77.620 153.670 ;
        RECT 72.240 153.110 73.130 153.230 ;
        RECT 71.585 152.420 71.815 152.710 ;
        RECT 72.130 152.670 73.130 153.110 ;
        RECT 73.330 152.460 73.870 153.300 ;
        RECT 71.520 151.600 71.810 152.420 ;
        RECT 72.130 152.230 73.870 152.460 ;
        RECT 63.580 150.050 64.580 150.230 ;
        RECT 64.890 150.050 66.010 150.680 ;
        RECT 67.970 150.440 70.970 151.240 ;
        RECT 67.970 150.050 70.970 150.230 ;
        RECT 71.390 150.210 72.090 151.600 ;
        RECT 72.250 151.420 73.870 152.230 ;
        RECT 74.390 151.330 77.620 153.440 ;
        RECT 77.790 153.220 78.050 154.100 ;
        RECT 78.200 153.360 78.540 153.960 ;
        RECT 78.690 153.880 84.690 154.100 ;
        RECT 85.560 153.880 91.560 154.100 ;
        RECT 78.690 153.440 84.690 153.670 ;
        RECT 77.790 152.960 80.270 153.220 ;
        RECT 81.730 153.180 84.690 153.440 ;
        RECT 85.560 153.180 91.560 153.670 ;
        RECT 81.730 153.170 91.560 153.180 ;
        RECT 78.725 152.430 78.955 152.720 ;
        RECT 79.270 152.680 80.270 152.960 ;
        RECT 81.070 152.470 82.070 153.000 ;
        RECT 79.270 152.460 82.070 152.470 ;
        RECT 82.270 152.870 91.560 153.170 ;
        RECT 82.270 152.460 92.210 152.870 ;
        RECT 92.410 152.810 94.410 154.100 ;
        RECT 94.815 153.860 95.045 153.920 ;
        RECT 95.250 153.880 100.250 154.100 ;
        RECT 78.660 151.520 78.950 152.430 ;
        RECT 79.270 152.240 81.540 152.460 ;
        RECT 72.250 150.050 73.250 151.210 ;
        RECT 74.910 150.450 77.620 151.330 ;
        RECT 77.910 151.490 78.950 151.520 ;
        RECT 77.910 151.160 79.230 151.490 ;
        RECT 79.390 151.430 81.540 152.240 ;
        RECT 82.280 151.450 92.210 152.460 ;
        RECT 77.910 150.480 78.910 151.160 ;
        RECT 74.920 150.440 76.920 150.450 ;
        RECT 74.920 150.050 76.920 150.230 ;
        RECT 79.390 150.050 80.390 151.220 ;
        RECT 82.280 151.010 84.280 151.240 ;
        RECT 87.460 151.170 92.210 151.450 ;
        RECT 80.680 150.230 82.130 150.950 ;
        RECT 82.290 150.670 84.280 151.010 ;
        RECT 82.290 150.440 84.290 150.670 ;
        RECT 81.900 150.190 82.130 150.230 ;
        RECT 82.290 150.050 84.290 150.230 ;
        RECT 85.290 150.050 86.660 151.170 ;
        RECT 87.460 150.440 89.460 151.170 ;
        RECT 87.460 150.050 89.460 150.230 ;
        RECT 91.890 150.190 92.210 151.170 ;
        RECT 92.370 152.010 94.410 152.600 ;
        RECT 94.610 152.010 95.050 153.860 ;
        RECT 95.250 153.140 100.250 153.670 ;
        RECT 95.250 152.300 100.560 153.140 ;
        RECT 96.450 152.140 100.560 152.300 ;
        RECT 92.370 151.010 95.410 152.010 ;
        RECT 92.370 150.440 94.410 151.010 ;
        RECT 94.770 150.590 95.410 151.010 ;
        RECT 96.450 151.300 100.450 152.140 ;
        RECT 94.770 150.250 96.290 150.590 ;
        RECT 96.450 150.440 98.450 151.300 ;
        RECT 99.450 151.140 100.450 151.300 ;
        RECT 92.370 150.050 93.370 150.230 ;
        RECT 96.060 150.190 96.290 150.250 ;
        RECT 96.450 150.050 98.450 150.230 ;
        RECT 60.640 149.950 100.560 150.050 ;
        RECT 49.480 149.720 100.560 149.950 ;
        RECT 35.520 149.660 37.080 149.720 ;
        RECT 37.590 149.660 100.560 149.720 ;
        RECT 35.520 149.380 100.560 149.660 ;
        RECT 58.300 148.990 59.300 149.380 ;
        RECT 33.210 148.320 41.350 148.770 ;
        RECT 33.210 144.760 35.080 148.320 ;
        RECT 55.110 146.980 56.110 147.360 ;
        RECT 59.570 146.980 100.560 147.380 ;
        RECT 53.400 146.750 100.560 146.980 ;
        RECT 45.930 146.300 47.900 146.640 ;
        RECT 53.400 146.380 60.570 146.750 ;
        RECT 60.740 146.565 60.940 146.570 ;
        RECT 53.400 146.300 54.570 146.380 ;
        RECT 35.400 146.280 54.570 146.300 ;
        RECT 35.400 146.000 54.560 146.280 ;
        RECT 35.400 145.770 37.200 146.000 ;
        RECT 38.490 145.970 54.560 146.000 ;
        RECT 35.400 145.160 37.195 145.770 ;
        RECT 33.210 144.470 35.085 144.760 ;
        RECT 35.400 144.720 36.400 145.160 ;
        RECT 36.750 144.845 37.195 145.160 ;
        RECT 36.750 144.840 37.190 144.845 ;
        RECT 37.400 144.840 38.280 145.860 ;
        RECT 38.490 144.840 38.930 145.970 ;
        RECT 40.160 145.730 40.390 145.785 ;
        RECT 40.595 145.745 43.595 145.970 ;
        RECT 44.420 145.750 47.420 145.970 ;
        RECT 39.070 145.210 40.390 145.730 ;
        RECT 47.780 145.540 48.050 145.790 ;
        RECT 48.250 145.750 54.250 145.970 ;
        RECT 55.110 145.940 56.110 146.380 ;
        RECT 60.710 146.275 60.940 146.565 ;
        RECT 61.145 146.525 67.145 146.750 ;
        RECT 67.970 146.530 70.970 146.750 ;
        RECT 60.740 145.910 60.940 146.275 ;
        RECT 59.560 145.630 60.940 145.910 ;
        RECT 40.600 145.535 43.600 145.540 ;
        RECT 40.595 145.305 43.600 145.535 ;
        RECT 44.420 145.310 48.050 145.540 ;
        RECT 48.250 145.310 54.250 145.540 ;
        RECT 35.400 144.470 36.600 144.510 ;
        RECT 36.850 144.470 37.450 144.690 ;
        RECT 33.210 143.530 35.080 144.470 ;
        RECT 35.400 144.280 37.450 144.470 ;
        RECT 35.520 144.250 37.450 144.280 ;
        RECT 37.590 144.600 38.190 144.840 ;
        RECT 39.070 144.600 39.290 145.210 ;
        RECT 37.590 144.380 39.290 144.600 ;
        RECT 33.210 143.200 35.360 143.530 ;
        RECT 35.520 143.470 37.180 144.250 ;
        RECT 37.590 144.110 38.930 144.380 ;
        RECT 37.390 143.750 38.930 144.110 ;
        RECT 39.460 143.860 40.460 144.860 ;
        RECT 40.600 144.660 43.600 145.305 ;
        RECT 44.820 144.910 48.050 145.310 ;
        RECT 44.820 144.500 47.820 144.910 ;
        RECT 40.600 144.270 43.600 144.450 ;
        RECT 40.600 144.220 44.660 144.270 ;
        RECT 37.390 143.720 37.890 143.750 ;
        RECT 38.360 143.710 38.930 143.750 ;
        RECT 38.360 143.520 39.860 143.710 ;
        RECT 33.210 141.420 35.080 143.200 ;
        RECT 35.520 143.120 36.520 143.260 ;
        RECT 35.520 142.370 36.820 143.120 ;
        RECT 36.990 142.900 37.180 143.470 ;
        RECT 37.390 143.310 37.890 143.510 ;
        RECT 37.390 143.040 38.120 143.310 ;
        RECT 36.990 142.710 37.450 142.900 ;
        RECT 37.610 142.720 38.120 143.040 ;
        RECT 37.220 142.450 37.450 142.710 ;
        RECT 38.360 142.540 39.360 143.320 ;
        RECT 39.640 142.870 39.860 143.520 ;
        RECT 40.060 143.400 40.460 143.860 ;
        RECT 41.630 143.520 44.660 144.220 ;
        RECT 44.820 144.120 48.710 144.500 ;
        RECT 49.480 144.120 54.120 145.310 ;
        RECT 59.560 144.910 60.560 145.630 ;
        RECT 60.705 145.190 60.940 145.480 ;
        RECT 61.140 145.440 67.150 146.320 ;
        RECT 39.640 142.540 41.470 142.870 ;
        RECT 41.630 142.810 43.600 143.520 ;
        RECT 44.820 142.810 47.820 143.910 ;
        RECT 48.350 142.870 48.710 144.120 ;
        RECT 37.610 142.370 38.110 142.510 ;
        RECT 41.630 142.370 42.630 142.600 ;
        RECT 44.820 142.370 47.820 142.600 ;
        RECT 48.350 142.540 49.320 142.870 ;
        RECT 49.480 142.810 51.480 143.910 ;
        RECT 52.670 143.120 53.670 144.120 ;
        RECT 60.060 143.530 60.560 144.910 ;
        RECT 60.730 144.670 60.940 145.190 ;
        RECT 61.140 145.000 67.810 145.230 ;
        RECT 60.730 144.140 63.250 144.670 ;
        RECT 61.770 143.670 63.250 144.140 ;
        RECT 63.580 144.160 67.810 145.000 ;
        RECT 60.060 143.190 63.420 143.530 ;
        RECT 58.310 142.600 59.310 143.060 ;
        RECT 60.640 142.700 61.640 143.030 ;
        RECT 61.860 142.700 62.920 143.050 ;
        RECT 63.140 142.840 63.420 143.190 ;
        RECT 63.580 143.090 64.580 144.160 ;
        RECT 66.900 143.830 67.810 144.160 ;
        RECT 67.970 144.100 70.970 146.320 ;
        RECT 72.240 145.880 72.420 146.750 ;
        RECT 72.565 146.530 77.095 146.750 ;
        RECT 72.565 146.090 77.620 146.320 ;
        RECT 72.240 145.760 73.130 145.880 ;
        RECT 71.585 145.070 71.815 145.360 ;
        RECT 72.130 145.320 73.130 145.760 ;
        RECT 73.330 145.110 73.870 145.950 ;
        RECT 71.520 144.250 71.810 145.070 ;
        RECT 72.130 144.880 73.870 145.110 ;
        RECT 63.580 142.700 64.580 142.880 ;
        RECT 64.890 142.700 66.010 143.330 ;
        RECT 67.970 143.090 70.970 143.890 ;
        RECT 67.970 142.700 70.970 142.880 ;
        RECT 71.390 142.860 72.090 144.250 ;
        RECT 72.250 144.070 73.870 144.880 ;
        RECT 74.390 143.980 77.620 146.090 ;
        RECT 77.790 145.870 78.050 146.750 ;
        RECT 78.200 146.010 78.540 146.610 ;
        RECT 78.690 146.530 84.690 146.750 ;
        RECT 85.560 146.530 91.560 146.750 ;
        RECT 78.690 146.090 84.690 146.320 ;
        RECT 77.790 145.610 80.270 145.870 ;
        RECT 81.730 145.830 84.690 146.090 ;
        RECT 85.560 145.830 91.560 146.320 ;
        RECT 81.730 145.820 91.560 145.830 ;
        RECT 78.725 145.080 78.955 145.370 ;
        RECT 79.270 145.330 80.270 145.610 ;
        RECT 81.070 145.120 82.070 145.650 ;
        RECT 79.270 145.110 82.070 145.120 ;
        RECT 82.270 145.520 91.560 145.820 ;
        RECT 82.270 145.110 92.210 145.520 ;
        RECT 92.410 145.460 94.410 146.750 ;
        RECT 94.815 146.510 95.045 146.570 ;
        RECT 95.250 146.530 100.250 146.750 ;
        RECT 78.660 144.170 78.950 145.080 ;
        RECT 79.270 144.890 81.540 145.110 ;
        RECT 72.250 142.700 73.250 143.860 ;
        RECT 74.910 143.100 77.620 143.980 ;
        RECT 77.910 144.140 78.950 144.170 ;
        RECT 77.910 143.810 79.230 144.140 ;
        RECT 79.390 144.080 81.540 144.890 ;
        RECT 82.280 144.100 92.210 145.110 ;
        RECT 77.910 143.130 78.910 143.810 ;
        RECT 74.920 143.090 76.920 143.100 ;
        RECT 74.920 142.700 76.920 142.880 ;
        RECT 79.390 142.700 80.390 143.870 ;
        RECT 82.280 143.660 84.280 143.890 ;
        RECT 87.460 143.820 92.210 144.100 ;
        RECT 80.680 142.880 82.130 143.600 ;
        RECT 82.290 143.320 84.280 143.660 ;
        RECT 82.290 143.090 84.290 143.320 ;
        RECT 81.900 142.840 82.130 142.880 ;
        RECT 82.290 142.700 84.290 142.880 ;
        RECT 85.290 142.700 86.660 143.820 ;
        RECT 87.460 143.090 89.460 143.820 ;
        RECT 87.460 142.700 89.460 142.880 ;
        RECT 91.890 142.840 92.210 143.820 ;
        RECT 92.370 144.660 94.410 145.250 ;
        RECT 94.610 144.660 95.050 146.510 ;
        RECT 95.250 145.790 100.250 146.320 ;
        RECT 95.250 144.950 100.560 145.790 ;
        RECT 96.450 144.790 100.560 144.950 ;
        RECT 112.570 145.350 114.740 154.450 ;
        RECT 114.880 153.590 127.840 153.900 ;
        RECT 114.880 149.580 115.120 153.590 ;
        RECT 115.330 150.430 121.480 153.310 ;
        RECT 115.330 150.420 118.820 150.430 ;
        RECT 114.880 148.580 116.120 149.580 ;
        RECT 119.460 149.100 121.480 150.430 ;
        RECT 121.820 150.380 127.240 153.310 ;
        RECT 127.520 150.550 127.840 153.590 ;
        RECT 129.880 151.050 131.400 154.770 ;
        RECT 131.540 150.380 134.000 159.270 ;
        RECT 121.820 149.400 134.000 150.380 ;
        RECT 114.880 148.090 119.320 148.580 ;
        RECT 114.880 146.330 116.370 148.090 ;
        RECT 92.370 143.660 95.410 144.660 ;
        RECT 92.370 143.090 94.410 143.660 ;
        RECT 94.770 143.240 95.410 143.660 ;
        RECT 96.450 143.950 100.450 144.790 ;
        RECT 94.770 142.900 96.290 143.240 ;
        RECT 96.450 143.090 98.450 143.950 ;
        RECT 99.450 143.790 100.450 143.950 ;
        RECT 112.570 144.350 115.220 145.350 ;
        RECT 112.570 143.360 114.740 144.350 ;
        RECT 115.880 144.185 116.370 146.330 ;
        RECT 115.930 144.180 116.370 144.185 ;
        RECT 116.590 143.360 118.820 146.930 ;
        RECT 118.970 143.920 119.320 148.090 ;
        RECT 119.460 147.850 128.970 149.100 ;
        RECT 119.460 144.200 121.480 147.850 ;
        RECT 121.680 143.920 122.260 147.230 ;
        RECT 126.810 147.190 128.970 147.850 ;
        RECT 131.540 147.730 134.000 149.400 ;
        RECT 131.230 146.730 134.000 147.730 ;
        RECT 118.970 143.500 122.260 143.920 ;
        RECT 122.700 145.160 130.400 146.600 ;
        RECT 122.700 143.360 123.050 145.160 ;
        RECT 92.370 142.700 93.370 142.880 ;
        RECT 96.060 142.840 96.290 142.900 ;
        RECT 96.450 142.700 98.450 142.880 ;
        RECT 60.640 142.600 100.560 142.700 ;
        RECT 49.480 142.370 100.560 142.600 ;
        RECT 35.520 142.310 37.080 142.370 ;
        RECT 37.590 142.310 100.560 142.370 ;
        RECT 35.520 142.030 100.560 142.310 ;
        RECT 58.310 141.640 59.310 142.030 ;
        RECT 112.570 141.910 123.050 143.360 ;
        RECT 126.810 142.230 131.400 144.590 ;
        RECT 33.210 140.970 41.350 141.420 ;
        RECT 33.210 137.410 35.080 140.970 ;
        RECT 55.100 139.630 56.100 140.010 ;
        RECT 59.570 139.630 100.560 140.030 ;
        RECT 53.390 139.400 100.560 139.630 ;
        RECT 45.930 138.950 47.900 139.290 ;
        RECT 53.390 139.030 60.570 139.400 ;
        RECT 60.740 139.215 60.940 139.220 ;
        RECT 53.390 138.950 54.560 139.030 ;
        RECT 35.400 138.650 54.560 138.950 ;
        RECT 35.400 138.420 37.200 138.650 ;
        RECT 38.490 138.620 54.560 138.650 ;
        RECT 35.400 137.810 37.195 138.420 ;
        RECT 33.210 137.120 35.085 137.410 ;
        RECT 35.400 137.370 36.400 137.810 ;
        RECT 36.750 137.495 37.195 137.810 ;
        RECT 36.750 137.490 37.190 137.495 ;
        RECT 37.400 137.490 38.280 138.510 ;
        RECT 38.490 137.490 38.930 138.620 ;
        RECT 40.160 138.380 40.390 138.435 ;
        RECT 40.595 138.395 43.595 138.620 ;
        RECT 44.420 138.400 47.420 138.620 ;
        RECT 39.070 137.860 40.390 138.380 ;
        RECT 47.780 138.190 48.050 138.440 ;
        RECT 48.250 138.400 54.250 138.620 ;
        RECT 55.100 138.590 56.100 139.030 ;
        RECT 60.710 138.925 60.940 139.215 ;
        RECT 61.145 139.175 67.145 139.400 ;
        RECT 67.970 139.180 70.970 139.400 ;
        RECT 60.740 138.560 60.940 138.925 ;
        RECT 59.560 138.280 60.940 138.560 ;
        RECT 40.600 138.185 43.600 138.190 ;
        RECT 40.595 137.955 43.600 138.185 ;
        RECT 44.420 137.960 48.050 138.190 ;
        RECT 48.250 137.960 54.250 138.190 ;
        RECT 35.400 137.120 36.600 137.160 ;
        RECT 36.850 137.120 37.450 137.340 ;
        RECT 33.210 136.180 35.080 137.120 ;
        RECT 35.400 136.930 37.450 137.120 ;
        RECT 35.520 136.900 37.450 136.930 ;
        RECT 37.590 137.250 38.190 137.490 ;
        RECT 39.070 137.250 39.290 137.860 ;
        RECT 37.590 137.030 39.290 137.250 ;
        RECT 33.210 135.850 35.360 136.180 ;
        RECT 35.520 136.120 37.180 136.900 ;
        RECT 37.590 136.760 38.930 137.030 ;
        RECT 37.390 136.400 38.930 136.760 ;
        RECT 39.460 136.510 40.460 137.510 ;
        RECT 40.600 137.310 43.600 137.955 ;
        RECT 44.820 137.560 48.050 137.960 ;
        RECT 44.820 137.150 47.820 137.560 ;
        RECT 40.600 136.920 43.600 137.100 ;
        RECT 40.600 136.870 44.660 136.920 ;
        RECT 37.390 136.370 37.890 136.400 ;
        RECT 38.360 136.360 38.930 136.400 ;
        RECT 38.360 136.170 39.860 136.360 ;
        RECT 33.210 134.070 35.080 135.850 ;
        RECT 35.520 135.770 36.520 135.910 ;
        RECT 35.520 135.020 36.820 135.770 ;
        RECT 36.990 135.550 37.180 136.120 ;
        RECT 37.390 135.960 37.890 136.160 ;
        RECT 37.390 135.690 38.120 135.960 ;
        RECT 36.990 135.360 37.450 135.550 ;
        RECT 37.610 135.370 38.120 135.690 ;
        RECT 37.220 135.100 37.450 135.360 ;
        RECT 38.360 135.190 39.360 135.970 ;
        RECT 39.640 135.520 39.860 136.170 ;
        RECT 40.060 136.050 40.460 136.510 ;
        RECT 41.630 136.170 44.660 136.870 ;
        RECT 44.820 136.770 48.710 137.150 ;
        RECT 49.480 136.770 54.120 137.960 ;
        RECT 59.560 137.560 60.560 138.280 ;
        RECT 60.705 137.840 60.940 138.130 ;
        RECT 61.140 138.090 67.150 138.970 ;
        RECT 39.640 135.190 41.470 135.520 ;
        RECT 41.630 135.460 43.600 136.170 ;
        RECT 44.820 135.460 47.820 136.560 ;
        RECT 48.350 135.520 48.710 136.770 ;
        RECT 37.610 135.020 38.110 135.160 ;
        RECT 41.630 135.020 42.630 135.250 ;
        RECT 44.820 135.020 47.820 135.250 ;
        RECT 48.350 135.190 49.320 135.520 ;
        RECT 49.480 135.460 51.480 136.560 ;
        RECT 52.670 135.770 53.670 136.770 ;
        RECT 60.060 136.180 60.560 137.560 ;
        RECT 60.730 137.320 60.940 137.840 ;
        RECT 61.140 137.650 67.810 137.880 ;
        RECT 60.730 136.790 63.250 137.320 ;
        RECT 61.770 136.320 63.250 136.790 ;
        RECT 63.580 136.810 67.810 137.650 ;
        RECT 60.060 135.840 63.420 136.180 ;
        RECT 58.300 135.250 59.300 135.710 ;
        RECT 60.640 135.350 61.640 135.680 ;
        RECT 61.860 135.350 62.920 135.700 ;
        RECT 63.140 135.490 63.420 135.840 ;
        RECT 63.580 135.740 64.580 136.810 ;
        RECT 66.900 136.480 67.810 136.810 ;
        RECT 67.970 136.750 70.970 138.970 ;
        RECT 72.240 138.530 72.420 139.400 ;
        RECT 72.565 139.180 77.095 139.400 ;
        RECT 72.565 138.740 77.620 138.970 ;
        RECT 72.240 138.410 73.130 138.530 ;
        RECT 71.585 137.720 71.815 138.010 ;
        RECT 72.130 137.970 73.130 138.410 ;
        RECT 73.330 137.760 73.870 138.600 ;
        RECT 71.520 136.900 71.810 137.720 ;
        RECT 72.130 137.530 73.870 137.760 ;
        RECT 63.580 135.350 64.580 135.530 ;
        RECT 64.890 135.350 66.010 135.980 ;
        RECT 67.970 135.740 70.970 136.540 ;
        RECT 67.970 135.350 70.970 135.530 ;
        RECT 71.390 135.510 72.090 136.900 ;
        RECT 72.250 136.720 73.870 137.530 ;
        RECT 74.390 136.630 77.620 138.740 ;
        RECT 77.790 138.520 78.050 139.400 ;
        RECT 78.200 138.660 78.540 139.260 ;
        RECT 78.690 139.180 84.690 139.400 ;
        RECT 85.560 139.180 91.560 139.400 ;
        RECT 78.690 138.740 84.690 138.970 ;
        RECT 77.790 138.260 80.270 138.520 ;
        RECT 81.730 138.480 84.690 138.740 ;
        RECT 85.560 138.480 91.560 138.970 ;
        RECT 81.730 138.470 91.560 138.480 ;
        RECT 78.725 137.730 78.955 138.020 ;
        RECT 79.270 137.980 80.270 138.260 ;
        RECT 81.070 137.770 82.070 138.300 ;
        RECT 79.270 137.760 82.070 137.770 ;
        RECT 82.270 138.170 91.560 138.470 ;
        RECT 82.270 137.760 92.210 138.170 ;
        RECT 92.410 138.110 94.410 139.400 ;
        RECT 94.815 139.160 95.045 139.220 ;
        RECT 95.250 139.180 100.250 139.400 ;
        RECT 78.660 136.820 78.950 137.730 ;
        RECT 79.270 137.540 81.540 137.760 ;
        RECT 72.250 135.350 73.250 136.510 ;
        RECT 74.910 135.750 77.620 136.630 ;
        RECT 77.910 136.790 78.950 136.820 ;
        RECT 77.910 136.460 79.230 136.790 ;
        RECT 79.390 136.730 81.540 137.540 ;
        RECT 82.280 136.750 92.210 137.760 ;
        RECT 77.910 135.780 78.910 136.460 ;
        RECT 74.920 135.740 76.920 135.750 ;
        RECT 74.920 135.350 76.920 135.530 ;
        RECT 79.390 135.350 80.390 136.520 ;
        RECT 82.280 136.310 84.280 136.540 ;
        RECT 87.460 136.470 92.210 136.750 ;
        RECT 80.680 135.530 82.130 136.250 ;
        RECT 82.290 135.970 84.280 136.310 ;
        RECT 82.290 135.740 84.290 135.970 ;
        RECT 81.900 135.490 82.130 135.530 ;
        RECT 82.290 135.350 84.290 135.530 ;
        RECT 85.290 135.350 86.660 136.470 ;
        RECT 87.460 135.740 89.460 136.470 ;
        RECT 87.460 135.350 89.460 135.530 ;
        RECT 91.890 135.490 92.210 136.470 ;
        RECT 92.370 137.310 94.410 137.900 ;
        RECT 94.610 137.310 95.050 139.160 ;
        RECT 95.250 138.440 100.250 138.970 ;
        RECT 95.250 137.600 100.560 138.440 ;
        RECT 96.450 137.440 100.560 137.600 ;
        RECT 92.370 136.310 95.410 137.310 ;
        RECT 92.370 135.740 94.410 136.310 ;
        RECT 94.770 135.890 95.410 136.310 ;
        RECT 96.450 136.600 100.450 137.440 ;
        RECT 94.770 135.550 96.290 135.890 ;
        RECT 96.450 135.740 98.450 136.600 ;
        RECT 99.450 136.440 100.450 136.600 ;
        RECT 92.370 135.350 93.370 135.530 ;
        RECT 96.060 135.490 96.290 135.550 ;
        RECT 96.450 135.350 98.450 135.530 ;
        RECT 60.640 135.250 100.560 135.350 ;
        RECT 49.480 135.020 100.560 135.250 ;
        RECT 35.520 134.960 37.080 135.020 ;
        RECT 37.590 134.960 100.560 135.020 ;
        RECT 35.520 134.680 100.560 134.960 ;
        RECT 58.300 134.290 59.300 134.680 ;
        RECT 33.210 133.620 41.350 134.070 ;
        RECT 33.210 130.060 35.080 133.620 ;
        RECT 35.780 132.300 36.780 133.300 ;
        RECT 112.570 132.810 114.740 141.910 ;
        RECT 114.880 141.050 127.840 141.360 ;
        RECT 114.880 137.040 115.120 141.050 ;
        RECT 115.330 137.890 121.480 140.770 ;
        RECT 115.330 137.880 118.820 137.890 ;
        RECT 114.880 136.040 116.120 137.040 ;
        RECT 119.460 136.560 121.480 137.890 ;
        RECT 121.820 137.840 127.240 140.770 ;
        RECT 127.520 138.010 127.840 141.050 ;
        RECT 129.880 138.510 131.400 142.230 ;
        RECT 131.540 137.840 134.000 146.730 ;
        RECT 121.820 136.860 134.000 137.840 ;
        RECT 114.880 135.550 119.320 136.040 ;
        RECT 114.880 133.790 116.370 135.550 ;
        RECT 55.100 132.280 56.100 132.660 ;
        RECT 59.570 132.280 100.560 132.680 ;
        RECT 53.390 132.050 100.560 132.280 ;
        RECT 45.930 131.600 47.900 131.940 ;
        RECT 53.390 131.680 60.570 132.050 ;
        RECT 60.740 131.865 60.940 131.870 ;
        RECT 53.390 131.600 54.560 131.680 ;
        RECT 35.400 131.300 54.560 131.600 ;
        RECT 35.400 131.070 37.200 131.300 ;
        RECT 38.490 131.270 54.560 131.300 ;
        RECT 35.400 130.460 37.195 131.070 ;
        RECT 33.210 129.770 35.085 130.060 ;
        RECT 35.400 130.020 36.400 130.460 ;
        RECT 36.750 130.145 37.195 130.460 ;
        RECT 36.750 130.140 37.190 130.145 ;
        RECT 37.400 130.140 38.280 131.160 ;
        RECT 38.490 130.140 38.930 131.270 ;
        RECT 40.160 131.030 40.390 131.085 ;
        RECT 40.595 131.045 43.595 131.270 ;
        RECT 44.420 131.050 47.420 131.270 ;
        RECT 39.070 130.510 40.390 131.030 ;
        RECT 47.780 130.840 48.050 131.090 ;
        RECT 48.250 131.050 54.250 131.270 ;
        RECT 55.100 131.240 56.100 131.680 ;
        RECT 60.710 131.575 60.940 131.865 ;
        RECT 61.145 131.825 67.145 132.050 ;
        RECT 67.970 131.830 70.970 132.050 ;
        RECT 60.740 131.210 60.940 131.575 ;
        RECT 59.560 130.930 60.940 131.210 ;
        RECT 40.600 130.835 43.600 130.840 ;
        RECT 40.595 130.605 43.600 130.835 ;
        RECT 44.420 130.610 48.050 130.840 ;
        RECT 48.250 130.610 54.250 130.840 ;
        RECT 35.400 129.770 36.600 129.810 ;
        RECT 36.850 129.770 37.450 129.990 ;
        RECT 33.210 128.830 35.080 129.770 ;
        RECT 35.400 129.580 37.450 129.770 ;
        RECT 35.520 129.550 37.450 129.580 ;
        RECT 37.590 129.900 38.190 130.140 ;
        RECT 39.070 129.900 39.290 130.510 ;
        RECT 37.590 129.680 39.290 129.900 ;
        RECT 33.210 128.500 35.360 128.830 ;
        RECT 35.520 128.770 37.180 129.550 ;
        RECT 37.590 129.410 38.930 129.680 ;
        RECT 37.390 129.050 38.930 129.410 ;
        RECT 39.460 129.160 40.460 130.160 ;
        RECT 40.600 129.960 43.600 130.605 ;
        RECT 44.820 130.210 48.050 130.610 ;
        RECT 44.820 129.800 47.820 130.210 ;
        RECT 40.600 129.570 43.600 129.750 ;
        RECT 40.600 129.520 44.660 129.570 ;
        RECT 37.390 129.020 37.890 129.050 ;
        RECT 38.360 129.010 38.930 129.050 ;
        RECT 38.360 128.820 39.860 129.010 ;
        RECT 33.210 126.720 35.080 128.500 ;
        RECT 35.520 128.420 36.520 128.560 ;
        RECT 35.520 127.670 36.820 128.420 ;
        RECT 36.990 128.200 37.180 128.770 ;
        RECT 37.390 128.610 37.890 128.810 ;
        RECT 37.390 128.340 38.120 128.610 ;
        RECT 36.990 128.010 37.450 128.200 ;
        RECT 37.610 128.020 38.120 128.340 ;
        RECT 37.220 127.750 37.450 128.010 ;
        RECT 38.360 127.840 39.360 128.620 ;
        RECT 39.640 128.170 39.860 128.820 ;
        RECT 40.060 128.700 40.460 129.160 ;
        RECT 41.630 128.820 44.660 129.520 ;
        RECT 44.820 129.420 48.710 129.800 ;
        RECT 49.480 129.420 54.120 130.610 ;
        RECT 59.560 130.210 60.560 130.930 ;
        RECT 60.705 130.490 60.940 130.780 ;
        RECT 61.140 130.740 67.150 131.620 ;
        RECT 39.640 127.840 41.470 128.170 ;
        RECT 41.630 128.110 43.600 128.820 ;
        RECT 44.820 128.110 47.820 129.210 ;
        RECT 48.350 128.170 48.710 129.420 ;
        RECT 37.610 127.670 38.110 127.810 ;
        RECT 41.630 127.670 42.630 127.900 ;
        RECT 44.820 127.670 47.820 127.900 ;
        RECT 48.350 127.840 49.320 128.170 ;
        RECT 49.480 128.110 51.480 129.210 ;
        RECT 52.670 128.420 53.670 129.420 ;
        RECT 60.060 128.830 60.560 130.210 ;
        RECT 60.730 129.970 60.940 130.490 ;
        RECT 61.140 130.300 67.810 130.530 ;
        RECT 60.730 129.440 63.250 129.970 ;
        RECT 61.770 128.970 63.250 129.440 ;
        RECT 63.580 129.460 67.810 130.300 ;
        RECT 60.060 128.490 63.420 128.830 ;
        RECT 58.300 127.900 59.300 128.360 ;
        RECT 60.640 128.000 61.640 128.330 ;
        RECT 61.860 128.000 62.920 128.350 ;
        RECT 63.140 128.140 63.420 128.490 ;
        RECT 63.580 128.390 64.580 129.460 ;
        RECT 66.900 129.130 67.810 129.460 ;
        RECT 67.970 129.400 70.970 131.620 ;
        RECT 72.240 131.180 72.420 132.050 ;
        RECT 72.565 131.830 77.095 132.050 ;
        RECT 72.565 131.390 77.620 131.620 ;
        RECT 72.240 131.060 73.130 131.180 ;
        RECT 71.585 130.370 71.815 130.660 ;
        RECT 72.130 130.620 73.130 131.060 ;
        RECT 73.330 130.410 73.870 131.250 ;
        RECT 71.520 129.550 71.810 130.370 ;
        RECT 72.130 130.180 73.870 130.410 ;
        RECT 63.580 128.000 64.580 128.180 ;
        RECT 64.890 128.000 66.010 128.630 ;
        RECT 67.970 128.390 70.970 129.190 ;
        RECT 67.970 128.000 70.970 128.180 ;
        RECT 71.390 128.160 72.090 129.550 ;
        RECT 72.250 129.370 73.870 130.180 ;
        RECT 74.390 129.280 77.620 131.390 ;
        RECT 77.790 131.170 78.050 132.050 ;
        RECT 78.200 131.310 78.540 131.910 ;
        RECT 78.690 131.830 84.690 132.050 ;
        RECT 85.560 131.830 91.560 132.050 ;
        RECT 78.690 131.390 84.690 131.620 ;
        RECT 77.790 130.910 80.270 131.170 ;
        RECT 81.730 131.130 84.690 131.390 ;
        RECT 85.560 131.130 91.560 131.620 ;
        RECT 81.730 131.120 91.560 131.130 ;
        RECT 78.725 130.380 78.955 130.670 ;
        RECT 79.270 130.630 80.270 130.910 ;
        RECT 81.070 130.420 82.070 130.950 ;
        RECT 79.270 130.410 82.070 130.420 ;
        RECT 82.270 130.820 91.560 131.120 ;
        RECT 82.270 130.410 92.210 130.820 ;
        RECT 92.410 130.760 94.410 132.050 ;
        RECT 94.815 131.810 95.045 131.870 ;
        RECT 95.250 131.830 100.250 132.050 ;
        RECT 112.570 131.810 115.220 132.810 ;
        RECT 78.660 129.470 78.950 130.380 ;
        RECT 79.270 130.190 81.540 130.410 ;
        RECT 72.250 128.000 73.250 129.160 ;
        RECT 74.910 128.400 77.620 129.280 ;
        RECT 77.910 129.440 78.950 129.470 ;
        RECT 77.910 129.110 79.230 129.440 ;
        RECT 79.390 129.380 81.540 130.190 ;
        RECT 82.280 129.400 92.210 130.410 ;
        RECT 77.910 128.430 78.910 129.110 ;
        RECT 74.920 128.390 76.920 128.400 ;
        RECT 74.920 128.000 76.920 128.180 ;
        RECT 79.390 128.000 80.390 129.170 ;
        RECT 82.280 128.960 84.280 129.190 ;
        RECT 87.460 129.120 92.210 129.400 ;
        RECT 80.680 128.180 82.130 128.900 ;
        RECT 82.290 128.620 84.280 128.960 ;
        RECT 82.290 128.390 84.290 128.620 ;
        RECT 81.900 128.140 82.130 128.180 ;
        RECT 82.290 128.000 84.290 128.180 ;
        RECT 85.290 128.000 86.660 129.120 ;
        RECT 87.460 128.390 89.460 129.120 ;
        RECT 87.460 128.000 89.460 128.180 ;
        RECT 91.890 128.140 92.210 129.120 ;
        RECT 92.370 129.960 94.410 130.550 ;
        RECT 94.610 129.960 95.050 131.810 ;
        RECT 95.250 131.090 100.250 131.620 ;
        RECT 95.250 130.250 100.560 131.090 ;
        RECT 96.450 130.090 100.560 130.250 ;
        RECT 112.570 130.820 114.740 131.810 ;
        RECT 115.880 131.645 116.370 133.790 ;
        RECT 115.930 131.640 116.370 131.645 ;
        RECT 116.590 130.820 118.820 134.390 ;
        RECT 118.970 131.380 119.320 135.550 ;
        RECT 119.460 135.310 128.970 136.560 ;
        RECT 119.460 131.660 121.480 135.310 ;
        RECT 121.680 131.380 122.260 134.690 ;
        RECT 126.810 134.650 128.970 135.310 ;
        RECT 131.540 135.190 134.000 136.860 ;
        RECT 131.230 134.190 134.000 135.190 ;
        RECT 118.970 130.960 122.260 131.380 ;
        RECT 122.700 132.620 130.400 134.060 ;
        RECT 122.700 130.820 123.050 132.620 ;
        RECT 92.370 128.960 95.410 129.960 ;
        RECT 92.370 128.390 94.410 128.960 ;
        RECT 94.770 128.540 95.410 128.960 ;
        RECT 96.450 129.250 100.450 130.090 ;
        RECT 94.770 128.200 96.290 128.540 ;
        RECT 96.450 128.390 98.450 129.250 ;
        RECT 99.450 129.090 100.450 129.250 ;
        RECT 112.570 129.370 123.050 130.820 ;
        RECT 126.810 129.690 131.400 132.050 ;
        RECT 92.370 128.000 93.370 128.180 ;
        RECT 96.060 128.140 96.290 128.200 ;
        RECT 96.450 128.000 98.450 128.180 ;
        RECT 60.640 127.900 100.560 128.000 ;
        RECT 49.480 127.670 100.560 127.900 ;
        RECT 35.520 127.610 37.080 127.670 ;
        RECT 37.590 127.610 100.560 127.670 ;
        RECT 35.520 127.330 100.560 127.610 ;
        RECT 58.300 126.940 59.300 127.330 ;
        RECT 33.210 126.270 41.350 126.720 ;
        RECT 33.210 122.710 35.080 126.270 ;
        RECT 55.100 124.930 56.100 125.310 ;
        RECT 59.570 124.930 100.560 125.330 ;
        RECT 53.390 124.700 100.560 124.930 ;
        RECT 45.930 124.250 47.900 124.590 ;
        RECT 53.390 124.330 60.570 124.700 ;
        RECT 60.740 124.515 60.940 124.520 ;
        RECT 53.390 124.250 54.560 124.330 ;
        RECT 35.400 123.950 54.560 124.250 ;
        RECT 35.400 123.720 37.200 123.950 ;
        RECT 38.490 123.920 54.560 123.950 ;
        RECT 35.400 123.110 37.195 123.720 ;
        RECT 33.210 122.420 35.085 122.710 ;
        RECT 35.400 122.670 36.400 123.110 ;
        RECT 36.750 122.795 37.195 123.110 ;
        RECT 36.750 122.790 37.190 122.795 ;
        RECT 37.400 122.790 38.280 123.810 ;
        RECT 38.490 122.790 38.930 123.920 ;
        RECT 40.160 123.680 40.390 123.735 ;
        RECT 40.595 123.695 43.595 123.920 ;
        RECT 44.420 123.700 47.420 123.920 ;
        RECT 39.070 123.160 40.390 123.680 ;
        RECT 47.780 123.490 48.050 123.740 ;
        RECT 48.250 123.700 54.250 123.920 ;
        RECT 55.100 123.890 56.100 124.330 ;
        RECT 60.710 124.225 60.940 124.515 ;
        RECT 61.145 124.475 67.145 124.700 ;
        RECT 67.970 124.480 70.970 124.700 ;
        RECT 60.740 123.860 60.940 124.225 ;
        RECT 59.560 123.580 60.940 123.860 ;
        RECT 40.600 123.485 43.600 123.490 ;
        RECT 40.595 123.255 43.600 123.485 ;
        RECT 44.420 123.260 48.050 123.490 ;
        RECT 48.250 123.260 54.250 123.490 ;
        RECT 35.400 122.420 36.600 122.460 ;
        RECT 36.850 122.420 37.450 122.640 ;
        RECT 33.210 121.480 35.080 122.420 ;
        RECT 35.400 122.230 37.450 122.420 ;
        RECT 35.520 122.200 37.450 122.230 ;
        RECT 37.590 122.550 38.190 122.790 ;
        RECT 39.070 122.550 39.290 123.160 ;
        RECT 37.590 122.330 39.290 122.550 ;
        RECT 33.210 121.150 35.360 121.480 ;
        RECT 35.520 121.420 37.180 122.200 ;
        RECT 37.590 122.060 38.930 122.330 ;
        RECT 37.390 121.700 38.930 122.060 ;
        RECT 39.460 121.810 40.460 122.810 ;
        RECT 40.600 122.610 43.600 123.255 ;
        RECT 44.820 122.860 48.050 123.260 ;
        RECT 44.820 122.450 47.820 122.860 ;
        RECT 40.600 122.220 43.600 122.400 ;
        RECT 40.600 122.170 44.660 122.220 ;
        RECT 37.390 121.670 37.890 121.700 ;
        RECT 38.360 121.660 38.930 121.700 ;
        RECT 38.360 121.470 39.860 121.660 ;
        RECT 33.210 119.370 35.080 121.150 ;
        RECT 35.520 121.070 36.520 121.210 ;
        RECT 35.520 120.320 36.820 121.070 ;
        RECT 36.990 120.850 37.180 121.420 ;
        RECT 37.390 121.260 37.890 121.460 ;
        RECT 37.390 120.990 38.120 121.260 ;
        RECT 36.990 120.660 37.450 120.850 ;
        RECT 37.610 120.670 38.120 120.990 ;
        RECT 37.220 120.400 37.450 120.660 ;
        RECT 38.360 120.490 39.360 121.270 ;
        RECT 39.640 120.820 39.860 121.470 ;
        RECT 40.060 121.350 40.460 121.810 ;
        RECT 41.630 121.470 44.660 122.170 ;
        RECT 44.820 122.070 48.710 122.450 ;
        RECT 49.480 122.070 54.120 123.260 ;
        RECT 59.560 122.860 60.560 123.580 ;
        RECT 60.705 123.140 60.940 123.430 ;
        RECT 61.140 123.390 67.150 124.270 ;
        RECT 39.640 120.490 41.470 120.820 ;
        RECT 41.630 120.760 43.600 121.470 ;
        RECT 44.820 120.760 47.820 121.860 ;
        RECT 48.350 120.820 48.710 122.070 ;
        RECT 37.610 120.320 38.110 120.460 ;
        RECT 41.630 120.320 42.630 120.550 ;
        RECT 44.820 120.320 47.820 120.550 ;
        RECT 48.350 120.490 49.320 120.820 ;
        RECT 49.480 120.760 51.480 121.860 ;
        RECT 52.670 121.070 53.670 122.070 ;
        RECT 60.060 121.480 60.560 122.860 ;
        RECT 60.730 122.620 60.940 123.140 ;
        RECT 61.140 122.950 67.810 123.180 ;
        RECT 60.730 122.090 63.250 122.620 ;
        RECT 61.770 121.620 63.250 122.090 ;
        RECT 63.580 122.110 67.810 122.950 ;
        RECT 60.060 121.140 63.420 121.480 ;
        RECT 58.300 120.550 59.300 121.010 ;
        RECT 60.640 120.650 61.640 120.980 ;
        RECT 61.860 120.650 62.920 121.000 ;
        RECT 63.140 120.790 63.420 121.140 ;
        RECT 63.580 121.040 64.580 122.110 ;
        RECT 66.900 121.780 67.810 122.110 ;
        RECT 67.970 122.050 70.970 124.270 ;
        RECT 72.240 123.830 72.420 124.700 ;
        RECT 72.565 124.480 77.095 124.700 ;
        RECT 72.565 124.040 77.620 124.270 ;
        RECT 72.240 123.710 73.130 123.830 ;
        RECT 71.585 123.020 71.815 123.310 ;
        RECT 72.130 123.270 73.130 123.710 ;
        RECT 73.330 123.060 73.870 123.900 ;
        RECT 71.520 122.200 71.810 123.020 ;
        RECT 72.130 122.830 73.870 123.060 ;
        RECT 63.580 120.650 64.580 120.830 ;
        RECT 64.890 120.650 66.010 121.280 ;
        RECT 67.970 121.040 70.970 121.840 ;
        RECT 67.970 120.650 70.970 120.830 ;
        RECT 71.390 120.810 72.090 122.200 ;
        RECT 72.250 122.020 73.870 122.830 ;
        RECT 74.390 121.930 77.620 124.040 ;
        RECT 77.790 123.820 78.050 124.700 ;
        RECT 78.200 123.960 78.540 124.560 ;
        RECT 78.690 124.480 84.690 124.700 ;
        RECT 85.560 124.480 91.560 124.700 ;
        RECT 78.690 124.040 84.690 124.270 ;
        RECT 77.790 123.560 80.270 123.820 ;
        RECT 81.730 123.780 84.690 124.040 ;
        RECT 85.560 123.780 91.560 124.270 ;
        RECT 81.730 123.770 91.560 123.780 ;
        RECT 78.725 123.030 78.955 123.320 ;
        RECT 79.270 123.280 80.270 123.560 ;
        RECT 81.070 123.070 82.070 123.600 ;
        RECT 79.270 123.060 82.070 123.070 ;
        RECT 82.270 123.470 91.560 123.770 ;
        RECT 82.270 123.060 92.210 123.470 ;
        RECT 92.410 123.410 94.410 124.700 ;
        RECT 94.815 124.460 95.045 124.520 ;
        RECT 95.250 124.480 100.250 124.700 ;
        RECT 78.660 122.120 78.950 123.030 ;
        RECT 79.270 122.840 81.540 123.060 ;
        RECT 72.250 120.650 73.250 121.810 ;
        RECT 74.910 121.050 77.620 121.930 ;
        RECT 77.910 122.090 78.950 122.120 ;
        RECT 77.910 121.760 79.230 122.090 ;
        RECT 79.390 122.030 81.540 122.840 ;
        RECT 82.280 122.050 92.210 123.060 ;
        RECT 77.910 121.080 78.910 121.760 ;
        RECT 74.920 121.040 76.920 121.050 ;
        RECT 74.920 120.650 76.920 120.830 ;
        RECT 79.390 120.650 80.390 121.820 ;
        RECT 82.280 121.610 84.280 121.840 ;
        RECT 87.460 121.770 92.210 122.050 ;
        RECT 80.680 120.830 82.130 121.550 ;
        RECT 82.290 121.270 84.280 121.610 ;
        RECT 82.290 121.040 84.290 121.270 ;
        RECT 81.900 120.790 82.130 120.830 ;
        RECT 82.290 120.650 84.290 120.830 ;
        RECT 85.290 120.650 86.660 121.770 ;
        RECT 87.460 121.040 89.460 121.770 ;
        RECT 87.460 120.650 89.460 120.830 ;
        RECT 91.890 120.790 92.210 121.770 ;
        RECT 92.370 122.610 94.410 123.200 ;
        RECT 94.610 122.610 95.050 124.460 ;
        RECT 95.250 123.740 100.250 124.270 ;
        RECT 95.250 122.900 100.560 123.740 ;
        RECT 96.450 122.740 100.560 122.900 ;
        RECT 92.370 121.610 95.410 122.610 ;
        RECT 92.370 121.040 94.410 121.610 ;
        RECT 94.770 121.190 95.410 121.610 ;
        RECT 96.450 121.900 100.450 122.740 ;
        RECT 94.770 120.850 96.290 121.190 ;
        RECT 96.450 121.040 98.450 121.900 ;
        RECT 99.450 121.740 100.450 121.900 ;
        RECT 92.370 120.650 93.370 120.830 ;
        RECT 96.060 120.790 96.290 120.850 ;
        RECT 96.450 120.650 98.450 120.830 ;
        RECT 60.640 120.550 100.560 120.650 ;
        RECT 49.480 120.320 100.560 120.550 ;
        RECT 35.520 120.260 37.080 120.320 ;
        RECT 37.590 120.260 100.560 120.320 ;
        RECT 35.520 119.980 100.560 120.260 ;
        RECT 112.570 120.270 114.740 129.370 ;
        RECT 114.880 128.510 127.840 128.820 ;
        RECT 114.880 124.500 115.120 128.510 ;
        RECT 115.330 125.350 121.480 128.230 ;
        RECT 115.330 125.340 118.820 125.350 ;
        RECT 114.880 123.500 116.120 124.500 ;
        RECT 119.460 124.020 121.480 125.350 ;
        RECT 121.820 125.300 127.240 128.230 ;
        RECT 127.520 125.470 127.840 128.510 ;
        RECT 129.880 125.970 131.400 129.690 ;
        RECT 131.540 125.300 134.000 134.190 ;
        RECT 121.820 124.320 134.000 125.300 ;
        RECT 114.880 123.010 119.320 123.500 ;
        RECT 114.880 121.250 116.370 123.010 ;
        RECT 58.300 119.590 59.300 119.980 ;
        RECT 33.210 118.920 41.350 119.370 ;
        RECT 112.570 119.270 115.220 120.270 ;
        RECT 33.210 115.360 35.080 118.920 ;
        RECT 112.570 118.280 114.740 119.270 ;
        RECT 115.880 119.105 116.370 121.250 ;
        RECT 115.930 119.100 116.370 119.105 ;
        RECT 116.590 118.280 118.820 121.850 ;
        RECT 118.970 118.840 119.320 123.010 ;
        RECT 119.460 122.770 128.970 124.020 ;
        RECT 119.460 119.120 121.480 122.770 ;
        RECT 121.680 118.840 122.260 122.150 ;
        RECT 126.810 122.110 128.970 122.770 ;
        RECT 131.540 122.650 134.000 124.320 ;
        RECT 131.230 121.650 134.000 122.650 ;
        RECT 118.970 118.420 122.260 118.840 ;
        RECT 122.700 120.080 130.400 121.520 ;
        RECT 122.700 118.280 123.050 120.080 ;
        RECT 55.100 117.580 56.100 117.960 ;
        RECT 59.570 117.580 100.560 117.980 ;
        RECT 53.390 117.350 100.560 117.580 ;
        RECT 45.930 116.900 47.900 117.240 ;
        RECT 53.390 116.980 60.570 117.350 ;
        RECT 60.740 117.165 60.940 117.170 ;
        RECT 53.390 116.900 54.560 116.980 ;
        RECT 35.400 116.600 54.560 116.900 ;
        RECT 35.400 116.370 37.200 116.600 ;
        RECT 38.490 116.570 54.560 116.600 ;
        RECT 35.400 115.760 37.195 116.370 ;
        RECT 33.210 115.070 35.085 115.360 ;
        RECT 35.400 115.320 36.400 115.760 ;
        RECT 36.750 115.445 37.195 115.760 ;
        RECT 36.750 115.440 37.190 115.445 ;
        RECT 37.400 115.440 38.280 116.460 ;
        RECT 38.490 115.440 38.930 116.570 ;
        RECT 40.160 116.330 40.390 116.385 ;
        RECT 40.595 116.345 43.595 116.570 ;
        RECT 44.420 116.350 47.420 116.570 ;
        RECT 39.070 115.810 40.390 116.330 ;
        RECT 47.780 116.140 48.050 116.390 ;
        RECT 48.250 116.350 54.250 116.570 ;
        RECT 55.100 116.540 56.100 116.980 ;
        RECT 60.710 116.875 60.940 117.165 ;
        RECT 61.145 117.125 67.145 117.350 ;
        RECT 67.970 117.130 70.970 117.350 ;
        RECT 60.740 116.510 60.940 116.875 ;
        RECT 59.560 116.230 60.940 116.510 ;
        RECT 40.600 116.135 43.600 116.140 ;
        RECT 40.595 115.905 43.600 116.135 ;
        RECT 44.420 115.910 48.050 116.140 ;
        RECT 48.250 115.910 54.250 116.140 ;
        RECT 35.400 115.070 36.600 115.110 ;
        RECT 36.850 115.070 37.450 115.290 ;
        RECT 33.210 114.130 35.080 115.070 ;
        RECT 35.400 114.880 37.450 115.070 ;
        RECT 35.520 114.850 37.450 114.880 ;
        RECT 37.590 115.200 38.190 115.440 ;
        RECT 39.070 115.200 39.290 115.810 ;
        RECT 37.590 114.980 39.290 115.200 ;
        RECT 33.210 113.800 35.360 114.130 ;
        RECT 35.520 114.070 37.180 114.850 ;
        RECT 37.590 114.710 38.930 114.980 ;
        RECT 37.390 114.350 38.930 114.710 ;
        RECT 39.460 114.460 40.460 115.460 ;
        RECT 40.600 115.260 43.600 115.905 ;
        RECT 44.820 115.510 48.050 115.910 ;
        RECT 44.820 115.100 47.820 115.510 ;
        RECT 40.600 114.870 43.600 115.050 ;
        RECT 40.600 114.820 44.660 114.870 ;
        RECT 37.390 114.320 37.890 114.350 ;
        RECT 38.360 114.310 38.930 114.350 ;
        RECT 38.360 114.120 39.860 114.310 ;
        RECT 33.210 112.020 35.080 113.800 ;
        RECT 35.520 113.720 36.520 113.860 ;
        RECT 35.520 112.970 36.820 113.720 ;
        RECT 36.990 113.500 37.180 114.070 ;
        RECT 37.390 113.910 37.890 114.110 ;
        RECT 37.390 113.640 38.120 113.910 ;
        RECT 36.990 113.310 37.450 113.500 ;
        RECT 37.610 113.320 38.120 113.640 ;
        RECT 37.220 113.050 37.450 113.310 ;
        RECT 38.360 113.140 39.360 113.920 ;
        RECT 39.640 113.470 39.860 114.120 ;
        RECT 40.060 114.000 40.460 114.460 ;
        RECT 41.630 114.120 44.660 114.820 ;
        RECT 44.820 114.720 48.710 115.100 ;
        RECT 49.480 114.720 54.120 115.910 ;
        RECT 59.560 115.510 60.560 116.230 ;
        RECT 60.705 115.790 60.940 116.080 ;
        RECT 61.140 116.040 67.150 116.920 ;
        RECT 39.640 113.140 41.470 113.470 ;
        RECT 41.630 113.410 43.600 114.120 ;
        RECT 44.820 113.410 47.820 114.510 ;
        RECT 48.350 113.470 48.710 114.720 ;
        RECT 37.610 112.970 38.110 113.110 ;
        RECT 41.630 112.970 42.630 113.200 ;
        RECT 44.820 112.970 47.820 113.200 ;
        RECT 48.350 113.140 49.320 113.470 ;
        RECT 49.480 113.410 51.480 114.510 ;
        RECT 52.670 113.720 53.670 114.720 ;
        RECT 60.060 114.130 60.560 115.510 ;
        RECT 60.730 115.270 60.940 115.790 ;
        RECT 61.140 115.600 67.810 115.830 ;
        RECT 60.730 114.740 63.250 115.270 ;
        RECT 61.770 114.270 63.250 114.740 ;
        RECT 63.580 114.760 67.810 115.600 ;
        RECT 60.060 113.790 63.420 114.130 ;
        RECT 58.300 113.200 59.300 113.660 ;
        RECT 60.640 113.300 61.640 113.630 ;
        RECT 61.860 113.300 62.920 113.650 ;
        RECT 63.140 113.440 63.420 113.790 ;
        RECT 63.580 113.690 64.580 114.760 ;
        RECT 66.900 114.430 67.810 114.760 ;
        RECT 67.970 114.700 70.970 116.920 ;
        RECT 72.240 116.480 72.420 117.350 ;
        RECT 72.565 117.130 77.095 117.350 ;
        RECT 72.565 116.690 77.620 116.920 ;
        RECT 72.240 116.360 73.130 116.480 ;
        RECT 71.585 115.670 71.815 115.960 ;
        RECT 72.130 115.920 73.130 116.360 ;
        RECT 73.330 115.710 73.870 116.550 ;
        RECT 71.520 114.850 71.810 115.670 ;
        RECT 72.130 115.480 73.870 115.710 ;
        RECT 63.580 113.300 64.580 113.480 ;
        RECT 64.890 113.300 66.010 113.930 ;
        RECT 67.970 113.690 70.970 114.490 ;
        RECT 67.970 113.300 70.970 113.480 ;
        RECT 71.390 113.460 72.090 114.850 ;
        RECT 72.250 114.670 73.870 115.480 ;
        RECT 74.390 114.580 77.620 116.690 ;
        RECT 77.790 116.470 78.050 117.350 ;
        RECT 78.200 116.610 78.540 117.210 ;
        RECT 78.690 117.130 84.690 117.350 ;
        RECT 85.560 117.130 91.560 117.350 ;
        RECT 78.690 116.690 84.690 116.920 ;
        RECT 77.790 116.210 80.270 116.470 ;
        RECT 81.730 116.430 84.690 116.690 ;
        RECT 85.560 116.430 91.560 116.920 ;
        RECT 81.730 116.420 91.560 116.430 ;
        RECT 78.725 115.680 78.955 115.970 ;
        RECT 79.270 115.930 80.270 116.210 ;
        RECT 81.070 115.720 82.070 116.250 ;
        RECT 79.270 115.710 82.070 115.720 ;
        RECT 82.270 116.120 91.560 116.420 ;
        RECT 82.270 115.710 92.210 116.120 ;
        RECT 92.410 116.060 94.410 117.350 ;
        RECT 94.815 117.110 95.045 117.170 ;
        RECT 95.250 117.130 100.250 117.350 ;
        RECT 78.660 114.770 78.950 115.680 ;
        RECT 79.270 115.490 81.540 115.710 ;
        RECT 72.250 113.300 73.250 114.460 ;
        RECT 74.910 113.700 77.620 114.580 ;
        RECT 77.910 114.740 78.950 114.770 ;
        RECT 77.910 114.410 79.230 114.740 ;
        RECT 79.390 114.680 81.540 115.490 ;
        RECT 82.280 114.700 92.210 115.710 ;
        RECT 77.910 113.730 78.910 114.410 ;
        RECT 74.920 113.690 76.920 113.700 ;
        RECT 74.920 113.300 76.920 113.480 ;
        RECT 79.390 113.300 80.390 114.470 ;
        RECT 82.280 114.260 84.280 114.490 ;
        RECT 87.460 114.420 92.210 114.700 ;
        RECT 80.680 113.480 82.130 114.200 ;
        RECT 82.290 113.920 84.280 114.260 ;
        RECT 82.290 113.690 84.290 113.920 ;
        RECT 81.900 113.440 82.130 113.480 ;
        RECT 82.290 113.300 84.290 113.480 ;
        RECT 85.290 113.300 86.660 114.420 ;
        RECT 87.460 113.690 89.460 114.420 ;
        RECT 87.460 113.300 89.460 113.480 ;
        RECT 91.890 113.440 92.210 114.420 ;
        RECT 92.370 115.260 94.410 115.850 ;
        RECT 94.610 115.260 95.050 117.110 ;
        RECT 95.250 116.390 100.250 116.920 ;
        RECT 112.570 116.830 123.050 118.280 ;
        RECT 126.810 117.150 131.400 119.510 ;
        RECT 95.250 115.550 100.560 116.390 ;
        RECT 96.450 115.390 100.560 115.550 ;
        RECT 92.370 114.260 95.410 115.260 ;
        RECT 92.370 113.690 94.410 114.260 ;
        RECT 94.770 113.840 95.410 114.260 ;
        RECT 96.450 114.550 100.450 115.390 ;
        RECT 94.770 113.500 96.290 113.840 ;
        RECT 96.450 113.690 98.450 114.550 ;
        RECT 99.450 114.390 100.450 114.550 ;
        RECT 92.370 113.300 93.370 113.480 ;
        RECT 96.060 113.440 96.290 113.500 ;
        RECT 96.450 113.300 98.450 113.480 ;
        RECT 60.640 113.200 100.560 113.300 ;
        RECT 49.480 112.970 100.560 113.200 ;
        RECT 35.520 112.910 37.080 112.970 ;
        RECT 37.590 112.910 100.560 112.970 ;
        RECT 35.520 112.630 100.560 112.910 ;
        RECT 58.300 112.240 59.300 112.630 ;
        RECT 33.210 111.570 41.350 112.020 ;
        RECT 33.210 108.010 35.080 111.570 ;
        RECT 55.100 110.230 56.100 110.610 ;
        RECT 59.570 110.230 100.560 110.630 ;
        RECT 53.390 110.000 100.560 110.230 ;
        RECT 45.930 109.550 47.900 109.890 ;
        RECT 53.390 109.630 60.570 110.000 ;
        RECT 60.740 109.815 60.940 109.820 ;
        RECT 53.390 109.550 54.560 109.630 ;
        RECT 35.400 109.250 54.560 109.550 ;
        RECT 35.400 109.020 37.200 109.250 ;
        RECT 38.490 109.220 54.560 109.250 ;
        RECT 35.400 108.410 37.195 109.020 ;
        RECT 33.210 107.720 35.085 108.010 ;
        RECT 35.400 107.970 36.400 108.410 ;
        RECT 36.750 108.095 37.195 108.410 ;
        RECT 36.750 108.090 37.190 108.095 ;
        RECT 37.400 108.090 38.280 109.110 ;
        RECT 38.490 108.090 38.930 109.220 ;
        RECT 40.160 108.980 40.390 109.035 ;
        RECT 40.595 108.995 43.595 109.220 ;
        RECT 44.420 109.000 47.420 109.220 ;
        RECT 39.070 108.460 40.390 108.980 ;
        RECT 47.780 108.790 48.050 109.040 ;
        RECT 48.250 109.000 54.250 109.220 ;
        RECT 55.100 109.190 56.100 109.630 ;
        RECT 60.710 109.525 60.940 109.815 ;
        RECT 61.145 109.775 67.145 110.000 ;
        RECT 67.970 109.780 70.970 110.000 ;
        RECT 60.740 109.160 60.940 109.525 ;
        RECT 59.560 108.880 60.940 109.160 ;
        RECT 40.600 108.785 43.600 108.790 ;
        RECT 40.595 108.555 43.600 108.785 ;
        RECT 44.420 108.560 48.050 108.790 ;
        RECT 48.250 108.560 54.250 108.790 ;
        RECT 35.400 107.720 36.600 107.760 ;
        RECT 36.850 107.720 37.450 107.940 ;
        RECT 33.210 106.780 35.080 107.720 ;
        RECT 35.400 107.530 37.450 107.720 ;
        RECT 35.520 107.500 37.450 107.530 ;
        RECT 37.590 107.850 38.190 108.090 ;
        RECT 39.070 107.850 39.290 108.460 ;
        RECT 37.590 107.630 39.290 107.850 ;
        RECT 33.210 106.450 35.360 106.780 ;
        RECT 35.520 106.720 37.180 107.500 ;
        RECT 37.590 107.360 38.930 107.630 ;
        RECT 37.390 107.000 38.930 107.360 ;
        RECT 39.460 107.110 40.460 108.110 ;
        RECT 40.600 107.910 43.600 108.555 ;
        RECT 44.820 108.160 48.050 108.560 ;
        RECT 44.820 107.750 47.820 108.160 ;
        RECT 40.600 107.520 43.600 107.700 ;
        RECT 40.600 107.470 44.660 107.520 ;
        RECT 37.390 106.970 37.890 107.000 ;
        RECT 38.360 106.960 38.930 107.000 ;
        RECT 38.360 106.770 39.860 106.960 ;
        RECT 33.210 104.670 35.080 106.450 ;
        RECT 35.520 106.370 36.520 106.510 ;
        RECT 35.520 105.620 36.820 106.370 ;
        RECT 36.990 106.150 37.180 106.720 ;
        RECT 37.390 106.560 37.890 106.760 ;
        RECT 37.390 106.290 38.120 106.560 ;
        RECT 36.990 105.960 37.450 106.150 ;
        RECT 37.610 105.970 38.120 106.290 ;
        RECT 37.220 105.700 37.450 105.960 ;
        RECT 38.360 105.790 39.360 106.570 ;
        RECT 39.640 106.120 39.860 106.770 ;
        RECT 40.060 106.650 40.460 107.110 ;
        RECT 41.630 106.770 44.660 107.470 ;
        RECT 44.820 107.370 48.710 107.750 ;
        RECT 49.480 107.370 54.120 108.560 ;
        RECT 59.560 108.160 60.560 108.880 ;
        RECT 60.705 108.440 60.940 108.730 ;
        RECT 61.140 108.690 67.150 109.570 ;
        RECT 39.640 105.790 41.470 106.120 ;
        RECT 41.630 106.060 43.600 106.770 ;
        RECT 44.820 106.060 47.820 107.160 ;
        RECT 48.350 106.120 48.710 107.370 ;
        RECT 37.610 105.620 38.110 105.760 ;
        RECT 41.630 105.620 42.630 105.850 ;
        RECT 44.820 105.620 47.820 105.850 ;
        RECT 48.350 105.790 49.320 106.120 ;
        RECT 49.480 106.060 51.480 107.160 ;
        RECT 52.670 106.370 53.670 107.370 ;
        RECT 60.060 106.780 60.560 108.160 ;
        RECT 60.730 107.920 60.940 108.440 ;
        RECT 61.140 108.250 67.810 108.480 ;
        RECT 60.730 107.390 63.250 107.920 ;
        RECT 61.770 106.920 63.250 107.390 ;
        RECT 63.580 107.410 67.810 108.250 ;
        RECT 60.060 106.440 63.420 106.780 ;
        RECT 58.300 105.850 59.300 106.310 ;
        RECT 60.640 105.950 61.640 106.280 ;
        RECT 61.860 105.950 62.920 106.300 ;
        RECT 63.140 106.090 63.420 106.440 ;
        RECT 63.580 106.340 64.580 107.410 ;
        RECT 66.900 107.080 67.810 107.410 ;
        RECT 67.970 107.350 70.970 109.570 ;
        RECT 72.240 109.130 72.420 110.000 ;
        RECT 72.565 109.780 77.095 110.000 ;
        RECT 72.565 109.340 77.620 109.570 ;
        RECT 72.240 109.010 73.130 109.130 ;
        RECT 71.585 108.320 71.815 108.610 ;
        RECT 72.130 108.570 73.130 109.010 ;
        RECT 73.330 108.360 73.870 109.200 ;
        RECT 71.520 107.500 71.810 108.320 ;
        RECT 72.130 108.130 73.870 108.360 ;
        RECT 63.580 105.950 64.580 106.130 ;
        RECT 64.890 105.950 66.010 106.580 ;
        RECT 67.970 106.340 70.970 107.140 ;
        RECT 67.970 105.950 70.970 106.130 ;
        RECT 71.390 106.110 72.090 107.500 ;
        RECT 72.250 107.320 73.870 108.130 ;
        RECT 74.390 107.230 77.620 109.340 ;
        RECT 77.790 109.120 78.050 110.000 ;
        RECT 78.200 109.260 78.540 109.860 ;
        RECT 78.690 109.780 84.690 110.000 ;
        RECT 85.560 109.780 91.560 110.000 ;
        RECT 78.690 109.340 84.690 109.570 ;
        RECT 77.790 108.860 80.270 109.120 ;
        RECT 81.730 109.080 84.690 109.340 ;
        RECT 85.560 109.080 91.560 109.570 ;
        RECT 81.730 109.070 91.560 109.080 ;
        RECT 78.725 108.330 78.955 108.620 ;
        RECT 79.270 108.580 80.270 108.860 ;
        RECT 81.070 108.370 82.070 108.900 ;
        RECT 79.270 108.360 82.070 108.370 ;
        RECT 82.270 108.770 91.560 109.070 ;
        RECT 82.270 108.360 92.210 108.770 ;
        RECT 92.410 108.710 94.410 110.000 ;
        RECT 94.815 109.760 95.045 109.820 ;
        RECT 95.250 109.780 100.250 110.000 ;
        RECT 78.660 107.420 78.950 108.330 ;
        RECT 79.270 108.140 81.540 108.360 ;
        RECT 72.250 105.950 73.250 107.110 ;
        RECT 74.910 106.350 77.620 107.230 ;
        RECT 77.910 107.390 78.950 107.420 ;
        RECT 77.910 107.060 79.230 107.390 ;
        RECT 79.390 107.330 81.540 108.140 ;
        RECT 82.280 107.350 92.210 108.360 ;
        RECT 77.910 106.380 78.910 107.060 ;
        RECT 74.920 106.340 76.920 106.350 ;
        RECT 74.920 105.950 76.920 106.130 ;
        RECT 79.390 105.950 80.390 107.120 ;
        RECT 82.280 106.910 84.280 107.140 ;
        RECT 87.460 107.070 92.210 107.350 ;
        RECT 80.680 106.130 82.130 106.850 ;
        RECT 82.290 106.570 84.280 106.910 ;
        RECT 82.290 106.340 84.290 106.570 ;
        RECT 81.900 106.090 82.130 106.130 ;
        RECT 82.290 105.950 84.290 106.130 ;
        RECT 85.290 105.950 86.660 107.070 ;
        RECT 87.460 106.340 89.460 107.070 ;
        RECT 87.460 105.950 89.460 106.130 ;
        RECT 91.890 106.090 92.210 107.070 ;
        RECT 92.370 107.910 94.410 108.500 ;
        RECT 94.610 107.910 95.050 109.760 ;
        RECT 95.250 109.040 100.250 109.570 ;
        RECT 95.250 108.200 100.560 109.040 ;
        RECT 96.450 108.040 100.560 108.200 ;
        RECT 92.370 106.910 95.410 107.910 ;
        RECT 92.370 106.340 94.410 106.910 ;
        RECT 94.770 106.490 95.410 106.910 ;
        RECT 96.450 107.200 100.450 108.040 ;
        RECT 94.770 106.150 96.290 106.490 ;
        RECT 96.450 106.340 98.450 107.200 ;
        RECT 99.450 107.040 100.450 107.200 ;
        RECT 112.570 107.730 114.740 116.830 ;
        RECT 114.880 115.970 127.840 116.280 ;
        RECT 114.880 111.960 115.120 115.970 ;
        RECT 115.330 112.810 121.480 115.690 ;
        RECT 115.330 112.800 118.820 112.810 ;
        RECT 114.880 110.960 116.120 111.960 ;
        RECT 119.460 111.480 121.480 112.810 ;
        RECT 121.820 112.760 127.240 115.690 ;
        RECT 127.520 112.930 127.840 115.970 ;
        RECT 129.880 113.430 131.400 117.150 ;
        RECT 131.540 112.760 134.000 121.650 ;
        RECT 121.820 111.780 134.000 112.760 ;
        RECT 114.880 110.470 119.320 110.960 ;
        RECT 114.880 108.710 116.370 110.470 ;
        RECT 112.570 106.730 115.220 107.730 ;
        RECT 92.370 105.950 93.370 106.130 ;
        RECT 96.060 106.090 96.290 106.150 ;
        RECT 96.450 105.950 98.450 106.130 ;
        RECT 60.640 105.850 100.560 105.950 ;
        RECT 49.480 105.620 100.560 105.850 ;
        RECT 35.520 105.560 37.080 105.620 ;
        RECT 37.590 105.560 100.560 105.620 ;
        RECT 35.520 105.280 100.560 105.560 ;
        RECT 112.570 105.740 114.740 106.730 ;
        RECT 115.880 106.565 116.370 108.710 ;
        RECT 115.930 106.560 116.370 106.565 ;
        RECT 116.590 105.740 118.820 109.310 ;
        RECT 118.970 106.300 119.320 110.470 ;
        RECT 119.460 110.230 128.970 111.480 ;
        RECT 119.460 106.580 121.480 110.230 ;
        RECT 121.680 106.300 122.260 109.610 ;
        RECT 126.810 109.570 128.970 110.230 ;
        RECT 131.540 110.110 134.000 111.780 ;
        RECT 131.230 109.110 134.000 110.110 ;
        RECT 118.970 105.880 122.260 106.300 ;
        RECT 122.700 107.540 130.400 108.980 ;
        RECT 122.700 105.740 123.050 107.540 ;
        RECT 58.300 104.890 59.300 105.280 ;
        RECT 33.210 104.220 41.350 104.670 ;
        RECT 112.570 104.290 123.050 105.740 ;
        RECT 126.810 104.610 131.400 106.970 ;
        RECT 33.210 100.660 35.080 104.220 ;
        RECT 55.100 102.880 56.100 103.260 ;
        RECT 59.570 102.880 100.560 103.280 ;
        RECT 53.390 102.650 100.560 102.880 ;
        RECT 45.930 102.200 47.900 102.540 ;
        RECT 53.390 102.280 60.570 102.650 ;
        RECT 60.740 102.465 60.940 102.470 ;
        RECT 53.390 102.200 54.560 102.280 ;
        RECT 35.400 101.900 54.560 102.200 ;
        RECT 35.400 101.670 37.200 101.900 ;
        RECT 38.490 101.870 54.560 101.900 ;
        RECT 35.400 101.060 37.195 101.670 ;
        RECT 33.210 100.370 35.085 100.660 ;
        RECT 35.400 100.620 36.400 101.060 ;
        RECT 36.750 100.745 37.195 101.060 ;
        RECT 36.750 100.740 37.190 100.745 ;
        RECT 37.400 100.740 38.280 101.760 ;
        RECT 38.490 100.740 38.930 101.870 ;
        RECT 40.160 101.630 40.390 101.685 ;
        RECT 40.595 101.645 43.595 101.870 ;
        RECT 44.420 101.650 47.420 101.870 ;
        RECT 39.070 101.110 40.390 101.630 ;
        RECT 47.780 101.440 48.050 101.690 ;
        RECT 48.250 101.650 54.250 101.870 ;
        RECT 55.100 101.840 56.100 102.280 ;
        RECT 60.710 102.175 60.940 102.465 ;
        RECT 61.145 102.425 67.145 102.650 ;
        RECT 67.970 102.430 70.970 102.650 ;
        RECT 60.740 101.810 60.940 102.175 ;
        RECT 59.560 101.530 60.940 101.810 ;
        RECT 40.600 101.435 43.600 101.440 ;
        RECT 40.595 101.205 43.600 101.435 ;
        RECT 44.420 101.210 48.050 101.440 ;
        RECT 48.250 101.210 54.250 101.440 ;
        RECT 35.400 100.370 36.600 100.410 ;
        RECT 36.850 100.370 37.450 100.590 ;
        RECT 33.210 99.430 35.080 100.370 ;
        RECT 35.400 100.180 37.450 100.370 ;
        RECT 35.520 100.150 37.450 100.180 ;
        RECT 37.590 100.500 38.190 100.740 ;
        RECT 39.070 100.500 39.290 101.110 ;
        RECT 37.590 100.280 39.290 100.500 ;
        RECT 33.210 99.100 35.360 99.430 ;
        RECT 35.520 99.370 37.180 100.150 ;
        RECT 37.590 100.010 38.930 100.280 ;
        RECT 37.390 99.650 38.930 100.010 ;
        RECT 39.460 99.760 40.460 100.760 ;
        RECT 40.600 100.560 43.600 101.205 ;
        RECT 44.820 100.810 48.050 101.210 ;
        RECT 44.820 100.400 47.820 100.810 ;
        RECT 40.600 100.170 43.600 100.350 ;
        RECT 40.600 100.120 44.660 100.170 ;
        RECT 37.390 99.620 37.890 99.650 ;
        RECT 38.360 99.610 38.930 99.650 ;
        RECT 38.360 99.420 39.860 99.610 ;
        RECT 33.210 97.320 35.080 99.100 ;
        RECT 35.520 99.020 36.520 99.160 ;
        RECT 35.520 98.270 36.820 99.020 ;
        RECT 36.990 98.800 37.180 99.370 ;
        RECT 37.390 99.210 37.890 99.410 ;
        RECT 37.390 98.940 38.120 99.210 ;
        RECT 36.990 98.610 37.450 98.800 ;
        RECT 37.610 98.620 38.120 98.940 ;
        RECT 37.220 98.350 37.450 98.610 ;
        RECT 38.360 98.440 39.360 99.220 ;
        RECT 39.640 98.770 39.860 99.420 ;
        RECT 40.060 99.300 40.460 99.760 ;
        RECT 41.630 99.420 44.660 100.120 ;
        RECT 44.820 100.020 48.710 100.400 ;
        RECT 49.480 100.020 54.120 101.210 ;
        RECT 59.560 100.810 60.560 101.530 ;
        RECT 60.705 101.090 60.940 101.380 ;
        RECT 61.140 101.340 67.150 102.220 ;
        RECT 39.640 98.440 41.470 98.770 ;
        RECT 41.630 98.710 43.600 99.420 ;
        RECT 44.820 98.710 47.820 99.810 ;
        RECT 48.350 98.770 48.710 100.020 ;
        RECT 37.610 98.270 38.110 98.410 ;
        RECT 41.630 98.270 42.630 98.500 ;
        RECT 44.820 98.270 47.820 98.500 ;
        RECT 48.350 98.440 49.320 98.770 ;
        RECT 49.480 98.710 51.480 99.810 ;
        RECT 52.670 99.020 53.670 100.020 ;
        RECT 60.060 99.430 60.560 100.810 ;
        RECT 60.730 100.570 60.940 101.090 ;
        RECT 61.140 100.900 67.810 101.130 ;
        RECT 60.730 100.040 63.250 100.570 ;
        RECT 61.770 99.570 63.250 100.040 ;
        RECT 63.580 100.060 67.810 100.900 ;
        RECT 60.060 99.090 63.420 99.430 ;
        RECT 58.300 98.500 59.300 98.960 ;
        RECT 60.640 98.600 61.640 98.930 ;
        RECT 61.860 98.600 62.920 98.950 ;
        RECT 63.140 98.740 63.420 99.090 ;
        RECT 63.580 98.990 64.580 100.060 ;
        RECT 66.900 99.730 67.810 100.060 ;
        RECT 67.970 100.000 70.970 102.220 ;
        RECT 72.240 101.780 72.420 102.650 ;
        RECT 72.565 102.430 77.095 102.650 ;
        RECT 72.565 101.990 77.620 102.220 ;
        RECT 72.240 101.660 73.130 101.780 ;
        RECT 71.585 100.970 71.815 101.260 ;
        RECT 72.130 101.220 73.130 101.660 ;
        RECT 73.330 101.010 73.870 101.850 ;
        RECT 71.520 100.150 71.810 100.970 ;
        RECT 72.130 100.780 73.870 101.010 ;
        RECT 63.580 98.600 64.580 98.780 ;
        RECT 64.890 98.600 66.010 99.230 ;
        RECT 67.970 98.990 70.970 99.790 ;
        RECT 67.970 98.600 70.970 98.780 ;
        RECT 71.390 98.760 72.090 100.150 ;
        RECT 72.250 99.970 73.870 100.780 ;
        RECT 74.390 99.880 77.620 101.990 ;
        RECT 77.790 101.770 78.050 102.650 ;
        RECT 78.200 101.910 78.540 102.510 ;
        RECT 78.690 102.430 84.690 102.650 ;
        RECT 85.560 102.430 91.560 102.650 ;
        RECT 78.690 101.990 84.690 102.220 ;
        RECT 77.790 101.510 80.270 101.770 ;
        RECT 81.730 101.730 84.690 101.990 ;
        RECT 85.560 101.730 91.560 102.220 ;
        RECT 81.730 101.720 91.560 101.730 ;
        RECT 78.725 100.980 78.955 101.270 ;
        RECT 79.270 101.230 80.270 101.510 ;
        RECT 81.070 101.020 82.070 101.550 ;
        RECT 79.270 101.010 82.070 101.020 ;
        RECT 82.270 101.420 91.560 101.720 ;
        RECT 82.270 101.010 92.210 101.420 ;
        RECT 92.410 101.360 94.410 102.650 ;
        RECT 94.815 102.410 95.045 102.470 ;
        RECT 95.250 102.430 100.250 102.650 ;
        RECT 78.660 100.070 78.950 100.980 ;
        RECT 79.270 100.790 81.540 101.010 ;
        RECT 72.250 98.600 73.250 99.760 ;
        RECT 74.910 99.000 77.620 99.880 ;
        RECT 77.910 100.040 78.950 100.070 ;
        RECT 77.910 99.710 79.230 100.040 ;
        RECT 79.390 99.980 81.540 100.790 ;
        RECT 82.280 100.000 92.210 101.010 ;
        RECT 77.910 99.030 78.910 99.710 ;
        RECT 74.920 98.990 76.920 99.000 ;
        RECT 74.920 98.600 76.920 98.780 ;
        RECT 79.390 98.600 80.390 99.770 ;
        RECT 82.280 99.560 84.280 99.790 ;
        RECT 87.460 99.720 92.210 100.000 ;
        RECT 80.680 98.780 82.130 99.500 ;
        RECT 82.290 99.220 84.280 99.560 ;
        RECT 82.290 98.990 84.290 99.220 ;
        RECT 81.900 98.740 82.130 98.780 ;
        RECT 82.290 98.600 84.290 98.780 ;
        RECT 85.290 98.600 86.660 99.720 ;
        RECT 87.460 98.990 89.460 99.720 ;
        RECT 87.460 98.600 89.460 98.780 ;
        RECT 91.890 98.740 92.210 99.720 ;
        RECT 92.370 100.560 94.410 101.150 ;
        RECT 94.610 100.560 95.050 102.410 ;
        RECT 95.250 101.690 100.250 102.220 ;
        RECT 95.250 100.850 100.560 101.690 ;
        RECT 96.450 100.690 100.560 100.850 ;
        RECT 92.370 99.560 95.410 100.560 ;
        RECT 92.370 98.990 94.410 99.560 ;
        RECT 94.770 99.140 95.410 99.560 ;
        RECT 96.450 99.850 100.450 100.690 ;
        RECT 94.770 98.800 96.290 99.140 ;
        RECT 96.450 98.990 98.450 99.850 ;
        RECT 99.450 99.690 100.450 99.850 ;
        RECT 92.370 98.600 93.370 98.780 ;
        RECT 96.060 98.740 96.290 98.800 ;
        RECT 96.450 98.600 98.450 98.780 ;
        RECT 60.640 98.500 100.560 98.600 ;
        RECT 49.480 98.270 100.560 98.500 ;
        RECT 35.520 98.210 37.080 98.270 ;
        RECT 37.590 98.210 100.560 98.270 ;
        RECT 35.520 97.930 100.560 98.210 ;
        RECT 58.300 97.540 59.300 97.930 ;
        RECT 33.210 96.870 41.350 97.320 ;
        RECT 33.210 93.310 35.080 96.870 ;
        RECT 55.100 95.530 56.100 95.910 ;
        RECT 59.570 95.530 100.560 95.930 ;
        RECT 53.390 95.300 100.560 95.530 ;
        RECT 45.930 94.850 47.900 95.190 ;
        RECT 53.390 94.930 60.570 95.300 ;
        RECT 60.740 95.115 60.940 95.120 ;
        RECT 53.390 94.850 54.560 94.930 ;
        RECT 35.400 94.550 54.560 94.850 ;
        RECT 35.400 94.320 37.200 94.550 ;
        RECT 38.490 94.520 54.560 94.550 ;
        RECT 35.400 93.710 37.195 94.320 ;
        RECT 33.210 93.020 35.085 93.310 ;
        RECT 35.400 93.270 36.400 93.710 ;
        RECT 36.750 93.395 37.195 93.710 ;
        RECT 36.750 93.390 37.190 93.395 ;
        RECT 37.400 93.390 38.280 94.410 ;
        RECT 38.490 93.390 38.930 94.520 ;
        RECT 40.160 94.280 40.390 94.335 ;
        RECT 40.595 94.295 43.595 94.520 ;
        RECT 44.420 94.300 47.420 94.520 ;
        RECT 39.070 93.760 40.390 94.280 ;
        RECT 47.780 94.090 48.050 94.340 ;
        RECT 48.250 94.300 54.250 94.520 ;
        RECT 55.100 94.490 56.100 94.930 ;
        RECT 60.710 94.825 60.940 95.115 ;
        RECT 61.145 95.075 67.145 95.300 ;
        RECT 67.970 95.080 70.970 95.300 ;
        RECT 60.740 94.460 60.940 94.825 ;
        RECT 59.560 94.180 60.940 94.460 ;
        RECT 40.600 94.085 43.600 94.090 ;
        RECT 40.595 93.855 43.600 94.085 ;
        RECT 44.420 93.860 48.050 94.090 ;
        RECT 48.250 93.860 54.250 94.090 ;
        RECT 35.400 93.020 36.600 93.060 ;
        RECT 36.850 93.020 37.450 93.240 ;
        RECT 33.210 92.080 35.080 93.020 ;
        RECT 35.400 92.830 37.450 93.020 ;
        RECT 35.520 92.800 37.450 92.830 ;
        RECT 37.590 93.150 38.190 93.390 ;
        RECT 39.070 93.150 39.290 93.760 ;
        RECT 37.590 92.930 39.290 93.150 ;
        RECT 33.210 91.750 35.360 92.080 ;
        RECT 35.520 92.020 37.180 92.800 ;
        RECT 37.590 92.660 38.930 92.930 ;
        RECT 37.390 92.300 38.930 92.660 ;
        RECT 39.460 92.410 40.460 93.410 ;
        RECT 40.600 93.210 43.600 93.855 ;
        RECT 44.820 93.460 48.050 93.860 ;
        RECT 44.820 93.050 47.820 93.460 ;
        RECT 40.600 92.820 43.600 93.000 ;
        RECT 40.600 92.770 44.660 92.820 ;
        RECT 37.390 92.270 37.890 92.300 ;
        RECT 38.360 92.260 38.930 92.300 ;
        RECT 38.360 92.070 39.860 92.260 ;
        RECT 33.210 89.970 35.080 91.750 ;
        RECT 35.520 91.670 36.520 91.810 ;
        RECT 35.520 90.920 36.820 91.670 ;
        RECT 36.990 91.450 37.180 92.020 ;
        RECT 37.390 91.860 37.890 92.060 ;
        RECT 37.390 91.590 38.120 91.860 ;
        RECT 36.990 91.260 37.450 91.450 ;
        RECT 37.610 91.270 38.120 91.590 ;
        RECT 37.220 91.000 37.450 91.260 ;
        RECT 38.360 91.090 39.360 91.870 ;
        RECT 39.640 91.420 39.860 92.070 ;
        RECT 40.060 91.950 40.460 92.410 ;
        RECT 41.630 92.070 44.660 92.770 ;
        RECT 44.820 92.670 48.710 93.050 ;
        RECT 49.480 92.670 54.120 93.860 ;
        RECT 59.560 93.460 60.560 94.180 ;
        RECT 60.705 93.740 60.940 94.030 ;
        RECT 61.140 93.990 67.150 94.870 ;
        RECT 39.640 91.090 41.470 91.420 ;
        RECT 41.630 91.360 43.600 92.070 ;
        RECT 44.820 91.360 47.820 92.460 ;
        RECT 48.350 91.420 48.710 92.670 ;
        RECT 37.610 90.920 38.110 91.060 ;
        RECT 41.630 90.920 42.630 91.150 ;
        RECT 44.820 90.920 47.820 91.150 ;
        RECT 48.350 91.090 49.320 91.420 ;
        RECT 49.480 91.360 51.480 92.460 ;
        RECT 52.670 91.670 53.670 92.670 ;
        RECT 60.060 92.080 60.560 93.460 ;
        RECT 60.730 93.220 60.940 93.740 ;
        RECT 61.140 93.550 67.810 93.780 ;
        RECT 60.730 92.690 63.250 93.220 ;
        RECT 61.770 92.220 63.250 92.690 ;
        RECT 63.580 92.710 67.810 93.550 ;
        RECT 60.060 91.740 63.420 92.080 ;
        RECT 58.300 91.150 59.300 91.610 ;
        RECT 60.640 91.250 61.640 91.580 ;
        RECT 61.860 91.250 62.920 91.600 ;
        RECT 63.140 91.390 63.420 91.740 ;
        RECT 63.580 91.640 64.580 92.710 ;
        RECT 66.900 92.380 67.810 92.710 ;
        RECT 67.970 92.650 70.970 94.870 ;
        RECT 72.240 94.430 72.420 95.300 ;
        RECT 72.565 95.080 77.095 95.300 ;
        RECT 72.565 94.640 77.620 94.870 ;
        RECT 72.240 94.310 73.130 94.430 ;
        RECT 71.585 93.620 71.815 93.910 ;
        RECT 72.130 93.870 73.130 94.310 ;
        RECT 73.330 93.660 73.870 94.500 ;
        RECT 71.520 92.800 71.810 93.620 ;
        RECT 72.130 93.430 73.870 93.660 ;
        RECT 63.580 91.250 64.580 91.430 ;
        RECT 64.890 91.250 66.010 91.880 ;
        RECT 67.970 91.640 70.970 92.440 ;
        RECT 67.970 91.250 70.970 91.430 ;
        RECT 71.390 91.410 72.090 92.800 ;
        RECT 72.250 92.620 73.870 93.430 ;
        RECT 74.390 92.530 77.620 94.640 ;
        RECT 77.790 94.420 78.050 95.300 ;
        RECT 78.200 94.560 78.540 95.160 ;
        RECT 78.690 95.080 84.690 95.300 ;
        RECT 85.560 95.080 91.560 95.300 ;
        RECT 78.690 94.640 84.690 94.870 ;
        RECT 77.790 94.160 80.270 94.420 ;
        RECT 81.730 94.380 84.690 94.640 ;
        RECT 85.560 94.380 91.560 94.870 ;
        RECT 81.730 94.370 91.560 94.380 ;
        RECT 78.725 93.630 78.955 93.920 ;
        RECT 79.270 93.880 80.270 94.160 ;
        RECT 81.070 93.670 82.070 94.200 ;
        RECT 79.270 93.660 82.070 93.670 ;
        RECT 82.270 94.070 91.560 94.370 ;
        RECT 82.270 93.660 92.210 94.070 ;
        RECT 92.410 94.010 94.410 95.300 ;
        RECT 94.815 95.060 95.045 95.120 ;
        RECT 95.250 95.080 100.250 95.300 ;
        RECT 112.570 95.190 114.740 104.290 ;
        RECT 114.880 103.430 127.840 103.740 ;
        RECT 114.880 99.420 115.120 103.430 ;
        RECT 115.330 100.270 121.480 103.150 ;
        RECT 115.330 100.260 118.820 100.270 ;
        RECT 114.880 98.420 116.120 99.420 ;
        RECT 119.460 98.940 121.480 100.270 ;
        RECT 121.820 100.220 127.240 103.150 ;
        RECT 127.520 100.390 127.840 103.430 ;
        RECT 129.880 100.890 131.400 104.610 ;
        RECT 131.540 100.220 134.000 109.110 ;
        RECT 121.820 99.240 134.000 100.220 ;
        RECT 114.880 97.930 119.320 98.420 ;
        RECT 114.880 96.170 116.370 97.930 ;
        RECT 78.660 92.720 78.950 93.630 ;
        RECT 79.270 93.440 81.540 93.660 ;
        RECT 72.250 91.250 73.250 92.410 ;
        RECT 74.910 91.650 77.620 92.530 ;
        RECT 77.910 92.690 78.950 92.720 ;
        RECT 77.910 92.360 79.230 92.690 ;
        RECT 79.390 92.630 81.540 93.440 ;
        RECT 82.280 92.650 92.210 93.660 ;
        RECT 77.910 91.680 78.910 92.360 ;
        RECT 74.920 91.640 76.920 91.650 ;
        RECT 74.920 91.250 76.920 91.430 ;
        RECT 79.390 91.250 80.390 92.420 ;
        RECT 82.280 92.210 84.280 92.440 ;
        RECT 87.460 92.370 92.210 92.650 ;
        RECT 80.680 91.430 82.130 92.150 ;
        RECT 82.290 91.870 84.280 92.210 ;
        RECT 82.290 91.640 84.290 91.870 ;
        RECT 81.900 91.390 82.130 91.430 ;
        RECT 82.290 91.250 84.290 91.430 ;
        RECT 85.290 91.250 86.660 92.370 ;
        RECT 87.460 91.640 89.460 92.370 ;
        RECT 87.460 91.250 89.460 91.430 ;
        RECT 91.890 91.390 92.210 92.370 ;
        RECT 92.370 93.210 94.410 93.800 ;
        RECT 94.610 93.210 95.050 95.060 ;
        RECT 95.250 94.340 100.250 94.870 ;
        RECT 95.250 93.500 100.560 94.340 ;
        RECT 96.450 93.340 100.560 93.500 ;
        RECT 112.570 94.190 115.220 95.190 ;
        RECT 92.370 92.210 95.410 93.210 ;
        RECT 92.370 91.640 94.410 92.210 ;
        RECT 94.770 91.790 95.410 92.210 ;
        RECT 96.450 92.500 100.450 93.340 ;
        RECT 94.770 91.450 96.290 91.790 ;
        RECT 96.450 91.640 98.450 92.500 ;
        RECT 99.450 92.340 100.450 92.500 ;
        RECT 112.570 93.200 114.740 94.190 ;
        RECT 115.880 94.025 116.370 96.170 ;
        RECT 115.930 94.020 116.370 94.025 ;
        RECT 116.590 93.200 118.820 96.770 ;
        RECT 118.970 93.760 119.320 97.930 ;
        RECT 119.460 97.690 128.970 98.940 ;
        RECT 119.460 94.040 121.480 97.690 ;
        RECT 121.680 93.760 122.260 97.070 ;
        RECT 126.810 97.030 128.970 97.690 ;
        RECT 131.540 97.570 134.000 99.240 ;
        RECT 131.230 96.570 134.000 97.570 ;
        RECT 118.970 93.340 122.260 93.760 ;
        RECT 122.700 95.000 130.400 96.440 ;
        RECT 122.700 93.200 123.050 95.000 ;
        RECT 112.570 91.750 123.050 93.200 ;
        RECT 126.810 92.070 131.400 94.430 ;
        RECT 92.370 91.250 93.370 91.430 ;
        RECT 96.060 91.390 96.290 91.450 ;
        RECT 96.450 91.250 98.450 91.430 ;
        RECT 60.640 91.150 100.560 91.250 ;
        RECT 49.480 90.920 100.560 91.150 ;
        RECT 35.520 90.860 37.080 90.920 ;
        RECT 37.590 90.860 100.560 90.920 ;
        RECT 35.520 90.580 100.560 90.860 ;
        RECT 58.300 90.190 59.300 90.580 ;
        RECT 33.210 89.520 41.350 89.970 ;
        RECT 33.210 88.690 35.080 89.520 ;
        RECT 33.210 87.990 36.500 88.690 ;
        RECT 55.100 88.170 56.100 88.610 ;
        RECT 59.565 88.170 100.555 88.575 ;
        RECT 33.210 86.990 35.080 87.990 ;
        RECT 35.840 87.070 36.500 87.990 ;
        RECT 53.700 87.945 100.555 88.170 ;
        RECT 53.700 87.575 60.565 87.945 ;
        RECT 60.735 87.760 60.935 87.765 ;
        RECT 53.700 87.570 59.790 87.575 ;
        RECT 45.960 87.070 47.330 87.300 ;
        RECT 53.700 87.070 54.560 87.570 ;
        RECT 55.100 87.190 56.100 87.570 ;
        RECT 60.705 87.470 60.935 87.760 ;
        RECT 61.140 87.720 67.140 87.945 ;
        RECT 67.965 87.725 70.965 87.945 ;
        RECT 60.735 87.105 60.935 87.470 ;
        RECT 35.840 86.770 38.710 87.070 ;
        RECT 36.890 86.650 37.890 86.770 ;
        RECT 34.910 85.140 35.910 86.610 ;
        RECT 36.120 86.510 36.750 86.610 ;
        RECT 36.120 85.420 37.360 86.510 ;
        RECT 37.560 86.290 37.790 86.480 ;
        RECT 38.380 86.430 38.710 86.770 ;
        RECT 38.910 86.720 54.560 87.070 ;
        RECT 59.555 86.825 60.935 87.105 ;
        RECT 38.910 86.290 39.910 86.720 ;
        RECT 37.560 85.480 38.440 86.290 ;
        RECT 34.910 84.540 35.490 85.140 ;
        RECT 36.120 84.680 37.120 85.420 ;
        RECT 38.210 85.290 38.440 85.480 ;
        RECT 38.650 86.070 39.910 86.290 ;
        RECT 38.650 85.290 39.470 86.070 ;
        RECT 34.910 83.540 36.490 84.540 ;
        RECT 36.770 83.950 37.120 84.680 ;
        RECT 37.290 85.140 37.980 85.280 ;
        RECT 37.290 84.140 38.290 85.140 ;
        RECT 40.100 85.060 40.390 86.560 ;
        RECT 40.590 86.500 43.590 86.720 ;
        RECT 44.420 86.500 47.420 86.720 ;
        RECT 47.750 86.290 48.050 86.570 ;
        RECT 48.250 86.500 54.250 86.720 ;
        RECT 40.580 85.410 43.590 86.290 ;
        RECT 44.420 86.060 48.050 86.290 ;
        RECT 48.250 86.060 54.250 86.290 ;
        RECT 59.555 86.105 60.555 86.825 ;
        RECT 60.700 86.385 60.935 86.675 ;
        RECT 61.135 86.635 67.145 87.515 ;
        RECT 45.010 85.690 48.050 86.060 ;
        RECT 45.010 85.420 48.590 85.690 ;
        RECT 38.600 84.820 40.390 85.060 ;
        RECT 40.585 85.070 43.585 85.205 ;
        RECT 40.585 84.975 44.850 85.070 ;
        RECT 45.010 85.010 48.010 85.420 ;
        RECT 38.600 83.950 38.800 84.820 ;
        RECT 36.770 83.740 38.800 83.950 ;
        RECT 38.940 83.680 39.940 84.680 ;
        RECT 40.100 84.040 40.390 84.820 ;
        RECT 41.600 84.740 44.850 84.975 ;
        RECT 40.100 83.710 41.450 84.040 ;
        RECT 41.600 83.980 42.600 84.740 ;
        RECT 41.600 83.540 42.600 83.770 ;
        RECT 42.990 83.540 43.730 84.190 ;
        RECT 45.010 83.980 48.010 84.800 ;
        RECT 48.320 84.040 48.590 85.420 ;
        RECT 49.300 85.010 53.490 86.060 ;
        RECT 45.010 83.540 48.010 83.770 ;
        RECT 48.320 83.710 49.140 84.040 ;
        RECT 49.300 83.980 51.300 84.800 ;
        RECT 60.055 84.725 60.555 86.105 ;
        RECT 60.725 85.865 60.935 86.385 ;
        RECT 61.135 86.195 67.805 86.425 ;
        RECT 60.725 85.335 63.245 85.865 ;
        RECT 61.765 84.865 63.245 85.335 ;
        RECT 63.575 85.355 67.805 86.195 ;
        RECT 58.300 83.770 59.300 84.640 ;
        RECT 60.055 84.385 63.415 84.725 ;
        RECT 60.635 83.895 61.635 84.225 ;
        RECT 61.855 83.895 62.915 84.245 ;
        RECT 63.135 84.035 63.415 84.385 ;
        RECT 63.575 84.285 64.575 85.355 ;
        RECT 66.895 85.025 67.805 85.355 ;
        RECT 67.965 85.295 70.965 87.515 ;
        RECT 72.235 87.075 72.415 87.945 ;
        RECT 72.560 87.725 77.090 87.945 ;
        RECT 72.560 87.285 77.615 87.515 ;
        RECT 72.235 86.955 73.125 87.075 ;
        RECT 71.580 86.265 71.810 86.555 ;
        RECT 72.125 86.515 73.125 86.955 ;
        RECT 73.325 86.305 73.865 87.145 ;
        RECT 71.515 85.445 71.805 86.265 ;
        RECT 72.125 86.075 73.865 86.305 ;
        RECT 63.575 83.895 64.575 84.075 ;
        RECT 64.885 83.895 66.005 84.525 ;
        RECT 67.965 84.285 70.965 85.085 ;
        RECT 67.965 83.895 70.965 84.075 ;
        RECT 71.385 84.055 72.085 85.445 ;
        RECT 72.245 85.265 73.865 86.075 ;
        RECT 74.385 85.175 77.615 87.285 ;
        RECT 77.785 87.065 78.045 87.945 ;
        RECT 78.195 87.205 78.535 87.805 ;
        RECT 78.685 87.725 84.685 87.945 ;
        RECT 85.555 87.725 91.555 87.945 ;
        RECT 78.685 87.285 84.685 87.515 ;
        RECT 77.785 86.805 80.265 87.065 ;
        RECT 81.725 87.025 84.685 87.285 ;
        RECT 85.555 87.025 91.555 87.515 ;
        RECT 81.725 87.015 91.555 87.025 ;
        RECT 78.720 86.275 78.950 86.565 ;
        RECT 79.265 86.525 80.265 86.805 ;
        RECT 81.065 86.315 82.065 86.845 ;
        RECT 79.265 86.305 82.065 86.315 ;
        RECT 82.265 86.715 91.555 87.015 ;
        RECT 82.265 86.305 92.205 86.715 ;
        RECT 92.405 86.655 94.405 87.945 ;
        RECT 94.810 87.705 95.040 87.765 ;
        RECT 95.245 87.725 100.245 87.945 ;
        RECT 78.655 85.365 78.945 86.275 ;
        RECT 79.265 86.085 81.535 86.305 ;
        RECT 72.245 83.895 73.245 85.055 ;
        RECT 74.905 84.295 77.615 85.175 ;
        RECT 77.905 85.335 78.945 85.365 ;
        RECT 77.905 85.005 79.225 85.335 ;
        RECT 79.385 85.275 81.535 86.085 ;
        RECT 82.275 85.295 92.205 86.305 ;
        RECT 77.905 84.730 78.905 85.005 ;
        RECT 77.905 84.325 78.910 84.730 ;
        RECT 74.915 84.285 76.915 84.295 ;
        RECT 74.915 83.895 76.915 84.075 ;
        RECT 77.910 83.895 78.910 84.325 ;
        RECT 79.385 83.895 80.385 85.065 ;
        RECT 82.275 84.855 84.275 85.085 ;
        RECT 87.455 85.015 92.205 85.295 ;
        RECT 80.675 84.075 82.125 84.795 ;
        RECT 82.285 84.515 84.275 84.855 ;
        RECT 82.285 84.285 84.285 84.515 ;
        RECT 81.895 84.035 82.125 84.075 ;
        RECT 82.285 83.895 84.285 84.075 ;
        RECT 85.285 83.895 86.655 85.015 ;
        RECT 87.455 84.285 89.455 85.015 ;
        RECT 87.455 83.895 89.455 84.075 ;
        RECT 91.885 84.035 92.205 85.015 ;
        RECT 92.365 85.855 94.405 86.445 ;
        RECT 94.605 85.855 95.045 87.705 ;
        RECT 95.245 86.980 100.245 87.515 ;
        RECT 95.245 86.145 100.560 86.980 ;
        RECT 96.445 85.980 100.560 86.145 ;
        RECT 92.365 84.855 95.405 85.855 ;
        RECT 92.365 84.285 94.405 84.855 ;
        RECT 94.765 84.435 95.405 84.855 ;
        RECT 96.445 85.145 100.440 85.980 ;
        RECT 94.765 84.095 96.285 84.435 ;
        RECT 96.445 84.285 98.445 85.145 ;
        RECT 99.440 84.980 100.440 85.145 ;
        RECT 92.365 83.895 93.365 84.075 ;
        RECT 96.055 84.035 96.285 84.095 ;
        RECT 96.445 83.895 98.445 84.075 ;
        RECT 60.635 83.770 100.555 83.895 ;
        RECT 49.300 83.540 100.555 83.770 ;
        RECT 34.910 83.225 100.555 83.540 ;
        RECT 34.910 83.220 60.640 83.225 ;
        RECT 52.410 76.030 54.560 83.220 ;
        RECT 55.100 81.770 56.100 82.770 ;
        RECT 46.560 76.020 54.560 76.030 ;
        RECT 34.690 75.340 54.560 76.020 ;
        RECT 33.500 74.270 34.530 75.130 ;
        RECT 34.690 75.070 45.690 75.340 ;
        RECT 37.060 75.020 45.690 75.070 ;
        RECT 25.780 72.480 34.530 74.270 ;
        RECT 34.690 73.660 36.690 74.860 ;
        RECT 45.860 74.270 46.400 75.140 ;
        RECT 46.560 75.080 54.560 75.340 ;
        RECT 46.560 74.100 54.560 74.870 ;
        RECT 54.720 74.270 55.260 75.140 ;
        RECT 34.690 72.660 37.690 73.660 ;
        RECT 25.780 24.050 26.780 72.480 ;
        RECT 32.530 71.440 33.180 72.480 ;
        RECT 34.690 71.940 36.690 72.660 ;
        RECT 46.560 72.480 47.120 74.100 ;
        RECT 47.600 72.480 48.740 74.100 ;
        RECT 49.220 72.480 50.350 74.100 ;
        RECT 50.830 72.480 52.150 74.100 ;
        RECT 52.630 72.480 53.140 74.100 ;
        RECT 53.620 74.090 54.560 74.100 ;
        RECT 56.700 74.090 57.700 82.770 ;
        RECT 58.300 81.770 59.300 82.770 ;
        RECT 112.570 82.650 114.740 91.750 ;
        RECT 114.880 90.890 127.840 91.200 ;
        RECT 114.880 86.880 115.120 90.890 ;
        RECT 115.330 87.730 121.480 90.610 ;
        RECT 115.330 87.720 118.820 87.730 ;
        RECT 114.880 85.880 116.120 86.880 ;
        RECT 119.460 86.400 121.480 87.730 ;
        RECT 121.820 87.680 127.240 90.610 ;
        RECT 127.520 87.850 127.840 90.890 ;
        RECT 129.880 88.350 131.400 92.070 ;
        RECT 131.540 87.680 134.000 96.570 ;
        RECT 121.820 86.700 134.000 87.680 ;
        RECT 114.880 85.390 119.320 85.880 ;
        RECT 114.880 83.630 116.370 85.390 ;
        RECT 112.570 81.650 115.220 82.650 ;
        RECT 53.620 72.480 57.700 74.090 ;
        RECT 33.380 71.710 38.380 71.940 ;
        RECT 33.380 71.280 39.300 71.500 ;
        RECT 39.470 71.440 40.060 72.310 ;
        RECT 46.560 71.940 57.700 72.480 ;
        RECT 40.215 71.710 60.215 71.940 ;
        RECT 40.210 71.280 60.220 71.500 ;
        RECT 60.370 71.440 60.960 72.310 ;
        RECT 33.380 70.550 60.220 71.280 ;
        RECT 56.850 66.010 59.230 70.550 ;
        RECT 43.320 60.890 53.040 61.890 ;
        RECT 36.070 59.990 36.790 60.270 ;
        RECT 35.720 59.570 38.670 59.990 ;
        RECT 35.720 59.310 36.720 59.570 ;
        RECT 36.880 59.100 37.450 59.370 ;
        RECT 37.670 59.310 38.670 59.570 ;
        RECT 38.830 59.100 39.400 59.370 ;
        RECT 33.090 58.290 36.720 59.100 ;
        RECT 36.880 59.040 38.670 59.100 ;
        RECT 38.830 59.040 41.110 59.100 ;
        RECT 37.160 58.290 38.670 59.040 ;
        RECT 33.090 58.100 36.840 58.290 ;
        RECT 37.160 58.100 38.790 58.290 ;
        RECT 39.110 58.100 41.110 59.040 ;
        RECT 35.640 58.060 36.840 58.100 ;
        RECT 35.840 57.510 36.840 57.850 ;
        RECT 37.155 57.810 37.385 58.100 ;
        RECT 37.590 58.060 38.790 58.100 ;
        RECT 37.790 57.510 38.790 57.850 ;
        RECT 39.105 57.810 39.335 58.100 ;
        RECT 34.580 57.290 38.790 57.510 ;
        RECT 34.580 57.140 39.190 57.290 ;
        RECT 36.530 54.610 37.530 56.910 ;
        RECT 38.130 56.820 39.190 57.140 ;
        RECT 40.110 56.320 41.110 58.100 ;
        RECT 41.560 56.320 43.390 60.690 ;
        RECT 43.590 57.690 44.540 60.690 ;
        RECT 37.730 54.770 38.600 55.310 ;
        RECT 39.670 54.610 39.900 54.920 ;
        RECT 36.530 52.610 37.790 54.610 ;
        RECT 35.530 51.610 37.790 52.610 ;
        RECT 36.530 49.610 37.790 51.610 ;
        RECT 38.000 53.920 39.900 54.610 ;
        RECT 40.110 53.920 43.390 56.320 ;
        RECT 43.820 56.210 44.540 57.690 ;
        RECT 43.590 54.490 44.540 56.210 ;
        RECT 38.000 50.300 39.500 53.920 ;
        RECT 39.860 53.530 42.430 53.760 ;
        RECT 39.920 53.010 42.430 53.530 ;
        RECT 43.150 53.210 43.380 53.920 ;
        RECT 43.590 53.330 47.150 54.490 ;
        RECT 43.590 53.210 44.540 53.330 ;
        RECT 39.920 53.005 43.570 53.010 ;
        RECT 39.920 52.775 43.630 53.005 ;
        RECT 39.920 52.770 43.570 52.775 ;
        RECT 41.930 52.370 43.570 52.770 ;
        RECT 41.930 51.450 43.570 51.850 ;
        RECT 39.920 51.445 43.570 51.450 ;
        RECT 39.920 51.215 43.630 51.445 ;
        RECT 39.920 51.210 43.570 51.215 ;
        RECT 39.920 50.690 42.430 51.210 ;
        RECT 43.820 51.010 44.540 53.210 ;
        RECT 46.150 52.860 47.150 53.330 ;
        RECT 49.120 53.660 50.530 56.910 ;
        RECT 51.740 53.660 53.040 60.890 ;
        RECT 56.850 61.870 72.910 66.010 ;
        RECT 56.850 58.770 59.230 61.870 ;
        RECT 69.410 60.010 72.910 61.870 ;
        RECT 69.410 58.790 70.660 60.010 ;
        RECT 71.670 58.790 72.910 60.010 ;
        RECT 53.720 54.040 54.720 55.120 ;
        RECT 54.220 53.660 54.450 53.840 ;
        RECT 49.120 53.160 50.760 53.660 ;
        RECT 50.970 53.160 54.450 53.660 ;
        RECT 45.950 52.420 47.150 52.650 ;
        RECT 45.950 51.610 47.030 52.420 ;
        RECT 47.460 51.670 48.220 52.900 ;
        RECT 39.860 50.460 42.430 50.690 ;
        RECT 43.150 50.300 43.380 51.010 ;
        RECT 38.000 49.610 39.900 50.300 ;
        RECT 36.530 47.240 37.530 49.610 ;
        RECT 37.730 48.910 38.600 49.450 ;
        RECT 39.670 49.300 39.900 49.610 ;
        RECT 40.110 47.900 43.380 50.300 ;
        RECT 43.590 48.010 44.540 51.010 ;
        RECT 46.030 50.920 47.030 51.400 ;
        RECT 47.190 51.340 48.220 51.670 ;
        RECT 49.120 51.060 50.530 53.160 ;
        RECT 50.720 52.770 51.570 53.000 ;
        RECT 52.450 52.840 54.450 53.160 ;
        RECT 54.660 53.110 55.610 53.840 ;
        RECT 55.960 53.310 57.370 53.850 ;
        RECT 57.540 53.110 58.470 58.770 ;
        RECT 69.410 58.480 72.910 58.790 ;
        RECT 79.140 58.480 80.140 59.480 ;
        RECT 92.210 59.440 93.210 60.440 ;
        RECT 97.020 59.440 101.430 80.960 ;
        RECT 112.570 80.660 114.740 81.650 ;
        RECT 115.880 81.485 116.370 83.630 ;
        RECT 115.930 81.480 116.370 81.485 ;
        RECT 116.590 80.660 118.820 84.230 ;
        RECT 118.970 81.220 119.320 85.390 ;
        RECT 119.460 85.150 128.970 86.400 ;
        RECT 119.460 81.500 121.480 85.150 ;
        RECT 121.680 81.220 122.260 84.530 ;
        RECT 126.810 84.490 128.970 85.150 ;
        RECT 131.540 85.030 134.000 86.700 ;
        RECT 131.230 84.030 134.000 85.030 ;
        RECT 118.970 80.800 122.260 81.220 ;
        RECT 122.700 82.460 130.400 83.900 ;
        RECT 122.700 80.660 123.050 82.460 ;
        RECT 112.570 79.210 123.050 80.660 ;
        RECT 126.810 79.530 131.400 81.890 ;
        RECT 112.570 70.110 114.740 79.210 ;
        RECT 114.880 78.350 127.840 78.660 ;
        RECT 114.880 74.340 115.120 78.350 ;
        RECT 115.330 75.190 121.480 78.070 ;
        RECT 115.330 75.180 118.820 75.190 ;
        RECT 114.880 73.340 116.120 74.340 ;
        RECT 119.460 73.860 121.480 75.190 ;
        RECT 121.820 75.140 127.240 78.070 ;
        RECT 127.520 75.310 127.840 78.350 ;
        RECT 129.880 75.810 131.400 79.530 ;
        RECT 131.540 75.140 134.000 84.030 ;
        RECT 121.820 74.160 134.000 75.140 ;
        RECT 114.880 72.850 119.320 73.340 ;
        RECT 114.880 71.090 116.370 72.850 ;
        RECT 112.570 69.110 115.220 70.110 ;
        RECT 112.570 68.120 114.740 69.110 ;
        RECT 115.880 68.945 116.370 71.090 ;
        RECT 115.930 68.940 116.370 68.945 ;
        RECT 116.590 68.120 118.820 71.690 ;
        RECT 118.970 68.680 119.320 72.850 ;
        RECT 119.460 72.610 128.970 73.860 ;
        RECT 119.460 68.960 121.480 72.610 ;
        RECT 121.680 68.680 122.260 71.990 ;
        RECT 126.810 71.950 128.970 72.610 ;
        RECT 131.540 72.490 134.000 74.160 ;
        RECT 131.230 71.490 134.000 72.490 ;
        RECT 118.970 68.260 122.260 68.680 ;
        RECT 122.700 69.920 130.400 71.360 ;
        RECT 122.700 68.120 123.050 69.920 ;
        RECT 112.570 66.670 123.050 68.120 ;
        RECT 126.810 66.990 131.400 69.350 ;
        RECT 92.210 58.750 105.140 59.440 ;
        RECT 63.180 55.330 66.980 58.050 ;
        RECT 68.010 56.350 68.550 57.220 ;
        RECT 68.750 56.620 88.760 58.480 ;
        RECT 92.210 58.440 94.540 58.750 ;
        RECT 68.755 56.180 88.755 56.410 ;
        RECT 88.960 56.350 89.500 57.220 ;
        RECT 78.640 55.810 87.640 56.180 ;
        RECT 63.180 55.130 68.530 55.330 ;
        RECT 78.640 55.210 81.010 55.810 ;
        RECT 63.980 54.780 68.530 55.130 ;
        RECT 50.780 51.450 51.570 52.770 ;
        RECT 50.720 51.220 51.570 51.450 ;
        RECT 52.450 51.060 54.450 51.360 ;
        RECT 49.120 50.920 50.760 51.060 ;
        RECT 46.030 50.560 50.760 50.920 ;
        RECT 50.970 50.560 54.450 51.060 ;
        RECT 46.030 49.720 50.530 50.560 ;
        RECT 36.530 47.150 37.780 47.240 ;
        RECT 35.720 46.590 38.670 47.150 ;
        RECT 35.720 46.330 36.720 46.590 ;
        RECT 36.880 46.120 37.450 46.390 ;
        RECT 37.670 46.330 38.670 46.590 ;
        RECT 38.830 46.120 39.400 46.390 ;
        RECT 40.110 46.120 41.110 47.900 ;
        RECT 34.530 45.310 36.720 46.120 ;
        RECT 36.880 46.060 38.670 46.120 ;
        RECT 38.830 46.060 41.110 46.120 ;
        RECT 37.160 45.310 38.670 46.060 ;
        RECT 34.530 45.080 36.840 45.310 ;
        RECT 37.160 45.120 38.790 45.310 ;
        RECT 39.110 45.120 41.110 46.060 ;
        RECT 34.530 41.790 35.530 45.080 ;
        RECT 35.840 44.610 36.840 44.870 ;
        RECT 37.155 44.830 37.385 45.120 ;
        RECT 37.590 45.080 38.790 45.120 ;
        RECT 37.790 44.610 38.790 44.870 ;
        RECT 39.105 44.830 39.335 45.120 ;
        RECT 35.840 43.660 38.790 44.610 ;
        RECT 41.550 43.530 43.380 47.900 ;
        RECT 43.820 46.530 44.540 48.010 ;
        RECT 49.120 47.310 50.530 49.720 ;
        RECT 43.590 43.530 44.540 46.530 ;
        RECT 51.740 43.330 53.040 50.560 ;
        RECT 54.220 50.360 54.450 50.560 ;
        RECT 54.660 51.100 56.560 53.110 ;
        RECT 56.770 51.160 58.470 53.110 ;
        RECT 63.280 54.170 63.820 54.420 ;
        RECT 63.980 54.380 64.480 54.780 ;
        RECT 64.640 54.170 65.180 54.440 ;
        RECT 58.740 51.610 61.140 52.610 ;
        RECT 56.770 51.100 59.470 51.160 ;
        RECT 54.660 50.360 55.610 51.100 ;
        RECT 55.960 50.360 57.370 50.900 ;
        RECT 57.540 50.160 59.470 51.100 ;
        RECT 53.720 49.080 54.720 50.160 ;
        RECT 57.540 44.200 58.470 50.160 ;
        RECT 43.320 42.330 53.040 43.330 ;
        RECT 59.940 41.020 61.140 51.610 ;
        RECT 63.280 50.820 65.180 54.170 ;
        RECT 66.350 52.790 68.530 54.780 ;
        RECT 77.640 54.210 81.010 55.210 ;
        RECT 78.640 53.860 81.010 54.210 ;
        RECT 85.570 53.860 87.640 55.810 ;
        RECT 93.210 54.920 94.540 58.440 ;
        RECT 88.910 54.140 94.540 54.920 ;
        RECT 77.940 53.010 78.480 53.860 ;
        RECT 78.640 53.260 87.640 53.860 ;
        RECT 78.640 52.790 87.640 53.050 ;
        RECT 87.800 53.010 88.340 53.860 ;
        RECT 88.910 52.790 89.730 54.140 ;
        RECT 91.860 53.940 94.540 54.140 ;
        RECT 66.350 51.410 89.730 52.790 ;
        RECT 91.160 53.050 91.700 53.320 ;
        RECT 91.860 53.260 92.310 53.940 ;
        RECT 93.930 53.650 94.530 53.940 ;
        RECT 94.700 53.810 95.410 54.350 ;
        RECT 96.080 53.850 97.540 54.100 ;
        RECT 96.080 53.650 98.490 53.850 ;
        RECT 92.470 53.050 93.010 53.320 ;
        RECT 91.160 52.450 93.010 53.050 ;
        RECT 93.930 53.150 95.140 53.650 ;
        RECT 95.350 53.150 98.490 53.650 ;
        RECT 63.250 50.390 65.250 50.820 ;
        RECT 63.250 46.810 65.250 48.180 ;
        RECT 66.350 47.310 67.420 51.410 ;
        RECT 77.940 50.340 78.480 51.190 ;
        RECT 78.640 51.150 87.640 51.410 ;
        RECT 78.640 50.340 87.640 50.940 ;
        RECT 87.800 50.340 88.340 51.190 ;
        RECT 78.640 49.990 81.010 50.340 ;
        RECT 77.640 48.990 81.010 49.990 ;
        RECT 78.640 48.390 81.010 48.990 ;
        RECT 85.570 48.390 87.640 50.340 ;
        RECT 91.740 49.110 92.430 52.450 ;
        RECT 93.930 51.440 94.540 53.150 ;
        RECT 94.700 52.450 95.410 52.990 ;
        RECT 96.080 52.850 98.490 53.150 ;
        RECT 98.700 53.110 99.860 53.850 ;
        RECT 100.540 53.310 101.410 53.850 ;
        RECT 102.230 53.110 103.260 58.480 ;
        RECT 104.450 56.450 105.140 58.750 ;
        RECT 112.570 57.570 114.740 66.670 ;
        RECT 114.880 65.810 127.840 66.120 ;
        RECT 114.880 61.800 115.120 65.810 ;
        RECT 115.330 62.650 121.480 65.530 ;
        RECT 115.330 62.640 118.820 62.650 ;
        RECT 114.880 60.800 116.120 61.800 ;
        RECT 119.460 61.320 121.480 62.650 ;
        RECT 121.820 62.600 127.240 65.530 ;
        RECT 127.520 62.770 127.840 65.810 ;
        RECT 129.880 63.270 131.400 66.990 ;
        RECT 131.540 62.600 134.000 71.490 ;
        RECT 121.820 61.620 134.000 62.600 ;
        RECT 114.880 60.310 119.320 60.800 ;
        RECT 114.880 58.550 116.370 60.310 ;
        RECT 112.570 56.570 115.220 57.570 ;
        RECT 92.850 51.050 94.540 51.440 ;
        RECT 94.700 51.210 95.410 51.750 ;
        RECT 96.080 51.050 98.490 51.370 ;
        RECT 92.850 50.550 95.140 51.050 ;
        RECT 95.350 50.550 98.490 51.050 ;
        RECT 93.350 48.560 94.370 50.550 ;
        RECT 94.700 49.850 95.410 50.390 ;
        RECT 96.080 50.370 98.490 50.550 ;
        RECT 98.700 51.100 100.600 53.110 ;
        RECT 100.810 51.110 103.260 53.110 ;
        RECT 104.450 51.550 105.140 55.920 ;
        RECT 112.570 55.580 114.740 56.570 ;
        RECT 115.880 56.405 116.370 58.550 ;
        RECT 115.930 56.400 116.370 56.405 ;
        RECT 116.590 55.580 118.820 59.150 ;
        RECT 118.970 56.140 119.320 60.310 ;
        RECT 119.460 60.070 128.970 61.320 ;
        RECT 119.460 56.420 121.480 60.070 ;
        RECT 121.680 56.140 122.260 59.450 ;
        RECT 126.810 59.410 128.970 60.070 ;
        RECT 131.540 59.950 134.000 61.620 ;
        RECT 131.230 58.950 134.000 59.950 ;
        RECT 118.970 55.720 122.260 56.140 ;
        RECT 122.700 57.380 130.400 58.820 ;
        RECT 122.700 55.580 123.050 57.380 ;
        RECT 112.570 54.130 123.050 55.580 ;
        RECT 126.810 54.450 131.400 56.810 ;
        RECT 113.620 53.720 114.740 54.130 ;
        RECT 129.880 53.720 131.400 54.450 ;
        RECT 131.540 53.720 134.000 58.950 ;
        RECT 100.810 51.100 101.760 51.110 ;
        RECT 98.700 50.370 99.860 51.100 ;
        RECT 96.080 50.120 97.540 50.370 ;
        RECT 100.540 50.360 101.410 50.900 ;
        RECT 98.430 49.170 99.430 50.170 ;
        RECT 102.240 49.340 103.260 51.110 ;
        RECT 103.800 50.950 105.790 51.550 ;
        RECT 103.800 50.700 104.340 50.950 ;
        RECT 104.540 49.340 105.050 50.740 ;
        RECT 105.250 50.700 105.790 50.950 ;
        RECT 129.890 49.790 131.400 53.720 ;
        RECT 102.240 48.860 105.050 49.340 ;
        RECT 78.640 48.020 87.640 48.390 ;
        RECT 68.010 46.980 68.550 47.850 ;
        RECT 68.755 47.790 88.755 48.020 ;
        RECT 68.750 46.810 88.760 47.580 ;
        RECT 88.960 46.980 89.500 47.850 ;
        RECT 91.790 47.430 92.380 48.555 ;
        RECT 93.350 47.820 100.770 48.560 ;
        RECT 102.230 48.390 105.050 48.860 ;
        RECT 108.610 48.790 131.400 49.790 ;
        RECT 102.230 47.430 104.620 48.390 ;
        RECT 91.790 47.390 104.620 47.430 ;
        RECT 91.790 46.810 103.620 47.390 ;
        RECT 63.250 45.590 103.620 46.810 ;
        RECT 29.210 39.610 61.140 41.020 ;
        RECT 64.120 45.580 68.510 45.590 ;
        RECT 64.120 45.570 67.870 45.580 ;
        RECT 64.120 44.440 66.750 45.570 ;
        RECT 64.120 43.660 68.510 44.440 ;
        RECT 94.390 43.660 99.650 45.590 ;
        RECT 29.210 38.610 30.210 39.610 ;
        RECT 51.150 38.610 52.150 39.610 ;
        RECT 40.150 37.530 49.260 38.530 ;
        RECT 33.090 36.110 39.160 37.110 ;
        RECT 35.630 33.460 37.690 33.820 ;
        RECT 32.210 33.250 37.690 33.460 ;
        RECT 32.210 32.460 33.210 33.250 ;
        RECT 34.570 33.020 35.570 33.250 ;
        RECT 36.190 33.020 37.190 33.250 ;
        RECT 32.710 32.160 33.210 32.460 ;
        RECT 32.210 31.410 32.510 32.000 ;
        RECT 32.710 31.930 33.710 32.160 ;
        RECT 34.080 31.970 34.360 31.990 ;
        RECT 34.080 31.720 34.365 31.970 ;
        RECT 34.570 31.930 37.190 32.810 ;
        RECT 38.140 32.660 39.160 36.110 ;
        RECT 27.430 30.400 29.430 31.400 ;
        RECT 30.510 30.410 32.510 31.410 ;
        RECT 30.510 24.060 31.510 30.410 ;
        RECT 32.280 30.130 32.510 30.410 ;
        RECT 32.670 31.680 34.365 31.720 ;
        RECT 32.670 31.300 34.360 31.680 ;
        RECT 34.570 31.400 37.190 31.720 ;
        RECT 37.390 31.660 39.170 32.660 ;
        RECT 34.570 31.360 37.980 31.400 ;
        RECT 32.670 30.650 33.710 31.300 ;
        RECT 34.570 30.790 35.450 31.360 ;
        RECT 32.670 30.380 34.370 30.650 ;
        RECT 34.530 30.380 35.450 30.790 ;
        RECT 32.670 29.720 33.170 30.170 ;
        RECT 34.090 30.110 34.370 30.380 ;
        RECT 34.530 29.940 35.030 30.170 ;
        RECT 32.210 28.870 33.210 29.720 ;
        RECT 34.530 29.540 34.720 29.940 ;
        RECT 34.220 29.310 34.720 29.540 ;
        RECT 35.620 29.380 35.990 31.210 ;
        RECT 36.440 30.760 37.980 31.360 ;
        RECT 36.440 30.380 37.230 30.760 ;
        RECT 40.160 30.440 41.150 37.530 ;
        RECT 44.350 35.490 45.760 36.030 ;
        RECT 46.110 35.290 47.060 35.640 ;
        RECT 43.380 33.910 44.950 35.290 ;
        RECT 36.730 29.940 37.230 30.170 ;
        RECT 37.040 29.540 37.230 29.940 ;
        RECT 37.390 29.840 41.150 30.440 ;
        RECT 34.220 28.870 34.720 29.100 ;
        RECT 35.620 29.010 36.880 29.380 ;
        RECT 37.040 29.310 37.540 29.540 ;
        RECT 37.040 28.870 37.540 29.100 ;
        RECT 32.210 28.310 41.030 28.870 ;
        RECT 40.370 26.500 41.030 28.310 ;
        RECT 42.230 27.290 43.250 28.290 ;
        RECT 35.980 26.110 37.660 26.500 ;
        RECT 40.370 26.140 42.160 26.500 ;
        RECT 44.000 26.160 44.950 33.910 ;
        RECT 32.180 25.900 37.660 26.110 ;
        RECT 32.180 25.110 33.180 25.900 ;
        RECT 34.540 25.670 35.540 25.900 ;
        RECT 36.160 25.670 37.160 25.900 ;
        RECT 32.680 24.810 33.180 25.110 ;
        RECT 32.180 24.060 32.480 24.650 ;
        RECT 32.680 24.580 33.680 24.810 ;
        RECT 34.050 24.620 34.330 24.640 ;
        RECT 34.050 24.370 34.335 24.620 ;
        RECT 34.540 24.580 37.160 25.460 ;
        RECT 25.780 23.050 29.430 24.050 ;
        RECT 30.480 23.060 32.480 24.060 ;
        RECT 30.510 16.400 31.510 23.060 ;
        RECT 32.250 22.780 32.480 23.060 ;
        RECT 32.640 24.330 34.335 24.370 ;
        RECT 32.640 23.950 34.330 24.330 ;
        RECT 34.540 24.050 37.160 24.370 ;
        RECT 37.360 24.310 39.750 25.310 ;
        RECT 34.540 24.010 37.950 24.050 ;
        RECT 32.640 23.300 33.680 23.950 ;
        RECT 34.540 23.440 35.420 24.010 ;
        RECT 32.640 23.030 34.340 23.300 ;
        RECT 34.500 23.030 35.420 23.440 ;
        RECT 32.640 22.370 33.140 22.820 ;
        RECT 34.060 22.760 34.340 23.030 ;
        RECT 34.500 22.590 35.000 22.820 ;
        RECT 32.180 21.520 33.180 22.370 ;
        RECT 34.500 22.190 34.690 22.590 ;
        RECT 34.190 21.960 34.690 22.190 ;
        RECT 35.590 22.030 35.960 23.860 ;
        RECT 36.410 23.410 37.950 24.010 ;
        RECT 41.500 23.800 42.160 26.140 ;
        RECT 43.000 25.160 44.950 26.160 ;
        RECT 36.410 23.030 37.200 23.410 ;
        RECT 36.700 22.590 37.200 22.820 ;
        RECT 37.010 22.190 37.200 22.590 ;
        RECT 37.360 22.490 41.140 23.090 ;
        RECT 34.190 21.520 34.690 21.750 ;
        RECT 35.590 21.660 36.850 22.030 ;
        RECT 37.010 21.960 37.510 22.190 ;
        RECT 37.010 21.520 37.510 21.750 ;
        RECT 32.180 21.060 37.670 21.520 ;
        RECT 36.470 17.610 37.670 21.060 ;
        RECT 33.560 16.940 37.670 17.610 ;
        RECT 40.150 18.040 41.140 22.490 ;
        RECT 44.000 21.650 44.950 25.160 ;
        RECT 43.380 20.280 44.950 21.650 ;
        RECT 45.160 32.640 47.060 35.290 ;
        RECT 47.270 35.330 47.500 35.640 ;
        RECT 48.260 35.330 49.260 37.530 ;
        RECT 64.120 37.270 99.650 43.660 ;
        RECT 50.230 35.720 55.940 36.030 ;
        RECT 50.170 35.490 55.940 35.720 ;
        RECT 47.270 32.640 50.210 35.330 ;
        RECT 45.160 22.930 45.390 32.640 ;
        RECT 47.000 31.660 47.330 32.440 ;
        RECT 48.220 31.850 50.210 32.640 ;
        RECT 50.420 31.850 51.260 35.330 ;
        RECT 54.940 35.030 55.940 35.490 ;
        RECT 50.170 31.660 50.460 31.690 ;
        RECT 47.000 31.460 50.460 31.660 ;
        RECT 47.000 30.660 50.400 31.460 ;
        RECT 48.795 28.290 49.025 28.580 ;
        RECT 49.340 28.540 50.540 29.770 ;
        RECT 46.370 27.350 49.020 28.290 ;
        RECT 49.340 28.100 50.540 28.330 ;
        RECT 46.370 27.290 49.300 27.350 ;
        RECT 49.460 27.290 50.540 28.100 ;
        RECT 48.730 27.020 49.300 27.290 ;
        RECT 50.680 27.080 51.260 31.850 ;
        RECT 53.110 29.880 53.840 33.410 ;
        RECT 55.230 29.880 55.940 35.030 ;
        RECT 53.110 29.750 54.070 29.880 ;
        RECT 52.230 28.880 54.070 29.750 ;
        RECT 54.280 29.020 55.940 29.880 ;
        RECT 56.490 29.890 61.940 30.890 ;
        RECT 64.120 30.470 68.510 37.270 ;
        RECT 83.330 33.950 86.020 35.810 ;
        RECT 81.500 32.840 91.370 33.950 ;
        RECT 94.390 33.390 99.650 37.270 ;
        RECT 101.660 33.390 102.660 34.390 ;
        RECT 105.040 33.390 105.730 34.280 ;
        RECT 80.800 31.490 81.340 32.340 ;
        RECT 81.500 32.300 88.500 32.840 ;
        RECT 94.390 32.580 105.730 33.390 ;
        RECT 81.500 31.860 88.500 32.090 ;
        RECT 81.500 31.320 88.460 31.860 ;
        RECT 88.660 31.490 89.200 32.340 ;
        RECT 90.240 31.970 105.730 32.580 ;
        RECT 81.500 30.710 84.450 31.320 ;
        RECT 63.930 30.330 68.510 30.470 ;
        RECT 63.930 29.910 66.920 30.330 ;
        RECT 56.490 29.410 57.490 29.890 ;
        RECT 56.850 29.180 57.140 29.410 ;
        RECT 54.280 28.880 56.890 29.020 ;
        RECT 52.230 28.540 53.840 28.880 ;
        RECT 49.460 26.820 51.260 27.080 ;
        RECT 49.920 26.040 51.260 26.820 ;
        RECT 46.900 24.110 50.400 24.910 ;
        RECT 46.900 23.910 50.460 24.110 ;
        RECT 47.000 23.130 47.330 23.910 ;
        RECT 50.170 23.880 50.460 23.910 ;
        RECT 50.680 23.720 51.260 26.040 ;
        RECT 48.220 22.930 50.210 23.720 ;
        RECT 45.160 20.280 47.060 22.930 ;
        RECT 43.380 20.270 44.180 20.280 ;
        RECT 44.350 19.540 45.760 20.080 ;
        RECT 46.110 19.930 47.060 20.280 ;
        RECT 47.270 20.240 50.210 22.930 ;
        RECT 50.420 20.240 51.260 23.720 ;
        RECT 53.110 26.680 53.840 28.540 ;
        RECT 54.030 26.880 54.940 28.680 ;
        RECT 55.390 28.520 56.890 28.880 ;
        RECT 57.100 28.280 57.700 29.020 ;
        RECT 58.400 28.440 59.270 28.980 ;
        RECT 63.190 28.850 63.730 29.120 ;
        RECT 63.930 29.060 64.390 29.910 ;
        RECT 64.590 28.850 65.130 29.120 ;
        RECT 57.100 27.280 59.000 28.280 ;
        RECT 59.210 27.280 61.160 28.280 ;
        RECT 63.190 28.250 65.130 28.850 ;
        RECT 66.040 28.470 66.920 29.910 ;
        RECT 80.500 29.710 84.450 30.710 ;
        RECT 85.910 29.710 88.460 31.320 ;
        RECT 67.710 28.670 68.250 29.540 ;
        RECT 80.500 29.170 88.460 29.710 ;
        RECT 90.240 31.380 95.980 31.970 ;
        RECT 68.455 28.940 88.460 29.170 ;
        RECT 68.450 28.470 88.460 28.730 ;
        RECT 88.660 28.670 89.200 29.540 ;
        RECT 90.240 28.470 91.610 31.380 ;
        RECT 55.390 26.680 56.890 27.040 ;
        RECT 53.110 25.680 54.070 26.680 ;
        RECT 54.280 26.540 56.890 26.680 ;
        RECT 57.100 26.540 57.700 27.280 ;
        RECT 58.400 26.580 59.270 27.120 ;
        RECT 63.510 27.080 64.810 28.250 ;
        RECT 66.040 27.090 91.610 28.470 ;
        RECT 91.960 29.340 92.500 29.610 ;
        RECT 92.700 29.550 93.160 31.380 ;
        RECT 94.950 30.880 95.980 31.380 ;
        RECT 96.250 31.080 97.120 31.620 ;
        RECT 105.040 31.290 105.730 31.970 ;
        RECT 94.950 30.875 96.620 30.880 ;
        RECT 93.360 29.340 93.900 29.610 ;
        RECT 63.160 26.650 65.160 27.080 ;
        RECT 63.510 26.620 64.810 26.650 ;
        RECT 54.280 25.680 55.940 26.540 ;
        RECT 56.850 26.150 57.140 26.380 ;
        RECT 53.110 22.160 53.840 25.680 ;
        RECT 55.230 20.540 55.940 25.680 ;
        RECT 56.490 25.670 57.490 26.150 ;
        RECT 67.710 26.020 68.250 26.890 ;
        RECT 68.450 26.830 88.460 27.090 ;
        RECT 68.455 26.390 88.460 26.620 ;
        RECT 81.500 25.850 88.460 26.390 ;
        RECT 88.660 26.020 89.200 26.890 ;
        RECT 81.500 25.670 84.450 25.850 ;
        RECT 56.490 24.670 61.940 25.670 ;
        RECT 80.500 24.670 84.450 25.670 ;
        RECT 63.510 24.440 64.810 24.470 ;
        RECT 63.160 24.010 65.160 24.440 ;
        RECT 81.500 24.240 84.450 24.670 ;
        RECT 85.920 24.240 88.460 25.850 ;
        RECT 91.960 24.550 93.900 29.340 ;
        RECT 94.950 28.875 96.850 30.875 ;
        RECT 97.060 29.020 99.080 30.880 ;
        RECT 94.950 26.685 96.620 28.875 ;
        RECT 97.060 28.870 100.300 29.020 ;
        RECT 96.790 28.130 97.660 28.670 ;
        RECT 98.010 28.520 100.300 28.870 ;
        RECT 100.510 28.780 101.640 29.020 ;
        RECT 102.350 28.940 103.220 29.480 ;
        RECT 96.790 26.890 97.660 27.430 ;
        RECT 98.010 26.690 100.300 27.040 ;
        RECT 94.950 24.685 96.850 26.685 ;
        RECT 97.060 26.540 100.300 26.690 ;
        RECT 100.510 26.780 102.410 28.780 ;
        RECT 102.620 26.780 104.110 28.780 ;
        RECT 100.510 26.540 101.640 26.780 ;
        RECT 94.950 24.680 96.620 24.685 ;
        RECT 97.060 24.680 99.080 26.540 ;
        RECT 100.240 25.380 101.240 26.380 ;
        RECT 102.350 26.080 103.220 26.620 ;
        RECT 103.450 25.840 104.110 26.780 ;
        RECT 104.460 26.820 106.310 30.760 ;
        RECT 104.460 26.570 105.000 26.820 ;
        RECT 105.160 25.840 105.610 26.610 ;
        RECT 105.770 26.570 106.310 26.820 ;
        RECT 63.510 22.510 64.810 24.010 ;
        RECT 80.800 23.220 81.340 24.070 ;
        RECT 81.500 23.700 88.460 24.240 ;
        RECT 81.500 23.470 88.500 23.700 ;
        RECT 81.500 22.840 88.500 23.260 ;
        RECT 88.660 23.220 89.200 24.070 ;
        RECT 92.590 22.840 93.280 24.020 ;
        RECT 96.250 23.940 97.120 24.480 ;
        RECT 58.510 22.490 66.610 22.510 ;
        RECT 81.500 22.490 93.490 22.840 ;
        RECT 58.510 22.440 93.490 22.490 ;
        RECT 103.450 22.440 105.610 25.840 ;
        RECT 108.610 25.830 109.610 48.790 ;
        RECT 108.610 24.830 110.610 25.830 ;
        RECT 58.510 20.930 105.610 22.440 ;
        RECT 47.270 19.930 47.500 20.240 ;
        RECT 48.260 18.040 49.260 20.240 ;
        RECT 54.940 20.080 55.940 20.540 ;
        RECT 50.170 19.850 55.940 20.080 ;
        RECT 101.630 19.930 102.630 20.930 ;
        RECT 50.230 19.540 55.940 19.850 ;
        RECT 40.150 17.040 49.260 18.040 ;
        RECT 33.560 16.610 34.560 16.940 ;
        RECT 35.590 16.870 37.670 16.940 ;
        RECT 34.720 16.400 35.290 16.670 ;
        RECT 35.590 16.610 37.830 16.870 ;
        RECT 30.510 15.590 34.560 16.400 ;
        RECT 34.720 16.340 37.830 16.400 ;
        RECT 35.000 15.590 37.830 16.340 ;
        RECT 30.510 15.400 34.680 15.590 ;
        RECT 35.000 15.400 37.950 15.590 ;
        RECT 33.480 15.360 34.680 15.400 ;
        RECT 33.680 14.850 34.680 15.150 ;
        RECT 34.995 15.110 35.225 15.400 ;
        RECT 36.750 15.360 37.950 15.400 ;
        RECT 35.440 14.850 37.950 15.150 ;
        RECT 33.680 14.390 37.950 14.850 ;
      LAYER met2 ;
        RECT 78.020 201.190 79.190 203.090 ;
        RECT 13.420 200.190 79.190 201.190 ;
        RECT 95.960 200.960 96.960 200.970 ;
        RECT 80.460 200.010 96.960 200.960 ;
        RECT 13.420 195.990 79.380 196.990 ;
        RECT 13.420 193.820 79.380 194.820 ;
        RECT 14.960 192.650 15.960 193.650 ;
        RECT 20.460 192.650 21.460 193.650 ;
        RECT 25.960 192.650 26.960 193.650 ;
        RECT 31.460 192.650 32.460 193.650 ;
        RECT 36.960 192.650 37.960 193.650 ;
        RECT 42.460 192.650 43.460 193.650 ;
        RECT 47.960 192.650 48.960 193.650 ;
        RECT 53.460 192.650 54.460 193.650 ;
        RECT 58.960 192.650 59.960 193.650 ;
        RECT 64.460 192.650 65.460 193.650 ;
        RECT 69.960 192.650 70.960 193.650 ;
        RECT 75.460 192.650 76.460 193.650 ;
        RECT 80.460 188.430 81.600 200.010 ;
        RECT 82.300 198.580 95.450 199.580 ;
        RECT 94.450 197.400 95.450 198.580 ;
        RECT 95.960 197.840 96.960 200.010 ;
        RECT 97.130 197.400 97.770 198.940 ;
        RECT 94.450 196.400 97.770 197.400 ;
        RECT 82.300 193.510 95.450 194.510 ;
        RECT 94.450 192.330 95.450 193.510 ;
        RECT 95.960 192.770 96.960 196.400 ;
        RECT 97.130 192.330 97.770 193.870 ;
        RECT 94.450 191.330 97.770 192.330 ;
        RECT 82.300 188.440 95.450 189.440 ;
        RECT 75.500 187.250 81.600 188.430 ;
        RECT 94.450 187.260 95.450 188.440 ;
        RECT 95.960 187.700 96.960 191.330 ;
        RECT 97.130 187.260 97.770 188.800 ;
        RECT 63.190 179.000 64.090 185.750 ;
        RECT 64.870 182.130 71.110 183.130 ;
        RECT 63.190 178.000 69.580 179.000 ;
        RECT 36.780 175.800 61.700 176.800 ;
        RECT 63.190 175.830 64.090 178.000 ;
        RECT 70.010 176.780 71.110 182.130 ;
        RECT 75.500 178.560 76.500 187.250 ;
        RECT 94.450 186.260 97.770 187.260 ;
        RECT 82.300 183.370 95.450 184.370 ;
        RECT 94.450 182.190 95.450 183.370 ;
        RECT 95.960 182.630 96.960 186.260 ;
        RECT 97.130 182.190 97.770 183.730 ;
        RECT 94.450 181.190 97.770 182.190 ;
        RECT 75.500 177.560 96.960 178.560 ;
        RECT 97.130 177.880 97.770 181.190 ;
        RECT 36.780 172.870 37.780 175.800 ;
        RECT 55.100 172.890 56.100 174.310 ;
        RECT 56.700 173.320 57.700 174.320 ;
        RECT 58.300 174.310 59.300 175.310 ;
        RECT 60.700 174.760 61.700 175.800 ;
        RECT 75.500 174.760 76.500 177.560 ;
        RECT 98.430 176.020 99.430 200.670 ;
        RECT 100.140 176.020 101.140 200.670 ;
        RECT 103.550 196.490 115.880 197.490 ;
        RECT 60.700 173.760 76.500 174.760 ;
        RECT 36.780 171.870 40.460 172.870 ;
        RECT 36.780 166.910 37.780 171.870 ;
        RECT 38.360 169.760 39.360 171.330 ;
        RECT 52.670 171.300 62.770 172.300 ;
        RECT 38.360 169.060 53.670 169.760 ;
        RECT 58.300 169.680 59.300 171.100 ;
        RECT 36.780 165.910 40.460 166.910 ;
        RECT 52.670 166.570 53.670 169.060 ;
        RECT 55.100 167.990 56.100 169.410 ;
        RECT 56.700 166.960 60.560 167.960 ;
        RECT 52.670 165.970 60.360 166.570 ;
        RECT 36.780 159.560 37.780 165.910 ;
        RECT 59.690 165.570 60.360 165.970 ;
        RECT 61.770 165.720 62.770 171.300 ;
        RECT 78.100 167.710 78.610 168.720 ;
        RECT 68.050 166.600 81.650 167.710 ;
        RECT 103.550 166.840 104.550 196.490 ;
        RECT 38.360 162.410 39.360 165.370 ;
        RECT 58.300 163.690 59.300 165.110 ;
        RECT 59.690 164.910 72.090 165.570 ;
        RECT 77.910 163.470 78.910 166.220 ;
        RECT 80.690 165.670 81.650 166.600 ;
        RECT 80.680 164.930 81.650 165.670 ;
        RECT 40.480 163.020 78.910 163.470 ;
        RECT 94.410 162.660 95.410 166.710 ;
        RECT 99.450 165.840 104.550 166.840 ;
        RECT 105.950 183.950 115.880 184.950 ;
        RECT 38.360 161.710 53.670 162.410 ;
        RECT 61.770 162.060 95.410 162.660 ;
        RECT 36.780 158.560 40.460 159.560 ;
        RECT 52.670 159.220 53.670 161.710 ;
        RECT 55.100 160.640 56.100 162.060 ;
        RECT 56.700 159.610 60.560 160.610 ;
        RECT 52.670 158.620 60.360 159.220 ;
        RECT 36.780 152.210 37.780 158.560 ;
        RECT 59.690 158.220 60.360 158.620 ;
        RECT 61.770 158.370 62.770 162.060 ;
        RECT 78.100 160.360 78.610 161.370 ;
        RECT 68.050 159.250 81.650 160.360 ;
        RECT 105.950 159.490 106.950 183.950 ;
        RECT 112.570 178.710 114.740 182.780 ;
        RECT 131.540 181.390 134.000 187.800 ;
        RECT 38.360 155.060 39.360 158.020 ;
        RECT 58.300 156.340 59.300 157.760 ;
        RECT 59.690 157.560 72.090 158.220 ;
        RECT 77.910 156.120 78.910 158.870 ;
        RECT 80.690 158.320 81.650 159.250 ;
        RECT 80.680 157.580 81.650 158.320 ;
        RECT 40.480 155.670 78.910 156.120 ;
        RECT 94.410 155.330 95.410 159.360 ;
        RECT 99.450 158.490 106.950 159.490 ;
        RECT 108.020 171.410 115.880 172.410 ;
        RECT 38.360 154.360 53.670 155.060 ;
        RECT 61.770 154.730 95.410 155.330 ;
        RECT 36.780 151.210 40.460 152.210 ;
        RECT 52.670 151.870 53.670 154.360 ;
        RECT 55.100 153.290 56.100 154.710 ;
        RECT 56.700 152.260 60.560 153.260 ;
        RECT 52.670 151.270 60.360 151.870 ;
        RECT 36.780 144.860 37.780 151.210 ;
        RECT 59.690 150.870 60.360 151.270 ;
        RECT 61.770 151.020 62.770 154.730 ;
        RECT 78.100 153.010 78.610 154.020 ;
        RECT 68.050 151.900 81.650 153.010 ;
        RECT 108.020 152.140 109.020 171.410 ;
        RECT 38.360 147.710 39.360 150.670 ;
        RECT 58.300 148.990 59.300 150.410 ;
        RECT 59.690 150.210 72.090 150.870 ;
        RECT 77.910 148.770 78.910 151.520 ;
        RECT 80.690 150.970 81.650 151.900 ;
        RECT 80.680 150.230 81.650 150.970 ;
        RECT 40.480 148.320 78.910 148.770 ;
        RECT 94.410 147.980 95.410 152.010 ;
        RECT 99.450 151.140 109.020 152.140 ;
        RECT 109.870 158.870 115.880 159.870 ;
        RECT 38.360 147.010 53.670 147.710 ;
        RECT 61.770 147.380 95.410 147.980 ;
        RECT 36.780 143.860 40.460 144.860 ;
        RECT 52.670 144.520 53.670 147.010 ;
        RECT 55.110 145.940 56.110 147.360 ;
        RECT 56.700 144.910 60.560 145.910 ;
        RECT 52.670 143.920 60.360 144.520 ;
        RECT 36.780 137.510 37.780 143.860 ;
        RECT 59.690 143.520 60.360 143.920 ;
        RECT 61.770 143.670 62.770 147.380 ;
        RECT 78.100 145.660 78.610 146.670 ;
        RECT 68.050 144.550 81.650 145.660 ;
        RECT 109.870 144.790 110.870 158.870 ;
        RECT 112.570 153.700 114.740 157.770 ;
        RECT 131.540 157.000 134.000 163.410 ;
        RECT 38.360 140.360 39.360 143.320 ;
        RECT 58.310 141.640 59.310 143.060 ;
        RECT 59.690 142.860 72.090 143.520 ;
        RECT 77.910 141.420 78.910 144.170 ;
        RECT 80.690 143.620 81.650 144.550 ;
        RECT 80.680 142.880 81.650 143.620 ;
        RECT 40.480 140.970 78.910 141.420 ;
        RECT 94.410 140.630 95.410 144.660 ;
        RECT 99.450 143.790 110.870 144.790 ;
        RECT 111.830 146.330 115.880 147.330 ;
        RECT 38.360 139.660 53.670 140.360 ;
        RECT 61.770 140.030 95.410 140.630 ;
        RECT 36.780 136.510 40.460 137.510 ;
        RECT 52.670 137.170 53.670 139.660 ;
        RECT 55.100 138.590 56.100 140.010 ;
        RECT 56.700 137.560 60.560 138.560 ;
        RECT 52.670 136.570 60.360 137.170 ;
        RECT 36.780 133.300 37.780 136.510 ;
        RECT 59.690 136.170 60.360 136.570 ;
        RECT 61.770 136.320 62.770 140.030 ;
        RECT 78.100 138.310 78.610 139.320 ;
        RECT 68.050 137.200 81.650 138.310 ;
        RECT 111.830 137.440 112.830 146.330 ;
        RECT 35.780 132.300 37.780 133.300 ;
        RECT 38.360 133.010 39.360 135.970 ;
        RECT 58.300 134.290 59.300 135.710 ;
        RECT 59.690 135.510 72.090 136.170 ;
        RECT 77.910 134.070 78.910 136.820 ;
        RECT 80.690 136.270 81.650 137.200 ;
        RECT 80.680 135.530 81.650 136.270 ;
        RECT 40.480 133.620 78.910 134.070 ;
        RECT 94.410 133.280 95.410 137.310 ;
        RECT 99.450 136.440 112.830 137.440 ;
        RECT 38.360 132.310 53.670 133.010 ;
        RECT 61.770 132.680 95.410 133.280 ;
        RECT 109.760 133.790 115.880 134.790 ;
        RECT 36.780 130.160 37.780 132.300 ;
        RECT 36.780 129.160 40.460 130.160 ;
        RECT 52.670 129.820 53.670 132.310 ;
        RECT 55.100 131.240 56.100 132.660 ;
        RECT 56.700 130.210 60.560 131.210 ;
        RECT 52.670 129.220 60.360 129.820 ;
        RECT 36.780 122.810 37.780 129.160 ;
        RECT 59.690 128.820 60.360 129.220 ;
        RECT 61.770 128.970 62.770 132.680 ;
        RECT 78.100 130.960 78.610 131.970 ;
        RECT 68.050 129.850 81.650 130.960 ;
        RECT 109.760 130.090 110.760 133.790 ;
        RECT 38.360 125.660 39.360 128.620 ;
        RECT 58.300 126.940 59.300 128.360 ;
        RECT 59.690 128.160 72.090 128.820 ;
        RECT 77.910 126.720 78.910 129.470 ;
        RECT 80.690 128.920 81.650 129.850 ;
        RECT 80.680 128.180 81.650 128.920 ;
        RECT 40.480 126.270 78.910 126.720 ;
        RECT 94.410 125.930 95.410 129.960 ;
        RECT 99.450 129.090 110.760 130.090 ;
        RECT 112.570 128.030 114.740 132.100 ;
        RECT 131.540 129.710 134.000 136.120 ;
        RECT 38.360 124.960 53.670 125.660 ;
        RECT 61.770 125.330 95.410 125.930 ;
        RECT 36.780 121.810 40.460 122.810 ;
        RECT 52.670 122.470 53.670 124.960 ;
        RECT 55.100 123.890 56.100 125.310 ;
        RECT 56.700 122.860 60.560 123.860 ;
        RECT 52.670 121.870 60.360 122.470 ;
        RECT 36.780 115.460 37.780 121.810 ;
        RECT 59.690 121.470 60.360 121.870 ;
        RECT 61.770 121.620 62.770 125.330 ;
        RECT 78.100 123.610 78.610 124.620 ;
        RECT 68.050 122.500 81.650 123.610 ;
        RECT 38.360 118.310 39.360 121.270 ;
        RECT 58.300 119.590 59.300 121.010 ;
        RECT 59.690 120.810 72.090 121.470 ;
        RECT 77.910 119.370 78.910 122.120 ;
        RECT 80.690 121.570 81.650 122.500 ;
        RECT 80.680 120.830 81.650 121.570 ;
        RECT 40.480 118.920 78.910 119.370 ;
        RECT 94.410 118.580 95.410 122.610 ;
        RECT 99.450 122.250 109.780 122.740 ;
        RECT 99.450 121.740 115.880 122.250 ;
        RECT 108.780 121.250 115.880 121.740 ;
        RECT 38.360 117.610 53.670 118.310 ;
        RECT 61.770 117.980 95.410 118.580 ;
        RECT 36.780 114.460 40.460 115.460 ;
        RECT 52.670 115.120 53.670 117.610 ;
        RECT 55.100 116.540 56.100 117.960 ;
        RECT 56.700 115.510 60.560 116.510 ;
        RECT 52.670 114.520 60.360 115.120 ;
        RECT 36.780 108.110 37.780 114.460 ;
        RECT 59.690 114.120 60.360 114.520 ;
        RECT 61.770 114.270 62.770 117.980 ;
        RECT 78.100 116.260 78.610 117.270 ;
        RECT 68.050 115.150 81.650 116.260 ;
        RECT 38.360 110.960 39.360 113.920 ;
        RECT 58.300 112.240 59.300 113.660 ;
        RECT 59.690 113.460 72.090 114.120 ;
        RECT 77.910 112.020 78.910 114.770 ;
        RECT 80.690 114.220 81.650 115.150 ;
        RECT 80.680 113.480 81.650 114.220 ;
        RECT 40.480 111.570 78.910 112.020 ;
        RECT 94.410 111.230 95.410 115.260 ;
        RECT 99.450 114.390 110.430 115.390 ;
        RECT 38.360 110.260 53.670 110.960 ;
        RECT 61.770 110.630 95.410 111.230 ;
        RECT 36.780 107.110 40.460 108.110 ;
        RECT 52.670 107.770 53.670 110.260 ;
        RECT 55.100 109.190 56.100 110.610 ;
        RECT 56.700 108.160 60.560 109.160 ;
        RECT 52.670 107.170 60.360 107.770 ;
        RECT 36.780 100.760 37.780 107.110 ;
        RECT 59.690 106.770 60.360 107.170 ;
        RECT 61.770 106.920 62.770 110.630 ;
        RECT 78.100 108.910 78.610 109.920 ;
        RECT 109.430 109.710 110.430 114.390 ;
        RECT 68.050 107.800 81.650 108.910 ;
        RECT 109.430 108.710 115.880 109.710 ;
        RECT 38.360 103.610 39.360 106.570 ;
        RECT 58.300 104.890 59.300 106.310 ;
        RECT 59.690 106.110 72.090 106.770 ;
        RECT 77.910 104.670 78.910 107.420 ;
        RECT 80.690 106.870 81.650 107.800 ;
        RECT 80.680 106.130 81.650 106.870 ;
        RECT 40.480 104.220 78.910 104.670 ;
        RECT 94.410 103.880 95.410 107.910 ;
        RECT 99.450 107.040 108.420 108.040 ;
        RECT 38.360 102.910 53.670 103.610 ;
        RECT 61.770 103.280 95.410 103.880 ;
        RECT 36.780 99.760 40.460 100.760 ;
        RECT 52.670 100.420 53.670 102.910 ;
        RECT 55.100 101.840 56.100 103.260 ;
        RECT 56.700 100.810 60.560 101.810 ;
        RECT 52.670 99.820 60.360 100.420 ;
        RECT 36.780 93.410 37.780 99.760 ;
        RECT 59.690 99.420 60.360 99.820 ;
        RECT 61.770 99.570 62.770 103.280 ;
        RECT 78.100 101.560 78.610 102.570 ;
        RECT 68.050 100.450 81.650 101.560 ;
        RECT 38.360 96.260 39.360 99.220 ;
        RECT 58.300 97.540 59.300 98.960 ;
        RECT 59.690 98.760 72.090 99.420 ;
        RECT 77.910 97.320 78.910 100.070 ;
        RECT 80.690 99.520 81.650 100.450 ;
        RECT 80.680 98.780 81.650 99.520 ;
        RECT 40.480 96.870 78.910 97.320 ;
        RECT 94.410 96.530 95.410 100.560 ;
        RECT 99.450 99.690 106.870 100.690 ;
        RECT 38.360 95.560 53.670 96.260 ;
        RECT 61.770 95.930 95.410 96.530 ;
        RECT 36.780 92.410 40.460 93.410 ;
        RECT 52.670 93.070 53.670 95.560 ;
        RECT 55.100 94.490 56.100 95.910 ;
        RECT 56.700 93.460 60.560 94.460 ;
        RECT 52.670 92.470 60.410 93.070 ;
        RECT 36.780 84.680 37.780 92.410 ;
        RECT 59.690 92.070 60.410 92.470 ;
        RECT 61.770 92.220 62.770 95.930 ;
        RECT 78.100 94.210 78.610 95.220 ;
        RECT 68.050 93.100 81.650 94.210 ;
        RECT 38.360 89.190 39.360 91.870 ;
        RECT 58.300 90.190 59.300 91.610 ;
        RECT 59.690 91.410 72.090 92.070 ;
        RECT 77.910 89.970 78.910 92.720 ;
        RECT 80.690 92.170 81.650 93.100 ;
        RECT 80.680 91.430 81.650 92.170 ;
        RECT 40.480 89.520 78.910 89.970 ;
        RECT 38.360 88.390 50.790 89.190 ;
        RECT 94.410 89.180 95.410 93.210 ;
        RECT 99.450 92.340 104.920 93.340 ;
        RECT 49.290 85.490 50.790 88.390 ;
        RECT 55.100 87.190 56.100 88.610 ;
        RECT 61.760 88.580 95.410 89.180 ;
        RECT 56.700 86.100 60.560 87.100 ;
        RECT 49.290 84.890 60.430 85.490 ;
        RECT 36.780 83.680 39.950 84.680 ;
        RECT 59.750 84.650 60.430 84.890 ;
        RECT 61.760 84.860 62.760 88.580 ;
        RECT 78.095 86.855 78.605 87.865 ;
        RECT 68.045 85.745 81.645 86.855 ;
        RECT 80.685 84.815 81.645 85.745 ;
        RECT 99.440 84.980 103.400 85.980 ;
        RECT 36.780 80.230 37.780 83.680 ;
        RECT 58.300 83.220 59.300 84.640 ;
        RECT 59.750 84.060 72.080 84.650 ;
        RECT 80.675 84.075 81.645 84.815 ;
        RECT 55.100 81.770 56.100 82.770 ;
        RECT 56.700 81.770 57.700 82.770 ;
        RECT 58.300 81.770 59.300 82.770 ;
        RECT 29.190 78.410 37.780 80.230 ;
        RECT 29.200 39.610 30.910 78.410 ;
        RECT 97.020 77.090 101.430 80.960 ;
        RECT 45.860 73.660 46.400 75.140 ;
        RECT 54.720 73.660 55.260 75.140 ;
        RECT 36.690 72.660 60.960 73.660 ;
        RECT 39.470 71.440 40.060 72.660 ;
        RECT 60.370 71.440 60.960 72.660 ;
        RECT 38.020 61.890 45.710 62.930 ;
        RECT 33.090 36.110 34.090 59.100 ;
        RECT 36.530 56.910 37.530 59.990 ;
        RECT 38.020 57.140 38.790 61.890 ;
        RECT 44.540 60.020 45.710 61.890 ;
        RECT 102.400 62.690 103.400 84.980 ;
        RECT 103.920 72.090 104.920 92.340 ;
        RECT 105.870 84.630 106.870 99.690 ;
        RECT 107.420 97.170 108.420 107.040 ;
        RECT 131.540 107.020 134.000 113.430 ;
        RECT 112.570 102.890 114.740 106.500 ;
        RECT 107.420 96.170 115.880 97.170 ;
        RECT 105.870 83.630 115.880 84.630 ;
        RECT 131.540 82.130 134.000 88.540 ;
        RECT 112.570 77.090 114.440 80.960 ;
        RECT 103.920 71.090 115.880 72.090 ;
        RECT 102.400 61.690 107.630 62.690 ;
        RECT 43.820 58.770 58.470 60.020 ;
        RECT 106.630 59.550 107.630 61.690 ;
        RECT 106.630 58.550 115.890 59.550 ;
        RECT 62.630 56.910 66.980 58.050 ;
        RECT 87.600 57.610 103.260 58.480 ;
        RECT 36.530 55.910 66.980 56.910 ;
        RECT 68.010 56.620 97.180 57.220 ;
        RECT 68.010 56.350 68.550 56.620 ;
        RECT 88.910 56.350 97.180 56.620 ;
        RECT 37.730 54.870 46.000 55.450 ;
        RECT 37.730 49.350 38.600 54.870 ;
        RECT 40.510 50.460 41.110 54.660 ;
        RECT 41.280 49.560 41.880 53.760 ;
        RECT 45.160 52.610 46.000 54.870 ;
        RECT 53.720 54.120 81.010 55.120 ;
        RECT 55.960 52.610 57.370 53.850 ;
        RECT 77.940 53.320 78.480 53.860 ;
        RECT 87.750 53.320 88.340 53.860 ;
        RECT 45.160 51.610 47.030 52.610 ;
        RECT 47.470 51.610 59.740 52.610 ;
        RECT 45.160 49.350 46.000 51.610 ;
        RECT 55.960 50.360 57.370 51.610 ;
        RECT 63.280 50.880 88.340 53.320 ;
        RECT 94.700 52.280 95.410 54.350 ;
        RECT 96.080 52.850 97.180 56.350 ;
        RECT 100.540 53.160 101.410 53.850 ;
        RECT 91.740 51.920 95.410 52.280 ;
        RECT 77.940 50.340 78.480 50.880 ;
        RECT 87.750 50.340 88.340 50.880 ;
        RECT 37.730 48.770 46.000 49.350 ;
        RECT 53.720 49.080 81.010 50.080 ;
        RECT 94.700 49.850 95.410 51.920 ;
        RECT 100.980 52.510 101.410 53.160 ;
        RECT 100.980 51.700 105.140 52.510 ;
        RECT 36.530 47.310 67.420 48.310 ;
        RECT 96.080 47.850 97.180 51.370 ;
        RECT 100.980 51.050 101.410 51.700 ;
        RECT 100.540 50.360 101.410 51.050 ;
        RECT 98.430 49.790 99.430 50.170 ;
        RECT 98.430 48.790 109.610 49.790 ;
        RECT 68.010 47.580 68.550 47.850 ;
        RECT 88.910 47.580 97.180 47.850 ;
        RECT 68.010 46.980 97.180 47.580 ;
        RECT 34.530 41.790 36.430 42.770 ;
        RECT 35.430 38.750 36.430 41.790 ;
        RECT 37.690 42.330 38.790 44.610 ;
        RECT 43.820 44.210 58.470 45.450 ;
        RECT 43.820 44.200 68.510 44.210 ;
        RECT 44.540 42.330 45.710 44.200 ;
        RECT 37.690 41.290 45.710 42.330 ;
        RECT 35.430 37.790 39.760 38.750 ;
        RECT 35.630 33.810 37.580 33.820 ;
        RECT 35.630 33.250 38.420 33.810 ;
        RECT 28.430 30.400 37.230 31.400 ;
        RECT 37.470 26.500 38.420 33.250 ;
        RECT 35.980 25.900 38.420 26.500 ;
        RECT 37.470 24.080 38.420 25.900 ;
        RECT 38.750 24.310 39.750 37.790 ;
        RECT 41.350 28.290 42.690 41.020 ;
        RECT 55.930 40.140 68.510 44.200 ;
        RECT 48.860 37.530 68.510 40.140 ;
        RECT 98.190 39.800 100.770 48.560 ;
        RECT 83.330 37.620 100.770 39.800 ;
        RECT 43.380 36.630 53.840 37.530 ;
        RECT 43.380 33.910 44.180 36.630 ;
        RECT 44.350 28.290 45.760 36.030 ;
        RECT 41.350 27.290 47.700 28.290 ;
        RECT 40.200 25.070 44.170 26.210 ;
        RECT 40.200 24.080 41.340 25.070 ;
        RECT 28.430 23.050 37.200 24.050 ;
        RECT 37.470 23.020 41.340 24.080 ;
        RECT 37.470 22.700 38.420 23.020 ;
        RECT 34.470 22.070 38.420 22.700 ;
        RECT 34.470 14.390 35.450 22.070 ;
        RECT 41.500 21.520 42.160 24.700 ;
        RECT 36.470 20.770 42.160 21.520 ;
        RECT 40.110 20.310 42.160 20.770 ;
        RECT 43.380 21.650 44.170 25.070 ;
        RECT 40.110 16.910 41.030 20.310 ;
        RECT 43.380 18.940 44.180 21.650 ;
        RECT 44.350 19.540 45.760 27.290 ;
        RECT 48.220 22.660 48.920 31.660 ;
        RECT 49.210 23.910 49.910 32.910 ;
        RECT 53.110 32.410 53.840 36.630 ;
        RECT 83.330 33.950 86.020 37.620 ;
        RECT 87.680 34.200 99.080 36.200 ;
        RECT 87.680 32.900 89.200 34.200 ;
        RECT 80.800 32.300 89.200 32.900 ;
        RECT 50.680 30.620 60.160 31.620 ;
        RECT 80.800 31.490 81.390 32.300 ;
        RECT 88.610 31.490 89.200 32.300 ;
        RECT 50.110 28.540 52.760 29.750 ;
        RECT 50.130 28.280 54.030 28.290 ;
        RECT 58.400 28.280 59.270 28.980 ;
        RECT 50.130 27.280 59.270 28.280 ;
        RECT 58.400 26.580 59.270 27.280 ;
        RECT 59.500 24.940 60.160 30.620 ;
        RECT 60.560 29.890 84.450 30.890 ;
        RECT 67.710 28.470 68.250 29.540 ;
        RECT 88.660 28.470 89.200 29.540 ;
        RECT 63.510 27.090 89.200 28.470 ;
        RECT 67.710 26.020 68.250 27.090 ;
        RECT 88.660 26.020 89.200 27.090 ;
        RECT 50.680 23.940 60.160 24.940 ;
        RECT 60.560 24.670 84.450 25.670 ;
        RECT 53.110 18.940 53.840 23.160 ;
        RECT 43.380 18.040 53.840 18.940 ;
        RECT 43.380 18.030 44.180 18.040 ;
        RECT 58.510 16.910 60.160 23.940 ;
        RECT 80.800 23.260 81.390 24.070 ;
        RECT 88.610 23.260 89.200 24.070 ;
        RECT 80.800 22.660 89.200 23.260 ;
        RECT 73.170 20.930 78.340 22.490 ;
        RECT 87.680 21.360 89.200 22.660 ;
        RECT 89.870 21.830 91.370 33.950 ;
        RECT 96.250 28.670 96.790 31.620 ;
        RECT 91.960 26.890 97.660 28.670 ;
        RECT 98.010 28.520 99.080 34.200 ;
        RECT 102.620 28.120 103.220 29.480 ;
        RECT 102.620 27.420 106.310 28.120 ;
        RECT 96.250 23.940 96.790 26.890 ;
        RECT 98.010 21.360 99.080 27.040 ;
        RECT 100.240 25.830 101.240 26.380 ;
        RECT 102.620 26.080 103.220 27.420 ;
        RECT 100.240 24.830 109.610 25.830 ;
        RECT 87.680 19.360 99.080 21.360 ;
        RECT 40.110 15.250 60.160 16.910 ;
      LAYER met3 ;
        RECT 14.960 177.250 15.960 193.650 ;
        RECT 20.460 178.650 21.460 193.650 ;
        RECT 25.960 180.050 26.960 193.650 ;
        RECT 31.460 181.450 32.460 193.650 ;
        RECT 36.960 182.850 37.960 193.650 ;
        RECT 42.460 184.250 43.460 193.650 ;
        RECT 47.960 185.650 48.960 193.650 ;
        RECT 53.460 187.050 54.460 193.650 ;
        RECT 58.960 188.450 59.960 193.650 ;
        RECT 64.460 189.850 65.460 193.640 ;
        RECT 69.960 191.250 70.960 193.650 ;
        RECT 75.460 192.650 76.460 193.650 ;
        RECT 75.460 191.650 85.180 192.650 ;
        RECT 69.960 190.250 83.180 191.250 ;
        RECT 64.460 188.850 81.180 189.850 ;
        RECT 58.960 187.450 79.180 188.450 ;
        RECT 53.460 186.050 77.180 187.050 ;
        RECT 47.960 184.650 75.180 185.650 ;
        RECT 42.460 183.250 73.180 184.250 ;
        RECT 36.960 181.850 71.180 182.850 ;
        RECT 31.460 180.450 69.180 181.450 ;
        RECT 25.960 179.050 67.180 180.050 ;
        RECT 20.460 177.650 65.180 178.650 ;
        RECT 14.960 176.250 63.180 177.250 ;
        RECT 55.100 148.000 56.100 174.310 ;
        RECT 55.100 141.150 56.110 148.000 ;
        RECT 55.100 73.120 56.100 141.150 ;
        RECT 56.700 81.770 57.700 174.320 ;
        RECT 58.300 148.000 59.300 175.310 ;
        RECT 58.300 141.150 59.310 148.000 ;
        RECT 58.300 80.960 59.300 141.150 ;
        RECT 61.680 85.990 63.180 176.250 ;
        RECT 63.680 93.340 65.180 177.650 ;
        RECT 65.680 100.690 67.180 179.050 ;
        RECT 67.680 108.040 69.180 180.450 ;
        RECT 69.680 115.390 71.180 181.850 ;
        RECT 71.680 122.740 73.180 183.250 ;
        RECT 73.680 130.090 75.180 184.650 ;
        RECT 75.680 137.440 77.180 186.050 ;
        RECT 77.680 144.790 79.180 187.450 ;
        RECT 79.680 152.140 81.180 188.850 ;
        RECT 81.680 159.490 83.180 190.250 ;
        RECT 83.680 166.840 85.180 191.650 ;
        RECT 106.540 178.710 114.740 182.780 ;
        RECT 131.540 181.390 143.590 187.800 ;
        RECT 83.680 165.840 100.450 166.840 ;
        RECT 81.680 158.500 100.450 159.490 ;
        RECT 83.570 158.490 100.450 158.500 ;
        RECT 106.540 157.770 111.760 178.710 ;
        RECT 135.510 163.410 143.590 181.390 ;
        RECT 106.540 153.700 114.740 157.770 ;
        RECT 131.540 157.000 143.590 163.410 ;
        RECT 79.680 151.140 100.450 152.140 ;
        RECT 77.680 143.790 100.450 144.790 ;
        RECT 75.680 136.440 100.450 137.440 ;
        RECT 106.540 132.100 111.760 153.700 ;
        RECT 135.510 136.120 143.590 157.000 ;
        RECT 73.680 129.090 100.450 130.090 ;
        RECT 106.540 128.030 114.740 132.100 ;
        RECT 131.540 129.710 143.590 136.120 ;
        RECT 71.680 121.740 100.450 122.740 ;
        RECT 69.680 114.390 100.450 115.390 ;
        RECT 67.680 107.040 100.450 108.040 ;
        RECT 106.540 106.500 111.760 128.030 ;
        RECT 135.510 113.430 143.590 129.710 ;
        RECT 131.540 107.020 143.590 113.430 ;
        RECT 106.540 102.890 114.740 106.500 ;
        RECT 65.680 99.690 100.450 100.690 ;
        RECT 63.680 92.340 100.450 93.340 ;
        RECT 61.680 84.990 100.450 85.990 ;
        RECT 106.540 80.960 111.760 102.890 ;
        RECT 135.510 88.540 143.590 107.020 ;
        RECT 131.540 82.130 143.590 88.540 ;
        RECT 58.300 77.090 114.440 80.960 ;
        RECT 55.100 65.060 57.100 73.120 ;
        RECT 62.600 65.060 68.510 65.070 ;
        RECT 55.100 60.430 68.510 65.060 ;
        RECT 62.600 17.090 68.510 60.430 ;
        RECT 73.170 20.930 78.340 77.090 ;
        RECT 135.510 17.090 143.590 82.130 ;
        RECT 62.600 13.330 143.590 17.090 ;
  END
END tt_um_ahmed_nematallah_12_bit_adc
END LIBRARY

